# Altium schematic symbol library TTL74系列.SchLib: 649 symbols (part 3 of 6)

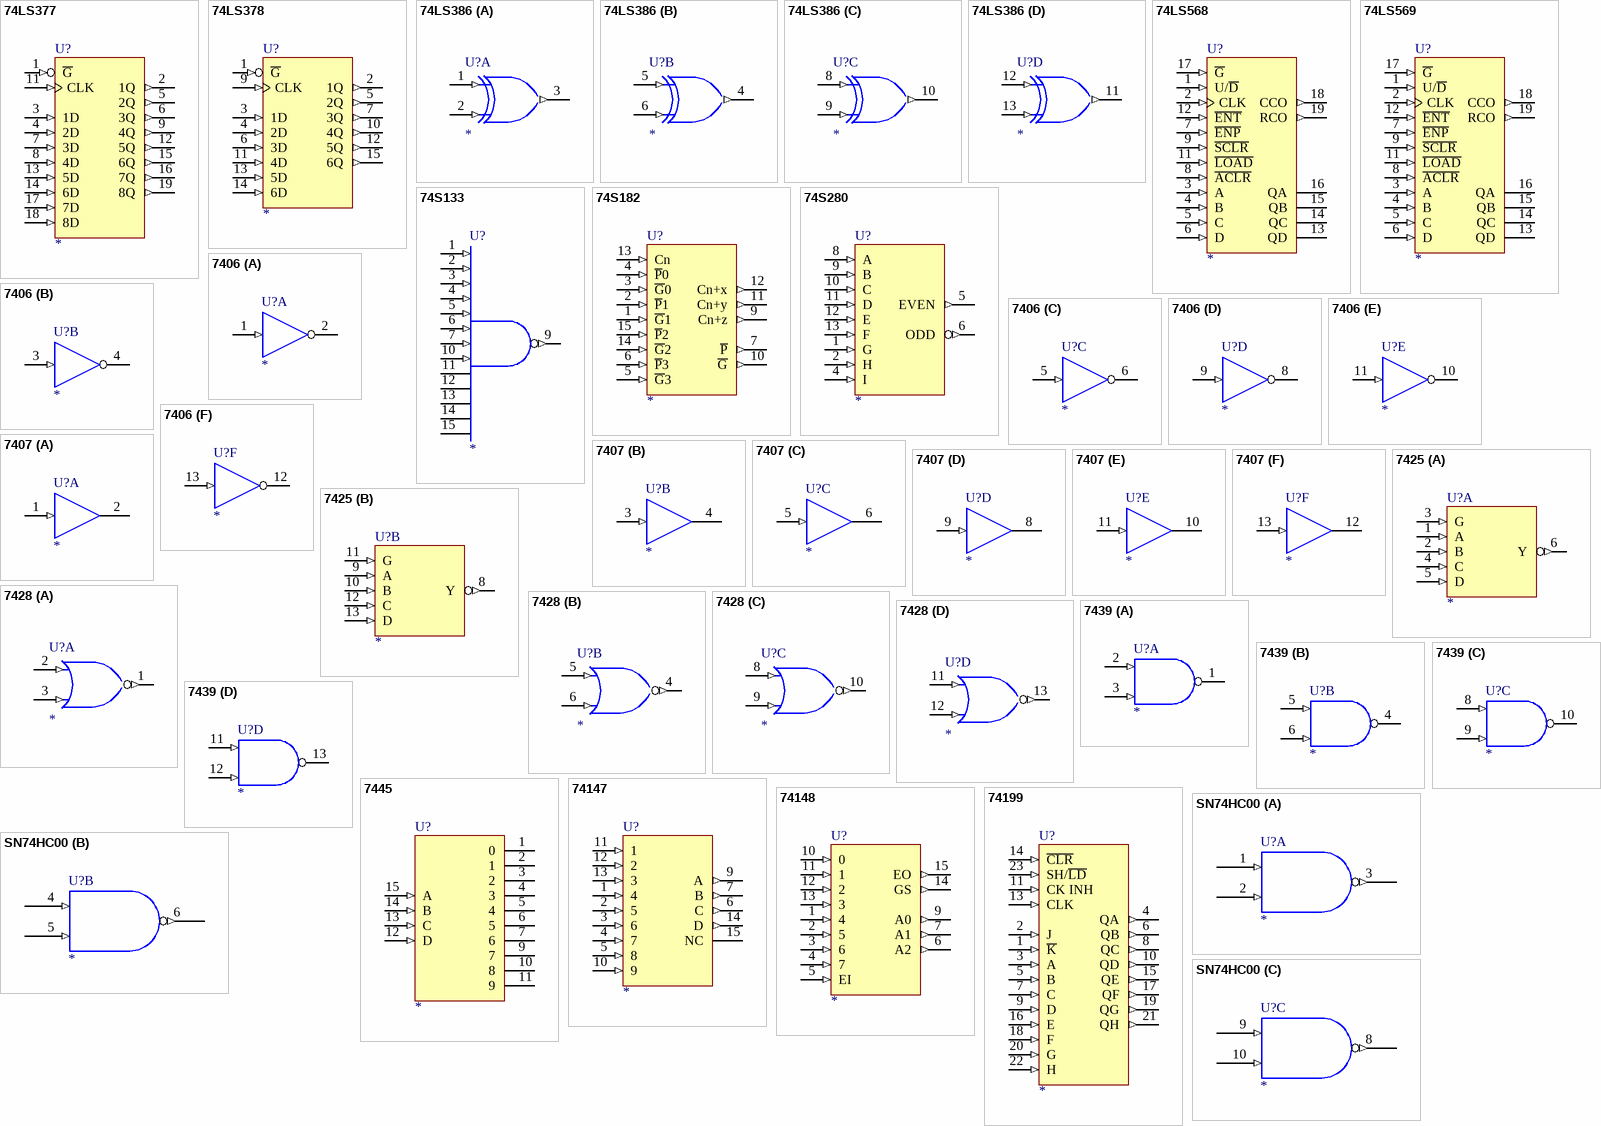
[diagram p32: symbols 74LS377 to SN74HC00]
## 74148
designator U?
8-Line to 3-Line Priority Encoder
footprint DIP-16
simulation model 74148 (SIMCODE)
pins: 1 4 (in), 2 5 (in), 3 6 (in), 4 7 (in), 5 EI (in), 6 A2 (out), 7 A1 (out), 8 GND (power) hidden to GND, 9 A0 (out), 10 0 (in), 11 1 (in), 12 2 (in), 13 3 (in), 14 GS (out), 15 EO (out), 16 VCC (power) hidden to VCC
1 alternate drawing of the same symbol

## 74199
designator U?
8-Bit Shift Register
footprint DIP-24
simulation model 74199 (SIMCODE)
pins: 1 ~{K} (in), 2 J (in), 3 A (in), 4 QA (out), 5 B (in), 6 QB (out), 7 C (in), 8 QC (out), 9 D (in), 10 QD (out), 11 CK INH (in), 12 GND (power) hidden to GND, 13 CLK (in), 14 ~{CLR} (in), 15 QE (out), 16 E (in), 17 QF (out), 18 F (in), 19 QG (out), 20 G (in), 21 QH (out), 22 H (in), 23 SH/~{LD} (in), 24 VCC (power) hidden to VCC
1 alternate drawing of the same symbol


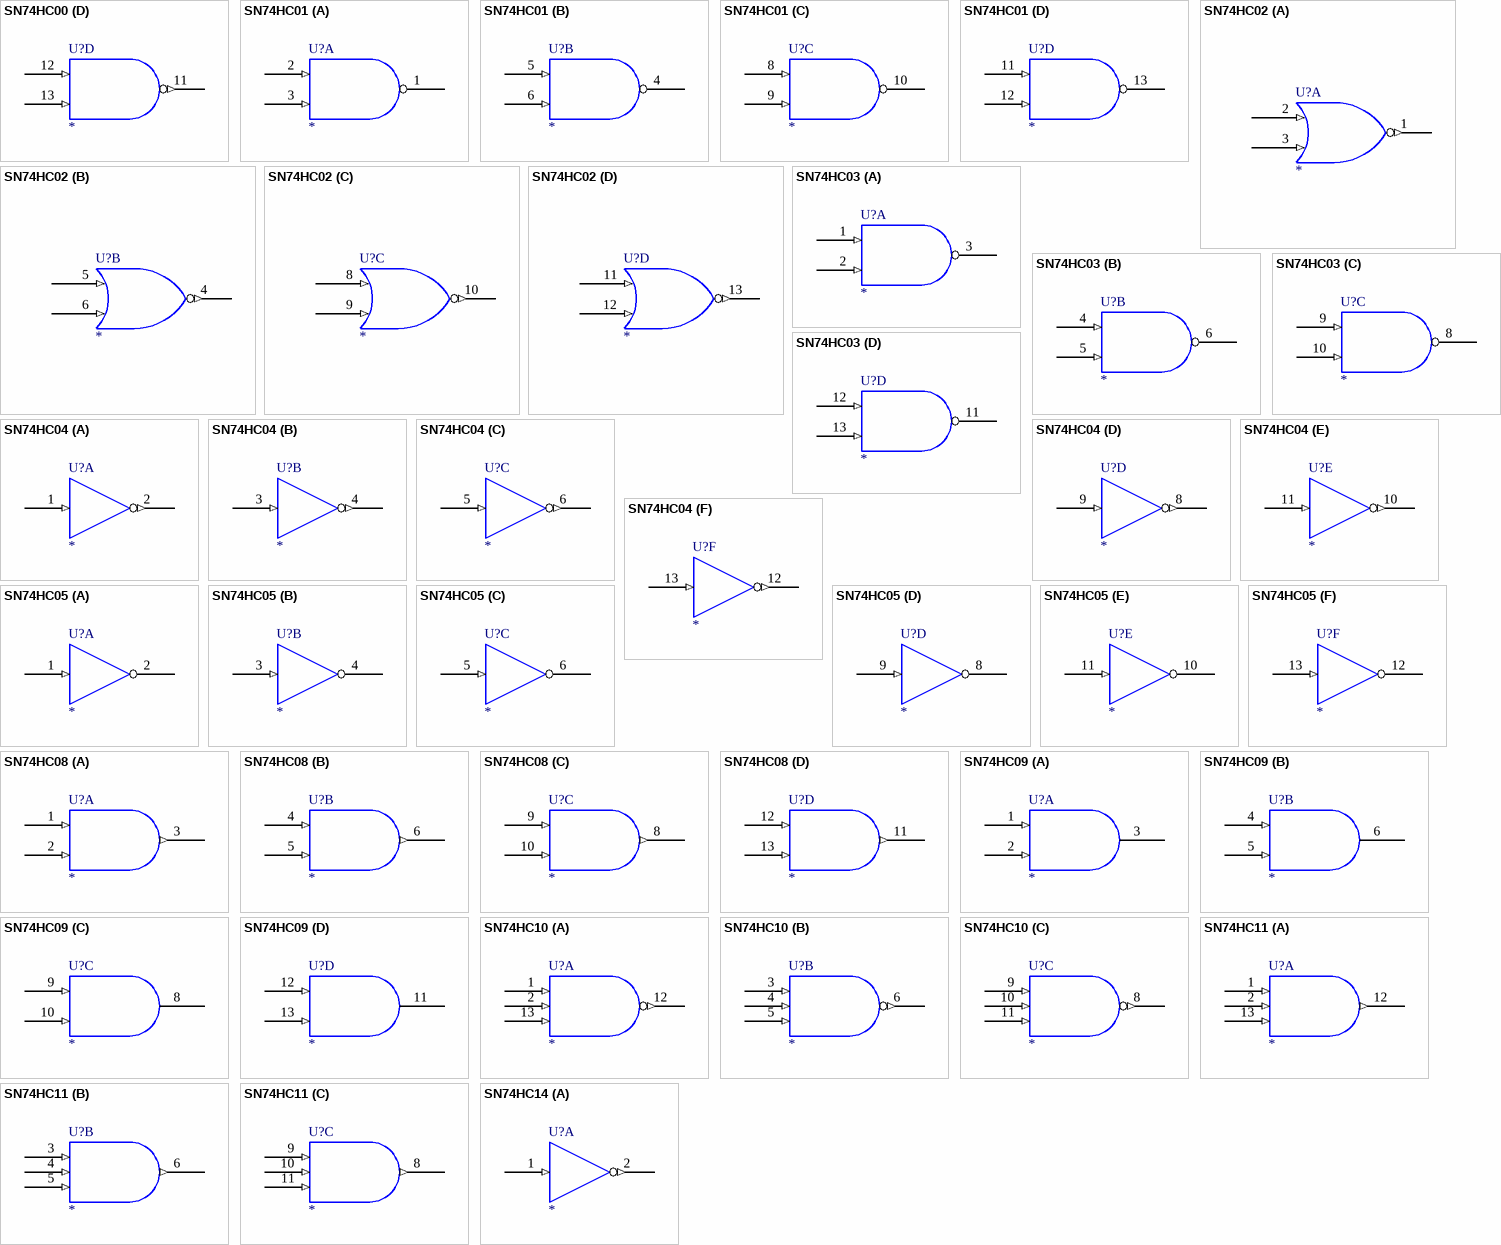
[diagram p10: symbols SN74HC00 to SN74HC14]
## SN74HC00
designator U?
Quad 2-IN Pos Nand G
footprint SO14
footprint DIP-14
part A pins: 1 (in), 2 (in), 3 (out), 7 GND (power) hidden to GND, 14 VCC (power) hidden to VCC
part B pins: 4 (in), 5 (in), 6 (out), 7 GND (power) hidden to GND, 14 VCC (power) hidden to VCC
part C pins: 7 GND (power) hidden to GND, 8 (out), 9 (in), 10 (in), 14 VCC (power) hidden to VCC
part D pins: 7 GND (power) hidden to GND, 11 (out), 12 (in), 13 (in), 14 VCC (power) hidden to VCC
2 alternate drawings of the same symbol

## SN74HC01
designator U?
Quad 2-IN Pos Nand G OCO
footprint SO14
footprint DIP-14
part A pins: 1 (oc), 2 (in), 3 (in), 7 GND (power) hidden to GND, 14 VCC (power) hidden to VCC
part B pins: 4 (oc), 5 (in), 6 (in), 7 GND (power) hidden to GND, 14 VCC (power) hidden to VCC
part C pins: 7 GND (power) hidden to GND, 8 (in), 9 (in), 10 (oc), 14 VCC (power) hidden to VCC
part D pins: 7 GND (power) hidden to GND, 11 (in), 12 (in), 13 (oc), 14 VCC (power) hidden to VCC
2 alternate drawings of the same symbol

## SN74HC02
designator U?
Quad 2-IN Pos Nor G
footprint SO14
footprint DIP-14
part A pins: 1 (out), 2 (in), 3 (in), 7 GND (power) hidden to GND, 14 VCC (power) hidden to VCC
part B pins: 4 (out), 5 (in), 6 (in), 7 GND (power) hidden to GND, 14 VCC (power) hidden to VCC
part C pins: 7 GND (power) hidden to GND, 8 (in), 9 (in), 10 (out), 14 VCC (power) hidden to VCC
part D pins: 7 GND (power) hidden to GND, 11 (in), 12 (in), 13 (out), 14 VCC (power) hidden to VCC
2 alternate drawings of the same symbol

## SN74HC03
designator U?
Quad 2-IN Pos Nand G OCO
footprint SO14
footprint DIP-14
part A pins: 1 (in), 2 (in), 3 (oc), 7 GND (power) hidden to GND, 14 VCC (power) hidden to VCC
part B pins: 4 (in), 5 (in), 6 (oc), 7 GND (power) hidden to GND, 14 VCC (power) hidden to VCC
part C pins: 7 GND (power) hidden to GND, 8 (oc), 9 (in), 10 (in), 14 VCC (power) hidden to VCC
part D pins: 7 GND (power) hidden to GND, 11 (oc), 12 (in), 13 (in), 14 VCC (power) hidden to VCC
2 alternate drawings of the same symbol

## SN74HC04
designator U?
Hex Inverters
footprint SO14
footprint DIP-14
part A pins: 1 (in), 2 (out), 7 GND (power) hidden to GND, 14 VCC (power) hidden to VCC
part B pins: 3 (in), 4 (out), 7 GND (power) hidden to GND, 14 VCC (power) hidden to VCC
part C pins: 5 (in), 6 (out), 7 GND (power) hidden to GND, 14 VCC (power) hidden to VCC
part D pins: 7 GND (power) hidden to GND, 8 (out), 9 (in), 14 VCC (power) hidden to VCC
part E pins: 7 GND (power) hidden to GND, 10 (out), 11 (in), 14 VCC (power) hidden to VCC
part F pins: 7 GND (power) hidden to GND, 12 (out), 13 (in), 14 VCC (power) hidden to VCC
2 alternate drawings of the same symbol

## SN74HC05
designator U?
Hex Inverters OCO
footprint SO14
footprint DIP-14
part A pins: 1 (in), 2 (oc), 7 GND (power) hidden to GND, 14 VCC (power) hidden to VCC
part B pins: 3 (in), 4 (oc), 7 GND (power) hidden to GND, 14 VCC (power) hidden to VCC
part C pins: 5 (in), 6 (oc), 7 GND (power) hidden to GND, 14 VCC (power) hidden to VCC
part D pins: 7 GND (power) hidden to GND, 8 (oc), 9 (in), 14 VCC (power) hidden to VCC
part E pins: 7 GND (power) hidden to GND, 10 (oc), 11 (in), 14 VCC (power) hidden to VCC
part F pins: 7 GND (power) hidden to GND, 12 (oc), 13 (in), 14 VCC (power) hidden to VCC
2 alternate drawings of the same symbol

## SN74HC08
designator U?
Quad 2-IN Pos And G
footprint SO14
footprint DIP-14
part A pins: 1 (in), 2 (in), 3 (out), 7 GND (power) hidden to GND, 14 VCC (power) hidden to VCC
part B pins: 4 (in), 5 (in), 6 (out), 7 GND (power) hidden to GND, 14 VCC (power) hidden to VCC
part C pins: 7 GND (power) hidden to GND, 8 (out), 9 (in), 10 (in), 14 VCC (power) hidden to VCC
part D pins: 7 GND (power) hidden to GND, 11 (out), 12 (in), 13 (in), 14 VCC (power) hidden to VCC
2 alternate drawings of the same symbol

## SN74HC09
designator U?
Quad 2-IN Pos And G OCO
footprint SO14
footprint DIP-14
part A pins: 1 (in), 2 (in), 3 (oc), 7 GND (power) hidden to GND, 14 VCC (power) hidden to VCC
part B pins: 4 (in), 5 (in), 6 (oc), 7 GND (power) hidden to GND, 14 VCC (power) hidden to VCC
part C pins: 7 GND (power) hidden to GND, 8 (oc), 9 (in), 10 (in), 14 VCC (power) hidden to VCC
part D pins: 7 GND (power) hidden to GND, 11 (oc), 12 (in), 13 (in), 14 VCC (power) hidden to VCC
2 alternate drawings of the same symbol

## SN74HC10
designator U?
Triple 3-IN Pos Nand G
footprint SO14
footprint DIP-14
part A pins: 1 (in), 2 (in), 7 GND (power) hidden to GND, 12 (out), 13 (in), 14 VCC (power) hidden to VCC
part B pins: 3 (in), 4 (in), 5 (in), 6 (out), 7 GND (power) hidden to GND, 14 VCC (power) hidden to VCC
part C pins: 7 GND (power) hidden to GND, 8 (out), 9 (in), 10 (in), 11 (in), 14 VCC (power) hidden to VCC
2 alternate drawings of the same symbol

## SN74HC11
designator U?
Triple 3-IN Pos And G
footprint SO14
footprint DIP-14
part A pins: 1 (in), 2 (in), 7 GND (power) hidden to GND, 12 (out), 13 (in), 14 VCC (power) hidden to VCC
part B pins: 3 (in), 4 (in), 5 (in), 6 (out), 7 GND (power) hidden to GND, 14 VCC (power) hidden to VCC
part C pins: 7 GND (power) hidden to GND, 8 (out), 9 (in), 10 (in), 11 (in), 14 VCC (power) hidden to VCC
2 alternate drawings of the same symbol


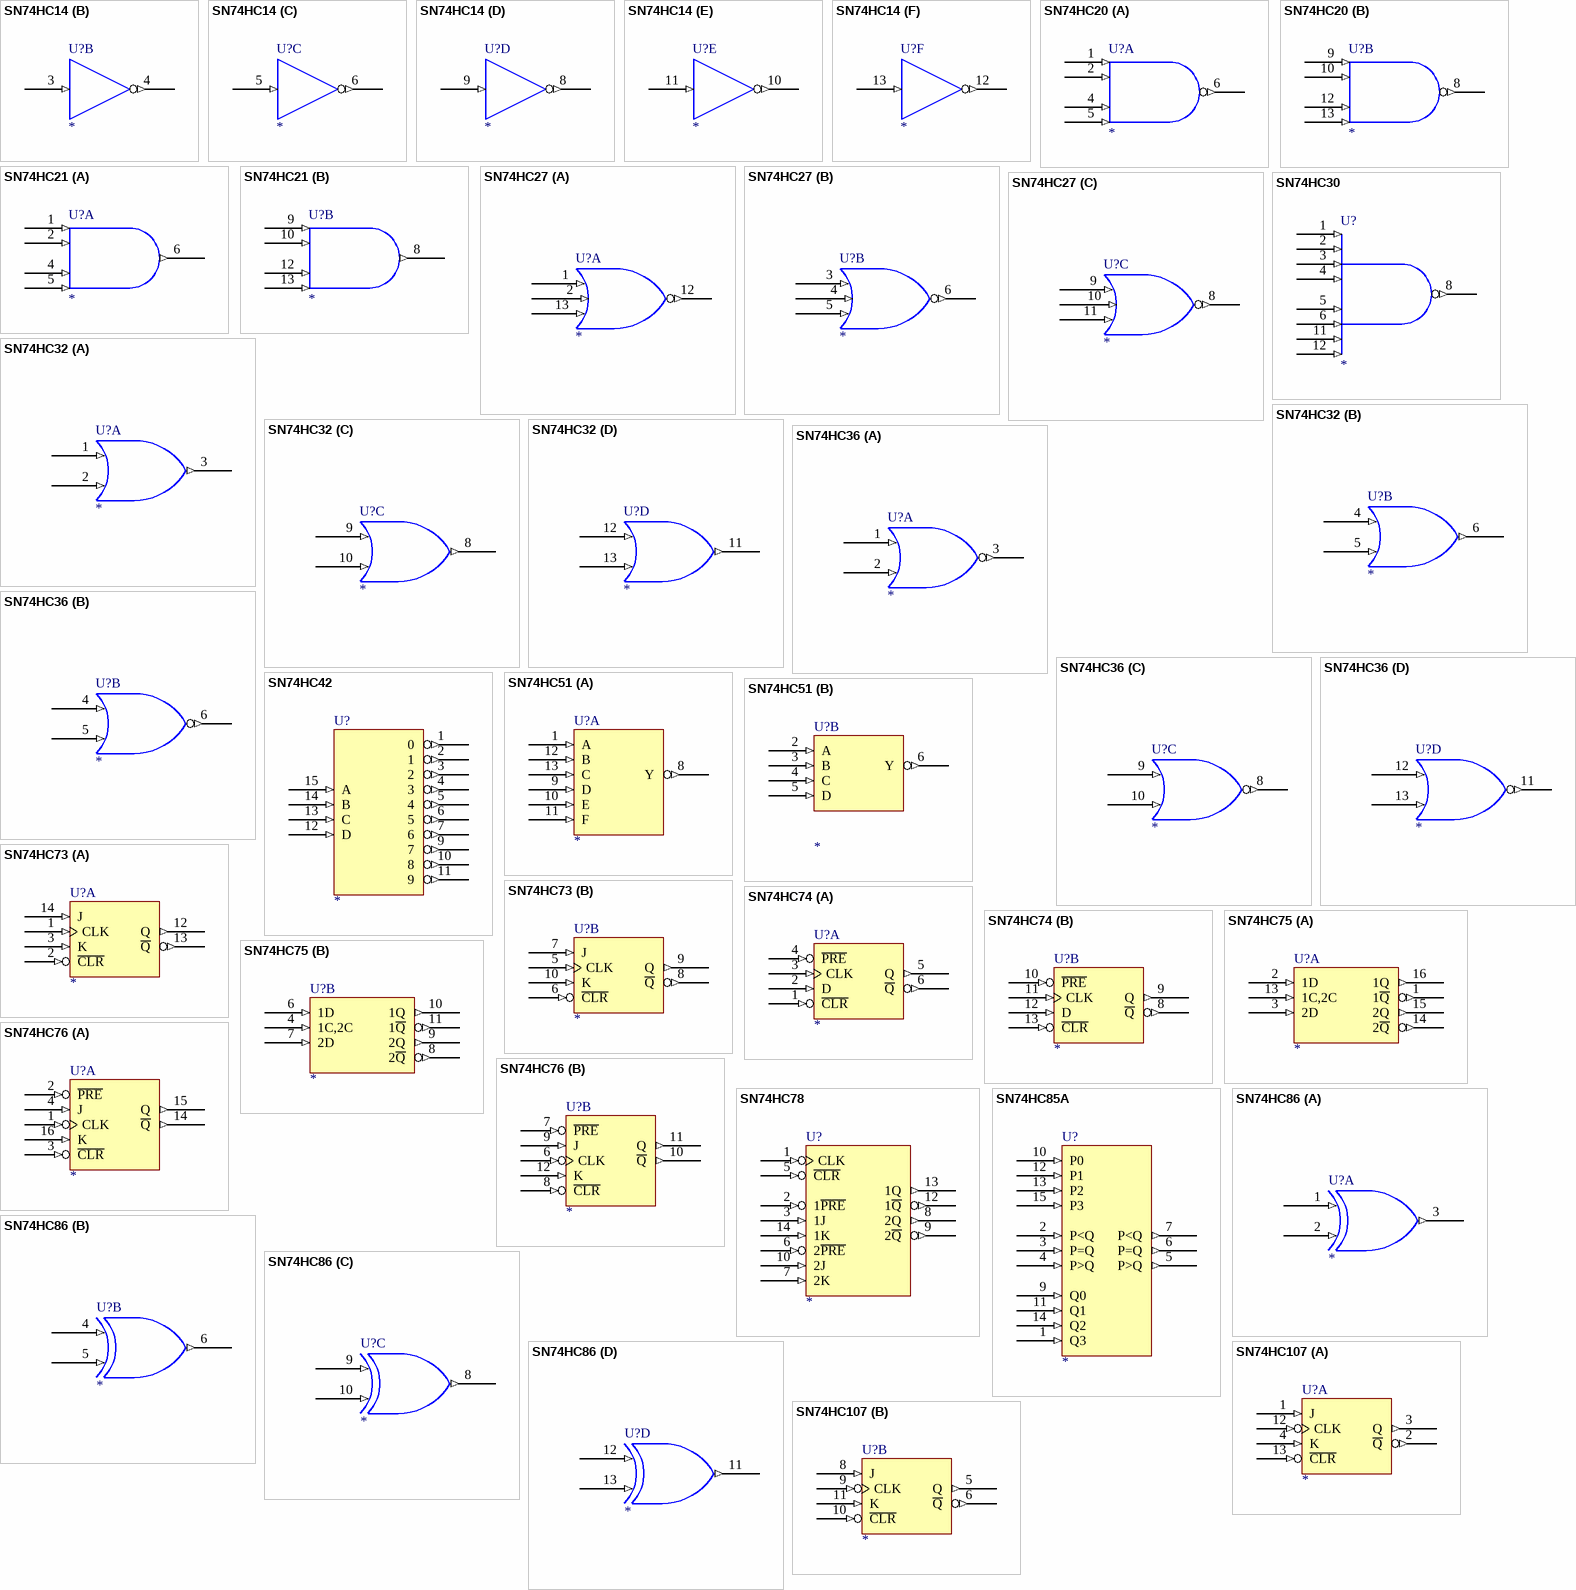
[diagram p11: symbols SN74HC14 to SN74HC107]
## SN74HC14
designator U?
Hex Inverter SCH
footprint SO14
footprint DIP-14
part A pins: 1 (in), 2 (out), 7 GND (power) hidden to GND, 14 VCC (power) hidden to VCC
part B pins: 3 (in), 4 (out), 7 GND (power) hidden to GND, 14 VCC (power) hidden to VCC
part C pins: 5 (in), 6 (out), 7 GND (power) hidden to GND, 14 VCC (power) hidden to VCC
part D pins: 7 GND (power) hidden to GND, 8 (out), 9 (in), 14 VCC (power) hidden to VCC
part E pins: 7 GND (power) hidden to GND, 10 (out), 11 (in), 14 VCC (power) hidden to VCC
part F pins: 7 GND (power) hidden to GND, 12 (out), 13 (in), 14 VCC (power) hidden to VCC
2 alternate drawings of the same symbol

## SN74HC20
designator U?
Dual 4-IN Pos Nand G
footprint SO14
footprint DIP-14
part A pins: 1 (in), 2 (in), 4 (in), 5 (in), 6 (out), 7 GND (power) hidden to GND, 14 VCC (power) hidden to VCC
part B pins: 7 GND (power) hidden to GND, 8 (out), 9 (in), 10 (in), 12 (in), 13 (in), 14 VCC (power) hidden to VCC
2 alternate drawings of the same symbol

## SN74HC21
designator U?
Dual 4-IN Pos And G
footprint SO14
footprint DIP-14
part A pins: 1 (in), 2 (in), 4 (in), 5 (in), 6 (out), 7 GND (power) hidden to GND, 14 VCC (power) hidden to VCC
part B pins: 7 GND (power) hidden to GND, 8 (out), 9 (in), 10 (in), 12 (in), 13 (in), 14 VCC (power) hidden to VCC
2 alternate drawings of the same symbol

## SN74HC27
designator U?
Triple 3-IN Pos Nor G
footprint SO14
footprint DIP-14
part A pins: 1 (in), 2 (in), 7 GND (power) hidden to GND, 12 (out), 13 (in), 14 VCC (power) hidden to VCC
part B pins: 3 (in), 4 (in), 5 (in), 6 (out), 7 GND (power) hidden to GND, 14 VCC (power) hidden to VCC
part C pins: 7 GND (power) hidden to GND, 8 (out), 9 (in), 10 (in), 11 (in), 14 VCC (power) hidden to VCC
2 alternate drawings of the same symbol

## SN74HC30
designator U?
8-IN Nand Pos G
footprint SO14
footprint DIP-14
pins: 1 (in), 2 (in), 3 (in), 4 (in), 5 (in), 6 (in), 7 GND (power) hidden to GND, 8 (out), 11 (in), 12 (in), 14 VCC (power) hidden to VCC
2 alternate drawings of the same symbol

## SN74HC32
designator U?
Quad 2-IN Pos Or G
footprint SO14
footprint DIP-14
part A pins: 1 (in), 2 (in), 3 (out), 7 GND (power) hidden to GND, 14 VCC (power) hidden to VCC
part B pins: 4 (in), 5 (in), 6 (out), 7 GND (power) hidden to GND, 14 VCC (power) hidden to VCC
part C pins: 7 GND (power) hidden to GND, 8 (out), 9 (in), 10 (in), 14 VCC (power) hidden to VCC
part D pins: 7 GND (power) hidden to GND, 11 (out), 12 (in), 13 (in), 14 VCC (power) hidden to VCC
2 alternate drawings of the same symbol

## SN74HC36
designator U?
Quad 2-IN Pos NOR G
footprint SO14
footprint DIP-14
part A pins: 1 (in), 2 (in), 3 (out), 7 GND (power) hidden to GND, 14 VCC (power) hidden to VCC
part B pins: 4 (in), 5 (in), 6 (out), 7 GND (power) hidden to GND, 14 VCC (power) hidden to VCC
part C pins: 7 GND (power) hidden to GND, 8 (out), 9 (in), 10 (in), 14 VCC (power) hidden to VCC
part D pins: 7 GND (power) hidden to GND, 11 (out), 12 (in), 13 (in), 14 VCC (power) hidden to VCC
2 alternate drawings of the same symbol

## SN74HC42
designator U?
4-line BCD to 10-line decimal Dec
footprint SO16
footprint DIP-16
pins: 1 0 (out), 2 1 (out), 3 2 (out), 4 3 (out), 5 4 (out), 6 5 (out), 7 6 (out), 8 GND (power) hidden to GND, 9 7 (out), 10 8 (out), 11 9 (out), 12 D (in), 13 C (in), 14 B (in), 15 A (in), 16 VCC (power) hidden to VCC
1 alternate drawing of the same symbol

## SN74HC51
designator U?
DUAL 2-WIDE 2&3-IN AND-OR-INVERT G
footprint SO14
footprint DIP-14
part A pins: 1 A (in), 7 GND (power) hidden to GND, 8 Y (out), 9 D (in), 10 E (in), 11 F (in), 12 B (in), 13 C (in), 14 VCC (power) hidden to VCC
part B pins: 2 A (in), 3 B (in), 4 C (in), 5 D (in), 6 Y (out), 7 GND (power) hidden to GND, 14 VCC (power) hidden to VCC
1 alternate drawing of the same symbol

## SN74HC73
designator U?
DUAL J-K FF CR
footprint SO14
footprint DIP-14
part A pins: 1 CLK (in), 2 ~{CLR} (in), 3 K (in), 4 GND (power) hidden to GND, 11 VCC (power) hidden to VCC, 12 Q (out), 13 ~{Q} (out), 14 J (in)
part B pins: 4 GND (power) hidden to GND, 5 CLK (in), 6 ~{CLR} (in), 7 J (in), 8 ~{Q} (out), 9 Q (out), 10 K (in), 11 VCC (power) hidden to VCC
1 alternate drawing of the same symbol

## SN74HC74
designator U?
DUAL D PET FF RS CR
footprint SO14
footprint DIP-14
part A pins: 1 ~{CLR} (in), 2 D (in), 3 CLK (in), 4 ~{PRE} (in), 5 Q (out), 6 ~{Q} (out), 7 GND (power) hidden to GND, 14 VCC (power) hidden to VCC
part B pins: 7 GND (power) hidden to GND, 8 ~{Q} (out), 9 Q (out), 10 ~{PRE} (in), 11 CLK (in), 12 D (in), 13 ~{CLR} (in), 14 VCC (power) hidden to VCC
1 alternate drawing of the same symbol

## SN74HC75
designator U?
4-BIT BISTABLE LCH
footprint SO16
footprint DIP-16
part A pins: 1 1~{Q} (out), 2 1D (in), 3 2D (in), 5 VCC (power) hidden to VCC, 12 GND (power) hidden to GND, 13 1C,2C (in), 14 2~{Q} (out), 15 2Q (out), 16 1Q (out)
part B pins: 4 1C,2C (in), 5 VCC (power) hidden to VCC, 6 1D (in), 7 2D (in), 8 2~{Q} (out), 9 2Q (out), 10 1Q (out), 11 1~{Q} (out), 12 GND (power) hidden to GND
1 alternate drawing of the same symbol

## SN74HC76
designator U?
DUAL J-K NET FF RS CR
footprint SO16
footprint DIP-16
part A pins: 1 CLK (in), 2 ~{PRE} (in), 3 ~{CLR} (in), 4 J (in), 5 VCC (power) hidden to VCC, 13 GND (power) hidden to GND, 14 ~{Q} (out), 15 Q (out), 16 K (in)
part B pins: 5 VCC (power) hidden to VCC, 6 CLK (in), 7 ~{PRE} (in), 8 ~{CLR} (in), 9 J (in), 10 ~{Q} (out), 11 Q (out), 12 K (in), 13 GND (power) hidden to GND
1 alternate drawing of the same symbol

## SN74HC78
designator U?
DUAL J-K FF RS COM CLK COM CR
footprint SO14
footprint DIP-14
pins: 1 CLK (in), 2 1~{PRE} (in), 3 1J (in), 4 VCC (power) hidden to VCC, 5 ~{CLR} (in), 6 2~{PRE} (in), 7 2K (in), 8 2Q (out), 9 2~{Q} (out), 10 2J (in), 11 GND (power) hidden to GND, 12 1~{Q} (out), 13 1Q (out), 14 1K (in)
1 alternate drawing of the same symbol

## SN74HC85A
designator U?
4-BIT MAGNITUDE COMP
footprint DIP-16
pins: 1 Q3 (in), 2 P<Q (in), 3 P=Q (in), 4 P>Q (in), 5 P>Q (out), 6 P=Q (out), 7 P<Q (out), 8 GND (power) hidden to GND, 9 Q0 (in), 10 P0 (in), 11 Q1 (in), 12 P1 (in), 13 P2 (in), 14 Q2 (in), 15 P3 (in), 16 VCC (power) hidden to VCC
1 alternate drawing of the same symbol

## SN74HC86
designator U?
QUAD 2-IN XOR  G
footprint SO14
footprint DIP-14
part A pins: 1 (in), 2 (in), 3 (out), 7 GND (power) hidden to GND, 14 VCC (power) hidden to VCC
part B pins: 4 (in), 5 (in), 6 (out), 7 GND (power) hidden to GND, 14 VCC (power) hidden to VCC
part C pins: 7 GND (power) hidden to GND, 8 (out), 9 (in), 10 (in), 14 VCC (power) hidden to VCC
part D pins: 7 GND (power) hidden to GND, 11 (out), 12 (in), 13 (in), 14 VCC (power) hidden to VCC
1 alternate drawing of the same symbol

## SN74HC107
designator U?
DUAL J-K FF CR
footprint SO14
footprint DIP-14
part A pins: 1 J (in), 2 ~{Q} (out), 3 Q (out), 4 K (in), 7 GND (power) hidden to GND, 12 CLK (in), 13 ~{CLR} (in), 14 VCC (power) hidden to VCC
part B pins: 5 Q (out), 6 ~{Q} (out), 7 GND (power) hidden to GND, 8 J (in), 9 CLK (in), 10 ~{CLR} (in), 11 K (in), 14 VCC (power) hidden to VCC
1 alternate drawing of the same symbol


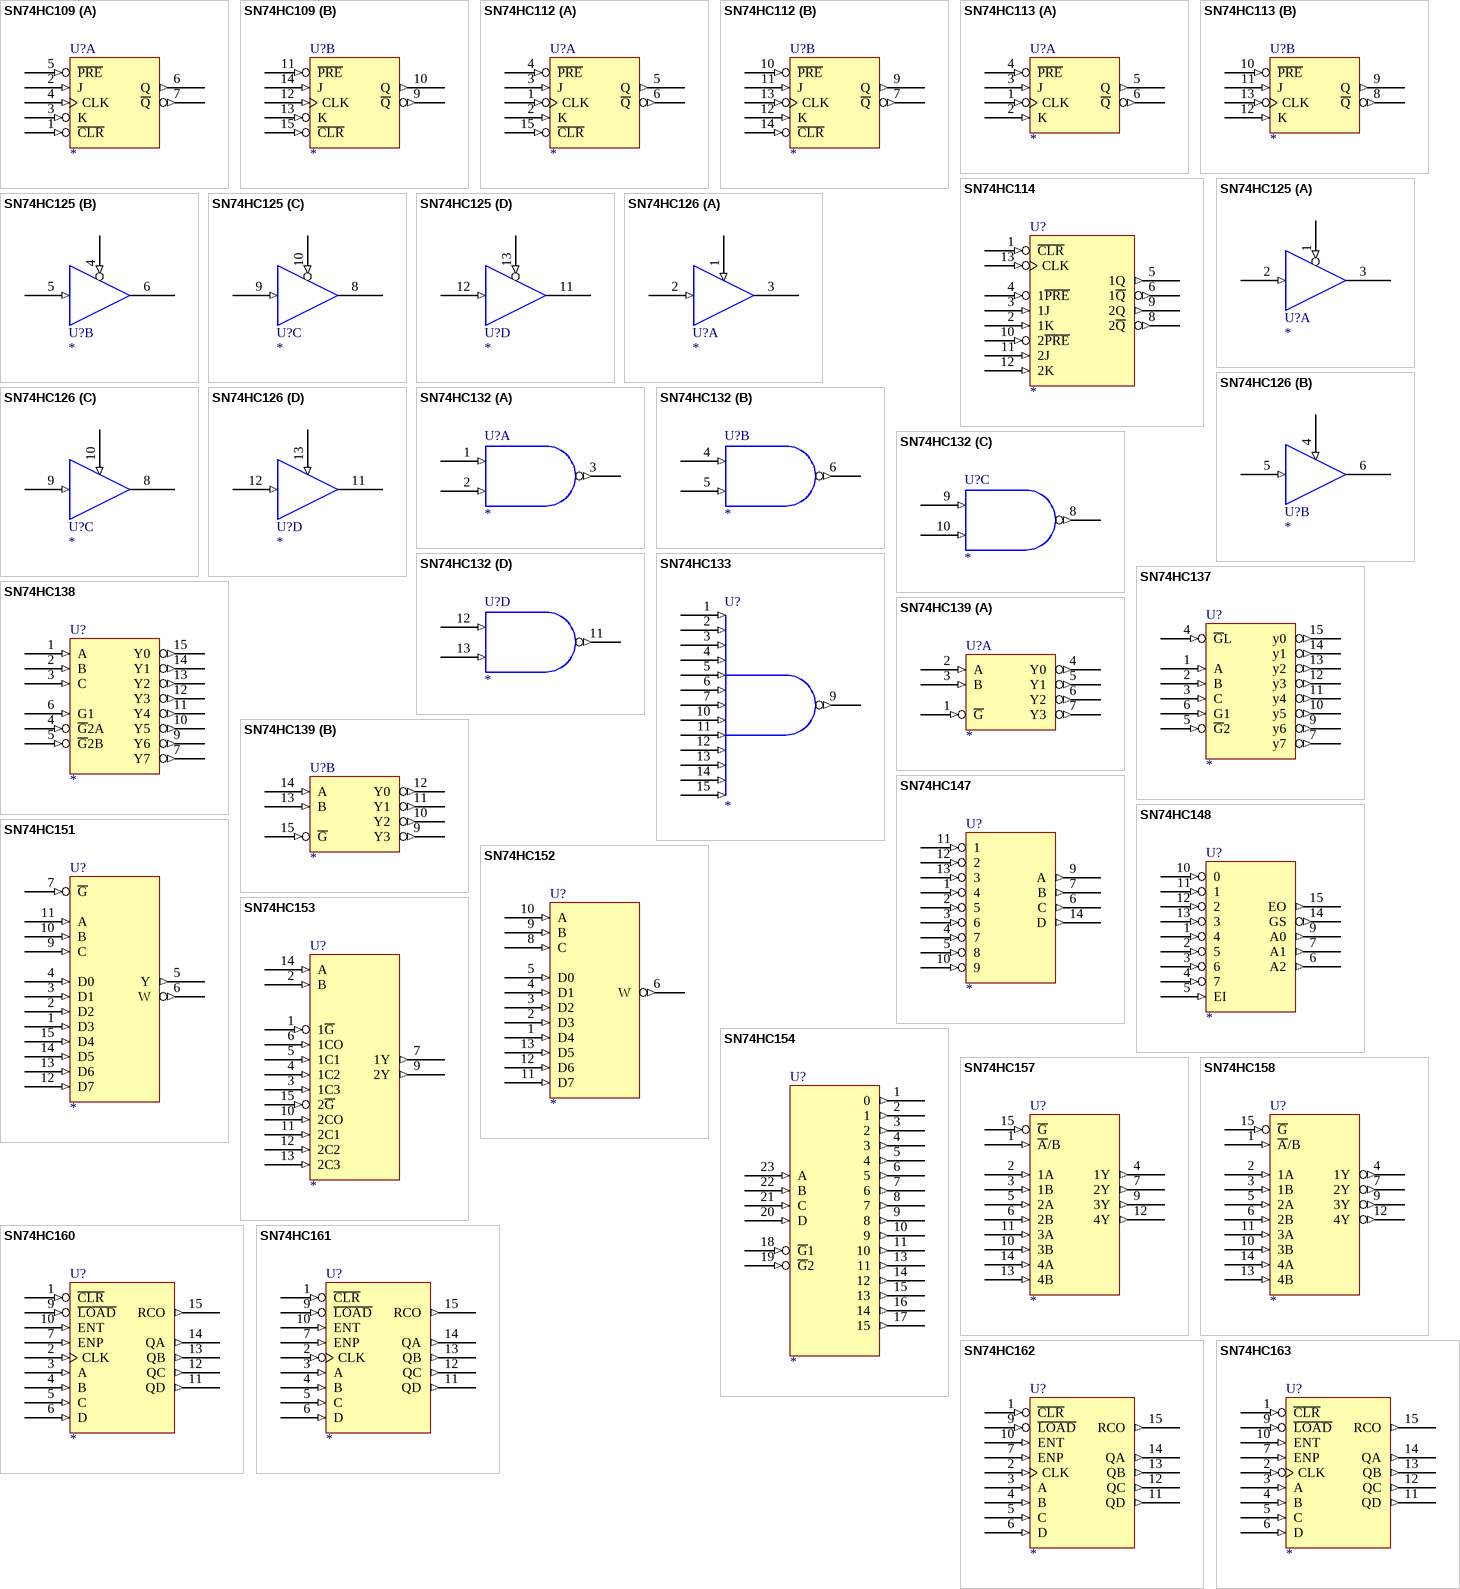
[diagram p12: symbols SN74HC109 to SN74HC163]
## SN74HC109
designator U?
DUAL J-K PET FF RS CR
footprint SO16
footprint DIP-16
part A pins: 1 ~{CLR} (in), 2 J (in), 3 K (in), 4 CLK (in), 5 ~{PRE} (in), 6 Q (out), 7 ~{Q} (out), 8 GND (power) hidden to GND, 16 VCC (power) hidden to VCC
part B pins: 8 GND (power) hidden to GND, 9 ~{Q} (out), 10 Q (out), 11 ~{PRE} (in), 12 CLK (in), 13 K (in), 14 J (in), 15 ~{CLR} (in), 16 VCC (power) hidden to VCC
1 alternate drawing of the same symbol

## SN74HC112
designator U?
DUAL J-K NET FF RS CR
footprint SO16
footprint DIP-16
part A pins: 1 CLK (in), 2 K (in), 3 J (in), 4 ~{PRE} (in), 5 Q (out), 6 ~{Q} (out), 8 GND (power) hidden to GND, 15 ~{CLR} (in), 16 VCC (power) hidden to VCC
part B pins: 7 ~{Q} (out), 8 GND (power) hidden to GND, 9 Q (out), 10 ~{PRE} (in), 11 J (in), 12 K (in), 13 CLK (in), 14 ~{CLR} (in), 16 VCC (power) hidden to VCC
1 alternate drawing of the same symbol

## SN74HC113
designator U?
DUAL J-K NET FF RS
footprint SO14
footprint DIP-14
part A pins: 1 CLK (in), 2 K (in), 3 J (in), 4 ~{PRE} (in), 5 Q (out), 6 ~{Q} (out), 7 GND (power) hidden to GND, 14 VCC (power) hidden to VCC
part B pins: 7 GND (power) hidden to GND, 8 ~{Q} (out), 9 Q (out), 10 ~{PRE} (in), 11 J (in), 12 K (in), 13 CLK (in), 14 VCC (power) hidden to VCC
1 alternate drawing of the same symbol

## SN74HC114
designator U?
DUAL J-K NET FF RS COM CR COM CLK
footprint SO14
footprint DIP-14
pins: 1 ~{CLR} (in), 2 1K (in), 3 1J (in), 4 1~{PRE} (in), 5 1Q (out), 6 1~{Q} (out), 7 GND (power) hidden to GND, 8 2~{Q} (out), 9 2Q (out), 10 2~{PRE} (in), 11 2J (in), 12 2K (in), 13 CLK (in), 14 VCC (power) hidden to VCC
1 alternate drawing of the same symbol

## SN74HC125
designator U?
QUAD BUS BUF 3SO
footprint DIP-14
part A pins: 1 (in), 2 (in), 3 (hiz), 7 GND (power) hidden to GND, 14 VCC (power) hidden to VCC
part B pins: 4 (in), 5 (in), 6 (hiz), 7 GND (power) hidden to GND, 14 VCC (power) hidden to VCC
part C pins: 7 GND (power) hidden to GND, 8 (hiz), 9 (in), 10 (in), 14 VCC (power) hidden to VCC
part D pins: 7 GND (power) hidden to GND, 11 (hiz), 12 (in), 13 (in), 14 VCC (power) hidden to VCC
2 alternate drawings of the same symbol

## SN74HC126
designator U?
QUAD BUS BUF 3SO
footprint DIP-14
part A pins: 1 (in), 2 (in), 3 (hiz), 7 GND (power) hidden to GND, 14 VCC (power) hidden to VCC
part B pins: 4 (in), 5 (in), 6 (hiz), 7 GND (power) hidden to GND, 14 VCC (power) hidden to VCC
part C pins: 7 GND (power) hidden to GND, 8 (hiz), 9 (in), 10 (in), 14 VCC (power) hidden to VCC
part D pins: 7 GND (power) hidden to GND, 11 (hiz), 12 (in), 13 (in), 14 VCC (power) hidden to VCC
2 alternate drawings of the same symbol

## SN74HC132
designator U?
QUAD 2-IN POS NAND SCH
footprint SO14
footprint DIP-14
part A pins: 1 (in), 2 (in), 3 (out), 7 GND (power) hidden to GND, 14 VCC (power) hidden to VCC
part B pins: 4 (in), 5 (in), 6 (out), 7 GND (power) hidden to GND, 14 VCC (power) hidden to VCC
part C pins: 7 GND (power) hidden to GND, 8 (out), 9 (in), 10 (in), 14 VCC (power) hidden to VCC
part D pins: 7 GND (power) hidden to GND, 11 (out), 12 (in), 13 (in), 14 VCC (power) hidden to VCC
2 alternate drawings of the same symbol

## SN74HC133
designator U?
13-IN POS Nand G
footprint SO16
footprint DIP-16
pins: 1 (in), 2 (in), 3 (in), 4 (in), 5 (in), 6 (in), 7 (in), 8 GND (power) hidden to GND, 9 (out), 10 (in), 11 (in), 12 (in), 13 (in), 14 (in), 15 (in), 16 VCC (power) hidden to VCC
2 alternate drawings of the same symbol

## SN74HC137
designator U?
3-8LINE DEC/DEMUL ADDRESS LCH
footprint SO16
footprint DIP-16
pins: 1 A (in), 2 B (in), 3 C (in), 4 ~{G}L (in), 5 ~{G}2 (in), 6 G1 (in), 7 y7 (out), 8 GND (power) hidden to GND, 9 y6 (out), 10 y5 (out), 11 y4 (out), 12 y3 (out), 13 y2 (out), 14 y1 (out), 15 y0 (out), 16 VCC (power) hidden to VCC
1 alternate drawing of the same symbol

## SN74HC138
designator U?
3-8LINE DEC/DEMUL
footprint SO16
footprint DIP-16
pins: 1 A (in), 2 B (in), 3 C (in), 4 ~{G}2A (in), 5 ~{G}2B (in), 6 G1 (in), 7 Y7 (out), 8 GND (power) hidden to GND, 9 Y6 (out), 10 Y5 (out), 11 Y4 (out), 12 Y3 (out), 13 Y2 (out), 14 Y1 (out), 15 Y0 (out), 16 VCC (power) hidden to VCC
1 alternate drawing of the same symbol

## SN74HC139
designator U?
DUAL 2-4LINE DEC/DEMULT
footprint SO16W
footprint DIP-16
part A pins: 1 ~{G} (in), 2 A (in), 3 B (in), 4 Y0 (out), 5 Y1 (out), 6 Y2 (out), 7 Y3 (out), 8 GND (power) hidden to GND, 16 VCC (power) hidden to VCC
part B pins: 8 GND (power) hidden to GND, 9 Y3 (out), 10 Y2 (out), 11 Y1 (out), 12 Y0 (out), 13 B (in), 14 A (in), 15 ~{G} (in), 16 VCC (power) hidden to VCC
1 alternate drawing of the same symbol

## SN74HC147
designator U?
10-4 LINE PRIORITY ENC
footprint DIP-16
pins: 1 4 (in), 2 5 (in), 3 6 (in), 4 7 (in), 5 8 (in), 6 C (out), 7 B (out), 8 GND (power) hidden to GND, 9 A (out), 10 9 (in), 11 1 (in), 12 2 (in), 13 3 (in), 14 D (out), 16 VCC (power) hidden to VCC
1 alternate drawing of the same symbol

## SN74HC148
designator U?
8-3 LINE PRIORITY ENC
footprint SO16W
footprint DIP-16
pins: 1 4 (in), 2 5 (in), 3 6 (in), 4 7 (in), 5 EI (in), 6 A2 (out), 7 A1 (out), 8 GND (power) hidden to GND, 9 A0 (out), 10 0 (in), 11 1 (in), 12 2 (in), 13 3 (in), 14 GS (out), 15 EO (out), 16 VCC (power) hidden to VCC
1 alternate drawing of the same symbol

## SN74HC151
designator U?
DATA SELEC/MUX
footprint SO16
footprint DIP-16
pins: 1 D3 (in), 2 D2 (in), 3 D1 (in), 4 D0 (in), 5 Y (out), 6 W (out), 7 ~{G} (in), 8 GND (power) hidden to GND, 9 C (in), 10 B (in), 11 A (in), 12 D7 (in), 13 D6 (in), 14 D5 (in), 15 D4 (in), 16 VCC (power) hidden to VCC
1 alternate drawing of the same symbol

## SN74HC152
designator U?
8 TO 1-LINE DATA SELEC/MUX
footprint SO14
footprint DIP-14
pins: 1 D4 (in), 2 D3 (in), 3 D2 (in), 4 D1 (in), 5 D0 (in), 6 W (out), 7 GND (power) hidden to GND, 8 C (in), 9 B (in), 10 A (in), 11 D7 (in), 12 D6 (in), 13 D5 (in), 14 VCC (power) hidden to VCC
1 alternate drawing of the same symbol

## SN74HC153
designator U?
DUAL 4-1 LINE DATA SELEC/MUX
footprint SO16
footprint SO16W
footprint DIP-16
pins: 1 1~{G} (in), 2 B (in), 3 1C3 (in), 4 1C2 (in), 5 1C1 (in), 6 1CO (in), 7 1Y (out), 8 GND (power) hidden to GND, 9 2Y (out), 10 2CO (in), 11 2C1 (in), 12 2C2 (in), 13 2C3 (in), 14 A (in), 15 2~{G} (in), 16 VCC (power) hidden to VCC
1 alternate drawing of the same symbol

## SN74HC154
designator U?
4-16LINE DEC DEMUL
footprint SO24W
footprint DIP-24
pins: 1 0 (out), 2 1 (out), 3 2 (out), 4 3 (out), 5 4 (out), 6 5 (out), 7 6 (out), 8 7 (out), 9 8 (out), 10 9 (out), 11 10 (out), 12 GND (power) hidden to GND, 13 11 (out), 14 12 (out), 15 13 (out), 16 14 (out), 17 15 (out), 18 ~{G}1 (in), 19 ~{G}2 (in), 20 D (in), 21 C (in), 22 B (in), 23 A (in), 24 VCC (power) hidden to VCC
1 alternate drawing of the same symbol

## SN74HC157
designator U?
QUAD 2-1LINE DATA SELEC/MUX
footprint SO16
footprint DIP-16
pins: 1 ~{A}/B (in), 2 1A (in), 3 1B (in), 4 1Y (out), 5 2A (in), 6 2B (in), 7 2Y (out), 8 GND (power) hidden to GND, 9 3Y (out), 10 3B (in), 11 3A (in), 12 4Y (out), 13 4B (in), 14 4A (in), 15 ~{G} (in), 16 VCC (power) hidden to VCC
1 alternate drawing of the same symbol

## SN74HC158
designator U?
QUAD 2-1LINE DATA SELEC/MUX
footprint SO16
footprint DIP-16
pins: 1 ~{A}/B (in), 2 1A (in), 3 1B (in), 4 1Y (out), 5 2A (in), 6 2B (in), 7 2Y (out), 8 GND (power) hidden to GND, 9 3Y (out), 10 3B (in), 11 3A (in), 12 4Y (out), 13 4B (in), 14 4A (in), 15 ~{G} (in), 16 VCC (power) hidden to VCC
1 alternate drawing of the same symbol

## SN74HC160
designator U?
SYN 4-BIT CNT
footprint SO16
footprint DIP-16
pins: 1 ~{CLR} (in), 2 CLK (in), 3 A (in), 4 B (in), 5 C (in), 6 D (in), 7 ENP (in), 8 GND (power) hidden to GND, 9 ~{LOAD} (in), 10 ENT (in), 11 QD (out), 12 QC (out), 13 QB (out), 14 QA (out), 15 RCO (out), 16 VCC (power) hidden to VCC
1 alternate drawing of the same symbol

## SN74HC161
designator U?
SYN 4-BIT CNT
footprint SO16
footprint DIP-16
pins: 1 ~{CLR} (in), 2 CLK (in), 3 A (in), 4 B (in), 5 C (in), 6 D (in), 7 ENP (in), 8 GND (power) hidden to GND, 9 ~{LOAD} (in), 10 ENT (in), 11 QD (out), 12 QC (out), 13 QB (out), 14 QA (out), 15 RCO (out), 16 VCC (power) hidden to VCC
1 alternate drawing of the same symbol

## SN74HC162
designator U?
SYN 4-BIT CNT
footprint SO16
footprint DIP-16
pins: 1 ~{CLR} (in), 2 CLK (in), 3 A (in), 4 B (in), 5 C (in), 6 D (in), 7 ENP (in), 8 GND (power) hidden to GND, 9 ~{LOAD} (in), 10 ENT (in), 11 QD (out), 12 QC (out), 13 QB (out), 14 QA (out), 15 RCO (out), 16 VCC (power) hidden to VCC
1 alternate drawing of the same symbol

## SN74HC163
designator U?
SYN 4-BIT CNT
footprint SO16
footprint DIP-16
pins: 1 ~{CLR} (in), 2 CLK (in), 3 A (in), 4 B (in), 5 C (in), 6 D (in), 7 ENP (in), 8 GND (power) hidden to GND, 9 ~{LOAD} (in), 10 ENT (in), 11 QD (out), 12 QC (out), 13 QB (out), 14 QA (out), 15 RCO (out), 16 VCC (power) hidden to VCC
1 alternate drawing of the same symbol


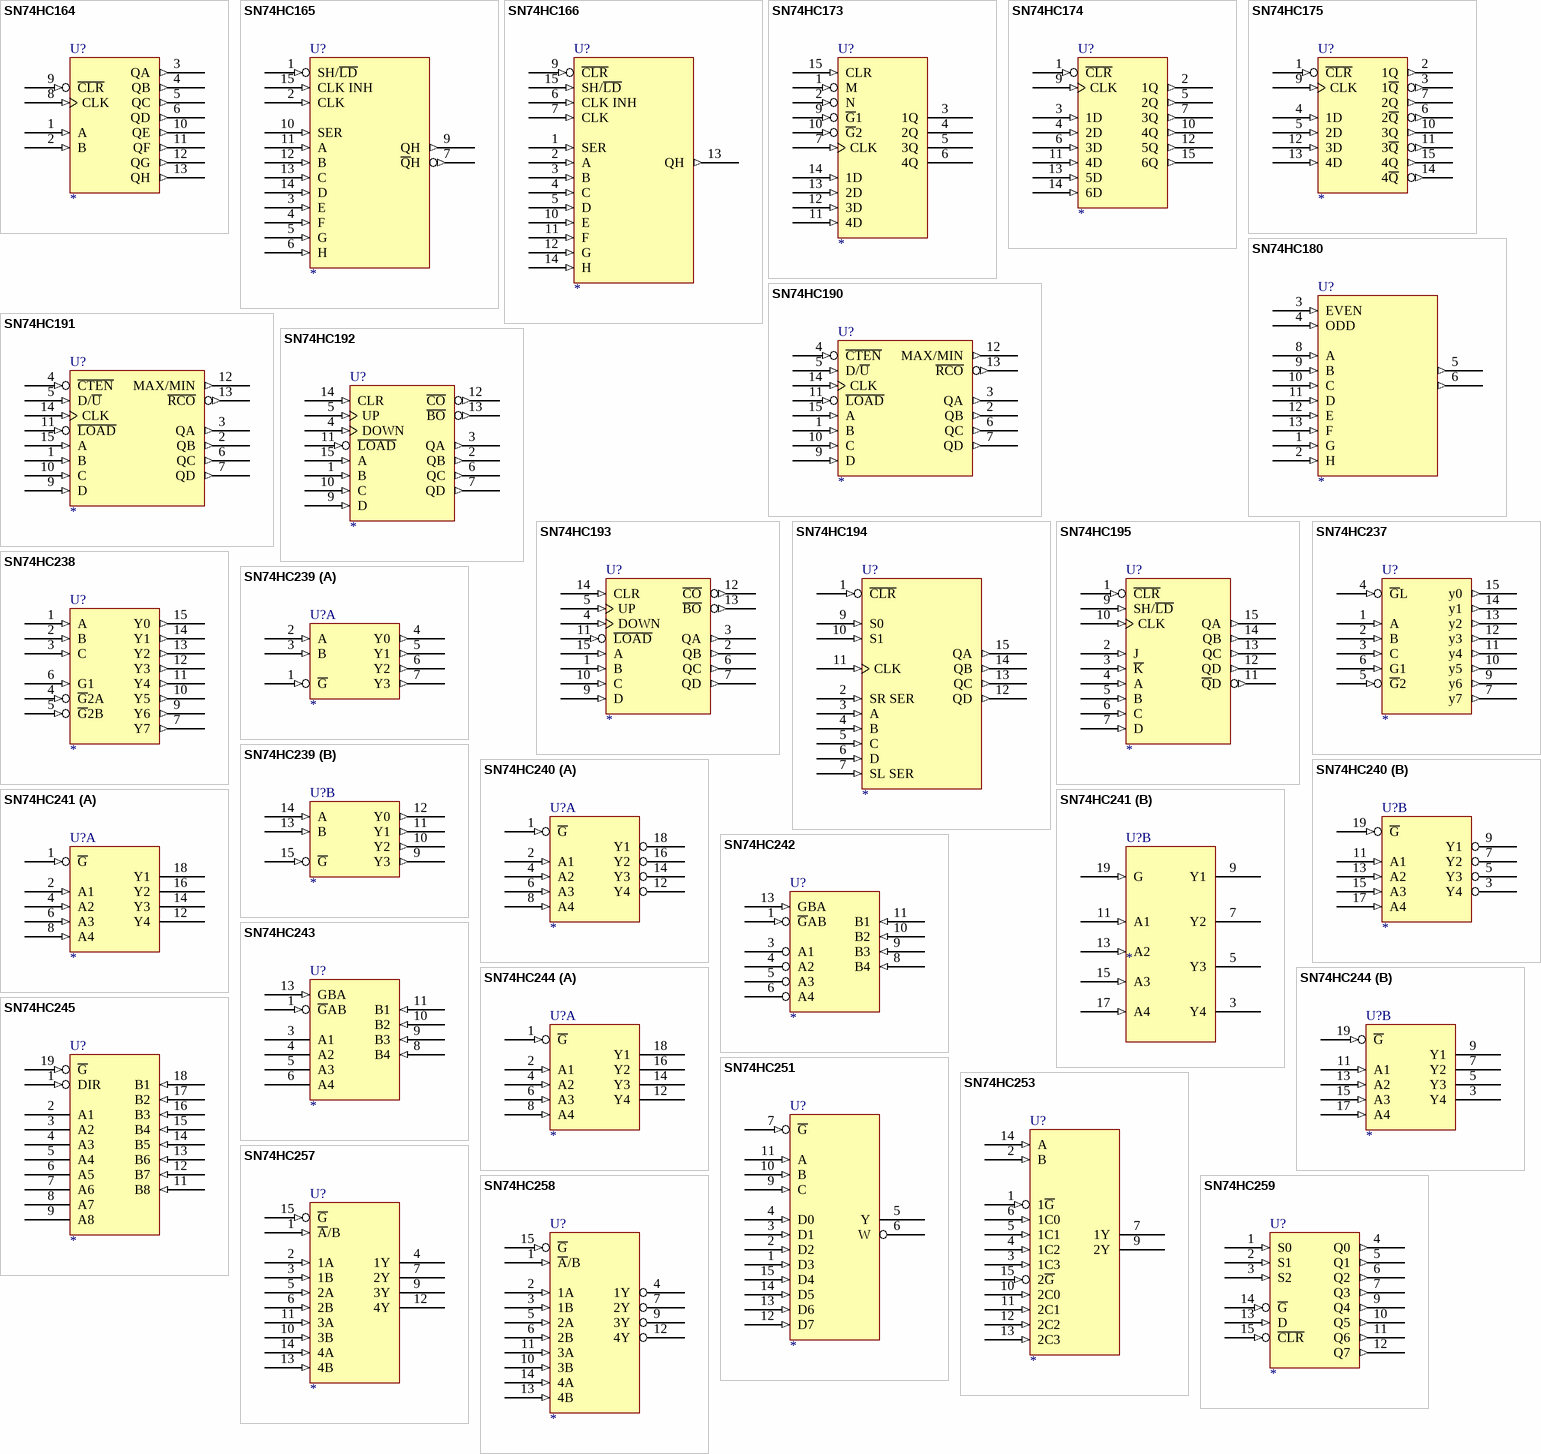
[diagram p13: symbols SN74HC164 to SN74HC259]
## SN74HC164
designator U?
8-BIT PALL SERI SFT REG
footprint DIP-14
pins: 1 A (in), 2 B (in), 3 QA (out), 4 QB (out), 5 QC (out), 6 QD (out), 7 GND (power) hidden to GND, 8 CLK (in), 9 ~{CLR} (in), 10 QE (out), 11 QF (out), 12 QG (out), 13 QH (out), 14 VCC (power) hidden to VCC
1 alternate drawing of the same symbol

## SN74HC165
designator U?
PALL LOAD 8-BIT SFT REG
footprint SO16
footprint DIP-16
pins: 1 SH/~{LD} (in), 2 CLK (in), 3 E (in), 4 F (in), 5 G (in), 6 H (in), 7 ~{Q}H (out), 8 GND (power) hidden to GND, 9 QH (out), 10 SER (in), 11 A (in), 12 B (in), 13 C (in), 14 D (in), 15 CLK INH (in), 16 VCC (power) hidden to VCC
1 alternate drawing of the same symbol

## SN74HC166
designator U?
PALL LOAD 8-BIT SFT REG
footprint SO16
footprint DIP-16
pins: 1 SER (in), 2 A (in), 3 B (in), 4 C (in), 5 D (in), 6 CLK INH (in), 7 CLK (in), 8 GND (power) hidden to GND, 9 ~{CLR} (in), 10 E (in), 11 F (in), 12 G (in), 13 QH (out), 14 H (in), 15 SH/~{LD} (in), 16 VCC (power) hidden to VCC
1 alternate drawing of the same symbol

## SN74HC173
designator U?
4-BIT D-TYPE REG 3SO
footprint SO16
footprint DIP-16
pins: 1 M (in), 2 N (in), 3 1Q (hiz), 4 2Q (hiz), 5 3Q (hiz), 6 4Q (hiz), 7 CLK (in), 8 GND (power) hidden to GND, 9 ~{G}1 (in), 10 ~{G}2 (in), 11 4D (in), 12 3D (in), 13 2D (in), 14 1D (in), 15 CLR (in), 16 VCC (power) hidden to VCC
1 alternate drawing of the same symbol

## SN74HC174
designator U?
HEX D-TYPE FF CR
footprint SO16
footprint DIP-16
pins: 1 ~{CLR} (in), 2 1Q (out), 3 1D (in), 4 2D (in), 5 2Q (out), 6 3D (in), 7 3Q (out), 8 GND (power) hidden to GND, 9 CLK (in), 10 4Q (out), 11 4D (in), 12 5Q (out), 13 5D (in), 14 6D (in), 15 6Q (out), 16 VCC (power) hidden to VCC
1 alternate drawing of the same symbol

## SN74HC175
designator U?
QUAD D-TYPE FF CR
footprint SO16
footprint DIP-16
pins: 1 ~{CLR} (in), 2 1Q (out), 3 1~{Q} (out), 4 1D (in), 5 2D (in), 6 2~{Q} (out), 7 2Q (out), 8 GND (power) hidden to GND, 9 CLK (in), 10 3Q (out), 11 3~{Q} (out), 12 3D (in), 13 4D (in), 14 4~{Q} (out), 15 4Q (out), 16 VCC (power) hidden to VCC
1 alternate drawing of the same symbol

## SN74HC180
designator U?
9-BIT PARITY GNR/CHKR
footprint SO14
footprint DIP-14
pins: 1 G (in), 2 H (in), 3 EVEN (in), 4 ODD (in), 5 (out), 6 (out), 7 GND (power) hidden to GND, 8 A (in), 9 B (in), 10 C (in), 11 D (in), 12 E (in), 13 F (in), 14 VCC (power) hidden to VCC
1 alternate drawing of the same symbol

## SN74HC190
designator U?
SYN UP/DOWN CNT DOWN/UP MODE CONTTOL
footprint SO16
footprint DIP-16
pins: 1 B (in), 2 QB (out), 3 QA (out), 4 ~{CTEN} (in), 5 D/~{U} (in), 6 QC (out), 7 QD (out), 8 GND (power) hidden to GND, 9 D (in), 10 C (in), 11 ~{LOAD} (in), 12 MAX/MIN (out), 13 ~{RCO} (out), 14 CLK (in), 15 A (in), 16 VCC (power) hidden to VCC
1 alternate drawing of the same symbol

## SN74HC191
designator U?
SYN UP/DOWN CNT DOWN/UP MODE CONTTOL
footprint SO16
footprint DIP-16
pins: 1 B (in), 2 QB (out), 3 QA (out), 4 ~{CTEN} (in), 5 D/~{U} (in), 6 QC (out), 7 QD (out), 8 GND (power) hidden to GND, 9 D (in), 10 C (in), 11 ~{LOAD} (in), 12 MAX/MIN (out), 13 ~{RCO} (out), 14 CLK (in), 15 A (in), 16 VCC (power) hidden to VCC
1 alternate drawing of the same symbol

## SN74HC192
designator U?
SYN 4-BIT UP/DOWN CNT DUAL CLK CR
footprint SO16
footprint DIP-16
pins: 1 B (in), 2 QB (out), 3 QA (out), 4 DOWN (in), 5 UP (in), 6 QC (out), 7 QD (out), 8 GND (power) hidden to GND, 9 D (in), 10 C (in), 11 ~{LOAD} (in), 12 ~{CO} (out), 13 ~{BO} (out), 14 CLR (in), 15 A (in), 16 VCC (power) hidden to VCC
1 alternate drawing of the same symbol

## SN74HC193
designator U?
SYN 4-BIT UP/DOWN CNT DUAL CLK CR
footprint SO16
footprint DIP-16
pins: 1 B (in), 2 QB (out), 3 QA (out), 4 DOWN (in), 5 UP (in), 6 QC (out), 7 QD (out), 8 GND (power) hidden to GND, 9 D (in), 10 C (in), 11 ~{LOAD} (in), 12 ~{CO} (out), 13 ~{BO} (out), 14 CLR (in), 15 A (in), 16 VCC (power) hidden to VCC
1 alternate drawing of the same symbol

## SN74HC194
designator U?
4-BIT BIDIRECTIONAL UNIVERSAL SFT REG
footprint DIP-16
pins: 1 ~{CLR} (in), 2 SR SER (in), 3 A (in), 4 B (in), 5 C (in), 6 D (in), 7 SL SER (in), 8 GND (power) hidden to GND, 9 S0 (in), 10 S1 (in), 11 CLK (in), 12 QD (out), 13 QC (out), 14 QB (out), 15 QA (out), 16 VCC (power) hidden to VCC
1 alternate drawing of the same symbol

## SN74HC195
designator U?
4-BIT PARALLEL ACCESS SFT REG
footprint DIP-16
pins: 1 ~{CLR} (in), 2 J (in), 3 ~{K} (in), 4 A (in), 5 B (in), 6 C (in), 7 D (in), 8 GND (power) hidden to GND, 9 SH/~{LD} (in), 10 CLK (in), 11 ~{Q}D (out), 12 QD (out), 13 QC (out), 14 QB (out), 15 QA (out), 16 VCC (power) hidden to VCC
1 alternate drawing of the same symbol

## SN74HC237
designator U?
3-8LINE DEC/DEMUL ADDRESS LCH
footprint SO16
footprint DIP-16
pins: 1 A (in), 2 B (in), 3 C (in), 4 ~{G}L (in), 5 ~{G}2 (in), 6 G1 (in), 7 y7 (out), 8 GND (power) hidden to GND, 9 y6 (out), 10 y5 (out), 11 y4 (out), 12 y3 (out), 13 y2 (out), 14 y1 (out), 15 y0 (out), 16 VCC (power) hidden to VCC
1 alternate drawing of the same symbol

## SN74HC238
designator U?
3-8LINE DEC/DEMUL
footprint SO16
footprint DIP-16
pins: 1 A (in), 2 B (in), 3 C (in), 4 ~{G}2A (in), 5 ~{G}2B (in), 6 G1 (in), 7 Y7 (out), 8 GND (power) hidden to GND, 9 Y6 (out), 10 Y5 (out), 11 Y4 (out), 12 Y3 (out), 13 Y2 (out), 14 Y1 (out), 15 Y0 (out), 16 VCC (power) hidden to VCC
1 alternate drawing of the same symbol

## SN74HC239
designator U?
DUAL 2-4LINE DEC/DEMULT
footprint SO16
footprint DIP-16
part A pins: 1 ~{G} (in), 2 A (in), 3 B (in), 4 Y0 (out), 5 Y1 (out), 6 Y2 (out), 7 Y3 (out), 8 GND (power) hidden to GND, 16 VCC (power) hidden to VCC
part B pins: 8 GND (power) hidden to GND, 9 Y3 (out), 10 Y2 (out), 11 Y1 (out), 12 Y0 (out), 13 B (in), 14 A (in), 15 ~{G} (in), 16 VCC (power) hidden to VCC
1 alternate drawing of the same symbol

## SN74HC240
designator U?
OCTAL BUF AND LIN DRV 3SO
footprint SO20W
footprint DIP-20
part A pins: 1 ~{G} (in), 2 A1 (in), 4 A2 (in), 6 A3 (in), 8 A4 (in), 10 GND (power) hidden to GND, 12 Y4 (hiz), 14 Y3 (hiz), 16 Y2 (hiz), 18 Y1 (hiz), 20 VCC (power) hidden to VCC
part B pins: 3 Y4 (hiz), 5 Y3 (hiz), 7 Y2 (hiz), 9 Y1 (hiz), 10 GND (power) hidden to GND, 11 A1 (in), 13 A2 (in), 15 A3 (in), 17 A4 (in), 19 ~{G} (in), 20 VCC (power) hidden to VCC
1 alternate drawing of the same symbol

## SN74HC241
designator U?
OCTAL BUF AND LIN DRV 3SO
footprint SO20W
footprint DIP-20
part A pins: 1 ~{G} (in), 2 A1 (in), 4 A2 (in), 6 A3 (in), 8 A4 (in), 10 GND (power) hidden to GND, 12 Y4 (hiz), 14 Y3 (hiz), 16 Y2 (hiz), 18 Y1 (hiz), 20 VCC (power) hidden to VCC
part B pins: 3 Y4 (hiz), 5 Y3 (hiz), 7 Y2 (hiz), 9 Y1 (hiz), 10 GND (power) hidden to GND, 11 A1 (in), 13 A2 (in), 15 A3 (in), 17 A4 (in), 19 G (in), 20 VCC (power) hidden to VCC
1 alternate drawing of the same symbol

## SN74HC242
designator U?
QUAD BUS TRANSCEIVER
footprint DIP-14
pins: 1 ~{G}AB (in), 3 A1 (hiz), 4 A2 (hiz), 5 A3 (hiz), 6 A4 (hiz), 7 GND (power) hidden to GND, 8 B4 (in), 9 B3 (in), 10 B2 (in), 11 B1 (in), 13 GBA (in), 14 VCC (power) hidden to VCC
1 alternate drawing of the same symbol

## SN74HC243
designator U?
QUAD BUS TRANSCEIVER
footprint DIP-14
pins: 1 ~{G}AB (in), 3 A1 (hiz), 4 A2 (hiz), 5 A3 (hiz), 6 A4 (hiz), 7 GND (power) hidden to GND, 8 B4 (in), 9 B3 (in), 10 B2 (in), 11 B1 (in), 13 GBA (in), 14 VCC (power) hidden to VCC
1 alternate drawing of the same symbol

## SN74HC244
designator U?
OCTAL BUF AND LIN DRV 3SO
footprint SO20W
footprint DIP-20
part A pins: 1 ~{G} (in), 2 A1 (in), 4 A2 (in), 6 A3 (in), 8 A4 (in), 10 GND (power) hidden to GND, 12 Y4 (hiz), 14 Y3 (hiz), 16 Y2 (hiz), 18 Y1 (hiz), 20 VCC (power) hidden to VCC
part B pins: 3 Y4 (hiz), 5 Y3 (hiz), 7 Y2 (hiz), 9 Y1 (hiz), 10 GND (power) hidden to GND, 11 A1 (in), 13 A2 (in), 15 A3 (in), 17 A4 (in), 19 ~{G} (in), 20 VCC (power) hidden to VCC
1 alternate drawing of the same symbol

## SN74HC245
designator U?
QUAD BUS TRANSCEIVER 3SO
footprint SO20W
footprint DIP-20
pins: 1 DIR (in), 2 A1 (hiz), 3 A2 (hiz), 4 A3 (hiz), 5 A4 (hiz), 6 A5 (hiz), 7 A6 (hiz), 8 A7 (hiz), 9 A8 (hiz), 10 GND (power) hidden to GND, 11 B8 (in), 12 B7 (in), 13 B6 (in), 14 B5 (in), 15 B4 (in), 16 B3 (in), 17 B2 (in), 18 B1 (in), 19 ~{G} (in), 20 VCC (power) hidden to VCC
1 alternate drawing of the same symbol

## SN74HC251
designator U?
DATA SLCR/MUX 3SO
footprint SO16
footprint DIP-16
pins: 1 D3 (in), 2 D2 (in), 3 D1 (in), 4 D0 (in), 5 Y (hiz), 6 W (hiz), 7 ~{G} (in), 8 GND (power) hidden to GND, 9 C (in), 10 B (in), 11 A (in), 12 D7 (in), 13 D6 (in), 14 D5 (in), 15 D4 (in), 16 VCC (power) hidden to VCC
1 alternate drawing of the same symbol

## SN74HC253
designator U?
DUAL 4-1LINES DATA SLCR/MUX
footprint SO16
footprint DIP-16
pins: 1 1~{G} (in), 2 B (in), 3 1C3 (in), 4 1C2 (in), 5 1C1 (in), 6 1C0 (in), 7 1Y (hiz), 8 GND (power) hidden to GND, 9 2Y (hiz), 10 2C0 (in), 11 2C1 (in), 12 2C2 (in), 13 2C3 (in), 14 A (in), 15 2~{G} (in), 16 VCC (power) hidden to VCC
1 alternate drawing of the same symbol

## SN74HC257
designator U?
QUAD 2-1LINE DATA SLCR/MUX
footprint SO16
footprint DIP-16
pins: 1 ~{A}/B (in), 2 1A (in), 3 1B (in), 4 1Y (hiz), 5 2A (in), 6 2B (in), 7 2Y (hiz), 8 GND (power) hidden to GND, 9 3Y (hiz), 10 3B (in), 11 3A (in), 12 4Y (hiz), 13 4B (in), 14 4A (in), 15 ~{G} (in), 16 VCC (power) hidden to VCC
1 alternate drawing of the same symbol

## SN74HC258
designator U?
QUAD 2-1LINE DATA SLCR/MUX
footprint SO16
footprint DIP-16
pins: 1 ~{A}/B (in), 2 1A (in), 3 1B (in), 4 1Y (hiz), 5 2A (in), 6 2B (in), 7 2Y (hiz), 8 GND (power) hidden to GND, 9 3Y (hiz), 10 3B (in), 11 3A (in), 12 4Y (hiz), 13 4B (in), 14 4A (in), 15 ~{G} (in), 16 VCC (power) hidden to VCC
1 alternate drawing of the same symbol

## SN74HC259
designator U?
8-BIT ADDRESSABLE LCH
footprint SO16
footprint DIP-16
pins: 1 S0 (in), 2 S1 (in), 3 S2 (in), 4 Q0 (out), 5 Q1 (out), 6 Q2 (out), 7 Q3 (out), 8 GND (power) hidden to GND, 9 Q4 (out), 10 Q5 (out), 11 Q6 (out), 12 Q7 (out), 13 D (in), 14 ~{G} (in), 15 ~{CLR} (in), 16 VCC (power) hidden to VCC
1 alternate drawing of the same symbol


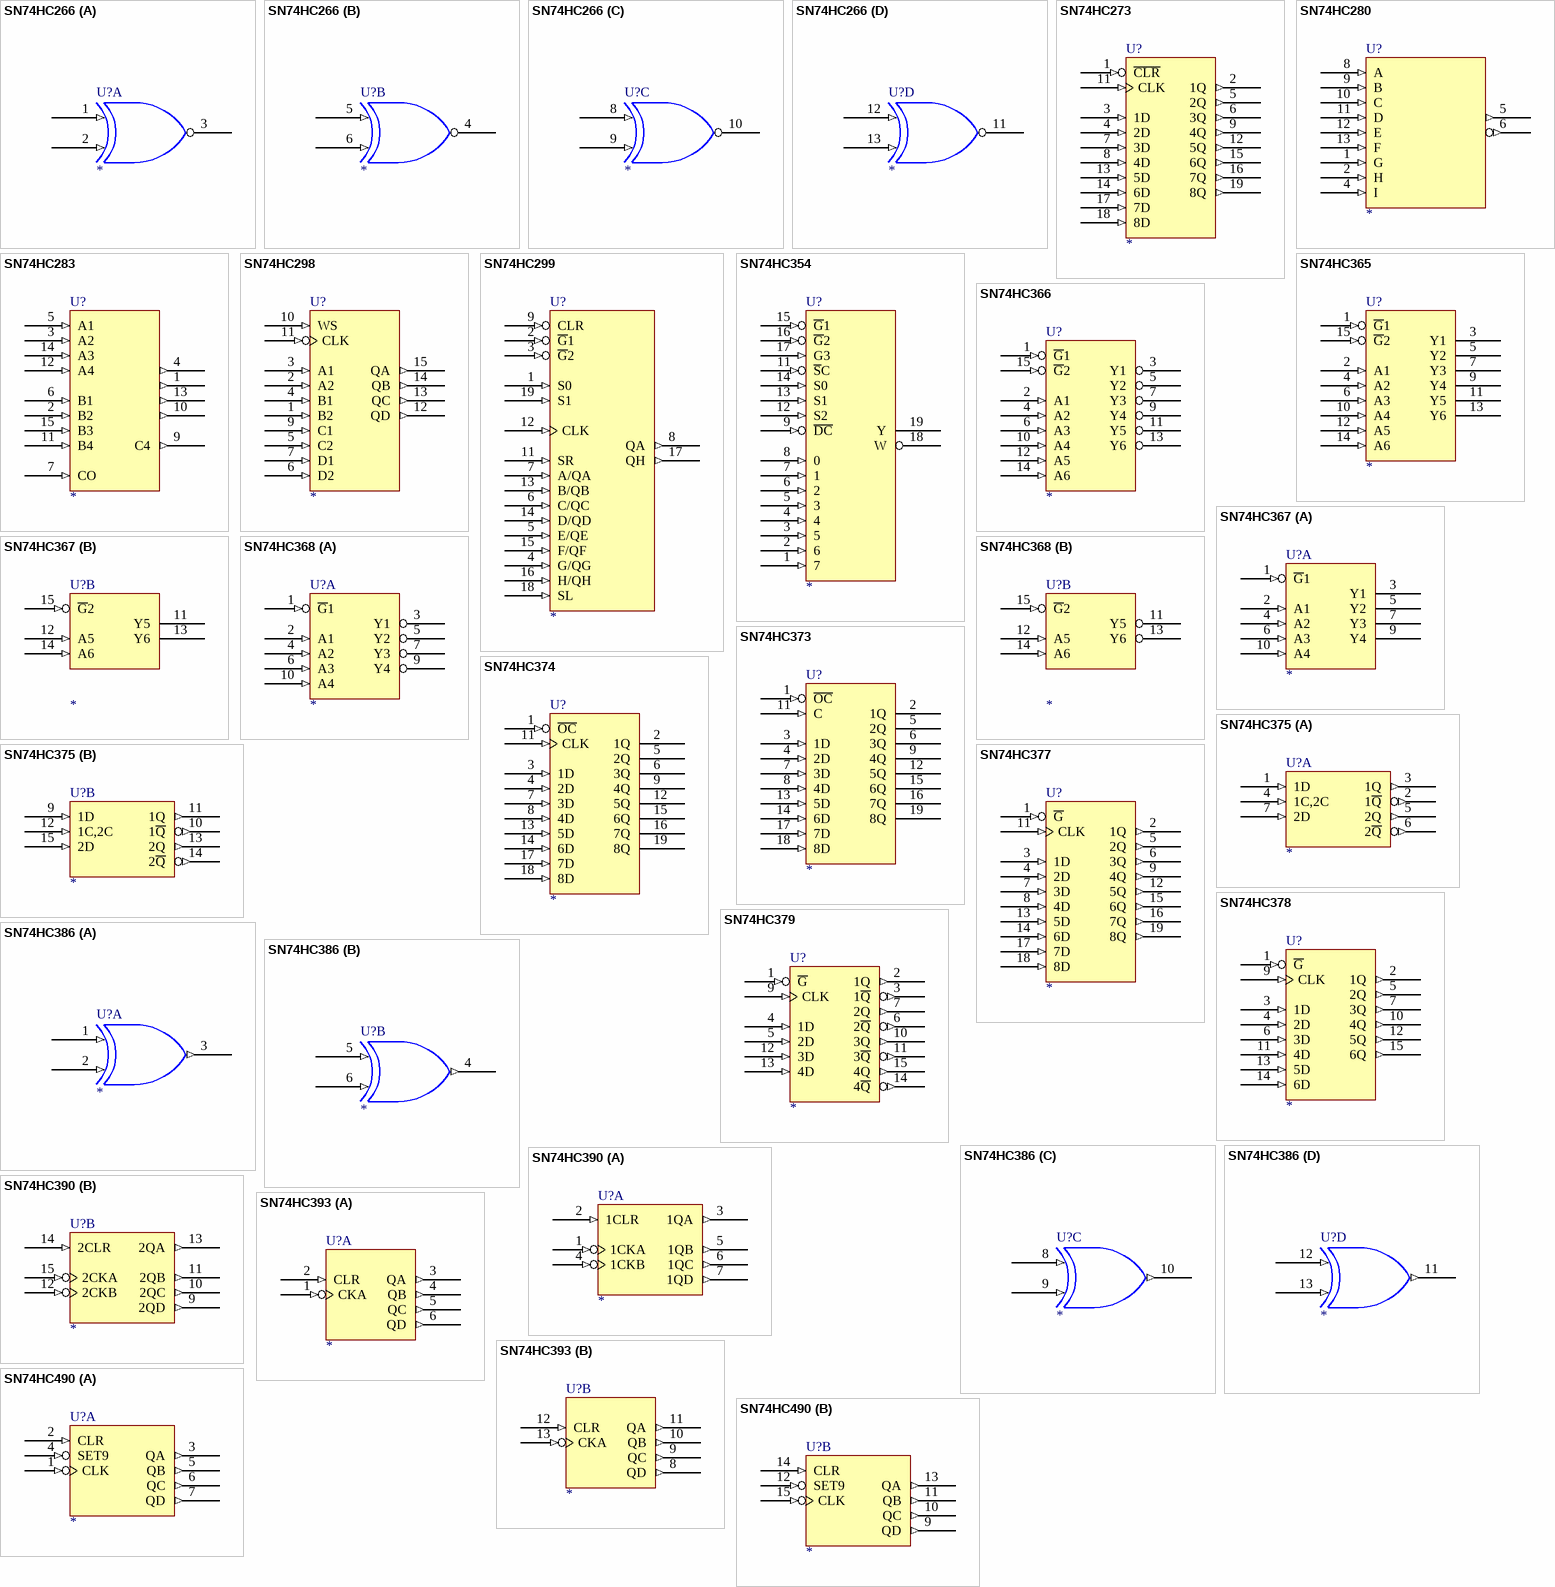
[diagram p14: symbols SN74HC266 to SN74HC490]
## SN74HC266
designator U?
QUAD 2-IN XOR  G OCO
footprint SO14
footprint DIP-14
part A pins: 1 (in), 2 (in), 3 (oc), 7 GND (power) hidden to GND, 14 VCC (power) hidden to VCC
part B pins: 4 (oc), 5 (in), 6 (in), 7 GND (power) hidden to GND, 14 VCC (power) hidden to VCC
part C pins: 7 GND (power) hidden to GND, 8 (in), 9 (in), 10 (oc), 14 VCC (power) hidden to VCC
part D pins: 7 GND (power) hidden to GND, 11 (oc), 12 (in), 13 (in), 14 VCC (power) hidden to VCC
1 alternate drawing of the same symbol

## SN74HC273
designator U?
OCTAL D-TYPE FF CR
footprint SO20W
footprint DIP-20
pins: 1 ~{CLR} (in), 2 1Q (out), 3 1D (in), 4 2D (in), 5 2Q (out), 6 3Q (out), 7 3D (in), 8 4D (in), 9 4Q (out), 10 GND (power) hidden to GND, 11 CLK (in), 12 5Q (out), 13 5D (in), 14 6D (in), 15 6Q (out), 16 7Q (out), 17 7D (in), 18 8D (in), 19 8Q (out), 20 VCC (power) hidden to VCC
1 alternate drawing of the same symbol

## SN74HC280
designator U?
9-BIT ODD/EVEN PARITY GNR/CHKR
footprint SO14
footprint DIP-14
pins: 1 G (in), 2 H (in), 4 I (in), 5 (out), 6 (out), 7 GND (power) hidden to GND, 8 A (in), 9 B (in), 10 C (in), 11 D (in), 12 E (in), 13 F (in), 14 VCC (power) hidden to VCC
1 alternate drawing of the same symbol

## SN74HC283
designator U?
4-BIT BIN ADD WITH FC
footprint SO16
footprint DIP-16
pins: 1 (out), 2 B2 (in), 3 A2 (in), 4 (out), 5 A1 (in), 6 B1 (in), 7 CO (in), 8 GND (power) hidden to GND, 9 C4 (out), 10 (out), 11 B4 (in), 12 A4 (in), 13 (out), 14 A3 (in), 15 B3 (in), 16 VCC (power) hidden to VCC
1 alternate drawing of the same symbol

## SN74HC298
designator U?
QUAD 2-IN MUX WITH STORAGE
footprint DIP-16
pins: 1 B2 (in), 2 A2 (in), 3 A1 (in), 4 B1 (in), 5 C2 (in), 6 D2 (in), 7 D1 (in), 8 GND (power) hidden to GND, 9 C1 (in), 10 WS (in), 11 CLK (in), 12 QD (out), 13 QC (out), 14 QB (out), 15 QA (out), 16 VCC (power) hidden to VCC
1 alternate drawing of the same symbol

## SN74HC299
designator U?
8-BIT UNIVERSAL SFT/STORAGE REG
footprint SO20W
footprint DIP-20
pins: 1 S0 (in), 2 ~{G}1 (in), 3 ~{G}2 (in), 4 G/QG (in), 5 E/QE (in), 6 C/QC (in), 7 A/QA (in), 8 QA (out), 9 CLR (in), 10 GND (power) hidden to GND, 11 SR (in), 12 CLK (in), 13 B/QB (in), 14 D/QD (in), 15 F/QF (in), 16 H/QH (in), 17 QH (out), 18 SL (in), 19 S1 (in), 20 VCC (power) hidden to VCC
1 alternate drawing of the same symbol

## SN74HC354
designator U?
8-1LINE DATA SLCR/MUX/REG
footprint SO20W
footprint DIP-20
pins: 1 7 (in), 2 6 (in), 3 5 (in), 4 (in), 5 3 (in), 6 2 (in), 7 1 (in), 8 0 (in), 9 ~{DC} (in), 10 GND (power) hidden to GND, 11 ~{S}C (in), 12 S2 (in), 13 S1 (in), 14 S0 (in), 15 ~{G}1 (in), 16 ~{G}2 (in), 17 G3 (in), 18 W (hiz), 19 Y (hiz), 20 VCC (power) hidden to VCC
1 alternate drawing of the same symbol

## SN74HC365
designator U?
HEX BUS DRV 3SO
footprint SO16
footprint DIP-16
pins: 1 ~{G}1 (in), 2 A1 (in), 3 Y1 (hiz), 4 A2 (in), 5 Y2 (hiz), 6 A3 (in), 7 Y3 (hiz), 8 GND (power) hidden to GND, 9 Y4 (hiz), 10 A4 (in), 11 Y5 (hiz), 12 A5 (in), 13 Y6 (hiz), 14 A6 (in), 15 ~{G}2 (in), 16 VCC (power) hidden to VCC
1 alternate drawing of the same symbol

## SN74HC366
designator U?
HEX BUS DRV 3SO
footprint SO16
footprint DIP-16
pins: 1 ~{G}1 (in), 2 A1 (in), 3 Y1 (hiz), 4 A2 (in), 5 Y2 (hiz), 6 A3 (in), 7 Y3 (hiz), 8 GND (power) hidden to GND, 9 Y4 (hiz), 10 A4 (in), 11 Y5 (hiz), 12 A5 (in), 13 Y6 (hiz), 14 A6 (in), 15 ~{G}2 (in), 16 VCC (power) hidden to VCC
1 alternate drawing of the same symbol

## SN74HC367
designator U?
HEX BUS DRV 3SO
footprint SO16
footprint DIP-16
part A pins: 1 ~{G}1 (in), 2 A1 (in), 3 Y1 (hiz), 4 A2 (in), 5 Y2 (hiz), 6 A3 (in), 7 Y3 (hiz), 8 GND (power) hidden to GND, 9 Y4 (hiz), 10 A4 (in), 16 VCC (power) hidden to VCC
part B pins: 8 GND (power) hidden to GND, 11 Y5 (hiz), 12 A5 (in), 13 Y6 (hiz), 14 A6 (in), 15 ~{G}2 (in), 16 VCC (power) hidden to VCC
1 alternate drawing of the same symbol

## SN74HC368
designator U?
HEX BUS DRV 3SO
footprint SO16
footprint DIP-16
part A pins: 1 ~{G}1 (in), 2 A1 (in), 3 Y1 (hiz), 4 A2 (in), 5 Y2 (hiz), 6 A3 (in), 7 Y3 (hiz), 8 GND (power) hidden to GND, 9 Y4 (hiz), 10 A4 (in), 16 VCC (power) hidden to VCC
part B pins: 8 GND (power) hidden to GND, 11 Y5 (hiz), 12 A5 (in), 13 Y6 (hiz), 14 A6 (in), 15 ~{G}2 (in), 16 VCC (power) hidden to VCC
1 alternate drawing of the same symbol

## SN74HC373
designator U?
OCTAL TRANSPARENT LCH
footprint SO20W
footprint DIP-20
pins: 1 ~{OC} (in), 2 1Q (hiz), 3 1D (in), 4 2D (in), 5 2Q (hiz), 6 3Q (hiz), 7 3D (in), 8 4D (in), 9 4Q (hiz), 10 GND (power) hidden to GND, 11 C (in), 12 5Q (hiz), 13 5D (in), 14 6D (in), 15 6Q (hiz), 16 7Q (hiz), 17 7D (in), 18 8D (in), 19 8Q (hiz), 20 VCC (power) hidden to VCC
1 alternate drawing of the same symbol

## SN74HC374
designator U?
OCTAL  D-TYPE EDGE-TRIGGERED FF 3SO
footprint SO20W
footprint DIP-20
pins: 1 ~{OC} (in), 2 1Q (hiz), 3 1D (in), 4 2D (in), 5 2Q (hiz), 6 3Q (hiz), 7 3D (in), 8 4D (in), 9 4Q (hiz), 10 GND (power) hidden to GND, 11 CLK (in), 12 5Q (hiz), 13 5D (in), 14 6D (in), 15 6Q (hiz), 16 7Q (hiz), 17 7D (in), 18 8D (in), 19 8Q (hiz), 20 VCC (power) hidden to VCC
1 alternate drawing of the same symbol

## SN74HC375
designator U?
4-BIT BISTABLE LCH
footprint SO16
footprint DIP-16
part A pins: 1 1D (in), 2 1~{Q} (out), 3 1Q (out), 4 1C,2C (in), 5 2Q (out), 6 2~{Q} (out), 7 2D (in), 8 GND (power) hidden to GND, 16 VCC (power) hidden to VCC
part B pins: 8 GND (power) hidden to GND, 9 1D (in), 10 1~{Q} (out), 11 1Q (out), 12 1C,2C (in), 13 2Q (out), 14 2~{Q} (out), 15 2D (in), 16 VCC (power) hidden to VCC
1 alternate drawing of the same symbol

## SN74HC377
designator U?
OCTAL D-TYPE FF WITH ENABLE
footprint SO20W
footprint DIP-20
pins: 1 ~{G} (in), 2 1Q (out), 3 1D (in), 4 2D (in), 5 2Q (out), 6 3Q (out), 7 3D (in), 8 4D (in), 9 4Q (out), 10 GND (power) hidden to GND, 11 CLK (in), 12 5Q (out), 13 5D (in), 14 6D (in), 15 6Q (out), 16 7Q (out), 17 7D (in), 18 8D (in), 19 8Q (out), 20 VCC (power) hidden to VCC
1 alternate drawing of the same symbol

## SN74HC378
designator U?
HEX D-TYPE FF WITH ENABLE
footprint SO16
footprint DIP-16
pins: 1 ~{G} (in), 2 1Q (out), 3 1D (in), 4 2D (in), 5 2Q (out), 6 3D (in), 7 3Q (out), 8 GND (power) hidden to GND, 9 CLK (in), 10 4Q (out), 11 4D (in), 12 5Q (out), 13 5D (in), 14 6D (in), 15 6Q (out), 16 VCC (power) hidden to VCC
1 alternate drawing of the same symbol

## SN74HC379
designator U?
QUAD D-TYPE FF WITH ENABLE
footprint SO16
footprint DIP-16
pins: 1 ~{G} (in), 2 1Q (out), 3 1~{Q} (out), 4 1D (in), 5 2D (in), 6 2~{Q} (out), 7 2Q (out), 8 GND (power) hidden to GND, 9 CLK (in), 10 3Q (out), 11 3~{Q} (out), 12 3D (in), 13 4D (in), 14 4~{Q} (out), 15 4Q (out), 16 VCC (power) hidden to VCC
1 alternate drawing of the same symbol

## SN74HC386
designator U?
QUAD 2-IN XOR
footprint SO14
footprint DIP-14
part A pins: 1 (in), 2 (in), 3 (out), 7 GND (power) hidden to GND, 14 VCC (power) hidden to VCC
part B pins: 4 (out), 5 (in), 6 (in), 7 GND (power) hidden to GND, 14 VCC (power) hidden to VCC
part C pins: 7 GND (power) hidden to GND, 8 (in), 9 (in), 10 (out), 14 VCC (power) hidden to VCC
part D pins: 7 GND (power) hidden to GND, 11 (out), 12 (in), 13 (in), 14 VCC (power) hidden to VCC
1 alternate drawing of the same symbol

## SN74HC390
designator U?
DUAL 4-BIT AND BIN CNT
footprint SO16
footprint DIP-16
part A pins: 1 1CKA (in), 2 1CLR (in), 3 1QA (out), 4 1CKB (in), 5 1QB (out), 6 1QC (out), 7 1QD (out), 8 GND (power) hidden to GND, 16 VCC (power) hidden to VCC
part B pins: 8 GND (power) hidden to GND, 9 2QD (out), 10 2QC (out), 11 2QB (out), 12 2CKB (in), 13 2QA (out), 14 2CLR (in), 15 2CKA (in), 16 VCC (power) hidden to VCC
1 alternate drawing of the same symbol

## SN74HC393
designator U?
DUAL 4-BIT AND BIN CNT
footprint DIP-14
part A pins: 1 CKA (in), 2 CLR (in), 3 QA (out), 4 QB (out), 5 QC (out), 6 QD (out), 7 GND (power) hidden to GND, 14 VCC (power) hidden to VCC
part B pins: 7 GND (power) hidden to GND, 8 QD (out), 9 QC (out), 10 QB (out), 11 QA (out), 12 CLR (in), 13 CKA (in), 14 VCC (power) hidden to VCC
1 alternate drawing of the same symbol

## SN74HC490
designator U?
DUAL 4-BIT AND BIN CNT
footprint DIP-16
part A pins: 1 CLK (in), 2 CLR (in), 3 QA (out), 4 SET9 (in), 5 QB (out), 6 QC (out), 7 QD (out), 8 GND (power) hidden to GND, 16 VCC (power) hidden to VCC
part B pins: 8 GND (power) hidden to GND, 9 QD (out), 10 QC (out), 11 QB (out), 12 SET9 (in), 13 QA (out), 14 CLR (in), 15 CLK (in), 16 VCC (power) hidden to VCC
1 alternate drawing of the same symbol


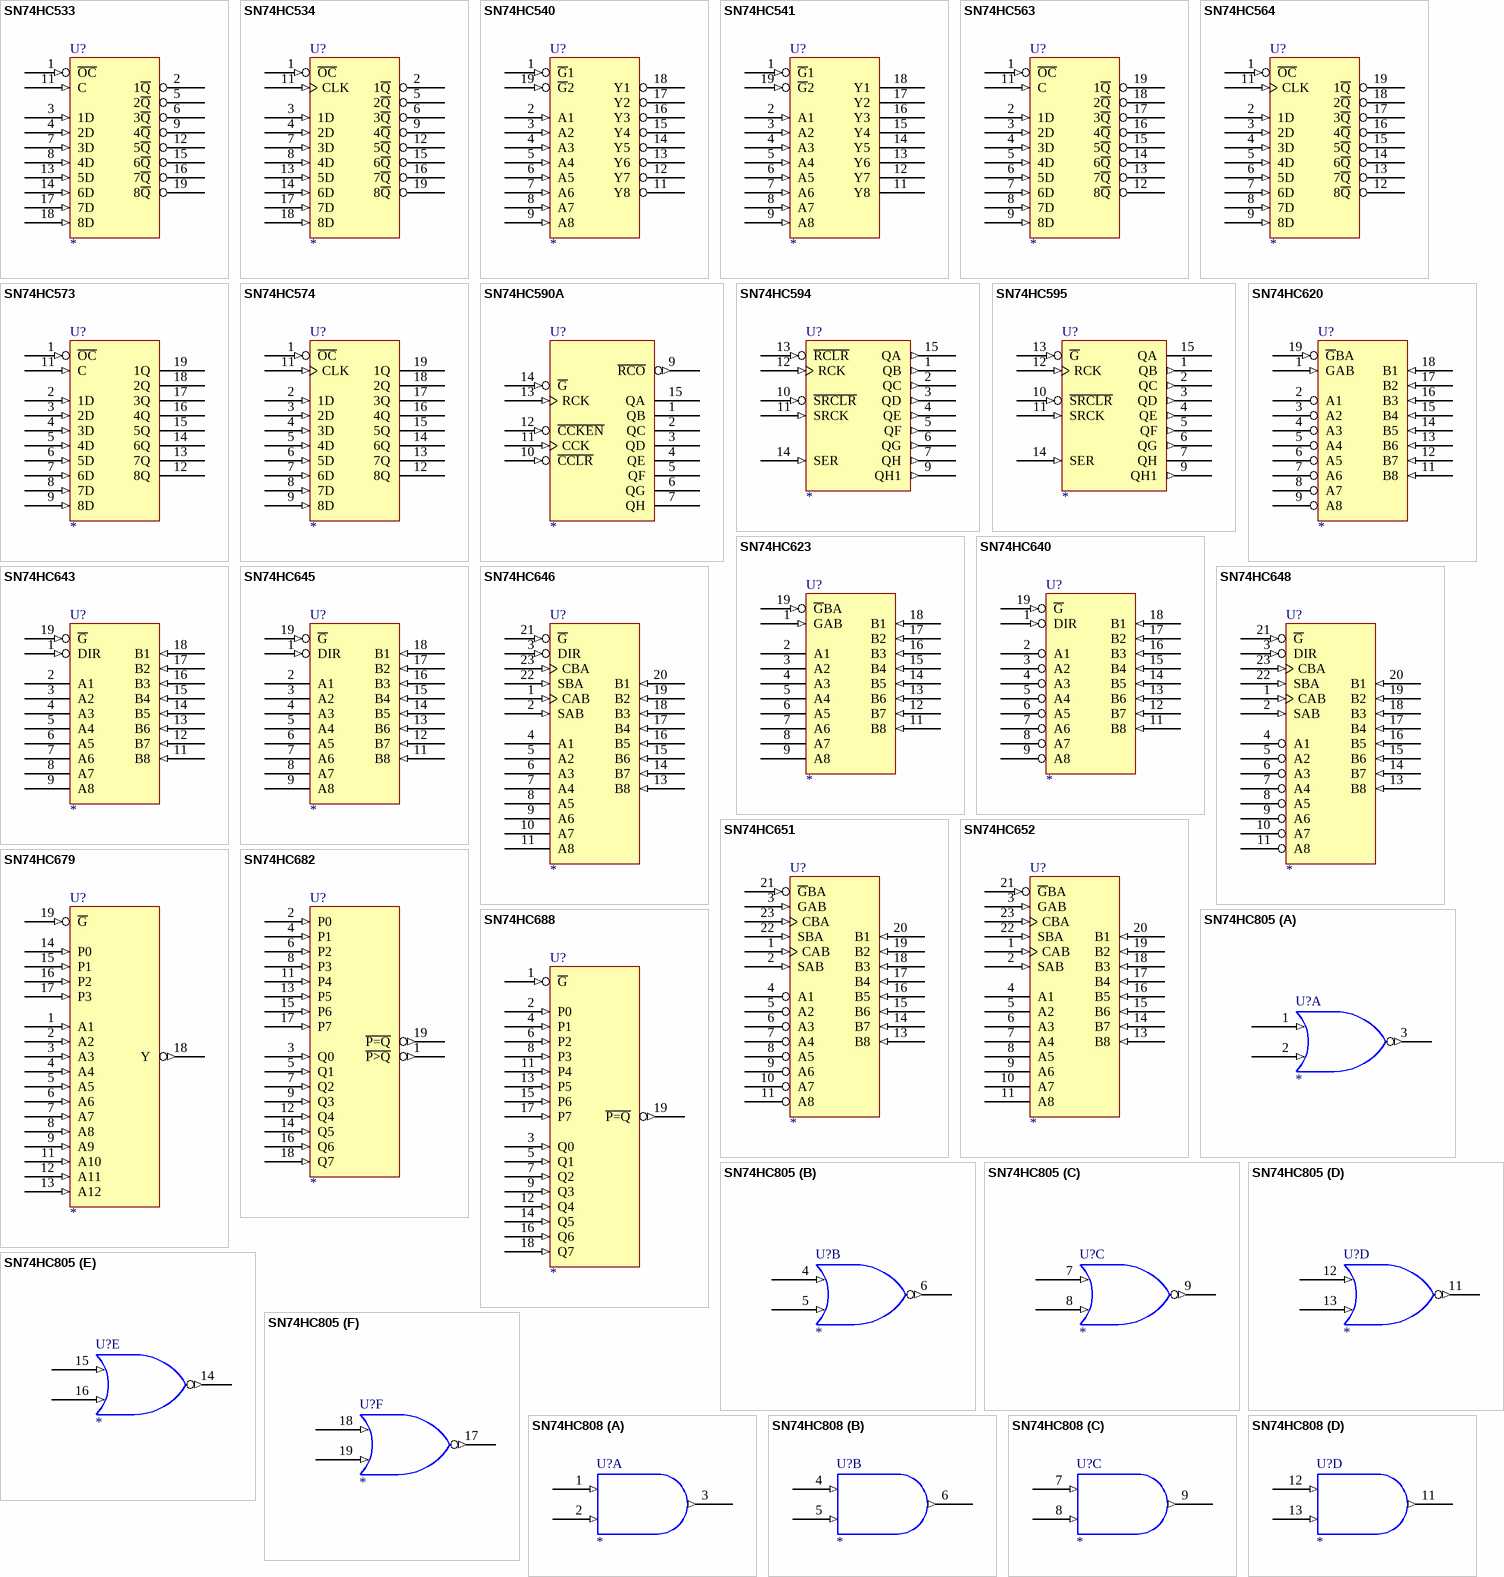
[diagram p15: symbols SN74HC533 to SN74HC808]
## SN74HC533
designator U?
OCTAL D-TYPE TRANSPARENT LCH 3SO
footprint SO20W
footprint DIP-20
pins: 1 ~{OC} (in), 2 1~{Q} (hiz), 3 1D (in), 4 2D (in), 5 2~{Q} (hiz), 6 3~{Q} (hiz), 7 3D (in), 8 4D (in), 9 4~{Q} (hiz), 10 GND (power) hidden to GND, 11 C (in), 12 5~{Q} (hiz), 13 5D (in), 14 6D (in), 15 6~{Q} (hiz), 16 7~{Q} (hiz), 17 7D (in), 18 8D (in), 19 8~{Q} (hiz), 20 VCC (power) hidden to VCC
1 alternate drawing of the same symbol

## SN74HC534
designator U?
OCTAL TRANSPARENT LCH
footprint SO20W
footprint DIP-20
pins: 1 ~{OC} (in), 2 1~{Q} (hiz), 3 1D (in), 4 2D (in), 5 2~{Q} (hiz), 6 3~{Q} (hiz), 7 3D (in), 8 4D (in), 9 4~{Q} (hiz), 10 GND (power) hidden to GND, 11 CLK (in), 12 5~{Q} (hiz), 13 5D (in), 14 6D (in), 15 6~{Q} (hiz), 16 7~{Q} (hiz), 17 7D (in), 18 8D (in), 19 8~{Q} (hiz), 20 VCC (power) hidden to VCC
1 alternate drawing of the same symbol

## SN74HC540
designator U?
OCTAL BUF AND LINE DRV 3SO
footprint SO20W
footprint DIP-20
pins: 1 ~{G}1 (in), 2 A1 (in), 3 A2 (in), 4 A3 (in), 5 A4 (in), 6 A5 (in), 7 A6 (in), 8 A7 (in), 9 A8 (in), 10 GND (power) hidden to GND, 11 Y8 (hiz), 12 Y7 (hiz), 13 Y6 (hiz), 14 Y5 (hiz), 15 Y4 (hiz), 16 Y3 (hiz), 17 Y2 (hiz), 18 Y1 (hiz), 19 ~{G}2 (in), 20 VCC (power) hidden to VCC
1 alternate drawing of the same symbol

## SN74HC541
designator U?
OCTAL BUF AND LINE DRV 3SO
footprint SO20W
footprint DIP-20
pins: 1 ~{G}1 (in), 2 A1 (in), 3 A2 (in), 4 A3 (in), 5 A4 (in), 6 A5 (in), 7 A6 (in), 8 A7 (in), 9 A8 (in), 10 GND (power) hidden to GND, 11 Y8 (hiz), 12 Y7 (hiz), 13 Y6 (hiz), 14 Y5 (hiz), 15 Y4 (hiz), 16 Y3 (hiz), 17 Y2 (hiz), 18 Y1 (hiz), 19 ~{G}2 (in), 20 VCC (power) hidden to VCC
1 alternate drawing of the same symbol

## SN74HC563
designator U?
OCTAL D-TYPE TRANSPARENT LCH 3SO
footprint SO20W
footprint DIP-20
pins: 1 ~{OC} (in), 2 1D (in), 3 2D (in), 4 3D (in), 5 4D (in), 6 5D (in), 7 6D (in), 8 7D (in), 9 8D (in), 10 GND (power) hidden to GND, 11 C (in), 12 8~{Q} (hiz), 13 7~{Q} (hiz), 14 6~{Q} (hiz), 15 5~{Q} (hiz), 16 4~{Q} (hiz), 17 3~{Q} (hiz), 18 2~{Q} (hiz), 19 1~{Q} (hiz), 20 VCC (power) hidden to VCC
1 alternate drawing of the same symbol

## SN74HC564
designator U?
OCTAL D-TYPE EDGE-TRIGGERED FF 3SO
footprint SO20W
footprint DIP-20
pins: 1 ~{OC} (in), 2 1D (in), 3 2D (in), 4 3D (in), 5 4D (in), 6 5D (in), 7 6D (in), 8 7D (in), 9 8D (in), 10 GND (power) hidden to GND, 11 CLK (in), 12 8~{Q} (hiz), 13 7~{Q} (hiz), 14 6~{Q} (hiz), 15 5~{Q} (hiz), 16 4~{Q} (hiz), 17 3~{Q} (hiz), 18 2~{Q} (hiz), 19 1~{Q} (hiz), 20 VCC (power) hidden to VCC
1 alternate drawing of the same symbol

## SN74HC573
designator U?
OCTAL D-TYPE TRANSPARENT LCH 3SO
footprint SO20W
footprint DIP-20
pins: 1 ~{OC} (in), 2 1D (in), 3 2D (in), 4 3D (in), 5 4D (in), 6 5D (in), 7 6D (in), 8 7D (in), 9 8D (in), 10 GND (power) hidden to GND, 11 C (in), 12 8Q (hiz), 13 7Q (hiz), 14 6Q (hiz), 15 5Q (hiz), 16 4Q (hiz), 17 3Q (hiz), 18 2Q (hiz), 19 1Q (hiz), 20 VCC (power) hidden to VCC
1 alternate drawing of the same symbol

## SN74HC574
designator U?
OCTAL D-TYPE EDGE-TRIGGERED FF 3SO
footprint SO20W
footprint DIP-20
pins: 1 ~{OC} (in), 2 1D (in), 3 2D (in), 4 3D (in), 5 4D (in), 6 5D (in), 7 6D (in), 8 7D (in), 9 8D (in), 10 GND (power) hidden to GND, 11 CLK (in), 12 8Q (hiz), 13 7Q (hiz), 14 6Q (hiz), 15 5Q (hiz), 16 4Q (hiz), 17 3Q (hiz), 18 2Q (hiz), 19 1Q (hiz), 20 VCC (power) hidden to VCC
1 alternate drawing of the same symbol

## SN74HC590A
designator U?
8-BIT BIN CNT WITH OUTPUT REGISTERS
footprint SO16W
footprint DIP-16
pins: 1 QB (hiz), 2 QC (hiz), 3 QD (hiz), 4 QE (hiz), 5 QF (hiz), 6 QG (hiz), 7 QH (hiz), 8 GND (power) hidden to GND, 9 ~{RCO} (out), 10 ~{CCLR} (in), 11 CCK (in), 12 ~{CCKEN} (in), 13 RCK (in), 14 ~{G} (in), 15 QA (hiz), 16 VCC (power) hidden to VCC
1 alternate drawing of the same symbol

## SN74HC594
designator U?
8-BIT SFT REG WIRTH OUTPUT LCH
footprint SO16
footprint DIP-16
pins: 1 QB (out), 2 QC (out), 3 QD (out), 4 QE (out), 5 QF (out), 6 QG (out), 7 QH (out), 8 GND (power) hidden to GND, 9 QH1 (out), 10 ~{SRCLR} (in), 11 SRCK (in), 12 RCK (in), 13 ~{RCLR} (in), 14 SER (in), 15 QA (out), 16 VCC (power) hidden to VCC
1 alternate drawing of the same symbol

## SN74HC595
designator U?
8-BIT SFT REG WIRTH OUTPUT LCH
footprint SO16
footprint DIP-16
pins: 1 QB (out), 2 QC (out), 3 QD (out), 4 QE (out), 5 QF (out), 6 QG (out), 7 QH (hiz), 8 GND (power) hidden to GND, 9 QH1 (out), 10 ~{SRCLR} (in), 11 SRCK (in), 12 RCK (in), 13 ~{G} (in), 14 SER (in), 15 QA (hiz), 16 VCC (power) hidden to VCC
1 alternate drawing of the same symbol

## SN74HC620
designator U?
OCTAL BUS TRANCEIVER
footprint SO20W
footprint DIP-20
pins: 1 GAB (in), 2 A1 (hiz), 3 A2 (hiz), 4 A3 (hiz), 5 A4 (hiz), 6 A5 (hiz), 7 A6 (hiz), 8 A7 (hiz), 9 A8 (hiz), 10 GND (power) hidden to GND, 11 B8 (in), 12 B7 (in), 13 B6 (in), 14 B5 (in), 15 B4 (in), 16 B3 (in), 17 B2 (in), 18 B1 (in), 19 ~{G}BA (in), 20 VCC (power) hidden to VCC
1 alternate drawing of the same symbol

## SN74HC623
designator U?
OCTAL BUS TRANCEIVER
footprint SO20W
footprint DIP-20
pins: 1 GAB (in), 2 A1 (hiz), 3 A2 (hiz), 4 A3 (hiz), 5 A4 (hiz), 6 A5 (hiz), 7 A6 (hiz), 8 A7 (hiz), 9 A8 (hiz), 10 GND (power) hidden to GND, 11 B8 (in), 12 B7 (in), 13 B6 (in), 14 B5 (in), 15 B4 (in), 16 B3 (in), 17 B2 (in), 18 B1 (in), 19 ~{G}BA (in), 20 VCC (power) hidden to VCC
1 alternate drawing of the same symbol

## SN74HC640
designator U?
OCTAL BUS TRANCEIVER
footprint SO20W
footprint DIP-20
pins: 1 DIR (in), 2 A1 (hiz), 3 A2 (hiz), 4 A3 (hiz), 5 A4 (hiz), 6 A5 (hiz), 7 A6 (hiz), 8 A7 (hiz), 9 A8 (hiz), 10 GND (power) hidden to GND, 11 B8 (in), 12 B7 (in), 13 B6 (in), 14 B5 (in), 15 B4 (in), 16 B3 (in), 17 B2 (in), 18 B1 (in), 19 ~{G} (in), 20 VCC (power) hidden to VCC
1 alternate drawing of the same symbol

## SN74HC643
designator U?
OCTAL BUS TRANCEIVER
footprint SO20W
footprint DIP-20
pins: 1 DIR (in), 2 A1 (hiz), 3 A2 (hiz), 4 A3 (hiz), 5 A4 (hiz), 6 A5 (hiz), 7 A6 (hiz), 8 A7 (hiz), 9 A8 (hiz), 10 GND (power) hidden to GND, 11 B8 (in), 12 B7 (in), 13 B6 (in), 14 B5 (in), 15 B4 (in), 16 B3 (in), 17 B2 (in), 18 B1 (in), 19 ~{G} (in), 20 VCC (power) hidden to VCC
1 alternate drawing of the same symbol

## SN74HC645
designator U?
OCTAL BUS TRANCEIVER
footprint SO20W
footprint DIP-20
pins: 1 DIR (in), 2 A1 (hiz), 3 A2 (hiz), 4 A3 (hiz), 5 A4 (hiz), 6 A5 (hiz), 7 A6 (hiz), 8 A7 (hiz), 9 A8 (hiz), 10 GND (power) hidden to GND, 11 B8 (in), 12 B7 (in), 13 B6 (in), 14 B5 (in), 15 B4 (in), 16 B3 (in), 17 B2 (in), 18 B1 (in), 19 ~{G} (in), 20 VCC (power) hidden to VCC
1 alternate drawing of the same symbol

## SN74HC646
designator U?
OCTAL BUS TRANCEIVER AND REG
footprint SO24W
footprint DIP-24
pins: 1 CAB (in), 2 SAB (in), 3 DIR (in), 4 A1 (hiz), 5 A2 (hiz), 6 A3 (hiz), 7 A4 (hiz), 8 A5 (hiz), 9 A6 (hiz), 10 A7 (hiz), 11 A8 (hiz), 12 GND (power) hidden to GND, 13 B8 (in), 14 B7 (in), 15 B6 (in), 16 B5 (in), 17 B4 (in), 18 B3 (in), 19 B2 (in), 20 B1 (in), 21 ~{G} (in), 22 SBA (in), 23 CBA (in), 24 VCC (power) hidden to VCC
1 alternate drawing of the same symbol

## SN74HC648
designator U?
OCTAL BUS TRANCEIVER AND REG
footprint SO24W
footprint DIP-24
pins: 1 CAB (in), 2 SAB (in), 3 DIR (in), 4 A1 (hiz), 5 A2 (hiz), 6 A3 (hiz), 7 A4 (hiz), 8 A5 (hiz), 9 A6 (hiz), 10 A7 (hiz), 11 A8 (hiz), 12 GND (power) hidden to GND, 13 B8 (in), 14 B7 (in), 15 B6 (in), 16 B5 (in), 17 B4 (in), 18 B3 (in), 19 B2 (in), 20 B1 (in), 21 ~{G} (in), 22 SBA (in), 23 CBA (in), 24 VCC (power) hidden to VCC
1 alternate drawing of the same symbol

## SN74HC651
designator U?
OCTAL BUS TRANCEIVER AND REG
footprint SO24W
footprint DIP-24
pins: 1 CAB (in), 2 SAB (in), 3 GAB (in), 4 A1 (hiz), 5 A2 (hiz), 6 A3 (hiz), 7 A4 (hiz), 8 A5 (hiz), 9 A6 (hiz), 10 A7 (hiz), 11 A8 (hiz), 12 GND (power) hidden to GND, 13 B8 (in), 14 B7 (in), 15 B6 (in), 16 B5 (in), 17 B4 (in), 18 B3 (in), 19 B2 (in), 20 B1 (in), 21 ~{G}BA (in), 22 SBA (in), 23 CBA (in), 24 VCC (power) hidden to VCC
1 alternate drawing of the same symbol

## SN74HC652
designator U?
OCTAL BUS TRANCEIVER AND REG
footprint SO24W
footprint DIP-24
pins: 1 CAB (in), 2 SAB (in), 3 GAB (in), 4 A1 (hiz), 5 A2 (hiz), 6 A3 (hiz), 7 A4 (hiz), 8 A5 (hiz), 9 A6 (hiz), 10 A7 (hiz), 11 A8 (hiz), 12 GND (power) hidden to GND, 13 B8 (in), 14 B7 (in), 15 B6 (in), 16 B5 (in), 17 B4 (in), 18 B3 (in), 19 B2 (in), 20 B1 (in), 21 ~{G}BA (in), 22 SBA (in), 23 CBA (in), 24 VCC (power) hidden to VCC
1 alternate drawing of the same symbol

## SN74HC679
designator U?
12-BIT ADDRESS COMPARATORS
footprint SO20W
footprint DIP-20
pins: 1 A1 (in), 2 A2 (in), 3 A3 (in), 4 A4 (in), 5 A5 (in), 6 A6 (in), 7 A7 (in), 8 A8 (in), 9 A9 (in), 10 GND (power) hidden to GND, 11 A10 (in), 12 A11 (in), 13 A12 (in), 14 P0 (in), 15 P1 (in), 16 P2 (in), 17 P3 (in), 18 Y (out), 19 ~{G} (in), 20 VCC (power) hidden to VCC
1 alternate drawing of the same symbol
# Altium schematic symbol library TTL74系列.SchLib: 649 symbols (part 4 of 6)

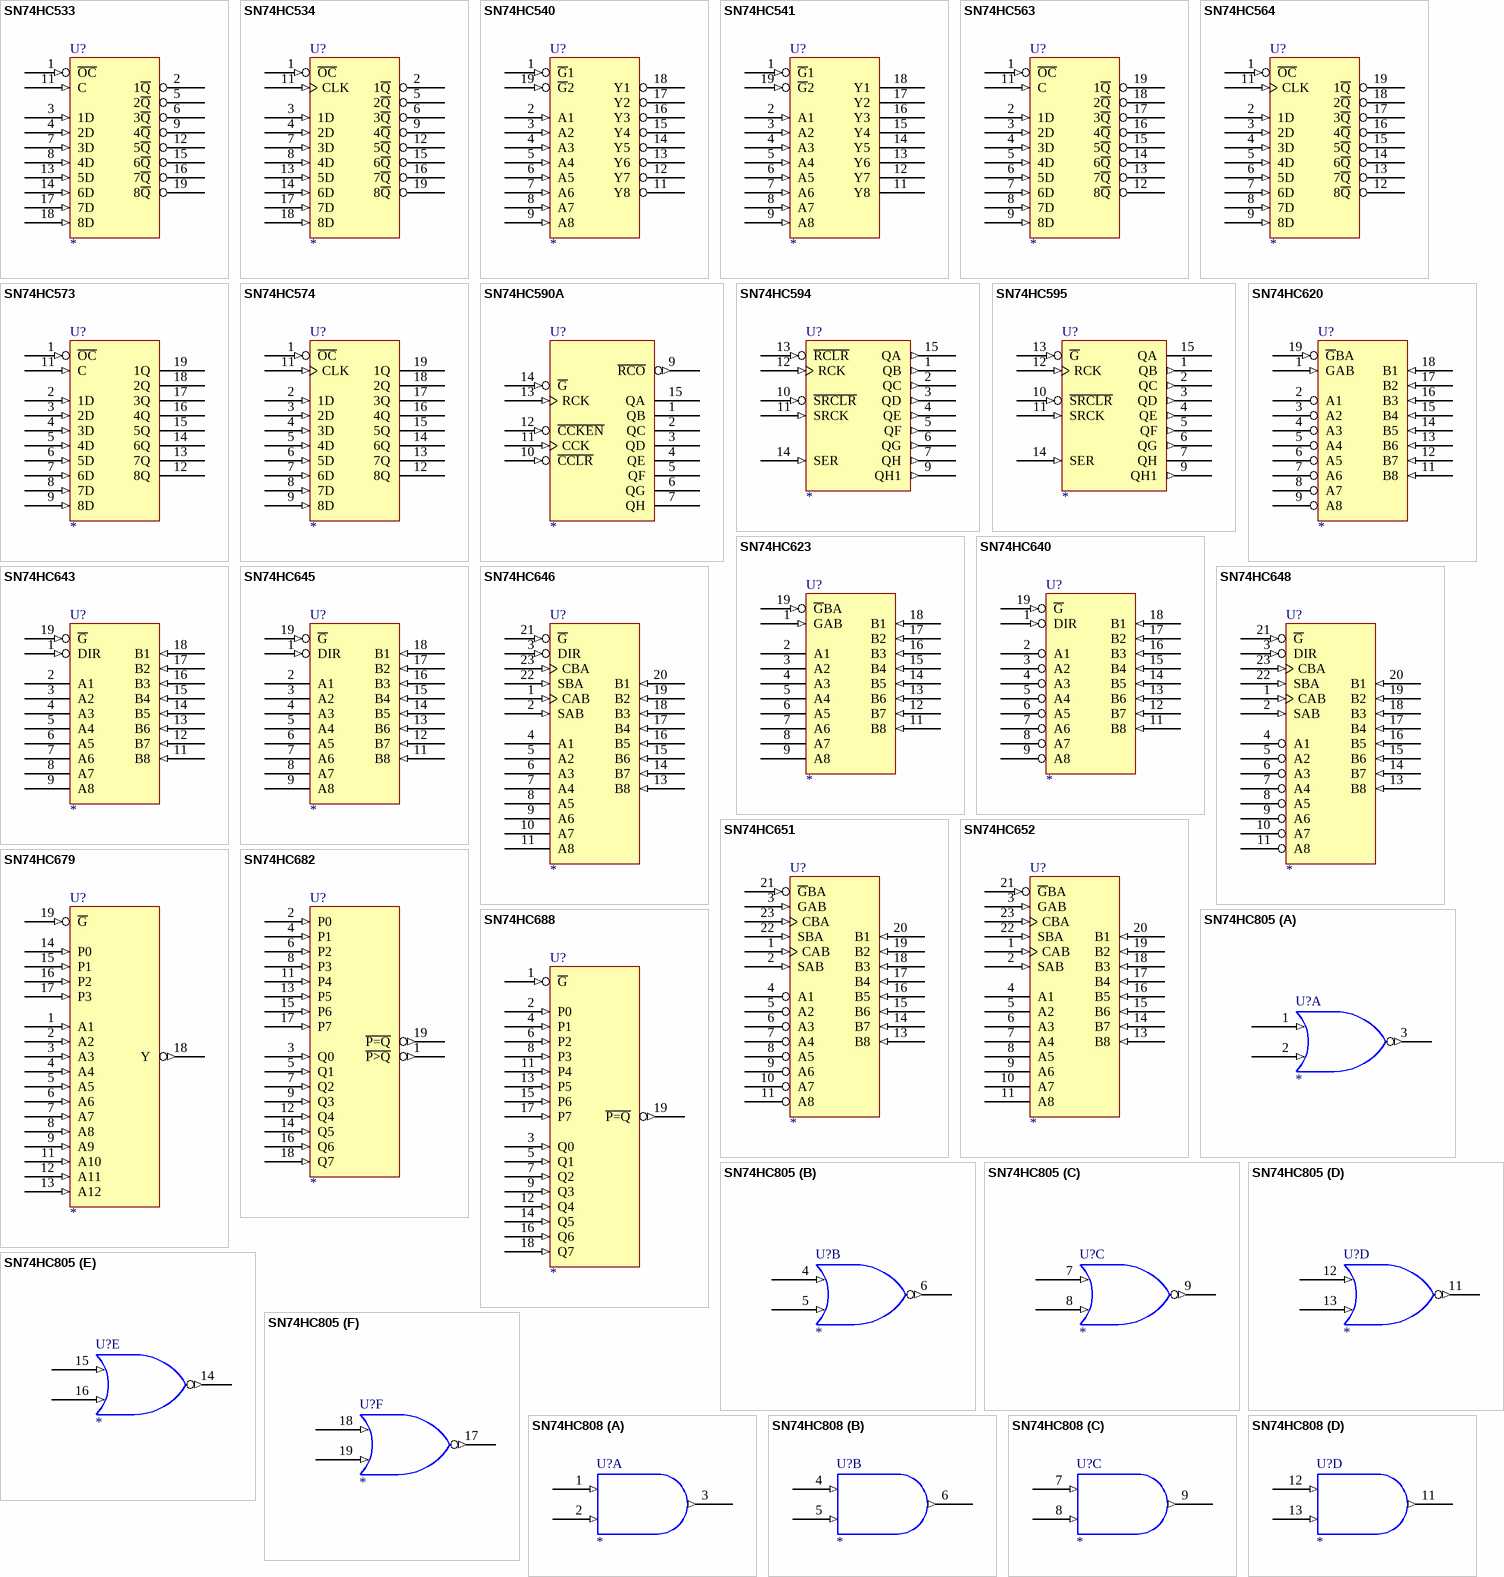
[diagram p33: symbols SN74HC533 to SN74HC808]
## SN74HC682
designator U?
8-BIT MAGNITUDE/IDENTITY COMPARATOR
footprint SO20W
footprint DIP-20
pins: 1 ~{P>Q} (out), 2 P0 (in), 3 Q0 (in), 4 P1 (in), 5 Q1 (in), 6 P2 (in), 7 Q2 (in), 8 P3 (in), 9 Q3 (in), 10 GND (power) hidden to GND, 11 P4 (in), 12 Q4 (in), 13 P5 (in), 14 Q5 (in), 15 P6 (in), 16 Q6 (in), 17 P7 (in), 18 Q7 (in), 19 ~{P=Q} (out), 20 VCC (power) hidden to VCC
1 alternate drawing of the same symbol

## SN74HC688
designator U?
8-BIT IDENTITY COMPARATOR
footprint SO20W
footprint DIP-20
pins: 1 ~{G} (in), 2 P0 (in), 3 Q0 (in), 4 P1 (in), 5 Q1 (in), 6 P2 (in), 7 Q2 (in), 8 P3 (in), 9 Q3 (in), 10 GND (power) hidden to GND, 11 P4 (in), 12 Q4 (in), 13 P5 (in), 14 Q5 (in), 15 P6 (in), 16 Q6 (in), 17 P7 (in), 18 Q7 (in), 19 ~{P=Q} (out), 20 VCC (power) hidden to VCC
1 alternate drawing of the same symbol

## SN74HC805
designator U?
HEX 2-IN NOR DRIVERS
footprint SO20W
footprint DIP-20
part A pins: 1 (in), 2 (in), 3 (out), 10 GND (power) hidden to GND, 20 VCC (power) hidden to VCC
part B pins: 4 (in), 5 (in), 6 (out), 10 GND (power) hidden to GND, 20 VCC (power) hidden to VCC
part C pins: 7 (in), 8 (in), 9 (out), 10 GND (power) hidden to GND, 20 VCC (power) hidden to VCC
part D pins: 10 GND (power) hidden to GND, 11 (out), 12 (in), 13 (in), 20 VCC (power) hidden to VCC
part E pins: 10 GND (power) hidden to GND, 14 (out), 15 (in), 16 (in), 20 VCC (power) hidden to VCC
part F pins: 10 GND (power) hidden to GND, 17 (out), 18 (in), 19 (in), 20 VCC (power) hidden to VCC
2 alternate drawings of the same symbol


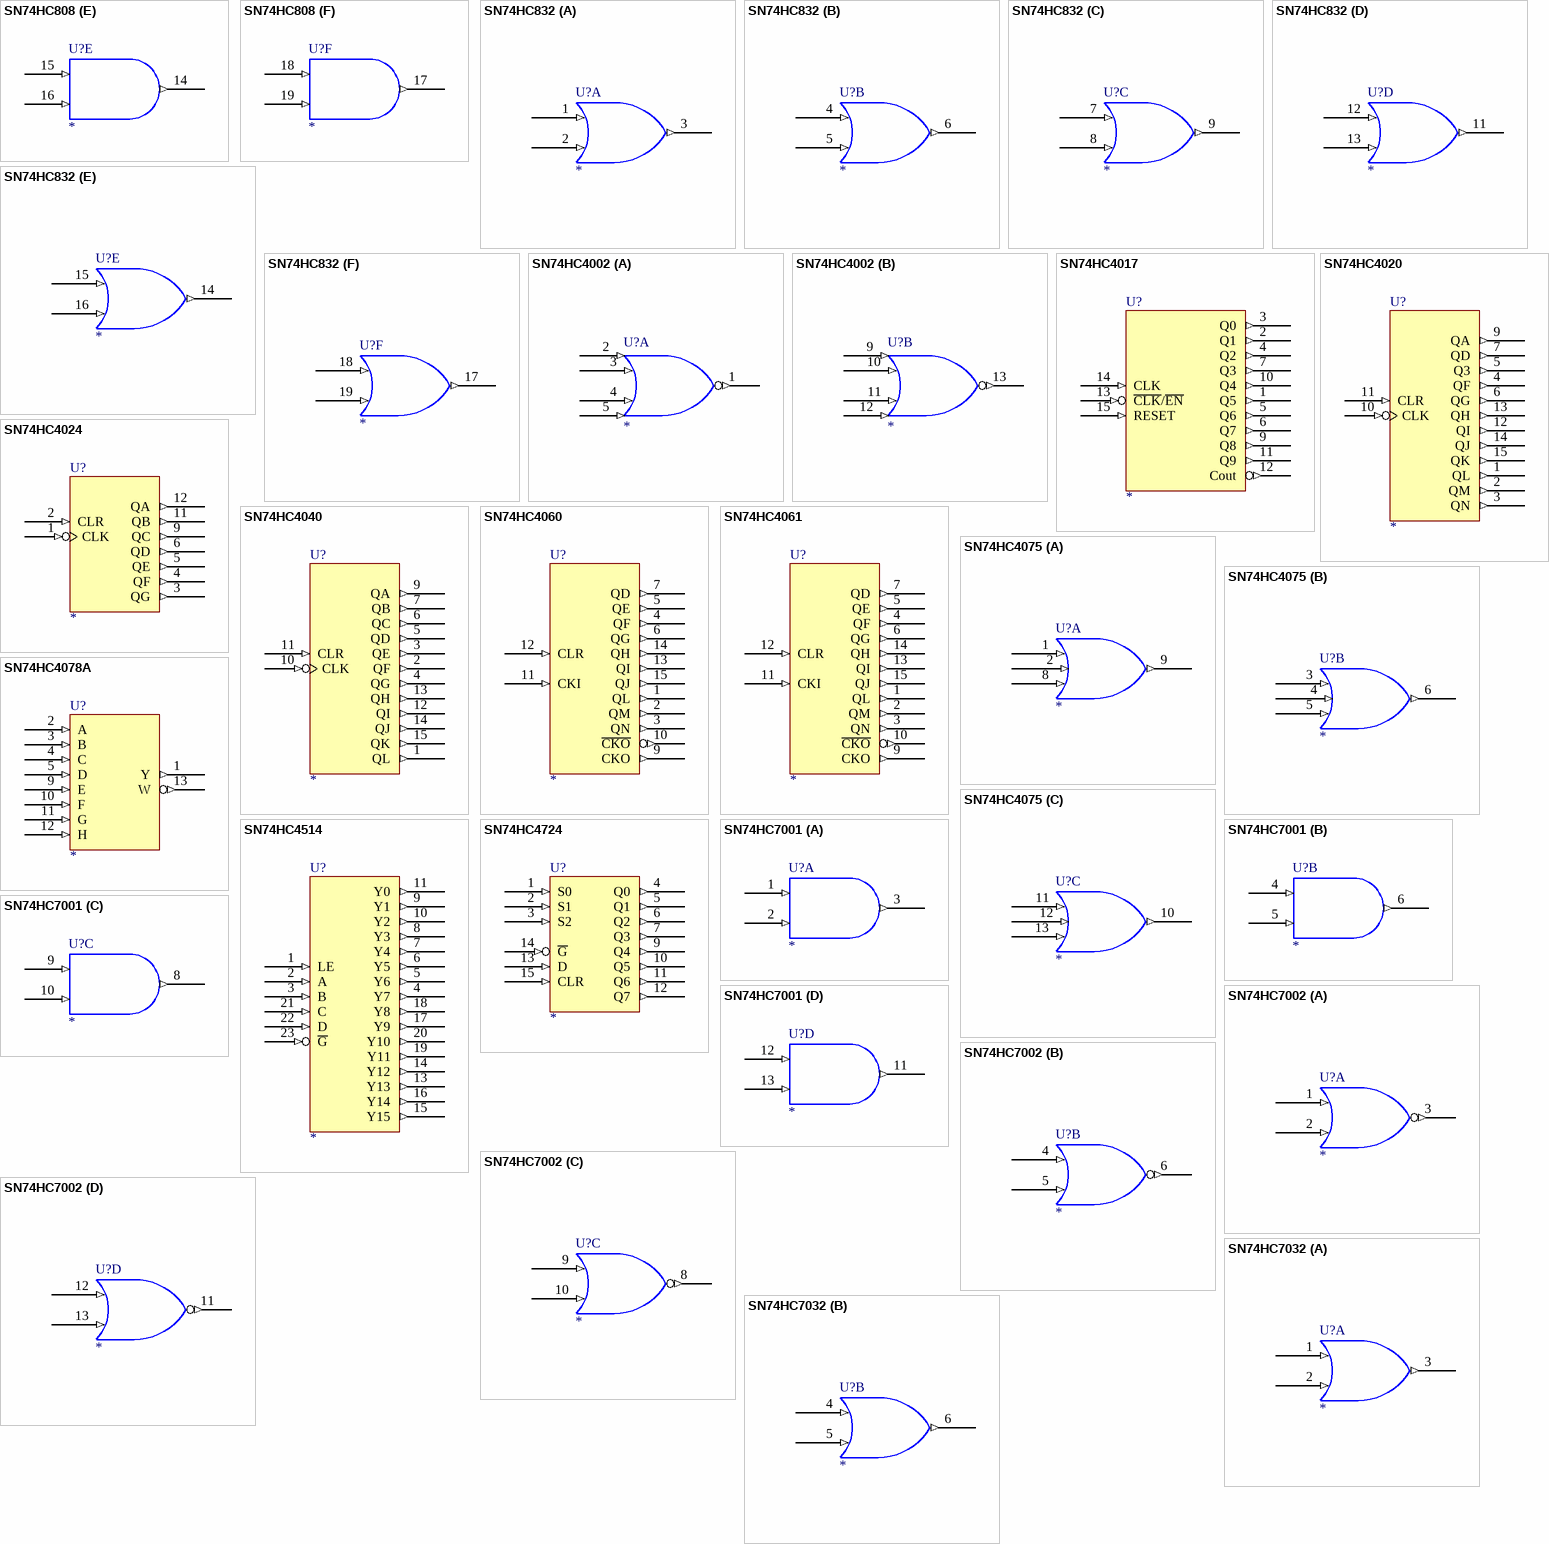
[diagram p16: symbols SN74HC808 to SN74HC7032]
## SN74HC808
designator U?
HEX 2-IN AND DRIVERS
footprint SO20W
footprint DIP-20
part A pins: 1 (in), 2 (in), 3 (out), 10 GND (power) hidden to GND, 20 VCC (power) hidden to VCC
part B pins: 4 (in), 5 (in), 6 (out), 10 GND (power) hidden to GND, 20 VCC (power) hidden to VCC
part C pins: 7 (in), 8 (in), 9 (out), 10 GND (power) hidden to GND, 20 VCC (power) hidden to VCC
part D pins: 10 GND (power) hidden to GND, 11 (out), 12 (in), 13 (in), 20 VCC (power) hidden to VCC
part E pins: 10 GND (power) hidden to GND, 14 (out), 15 (in), 16 (in), 20 VCC (power) hidden to VCC
part F pins: 10 GND (power) hidden to GND, 17 (out), 18 (in), 19 (in), 20 VCC (power) hidden to VCC
2 alternate drawings of the same symbol

## SN74HC832
designator U?
HEX 2-IN OR DRIVERS
footprint SO20W
footprint DIP-20
part A pins: 1 (in), 2 (in), 3 (out), 10 GND (power) hidden to GND, 20 VCC (power) hidden to VCC
part B pins: 4 (in), 5 (in), 6 (out), 10 GND (power) hidden to GND, 20 VCC (power) hidden to VCC
part C pins: 7 (in), 8 (in), 9 (out), 10 GND (power) hidden to GND, 20 VCC (power) hidden to VCC
part D pins: 10 GND (power) hidden to GND, 11 (out), 12 (in), 13 (in), 20 VCC (power) hidden to VCC
part E pins: 10 GND (power) hidden to GND, 14 (out), 15 (in), 16 (in), 20 VCC (power) hidden to VCC
part F pins: 10 GND (power) hidden to GND, 17 (out), 18 (in), 19 (in), 20 VCC (power) hidden to VCC
2 alternate drawings of the same symbol

## SN74HC4002
designator U?
Dual 4-INPUT NOR GATE
footprint SO14
footprint DIP-14
part A pins: 1 (out), 2 (in), 3 (in), 4 (in), 5 (in), 7 GND (power) hidden to GND, 14 VCC (power) hidden to VCC
part B pins: 7 GND (power) hidden to GND, 9 (in), 10 (in), 11 (in), 12 (in), 13 (out), 14 VCC (power) hidden to VCC
2 alternate drawings of the same symbol

## SN74HC4017
designator U?
DECADE COUNTER/DIVIDER
footprint DIP-16
pins: 1 Q5 (out), 2 Q1 (out), 3 Q0 (out), 4 Q2 (out), 5 Q6 (out), 6 Q7 (out), 7 Q3 (out), 8 GND (power) hidden to GND, 9 Q8 (out), 10 Q4 (out), 11 Q9 (out), 12 Cout (out), 13 ~{CLK}/~{EN} (in), 14 CLK (in), 15 RESET (in), 16 VCC (power) hidden to VCC
1 alternate drawing of the same symbol

## SN74HC4020
designator U?
14-BIT BINARY COUNTER
footprint SO16
footprint DIP-16
pins: 1 QL (out), 2 QM (out), 3 QN (out), 4 QF (out), 5 Q3 (out), 6 QG (out), 7 QD (out), 8 GND (power) hidden to GND, 9 QA (out), 10 CLK (in), 11 CLR (in), 12 QI (out), 13 QH (out), 14 QJ (out), 15 QK (out), 16 VCC (power) hidden to VCC
1 alternate drawing of the same symbol

## SN74HC4024
designator U?
ASYNCHRONOUS 7-BIT BINARY COUNTERS
footprint SO14
footprint DIP-14
pins: 1 CLK (in), 2 CLR (in), 3 QG (out), 4 QF (out), 5 QE (out), 6 QD (out), 7 GND (power) hidden to GND, 9 QC (out), 11 QB (out), 12 QA (out), 14 VCC (power) hidden to VCC
1 alternate drawing of the same symbol

## SN74HC4040
designator U?
ASYNCHRONOUS 12-BIT BINARY COUNTERS
footprint SO16
footprint DIP-16
pins: 1 QL (out), 2 QF (out), 3 QE (out), 4 QG (out), 5 QD (out), 6 QC (out), 7 QB (out), 8 GND (power) hidden to GND, 9 QA (out), 10 CLK (in), 11 CLR (in), 12 QI (out), 13 QH (out), 14 QJ (out), 15 QK (out), 16 VCC (power) hidden to VCC
1 alternate drawing of the same symbol

## SN74HC4060
designator U?
ASYNCHRONOUS 14-STAGE BINARY COUNTERS AND OSCILATORS
footprint SO16
footprint DIP-16
pins: 1 QL (out), 2 QM (out), 3 QN (out), 4 QF (out), 5 QE (out), 6 QG (out), 7 QD (out), 8 GND (power) hidden to GND, 9 CKO (out), 10 ~{CKO} (out), 11 CKI (in), 12 CLR (in), 13 QI (out), 14 QH (out), 15 QJ (out), 16 VCC (power) hidden to VCC
1 alternate drawing of the same symbol

## SN74HC4061
designator U?
ASYNCHRONOUS 14-STAGE BINARY COUNTERS AND OSCILATORS
footprint SO16
footprint DIP-16
pins: 1 QL (out), 2 QM (out), 3 QN (out), 4 QF (out), 5 QE (out), 6 QG (out), 7 QD (out), 8 GND (power) hidden to GND, 9 CKO (out), 10 ~{CKO} (out), 11 CKI (in), 12 CLR (in), 13 QI (out), 14 QH (out), 15 QJ (out), 16 VCC (power) hidden to VCC
1 alternate drawing of the same symbol

## SN74HC4075
designator U?
TRIPLE 3-INPUT OR GATE
footprint SO14
footprint DIP-14
part A pins: 1 (in), 2 (in), 7 GND (power) hidden to GND, 8 (in), 9 (out), 14 VCC (power) hidden to VCC
part B pins: 3 (in), 4 (in), 5 (in), 6 (out), 7 GND (power) hidden to GND, 14 VCC (power) hidden to VCC
part C pins: 7 GND (power) hidden to GND, 10 (out), 11 (in), 12 (in), 13 (in), 14 VCC (power) hidden to VCC
2 alternate drawings of the same symbol

## SN74HC4078A
designator U?
8-INPUT OR/NOR GATE
footprint SO14
footprint DIP-14
pins: 1 Y (out), 2 A (in), 3 B (in), 4 C (in), 5 D (in), 7 GND (power) hidden to GND, 9 E (in), 10 F (in), 11 G (in), 12 H (in), 13 W (out), 14 VCC (power) hidden to VCC
1 alternate drawing of the same symbol

## SN74HC4514
designator U?
4-LINE TO 16-LINE DECODER/DEMULTIPLEXERS WITH ADDRESS LATCHES
footprint SO24W
footprint DIP-24
pins: 1 LE (in), 2 A (in), 3 B (in), 4 Y7 (out), 5 Y6 (out), 6 Y5 (out), 7 Y4 (out), 8 Y3 (out), 9 Y1 (out), 10 Y2 (out), 11 Y0 (out), 12 GND (power) hidden to GND, 13 Y13 (out), 14 Y12 (out), 15 Y15 (out), 16 Y14 (out), 17 Y9 (out), 18 Y8 (out), 19 Y11 (out), 20 Y10 (out), 21 C (in), 22 D (in), 23 ~{G} (in), 24 VCC (power) hidden to VCC
1 alternate drawing of the same symbol

## SN74HC4724
designator U?
8-BIT ADDRESSABLE LARCHES
footprint DIP-16
pins: 1 S0 (in), 2 S1 (in), 3 S2 (in), 4 Q0 (out), 5 Q1 (out), 6 Q2 (out), 7 Q3 (out), 8 GND (power) hidden to GND, 9 Q4 (out), 10 Q5 (out), 11 Q6 (out), 12 Q7 (out), 13 D (in), 14 ~{G} (in), 15 CLR (in), 16 VCC (power) hidden to VCC
1 alternate drawing of the same symbol

## SN74HC7001
designator U?
Quad 2-IN Pos AND G SCH INPUTS
footprint SO14
footprint DIP-14
part A pins: 1 (in), 2 (in), 3 (out), 7 GND (power) hidden to GND, 14 VCC (power) hidden to VCC
part B pins: 4 (in), 5 (in), 6 (out), 7 GND (power) hidden to GND, 14 VCC (power) hidden to VCC
part C pins: 7 GND (power) hidden to GND, 8 (out), 9 (in), 10 (in), 14 VCC (power) hidden to VCC
part D pins: 7 GND (power) hidden to GND, 11 (out), 12 (in), 13 (in), 14 VCC (power) hidden to VCC
2 alternate drawings of the same symbol

## SN74HC7002
designator U?
Quad 2-IN Pos NOR G SCH INPUTS
footprint SO14
footprint DIP-14
part A pins: 1 (in), 2 (in), 3 (out), 7 GND (power) hidden to GND, 14 VCC (power) hidden to VCC
part B pins: 4 (in), 5 (in), 6 (out), 7 GND (power) hidden to GND, 14 VCC (power) hidden to VCC
part C pins: 7 GND (power) hidden to GND, 8 (out), 9 (in), 10 (in), 14 VCC (power) hidden to VCC
part D pins: 7 GND (power) hidden to GND, 11 (out), 12 (in), 13 (in), 14 VCC (power) hidden to VCC
2 alternate drawings of the same symbol


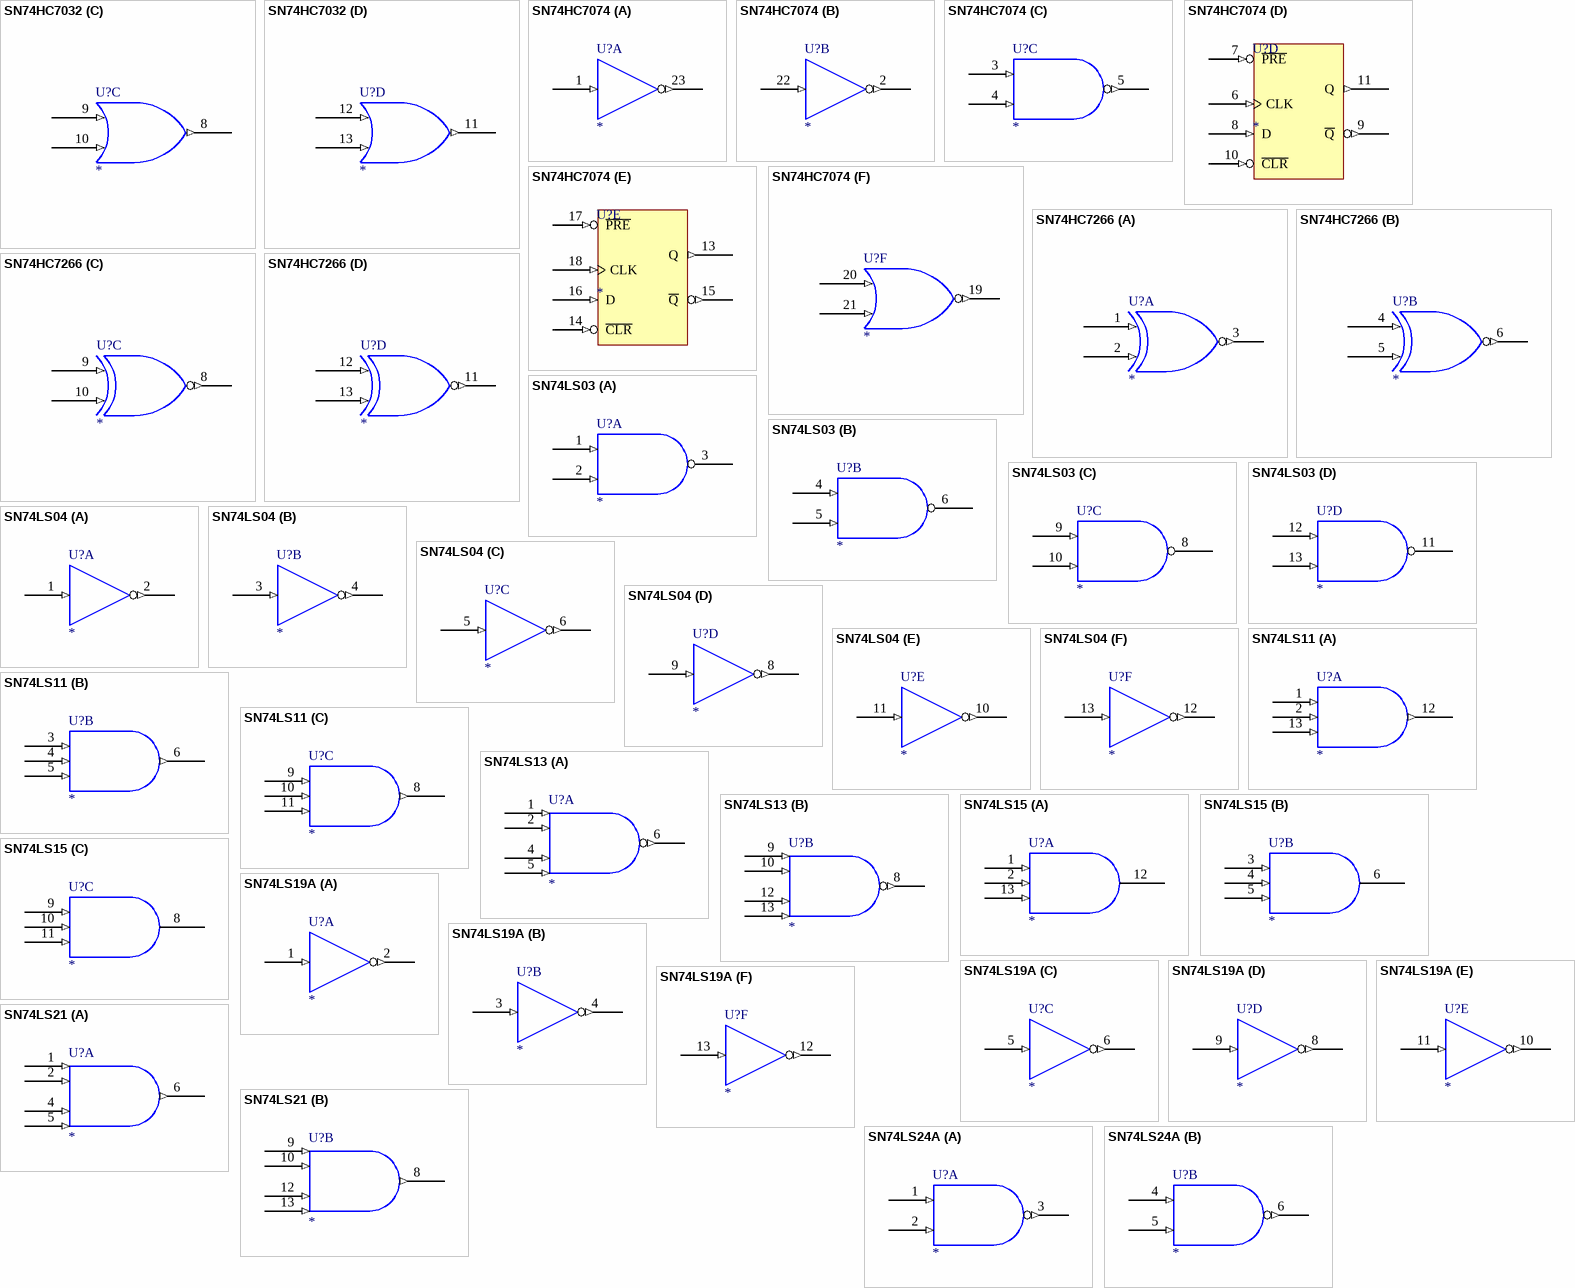
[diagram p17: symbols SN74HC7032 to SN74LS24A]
## SN74HC7032
designator U?
Quad 2-IN Pos OR G SCH INPUTS
footprint SO14
footprint DIP-14
part A pins: 1 (in), 2 (in), 3 (out), 7 GND (power) hidden to GND, 14 VCC (power) hidden to VCC
part B pins: 4 (in), 5 (in), 6 (out), 7 GND (power) hidden to GND, 14 VCC (power) hidden to VCC
part C pins: 7 GND (power) hidden to GND, 8 (out), 9 (in), 10 (in), 14 VCC (power) hidden to VCC
part D pins: 7 GND (power) hidden to GND, 11 (out), 12 (in), 13 (in), 14 VCC (power) hidden to VCC
2 alternate drawings of the same symbol

## SN74HC7074
designator U?
6-SECTION MULTIFUNCTION NAND INVERT NOR FF
footprint SO24W
footprint DIP-24
part A pins: 1 (in), 12 GND (power) hidden to GND, 23 (out), 24 VCC (power) hidden to VCC
part B pins: 2 (out), 12 GND (power) hidden to GND, 22 (in), 24 VCC (power) hidden to VCC
part C pins: 3 (in), 4 (in), 5 (out), 12 GND (power) hidden to GND, 24 VCC (power) hidden to VCC
part D pins: 6 CLK (in), 7 ~{PRE} (in), 8 D (in), 9 ~{Q} (out), 10 ~{CLR} (in), 11 Q (out), 12 GND (power) hidden to GND, 24 VCC (power) hidden to VCC
part E pins: 12 GND (power) hidden to GND, 13 Q (out), 14 ~{CLR} (in), 15 ~{Q} (out), 16 D (in), 17 ~{PRE} (in), 18 CLK (in), 24 VCC (power) hidden to VCC
part F pins: 12 GND (power) hidden to GND, 19 (out), 20 (in), 21 (in), 24 VCC (power) hidden to VCC
2 alternate drawings of the same symbol

## SN74HC7266
designator U?
QUAD 2-IN XNOR G
footprint SO14
footprint DIP-14
part A pins: 1 (in), 2 (in), 3 (out), 7 GND (power) hidden to GND, 14 VCC (power) hidden to VCC
part B pins: 4 (in), 5 (in), 6 (out), 7 GND (power) hidden to GND, 14 VCC (power) hidden to VCC
part C pins: 7 GND (power) hidden to GND, 8 (out), 9 (in), 10 (in), 14 VCC (power) hidden to VCC
part D pins: 7 GND (power) hidden to GND, 11 (out), 12 (in), 13 (in), 14 VCC (power) hidden to VCC
1 alternate drawing of the same symbol

## SN74LS03
designator U?
Quad 2-IN Pos Nand G OCO
footprint SO14
footprint DIP-14
part A pins: 1 (in), 2 (in), 3 (oc), 7 GND (power) hidden to GND, 14 VCC (power) hidden to VCC
part B pins: 4 (in), 5 (in), 6 (oc), 7 GND (power) hidden to GND, 14 VCC (power) hidden to VCC
part C pins: 7 GND (power) hidden to GND, 8 (oc), 9 (in), 10 (in), 14 VCC (power) hidden to VCC
part D pins: 7 GND (power) hidden to GND, 11 (oc), 12 (in), 13 (in), 14 VCC (power) hidden to VCC
2 alternate drawings of the same symbol

## SN74LS04
designator U?
Hex Inverters
footprint SO14
footprint DIP-14
part A pins: 1 (in), 2 (out), 7 GND (power) hidden to GND, 14 VCC (power) hidden to VCC
part B pins: 3 (in), 4 (out), 7 GND (power) hidden to GND, 14 VCC (power) hidden to VCC
part C pins: 5 (in), 6 (out), 7 GND (power) hidden to GND, 14 VCC (power) hidden to VCC
part D pins: 7 GND (power) hidden to GND, 8 (out), 9 (in), 14 VCC (power) hidden to VCC
part E pins: 7 GND (power) hidden to GND, 10 (out), 11 (in), 14 VCC (power) hidden to VCC
part F pins: 7 GND (power) hidden to GND, 12 (out), 13 (in), 14 VCC (power) hidden to VCC
2 alternate drawings of the same symbol

## SN74LS11
designator U?
Triple 3-IN Pos And G
footprint SO14
footprint DIP-14
part A pins: 1 (in), 2 (in), 7 GND (power) hidden to GND, 12 (out), 13 (in), 14 VCC (power) hidden to VCC
part B pins: 3 (in), 4 (in), 5 (in), 6 (out), 7 GND (power) hidden to GND, 14 VCC (power) hidden to VCC
part C pins: 7 GND (power) hidden to GND, 8 (out), 9 (in), 10 (in), 11 (in), 14 VCC (power) hidden to VCC
2 alternate drawings of the same symbol

## SN74LS13
designator U?
Dual 4-IN Pos Nand G SCH
footprint SO14
footprint DIP-14
part A pins: 1 (in), 2 (in), 4 (in), 5 (in), 6 (out), 7 GND (power) hidden to GND, 14 VCC (power) hidden to VCC
part B pins: 7 GND (power) hidden to GND, 8 (out), 9 (in), 10 (in), 12 (in), 13 (in), 14 VCC (power) hidden to VCC
2 alternate drawings of the same symbol

## SN74LS15
designator U?
Triple 3-IN Pos And G OCO
footprint SO14
footprint DIP-14
part A pins: 1 (in), 2 (in), 7 GND (power) hidden to GND, 12 (oc), 13 (in), 14 VCC (power) hidden to VCC
part B pins: 3 (in), 4 (in), 5 (in), 6 (oc), 7 GND (power) hidden to GND, 14 VCC (power) hidden to VCC
part C pins: 7 GND (power) hidden to GND, 8 (oc), 9 (in), 10 (in), 11 (in), 14 VCC (power) hidden to VCC
2 alternate drawings of the same symbol

## SN74LS19A
designator U?
Hex Inverter Totem
footprint SO14
footprint DIP-14
part A pins: 1 (in), 2 (out), 7 GND (power) hidden to GND, 14 VCC (power) hidden to VCC
part B pins: 3 (in), 4 (out), 7 GND (power) hidden to GND, 14 VCC (power) hidden to VCC
part C pins: 5 (in), 6 (out), 7 GND (power) hidden to GND, 14 VCC (power) hidden to VCC
part D pins: 7 GND (power) hidden to GND, 8 (out), 9 (in), 14 VCC (power) hidden to VCC
part E pins: 7 GND (power) hidden to GND, 10 (out), 11 (in), 14 VCC (power) hidden to VCC
part F pins: 7 GND (power) hidden to GND, 12 (out), 13 (in), 14 VCC (power) hidden to VCC
2 alternate drawings of the same symbol

## SN74LS21
designator U?
Dual 4-IN Pos And G
footprint SO14
footprint DIP-14
part A pins: 1 (in), 2 (in), 4 (in), 5 (in), 6 (out), 7 GND (power) hidden to GND, 14 VCC (power) hidden to VCC
part B pins: 7 GND (power) hidden to GND, 8 (out), 9 (in), 10 (in), 12 (in), 13 (in), 14 VCC (power) hidden to VCC
2 alternate drawings of the same symbol


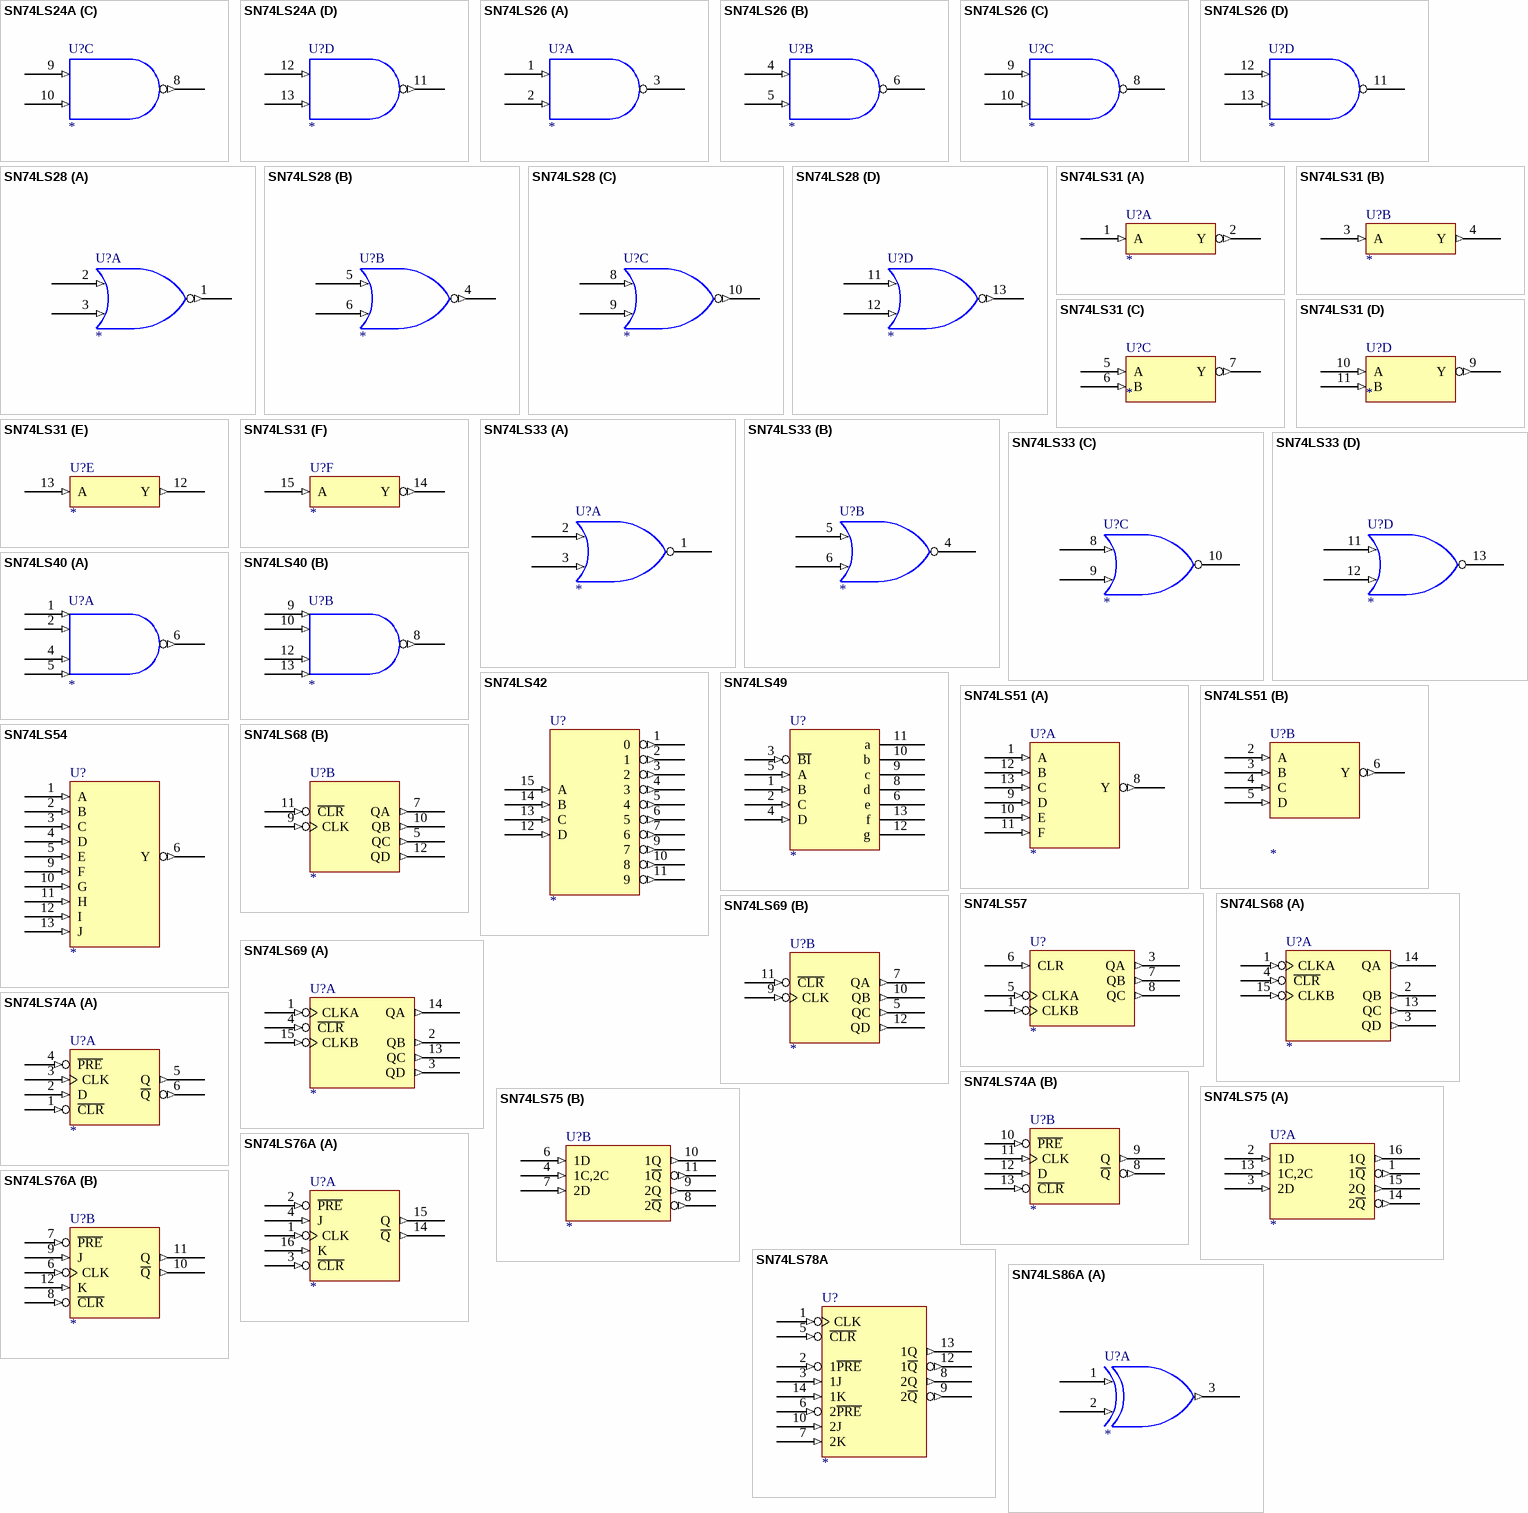
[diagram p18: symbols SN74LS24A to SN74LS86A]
## SN74LS24A
designator U?
Quad 2-IN Pos Nand G SCH totem
footprint SO14
footprint DIP-14
part A pins: 1 (in), 2 (in), 3 (out), 7 GND (power) hidden to GND, 14 VCC (power) hidden to VCC
part B pins: 4 (in), 5 (in), 6 (out), 7 GND (power) hidden to GND, 14 VCC (power) hidden to VCC
part C pins: 7 GND (power) hidden to GND, 8 (out), 9 (in), 10 (in), 14 VCC (power) hidden to VCC
part D pins: 7 GND (power) hidden to GND, 11 (out), 12 (in), 13 (in), 14 VCC (power) hidden to VCC
2 alternate drawings of the same symbol

## SN74LS26
designator U?
Quad 2-IN Pos Nand G HV INTF
footprint SO14
footprint DIP-14
part A pins: 1 (in), 2 (in), 3 (oc), 7 GND (power) hidden to GND, 14 VCC (power) hidden to VCC
part B pins: 4 (in), 5 (in), 6 (oc), 7 GND (power) hidden to GND, 14 VCC (power) hidden to VCC
part C pins: 7 GND (power) hidden to GND, 8 (oc), 9 (in), 10 (in), 14 VCC (power) hidden to VCC
part D pins: 7 GND (power) hidden to GND, 11 (oc), 12 (in), 13 (in), 14 VCC (power) hidden to VCC
2 alternate drawings of the same symbol

## SN74LS28
designator U?
Quad 2-IN Pos Nor G BUF
footprint SO14
footprint DIP-14
part A pins: 1 (out), 2 (in), 3 (in), 7 GND (power) hidden to GND, 14 VCC (power) hidden to VCC
part B pins: 4 (out), 5 (in), 6 (in), 7 GND (power) hidden to GND, 14 VCC (power) hidden to VCC
part C pins: 7 GND (power) hidden to GND, 8 (in), 9 (in), 10 (out), 14 VCC (power) hidden to VCC
part D pins: 7 GND (power) hidden to GND, 11 (in), 12 (in), 13 (out), 14 VCC (power) hidden to VCC
2 alternate drawings of the same symbol

## SN74LS31
designator U?
Delay Elements
footprint SO16
footprint DIP-16
part A pins: 1 A (in), 2 Y (out), 8 GND (power) hidden to GND, 16 VCC (power) hidden to VCC
part B pins: 3 A (in), 4 Y (out), 8 GND (power) hidden to GND, 16 VCC (power) hidden to VCC
part C pins: 5 A (in), 6 B (in), 7 Y (out), 8 GND (power) hidden to GND, 16 VCC (power) hidden to VCC
part D pins: 8 GND (power) hidden to GND, 9 Y (out), 10 A (in), 11 B (in), 16 VCC (power) hidden to VCC
part E pins: 8 GND (power) hidden to GND, 12 Y (out), 13 A (in), 16 VCC (power) hidden to VCC
part F pins: 8 GND (power) hidden to GND, 14 Y (out), 15 A (in), 16 VCC (power) hidden to VCC
1 alternate drawing of the same symbol

## SN74LS33
designator U?
Quad 2-IN Pos Nor G BUF OCO
footprint SO14
footprint DIP-14
part A pins: 1 (oc), 2 (in), 3 (in), 7 GND (power) hidden to GND, 14 VCC (power) hidden to VCC
part B pins: 4 (oc), 5 (in), 6 (in), 7 GND (power) hidden to GND, 14 VCC (power) hidden to VCC
part C pins: 7 GND (power) hidden to GND, 8 (in), 9 (in), 10 (oc), 14 VCC (power) hidden to VCC
part D pins: 7 GND (power) hidden to GND, 11 (in), 12 (in), 13 (oc), 14 VCC (power) hidden to VCC
2 alternate drawings of the same symbol

## SN74LS40
designator U?
Dual 4-in Pos Nand G BUF
footprint SO14
footprint DIP-14
part A pins: 1 (in), 2 (in), 4 (in), 5 (in), 6 (out), 7 GND (power) hidden to GND, 14 VCC (power) hidden to VCC
part B pins: 7 GND (power) hidden to GND, 8 (out), 9 (in), 10 (in), 12 (in), 13 (in), 14 VCC (power) hidden to VCC
2 alternate drawings of the same symbol

## SN74LS42
designator U?
4-line BCD to 10-line decimal Dec
footprint SO16
footprint DIP-16
pins: 1 0 (out), 2 1 (out), 3 2 (out), 4 3 (out), 5 4 (out), 6 5 (out), 7 6 (out), 8 GND (power) hidden to GND, 9 7 (out), 10 8 (out), 11 9 (out), 12 D (in), 13 C (in), 14 B (in), 15 A (in), 16 VCC (power) hidden to VCC
1 alternate drawing of the same symbol

## SN74LS49
designator U?
BCD-To-SEVEN-SEGMENT DEC DRV
footprint SO14
footprint DIP-14
pins: 1 B (in), 2 C (in), 3 ~{BI} (in), 4 D (in), 5 A (in), 6 e (oc), 7 GND (power) hidden to GND, 8 d (oc), 9 c (oc), 10 b (oc), 11 a (oc), 12 g (oc), 13 f (oc), 14 VCC (power) hidden to VCC
1 alternate drawing of the same symbol

## SN74LS51
designator U?
DUAL 2-WIDE 2&3-IN AND-OR-INVERT G
footprint SO14
footprint DIP-14
part A pins: 1 A (in), 7 GND (power) hidden to GND, 8 Y (out), 9 D (in), 10 E (in), 11 F (in), 12 B (in), 13 C (in), 14 VCC (power) hidden to VCC
part B pins: 2 A (in), 3 B (in), 4 C (in), 5 D (in), 6 Y (out), 7 GND (power) hidden to GND, 14 VCC (power) hidden to VCC
1 alternate drawing of the same symbol

## SN74LS54
designator U?
4-WIDE 2-IN AND-OR-INVERT G
footprint SO14
footprint DIP-14
pins: 1 A (in), 2 B (in), 3 C (in), 4 D (in), 5 E (in), 6 Y (out), 7 GND (power) hidden to GND, 9 F (in), 10 G (in), 11 H (in), 12 I (in), 13 J (in), 14 VCC (power) hidden to VCC
1 alternate drawing of the same symbol

## SN74LS57
designator U?
FREQUENCY DIVIDERS
footprint DIP-8
pins: 1 CLKB (in), 2 VCC (power) hidden to VCC, 3 QA (out), 4 GND (power) hidden to GND, 5 CLKA (in), 6 CLR (in), 7 QB (out), 8 QC (out)
1 alternate drawing of the same symbol

## SN74LS68
designator U?
DUAL 4-BIT DECADE OR BINARY CNT
footprint SO16
footprint DIP-16
part A pins: 1 CLKA (in), 2 QB (out), 3 QD (out), 4 ~{CLR} (in), 8 GND (power) hidden to GND, 13 QC (out), 14 QA (out), 15 CLKB (in), 16 VCC (power) hidden to VCC
part B pins: 5 QC (out), 7 QA (out), 8 GND (power) hidden to GND, 9 CLK (in), 10 QB (out), 11 ~{CLR} (in), 12 QD (out), 16 VCC (power) hidden to VCC
1 alternate drawing of the same symbol

## SN74LS69
designator U?
DUAL 4-BIT DECADE OR BINARY CNT
footprint SO16
footprint DIP-16
part A pins: 1 CLKA (in), 2 QB (out), 3 QD (out), 4 ~{CLR} (in), 8 GND (power) hidden to GND, 13 QC (out), 14 QA (out), 15 CLKB (in), 16 VCC (power) hidden to VCC
part B pins: 5 QC (out), 7 QA (out), 8 GND (power) hidden to GND, 9 CLK (in), 10 QB (out), 11 ~{CLR} (in), 12 QD (out), 16 VCC (power) hidden to VCC
1 alternate drawing of the same symbol

## SN74LS74A
designator U?
DUAL D PET FF RS CR
footprint SO14
footprint DIP-14
part A pins: 1 ~{CLR} (in), 2 D (in), 3 CLK (in), 4 ~{PRE} (in), 5 Q (out), 6 ~{Q} (out), 7 GND (power) hidden to GND, 14 VCC (power) hidden to VCC
part B pins: 7 GND (power) hidden to GND, 8 ~{Q} (out), 9 Q (out), 10 ~{PRE} (in), 11 CLK (in), 12 D (in), 13 ~{CLR} (in), 14 VCC (power) hidden to VCC
1 alternate drawing of the same symbol

## SN74LS75
designator U?
4-BIT BISTABLE LCH
footprint SO16
footprint DIP-16
part A pins: 1 1~{Q} (out), 2 1D (in), 3 2D (in), 5 VCC (power) hidden to VCC, 12 GND (power) hidden to GND, 13 1C,2C (in), 14 2~{Q} (out), 15 2Q (out), 16 1Q (out)
part B pins: 4 1C,2C (in), 5 VCC (power) hidden to VCC, 6 1D (in), 7 2D (in), 8 2~{Q} (out), 9 2Q (out), 10 1Q (out), 11 1~{Q} (out), 12 GND (power) hidden to GND
1 alternate drawing of the same symbol

## SN74LS76A
designator U?
DUAL J-K NET FF RS CR
footprint SO16
footprint DIP-16
part A pins: 1 CLK (in), 2 ~{PRE} (in), 3 ~{CLR} (in), 4 J (in), 5 VCC (power) hidden to VCC, 13 GND (power) hidden to GND, 14 ~{Q} (out), 15 Q (out), 16 K (in)
part B pins: 5 VCC (power) hidden to VCC, 6 CLK (in), 7 ~{PRE} (in), 8 ~{CLR} (in), 9 J (in), 10 ~{Q} (out), 11 Q (out), 12 K (in), 13 GND (power) hidden to GND
1 alternate drawing of the same symbol

## SN74LS78A
designator U?
DUAL J-K FF RS COM CLK COM CR
footprint SO14
footprint DIP-14
pins: 1 CLK (in), 2 1~{PRE} (in), 3 1J (in), 4 VCC (power) hidden to VCC, 5 ~{CLR} (in), 6 2~{PRE} (in), 7 2K (in), 8 2Q (out), 9 2~{Q} (out), 10 2J (in), 11 GND (power) hidden to GND, 12 1~{Q} (out), 13 1Q (out), 14 1K (in)
1 alternate drawing of the same symbol


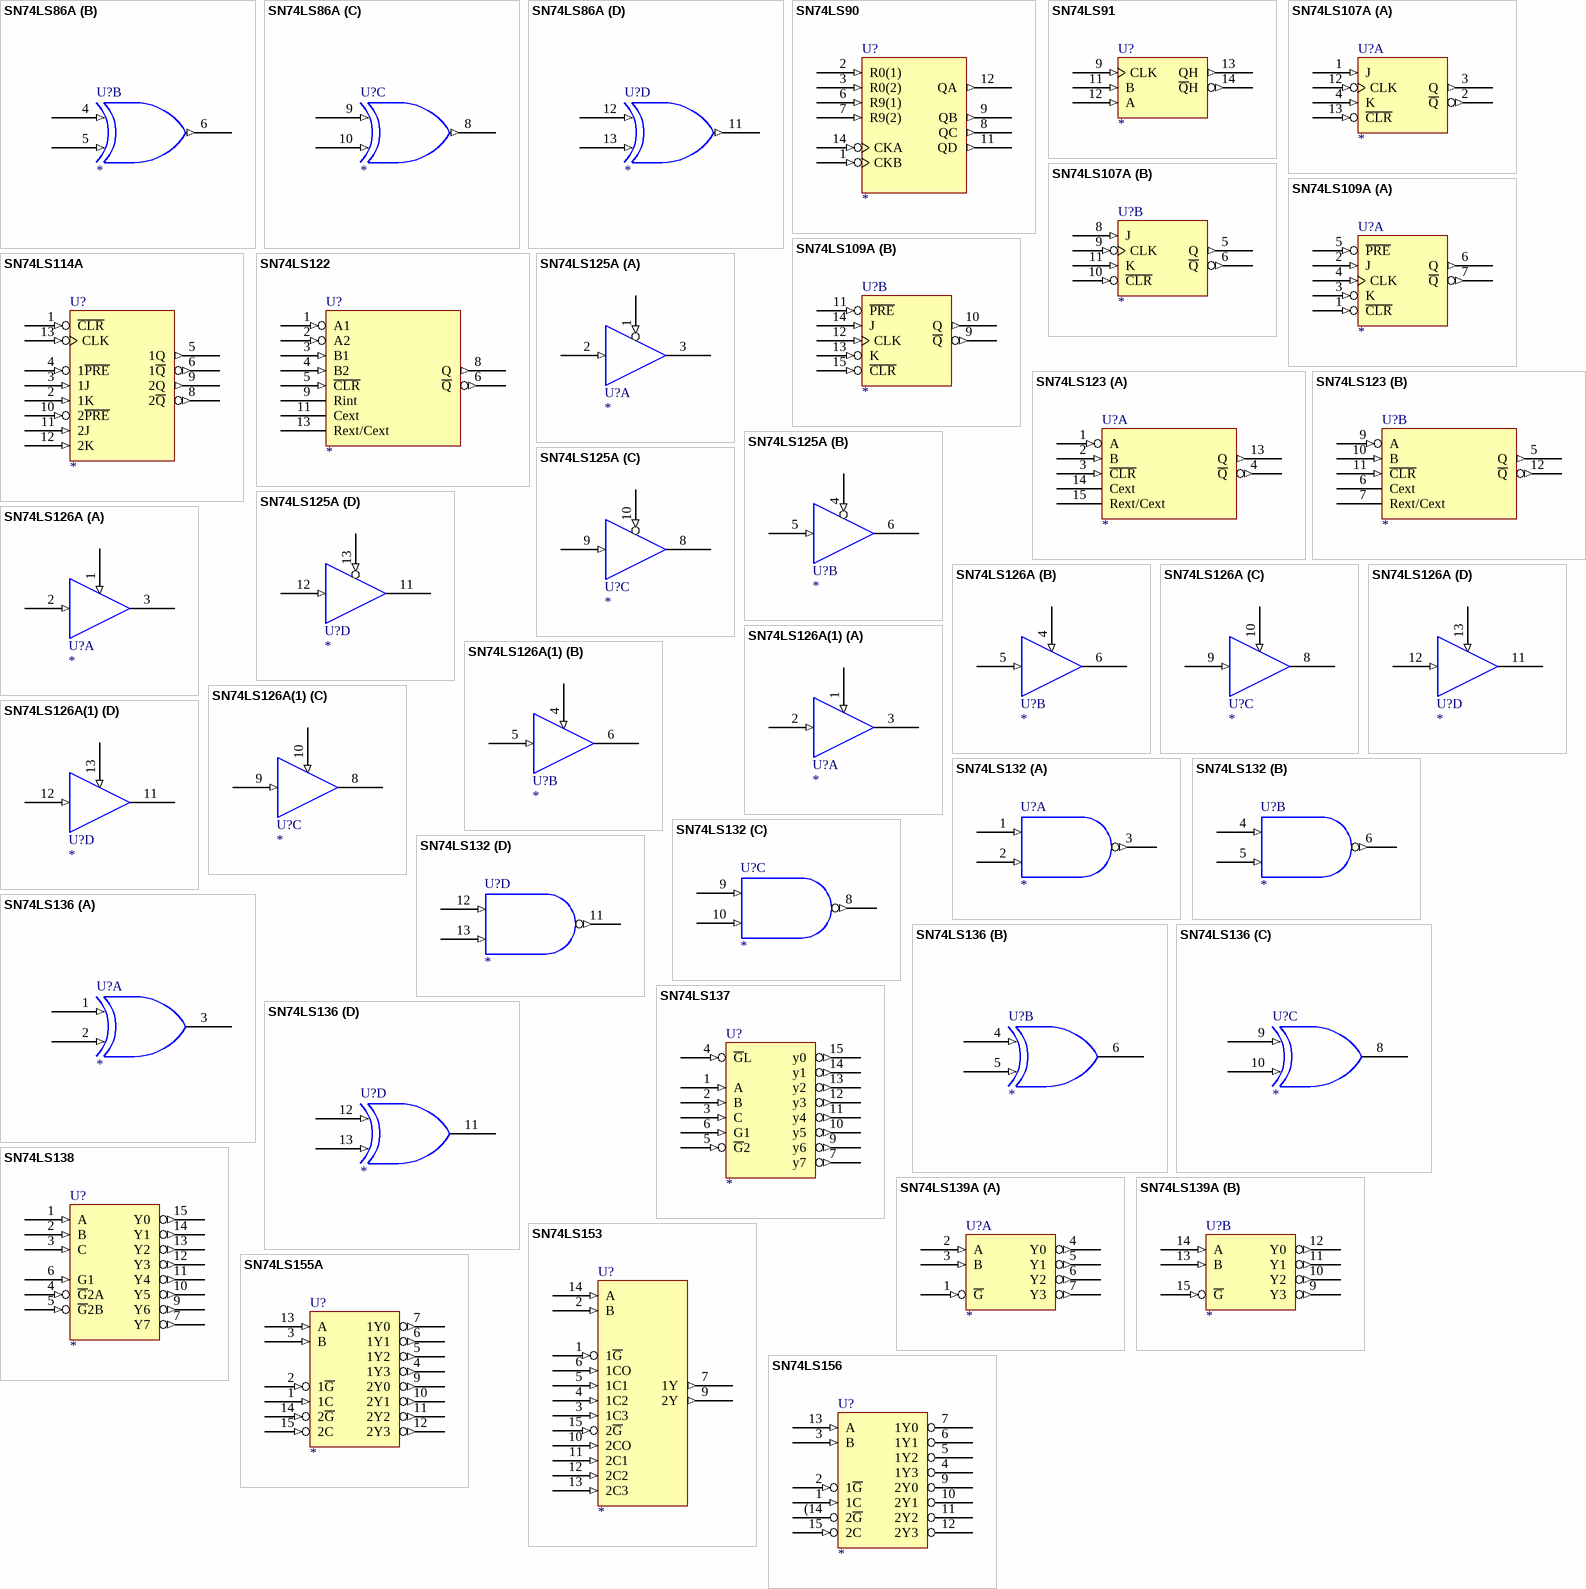
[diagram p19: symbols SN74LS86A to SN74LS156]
## SN74LS86A
designator U?
QUAD 2-IN XOR  G
footprint SO14
footprint DIP-14
part A pins: 1 (in), 2 (in), 3 (out), 7 GND (power) hidden to GND, 14 VCC (power) hidden to VCC
part B pins: 4 (in), 5 (in), 6 (out), 7 GND (power) hidden to GND, 14 VCC (power) hidden to VCC
part C pins: 7 GND (power) hidden to GND, 8 (out), 9 (in), 10 (in), 14 VCC (power) hidden to VCC
part D pins: 7 GND (power) hidden to GND, 11 (out), 12 (in), 13 (in), 14 VCC (power) hidden to VCC
1 alternate drawing of the same symbol

## SN74LS90
designator U?
DECADE DIV-BY-12 BIN CNT
footprint SO14
footprint DIP-14
pins: 1 CKB (in), 2 R0(1) (in), 3 R0(2) (in), 5 VCC (power) hidden to VCC, 6 R9(1) (in), 7 R9(2) (in), 8 QC (out), 9 QB (out), 10 GND (power) hidden to GND, 11 QD (out), 12 QA (out), 14 CKA (in)
1 alternate drawing of the same symbol

## SN74LS91
designator U?
8-BIT SHIFT REG
footprint SO14
footprint DIP-14
pins: 5 VCC (power) hidden to VCC, 9 CLK (in), 10 GND (power) hidden to GND, 11 B (in), 12 A (in), 13 QH (out), 14 ~{Q}H (out)
1 alternate drawing of the same symbol

## SN74LS107A
designator U?
DUAL J-K FF CR
footprint SO14
footprint DIP-14
part A pins: 1 J (in), 2 ~{Q} (out), 3 Q (out), 4 K (in), 7 GND (power) hidden to GND, 12 CLK (in), 13 ~{CLR} (in), 14 VCC (power) hidden to VCC
part B pins: 5 Q (out), 6 ~{Q} (out), 7 GND (power) hidden to GND, 8 J (in), 9 CLK (in), 10 ~{CLR} (in), 11 K (in), 14 VCC (power) hidden to VCC
1 alternate drawing of the same symbol

## SN74LS109A
designator U?
DUAL J-K PET FF RS CR
footprint SO16
footprint DIP-16
part A pins: 1 ~{CLR} (in), 2 J (in), 3 K (in), 4 CLK (in), 5 ~{PRE} (in), 6 Q (out), 7 ~{Q} (out), 8 GND (power) hidden to GND, 16 VCC (power) hidden to VCC
part B pins: 8 GND (power) hidden to GND, 9 ~{Q} (out), 10 Q (out), 11 ~{PRE} (in), 12 CLK (in), 13 K (in), 14 J (in), 15 ~{CLR} (in), 16 VCC (power) hidden to VCC
1 alternate drawing of the same symbol

## SN74LS114A
designator U?
DUAL J-K NET FF RS COM CR COM CLK
footprint SO14
footprint DIP-14
pins: 1 ~{CLR} (in), 2 1K (in), 3 1J (in), 4 1~{PRE} (in), 5 1Q (out), 6 1~{Q} (out), 7 GND (power) hidden to GND, 8 2~{Q} (out), 9 2Q (out), 10 2~{PRE} (in), 11 2J (in), 12 2K (in), 13 CLK (in), 14 VCC (power) hidden to VCC
1 alternate drawing of the same symbol

## SN74LS122
designator U?
RETRIGGERABLE MONOSTABLE MULTIVIBRATOR
footprint SO14
footprint DIP-14
pins: 1 A1 (in), 2 A2 (in), 3 B1 (in), 4 B2 (in), 5 ~{CLR} (in), 6 ~{Q} (out), 7 GND (power) hidden to GND, 8 Q (out), 9 Rint, 11 Cext, 13 Rext/Cext, 14 VCC (power) hidden to VCC
1 alternate drawing of the same symbol

## SN74LS123
designator U?
RETRIGGERABLE MONOSTABLE MULTIVIBRATOR
footprint SO16
footprint DIP-16
part A pins: 1 A (in), 2 B (in), 3 ~{CLR} (in), 4 ~{Q} (out), 8 GND (power) hidden to GND, 13 Q (out), 14 Cext, 15 Rext/Cext, 16 VCC (power) hidden to VCC
part B pins: 5 Q (out), 6 Cext, 7 Rext/Cext, 8 GND (power) hidden to GND, 9 A (in), 10 B (in), 11 ~{CLR} (in), 12 ~{Q} (out), 16 VCC (power) hidden to VCC
1 alternate drawing of the same symbol

## SN74LS125A
designator U?
QUAD BUS BUF 3SO
footprint SO14
footprint DIP-14
part A pins: 1 (in), 2 (in), 3 (hiz), 7 GND (power) hidden to GND, 14 VCC (power) hidden to VCC
part B pins: 4 (in), 5 (in), 6 (hiz), 7 GND (power) hidden to GND, 14 VCC (power) hidden to VCC
part C pins: 7 GND (power) hidden to GND, 8 (hiz), 9 (in), 10 (in), 14 VCC (power) hidden to VCC
part D pins: 7 GND (power) hidden to GND, 11 (hiz), 12 (in), 13 (in), 14 VCC (power) hidden to VCC
2 alternate drawings of the same symbol

## SN74LS126A
designator U?
QUAD BUS BUF 3SO
footprint SO14
footprint DIP-14
part A pins: 1 (in), 2 (in), 3 (hiz), 7 GND (power) hidden to GND, 14 VCC (power) hidden to VCC
part B pins: 4 (in), 5 (in), 6 (hiz), 7 GND (power) hidden to GND, 14 VCC (power) hidden to VCC
part C pins: 7 GND (power) hidden to GND, 8 (hiz), 9 (in), 10 (in), 14 VCC (power) hidden to VCC
part D pins: 7 GND (power) hidden to GND, 11 (hiz), 12 (in), 13 (in), 14 VCC (power) hidden to VCC
2 alternate drawings of the same symbol

## SN74LS126A(1)
designator U?
QUAD BUS BUF 3SO
footprint DIP-14
part A pins: 1 (in), 2 (in), 3 (hiz), 7 GND (power) hidden to GND, 14 VCC (power) hidden to VCC
part B pins: 4 (in), 5 (in), 6 (hiz), 7 GND (power) hidden to GND, 14 VCC (power) hidden to VCC
part C pins: 7 GND (power) hidden to GND, 8 (hiz), 9 (in), 10 (in), 14 VCC (power) hidden to VCC
part D pins: 7 GND (power) hidden to GND, 11 (hiz), 12 (in), 13 (in), 14 VCC (power) hidden to VCC
2 alternate drawings of the same symbol

## SN74LS132
designator U?
QUAD 2-IN POS NAND SCH
footprint SO14
footprint DIP-14
part A pins: 1 (in), 2 (in), 3 (out), 7 GND (power) hidden to GND, 14 VCC (power) hidden to VCC
part B pins: 4 (in), 5 (in), 6 (out), 7 GND (power) hidden to GND, 14 VCC (power) hidden to VCC
part C pins: 7 GND (power) hidden to GND, 8 (out), 9 (in), 10 (in), 14 VCC (power) hidden to VCC
part D pins: 7 GND (power) hidden to GND, 11 (out), 12 (in), 13 (in), 14 VCC (power) hidden to VCC
2 alternate drawings of the same symbol

## SN74LS136
designator U?
QUAD 2-IN XOR  G OCO
footprint DIP-14
part A pins: 1 (in), 2 (in), 3 (oc), 7 GND (power) hidden to GND, 14 VCC (power) hidden to VCC
part B pins: 4 (in), 5 (in), 6 (oc), 7 GND (power) hidden to GND, 14 VCC (power) hidden to VCC
part C pins: 7 GND (power) hidden to GND, 8 (oc), 9 (in), 10 (in), 14 VCC (power) hidden to VCC
part D pins: 7 GND (power) hidden to GND, 11 (oc), 12 (in), 13 (in), 14 VCC (power) hidden to VCC
1 alternate drawing of the same symbol

## SN74LS137
designator U?
3-8LINE DEC/DEMUL ADDRESS LCH
footprint SO16
footprint DIP-16
pins: 1 A (in), 2 B (in), 3 C (in), 4 ~{G}L (in), 5 ~{G}2 (in), 6 G1 (in), 7 y7 (out), 8 GND (power) hidden to GND, 9 y6 (out), 10 y5 (out), 11 y4 (out), 12 y3 (out), 13 y2 (out), 14 y1 (out), 15 y0 (out), 16 VCC (power) hidden to VCC
1 alternate drawing of the same symbol

## SN74LS138
designator U?
3-8LINE DEC/DEMUL
footprint SO16
footprint DIP-16
pins: 1 A (in), 2 B (in), 3 C (in), 4 ~{G}2A (in), 5 ~{G}2B (in), 6 G1 (in), 7 Y7 (out), 8 GND (power) hidden to GND, 9 Y6 (out), 10 Y5 (out), 11 Y4 (out), 12 Y3 (out), 13 Y2 (out), 14 Y1 (out), 15 Y0 (out), 16 VCC (power) hidden to VCC
1 alternate drawing of the same symbol

## SN74LS139A
designator U?
DUAL 2-4LINE DEC/DEMULT
footprint SO16
footprint DIP-16
part A pins: 1 ~{G} (in), 2 A (in), 3 B (in), 4 Y0 (out), 5 Y1 (out), 6 Y2 (out), 7 Y3 (out), 8 GND (power) hidden to GND, 16 VCC (power) hidden to VCC
part B pins: 8 GND (power) hidden to GND, 9 Y3 (out), 10 Y2 (out), 11 Y1 (out), 12 Y0 (out), 13 B (in), 14 A (in), 15 ~{G} (in), 16 VCC (power) hidden to VCC
1 alternate drawing of the same symbol

## SN74LS153
designator U?
DUAL 4-1 LINE DATA SELEC/MUX
footprint SO16
footprint DIP-16
pins: 1 1~{G} (in), 2 B (in), 3 1C3 (in), 4 1C2 (in), 5 1C1 (in), 6 1CO (in), 7 1Y (out), 8 GND (power) hidden to GND, 9 2Y (out), 10 2CO (in), 11 2C1 (in), 12 2C2 (in), 13 2C3 (in), 14 A (in), 15 2~{G} (in), 16 VCC (power) hidden to VCC
1 alternate drawing of the same symbol

## SN74LS155A
designator U?
DUAL 2-4 LINE DEC/DEMUL
footprint SO16
footprint DIP-16
pins: 1 1C (in), 2 1~{G} (in), 3 B (in), 4 1Y3 (out), 5 1Y2 (out), 6 1Y1 (out), 7 1Y0 (out), 8 GND (power) hidden to GND, 9 2Y0 (out), 10 2Y1 (out), 11 2Y2 (out), 12 2Y3 (out), 13 A (in), 14 2~{G} (in), 15 2C (in), 16 VCC (power) hidden to VCC
1 alternate drawing of the same symbol

## SN74LS156
designator U?
DUAL 2-4 LINE DEC/DEMUL
footprint DIP-16
pins: 1 1C (in), 2 1~{G} (in), 3 B (in), 4 1Y3 (oc), 5 1Y2 (oc), 6 1Y1 (oc), 7 1Y0 (oc), 8 GND (power) hidden to GND, 9 2Y0 (oc), 10 2Y1 (oc), 11 2Y2 (oc), 12 2Y3 (oc), 13 A (in), 15 2C (in), 16 VCC (power) hidden to VCC, (14 2~{G}
1 alternate drawing of the same symbol


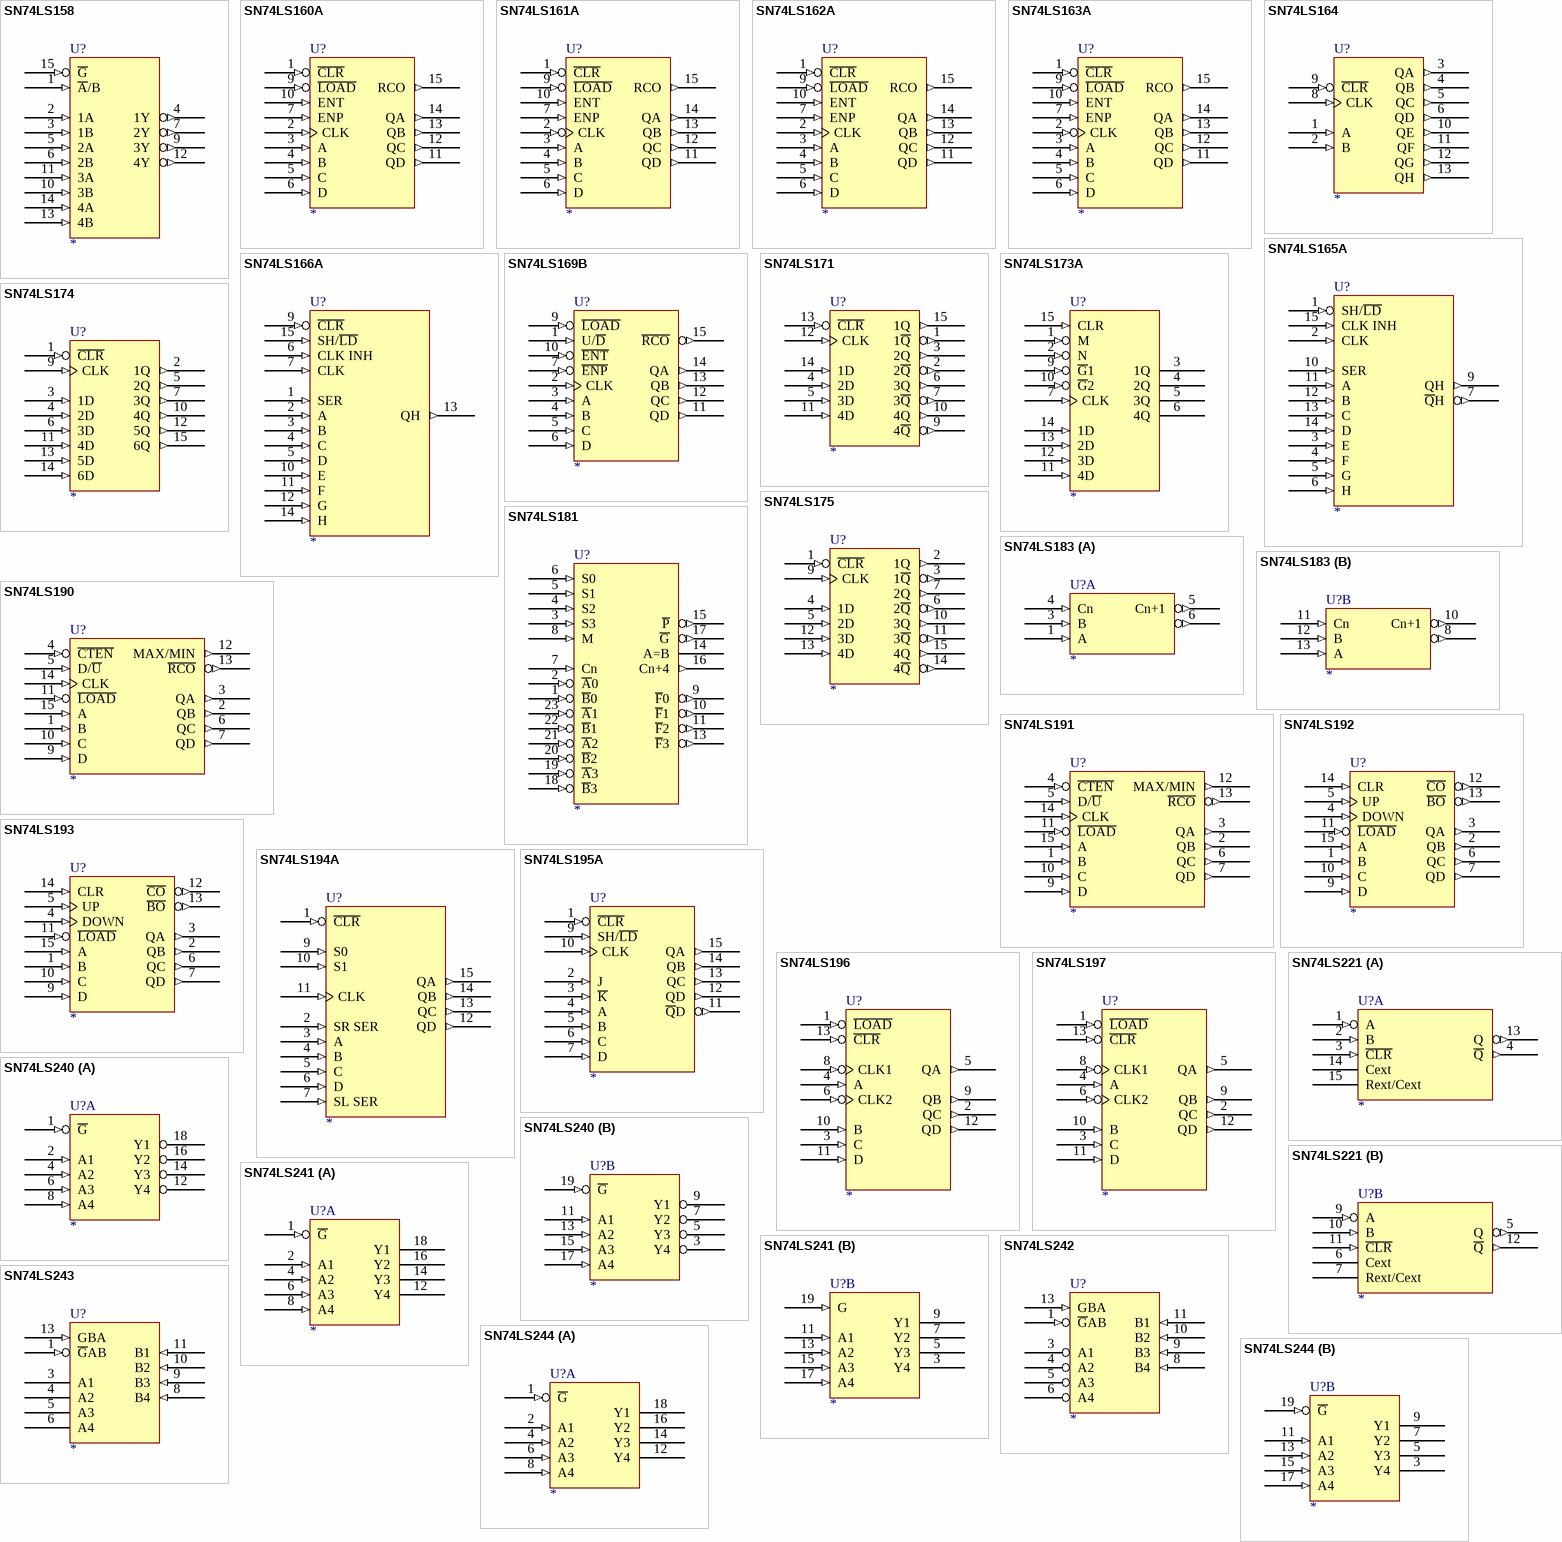
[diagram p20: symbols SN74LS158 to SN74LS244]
## SN74LS158
designator U?
QUAD 2-1LINE DATA SELEC/MUX
footprint SO16
footprint DIP-16
pins: 1 ~{A}/B (in), 2 1A (in), 3 1B (in), 4 1Y (out), 5 2A (in), 6 2B (in), 7 2Y (out), 8 GND (power) hidden to GND, 9 3Y (out), 10 3B (in), 11 3A (in), 12 4Y (out), 13 4B (in), 14 4A (in), 15 ~{G} (in), 16 VCC (power) hidden to VCC
1 alternate drawing of the same symbol

## SN74LS160A
designator U?
SYN 4-BIT CNT
footprint SO16
footprint DIP-16
pins: 1 ~{CLR} (in), 2 CLK (in), 3 A (in), 4 B (in), 5 C (in), 6 D (in), 7 ENP (in), 8 GND (power) hidden to GND, 9 ~{LOAD} (in), 10 ENT (in), 11 QD (out), 12 QC (out), 13 QB (out), 14 QA (out), 15 RCO (out), 16 VCC (power) hidden to VCC
1 alternate drawing of the same symbol

## SN74LS161A
designator U?
SYN 4-BIT CNT
footprint DIP-16
footprint SO16
pins: 1 ~{CLR} (in), 2 CLK (in), 3 A (in), 4 B (in), 5 C (in), 6 D (in), 7 ENP (in), 8 GND (power) hidden to GND, 9 ~{LOAD} (in), 10 ENT (in), 11 QD (out), 12 QC (out), 13 QB (out), 14 QA (out), 15 RCO (out), 16 VCC (power) hidden to VCC
1 alternate drawing of the same symbol

## SN74LS162A
designator U?
SYN 4-BIT CNT
footprint SO16
footprint DIP-16
pins: 1 ~{CLR} (in), 2 CLK (in), 3 A (in), 4 B (in), 5 C (in), 6 D (in), 7 ENP (in), 8 GND (power) hidden to GND, 9 ~{LOAD} (in), 10 ENT (in), 11 QD (out), 12 QC (out), 13 QB (out), 14 QA (out), 15 RCO (out), 16 VCC (power) hidden to VCC
1 alternate drawing of the same symbol

## SN74LS163A
designator U?
SYN 4-BIT CNT
footprint SO16
footprint DIP-16
pins: 1 ~{CLR} (in), 2 CLK (in), 3 A (in), 4 B (in), 5 C (in), 6 D (in), 7 ENP (in), 8 GND (power) hidden to GND, 9 ~{LOAD} (in), 10 ENT (in), 11 QD (out), 12 QC (out), 13 QB (out), 14 QA (out), 15 RCO (out), 16 VCC (power) hidden to VCC
1 alternate drawing of the same symbol

## SN74LS164
designator U?
8-BIT PALL SERI SFT REG
footprint SO14
footprint DIP-14
pins: 1 A (in), 2 B (in), 3 QA (out), 4 QB (out), 5 QC (out), 6 QD (out), 7 GND (power) hidden to GND, 8 CLK (in), 9 ~{CLR} (in), 10 QE (out), 11 QF (out), 12 QG (out), 13 QH (out), 14 VCC (power) hidden to VCC
1 alternate drawing of the same symbol

## SN74LS165A
designator U?
PALL LOAD 8-BIT SFT REG
footprint SO16
footprint DIP-16
pins: 1 SH/~{LD} (in), 2 CLK (in), 3 E (in), 4 F (in), 5 G (in), 6 H (in), 7 ~{Q}H (out), 8 GND (power) hidden to GND, 9 QH (out), 10 SER (in), 11 A (in), 12 B (in), 13 C (in), 14 D (in), 15 CLK INH (in), 16 VCC (power) hidden to VCC
1 alternate drawing of the same symbol

## SN74LS166A
designator U?
PALL LOAD 8-BIT SFT REG
footprint DIP-16
footprint SO16
pins: 1 SER (in), 2 A (in), 3 B (in), 4 C (in), 5 D (in), 6 CLK INH (in), 7 CLK (in), 8 GND (power) hidden to GND, 9 ~{CLR} (in), 10 E (in), 11 F (in), 12 G (in), 13 QH (out), 14 H (in), 15 SH/~{LD} (in), 16 VCC (power) hidden to VCC
1 alternate drawing of the same symbol

## SN74LS169B
designator U?
SYN 4-BIT UP/DOWN BIN CNT
footprint SO16
footprint DIP-16
pins: 1 U/~{D} (in), 2 CLK (in), 3 A (in), 4 B (in), 5 C (in), 6 D (in), 7 ~{ENP} (in), 8 GND (power) hidden to GND, 9 ~{LOAD} (in), 10 ~{ENT} (in), 11 QD (out), 12 QC (out), 13 QB (out), 14 QA (out), 15 ~{RCO} (out), 16 VCC (power) hidden to VCC
1 alternate drawing of the same symbol

## SN74LS171
designator U?
QUAD D-TYPE FF CR
footprint SO16
footprint DIP-16
pins: 1 1~{Q} (out), 2 2~{Q} (out), 3 2Q (out), 4 2D (in), 5 3D (in), 6 3Q (out), 7 3~{Q} (out), 8 GND (power) hidden to GND, 9 4~{Q} (out), 10 4Q (out), 11 4D (in), 12 CLK (in), 13 ~{CLR} (in), 14 1D (in), 15 1Q (out), 16 VCC (power) hidden to VCC
1 alternate drawing of the same symbol

## SN74LS173A
designator U?
4-BIT D-TYPE REG 3SO
footprint SO16
footprint DIP-16
pins: 1 M (in), 2 N (in), 3 1Q (hiz), 4 2Q (hiz), 5 3Q (hiz), 6 4Q (hiz), 7 CLK (in), 8 GND (power) hidden to GND, 9 ~{G}1 (in), 10 ~{G}2 (in), 11 4D (in), 12 3D (in), 13 2D (in), 14 1D (in), 15 CLR (in), 16 VCC (power) hidden to VCC
1 alternate drawing of the same symbol

## SN74LS174
designator U?
HEX D-TYPE FF CR
footprint SO16
footprint DIP-16
pins: 1 ~{CLR} (in), 2 1Q (out), 3 1D (in), 4 2D (in), 5 2Q (out), 6 3D (in), 7 3Q (out), 8 GND (power) hidden to GND, 9 CLK (in), 10 4Q (out), 11 4D (in), 12 5Q (out), 13 5D (in), 14 6D (in), 15 6Q (out), 16 VCC (power) hidden to VCC
1 alternate drawing of the same symbol

## SN74LS175
designator U?
QUAD D-TYPE FF CR
footprint SO16
footprint DIP-16
pins: 1 ~{CLR} (in), 2 1Q (out), 3 1~{Q} (out), 4 1D (in), 5 2D (in), 6 2~{Q} (out), 7 2Q (out), 8 GND (power) hidden to GND, 9 CLK (in), 10 3Q (out), 11 3~{Q} (out), 12 3D (in), 13 4D (in), 14 4~{Q} (out), 15 4Q (out), 16 VCC (power) hidden to VCC
1 alternate drawing of the same symbol

## SN74LS181
designator U?
ALU/FN GNR
footprint SO24W
footprint DIP-24
pins: 1 ~{B}0 (in), 2 ~{A}0 (in), 3 S3 (in), 4 S2 (in), 5 S1 (in), 6 S0 (in), 7 Cn (in), 8 M (in), 9 ~{F}0 (out), 10 ~{F}1 (out), 11 ~{F}2 (out), 12 GND (power) hidden to GND, 13 ~{F}3 (out), 14 A=B (oc), 15 ~{P} (out), 16 Cn+4 (out), 17 ~{G} (out), 18 ~{B}3 (in), 19 ~{A}3 (in), 20 ~{B}2 (in), 21 ~{A}2 (in), 22 ~{B}1 (in), 23 ~{A}1 (in), 24 VCC (power) hidden to VCC
1 alternate drawing of the same symbol

## SN74LS183
designator U?
DUAL CARRY-SAVE FULL ADD
footprint DIP-14
part A pins: 1 A (in), 3 B (in), 4 Cn (in), 5 Cn+1 (out), 6 (out), 7 GND (power) hidden to GND, 14 VCC (power) hidden to VCC
part B pins: 7 GND (power) hidden to GND, 8 (out), 10 Cn+1 (out), 11 Cn (in), 12 B (in), 13 A (in), 14 VCC (power) hidden to VCC
1 alternate drawing of the same symbol

## SN74LS190
designator U?
SYN UP/DOWN CNT DOWN/UP MODE CONTTOL
footprint DIP-16
footprint SO16
pins: 1 B (in), 2 QB (out), 3 QA (out), 4 ~{CTEN} (in), 5 D/~{U} (in), 6 QC (out), 7 QD (out), 8 GND (power) hidden to GND, 9 D (in), 10 C (in), 11 ~{LOAD} (in), 12 MAX/MIN (out), 13 ~{RCO} (out), 14 CLK (in), 15 A (in), 16 VCC (power) hidden to VCC
1 alternate drawing of the same symbol

## SN74LS191
designator U?
SYN UP/DOWN CNT DOWN/UP MODE CONTTOL
footprint SO16
footprint DIP-16
pins: 1 B (in), 2 QB (out), 3 QA (out), 4 ~{CTEN} (in), 5 D/~{U} (in), 6 QC (out), 7 QD (out), 8 GND (power) hidden to GND, 9 D (in), 10 C (in), 11 ~{LOAD} (in), 12 MAX/MIN (out), 13 ~{RCO} (out), 14 CLK (in), 15 A (in), 16 VCC (power) hidden to VCC
1 alternate drawing of the same symbol

## SN74LS192
designator U?
SYN 4-BIT UP/DOWN CNT DUAL CLK CR
footprint SO16
footprint DIP-16
pins: 1 B (in), 2 QB (out), 3 QA (out), 4 DOWN (in), 5 UP (in), 6 QC (out), 7 QD (out), 8 GND (power) hidden to GND, 9 D (in), 10 C (in), 11 ~{LOAD} (in), 12 ~{CO} (out), 13 ~{BO} (out), 14 CLR (in), 15 A (in), 16 VCC (power) hidden to VCC
1 alternate drawing of the same symbol

## SN74LS193
designator U?
SYN 4-BIT UP/DOWN CNT DUAL CLK CR
footprint DIP-16
footprint SO16
pins: 1 B (in), 2 QB (out), 3 QA (out), 4 DOWN (in), 5 UP (in), 6 QC (out), 7 QD (out), 8 GND (power) hidden to GND, 9 D (in), 10 C (in), 11 ~{LOAD} (in), 12 ~{CO} (out), 13 ~{BO} (out), 14 CLR (in), 15 A (in), 16 VCC (power) hidden to VCC
1 alternate drawing of the same symbol

## SN74LS194A
designator U?
4-BIT BIDIRECTIONAL UNIVERSAL SFT REG
footprint SO16
footprint DIP-16
pins: 1 ~{CLR} (in), 2 SR SER (in), 3 A (in), 4 B (in), 5 C (in), 6 D (in), 7 SL SER (in), 8 GND (power) hidden to GND, 9 S0 (in), 10 S1 (in), 11 CLK (in), 12 QD (out), 13 QC (out), 14 QB (out), 15 QA (out), 16 VCC (power) hidden to VCC
1 alternate drawing of the same symbol

## SN74LS195A
designator U?
4-BIT PARALLEL ACCESS SFT REG
footprint SO16
footprint DIP-16
pins: 1 ~{CLR} (in), 2 J (in), 3 ~{K} (in), 4 A (in), 5 B (in), 6 C (in), 7 D (in), 8 GND (power) hidden to GND, 9 SH/~{LD} (in), 10 CLK (in), 11 ~{Q}D (out), 12 QD (out), 13 QC (out), 14 QB (out), 15 QA (out), 16 VCC (power) hidden to VCC
1 alternate drawing of the same symbol

## SN74LS196
designator U?
50/30/100-MHZ PRESETTABLE DECADE BIN CNT LCH
footprint DIP-16
footprint SO16
pins: 1 ~{LOAD} (in), 2 QC (out), 3 C (in), 4 A (in), 5 QA (out), 6 CLK2 (in), 7 GND (power) hidden to GND, 8 CLK1 (in), 9 QB (out), 10 B (in), 11 D (in), 12 QD (out), 13 ~{CLR} (in), 14 VCC (power) hidden to VCC
1 alternate drawing of the same symbol

## SN74LS197
designator U?
50/30/100-MHZ PRESETTABLE DECADE BIN CNT LCH
footprint SO16
footprint DIP-16
pins: 1 ~{LOAD} (in), 2 QC (out), 3 C (in), 4 A (in), 5 QA (out), 6 CLK2 (in), 7 GND (power) hidden to GND, 8 CLK1 (in), 9 QB (out), 10 B (in), 11 D (in), 12 QD (out), 13 ~{CLR} (in), 14 VCC (power) hidden to VCC
1 alternate drawing of the same symbol

## SN74LS221
designator U?
DUAL MONOSTABLE MULTIVIBRATOR SCHI
footprint SO16
footprint DIP-16
part A pins: 1 A (in), 2 B (in), 3 ~{CLR} (in), 4 ~{Q} (out), 8 GND (power) hidden to GND, 13 Q (out), 14 Cext, 15 Rext/Cext, 16 VCC (power) hidden to VCC
part B pins: 5 Q (out), 6 Cext, 7 Rext/Cext, 8 GND (power) hidden to GND, 9 A (in), 10 B (in), 11 ~{CLR} (in), 12 ~{Q} (out), 16 VCC (power) hidden to VCC
1 alternate drawing of the same symbol

## SN74LS240
designator U?
OCTAL BUF AND LIN DRV 3SO
footprint SO20W
footprint DIP-20
part A pins: 1 ~{G} (in), 2 A1 (in), 4 A2 (in), 6 A3 (in), 8 A4 (in), 10 GND (power) hidden to GND, 12 Y4 (hiz), 14 Y3 (hiz), 16 Y2 (hiz), 18 Y1 (hiz), 20 VCC (power) hidden to VCC
part B pins: 3 Y4 (hiz), 5 Y3 (hiz), 7 Y2 (hiz), 9 Y1 (hiz), 10 GND (power) hidden to GND, 11 A1 (in), 13 A2 (in), 15 A3 (in), 17 A4 (in), 19 ~{G} (in), 20 VCC (power) hidden to VCC
1 alternate drawing of the same symbol

## SN74LS241
designator U?
OCTAL BUF AND LIN DRV 3SO
footprint SO20W
footprint DIP-20
part A pins: 1 ~{G} (in), 2 A1 (in), 4 A2 (in), 6 A3 (in), 8 A4 (in), 10 GND (power) hidden to GND, 12 Y4 (hiz), 14 Y3 (hiz), 16 Y2 (hiz), 18 Y1 (hiz), 20 VCC (power) hidden to VCC
part B pins: 3 Y4 (hiz), 5 Y3 (hiz), 7 Y2 (hiz), 9 Y1 (hiz), 10 GND (power) hidden to GND, 11 A1 (in), 13 A2 (in), 15 A3 (in), 17 A4 (in), 19 G (in), 20 VCC (power) hidden to VCC
1 alternate drawing of the same symbol

## SN74LS242
designator U?
QUAD BUS TRANSCEIVER
footprint SO14
footprint DIP-14
pins: 1 ~{G}AB (in), 3 A1 (hiz), 4 A2 (hiz), 5 A3 (hiz), 6 A4 (hiz), 7 GND (power) hidden to GND, 8 B4 (in), 9 B3 (in), 10 B2 (in), 11 B1 (in), 13 GBA (in), 14 VCC (power) hidden to VCC
1 alternate drawing of the same symbol

## SN74LS243
designator U?
QUAD BUS TRANSCEIVER
footprint SO14
footprint DIP-14
pins: 1 ~{G}AB (in), 3 A1 (hiz), 4 A2 (hiz), 5 A3 (hiz), 6 A4 (hiz), 7 GND (power) hidden to GND, 8 B4 (in), 9 B3 (in), 10 B2 (in), 11 B1 (in), 13 GBA (in), 14 VCC (power) hidden to VCC
1 alternate drawing of the same symbol

## SN74LS244
designator U?
OCTAL BUF AND LIN DRV 3SO
footprint DIP-20
footprint SO20W
part A pins: 1 ~{G} (in), 2 A1 (in), 4 A2 (in), 6 A3 (in), 8 A4 (in), 10 GND (power) hidden to GND, 12 Y4 (hiz), 14 Y3 (hiz), 16 Y2 (hiz), 18 Y1 (hiz), 20 VCC (power) hidden to VCC
part B pins: 3 Y4 (hiz), 5 Y3 (hiz), 7 Y2 (hiz), 9 Y1 (hiz), 10 GND (power) hidden to GND, 11 A1 (in), 13 A2 (in), 15 A3 (in), 17 A4 (in), 19 ~{G} (in), 20 VCC (power) hidden to VCC
1 alternate drawing of the same symbol


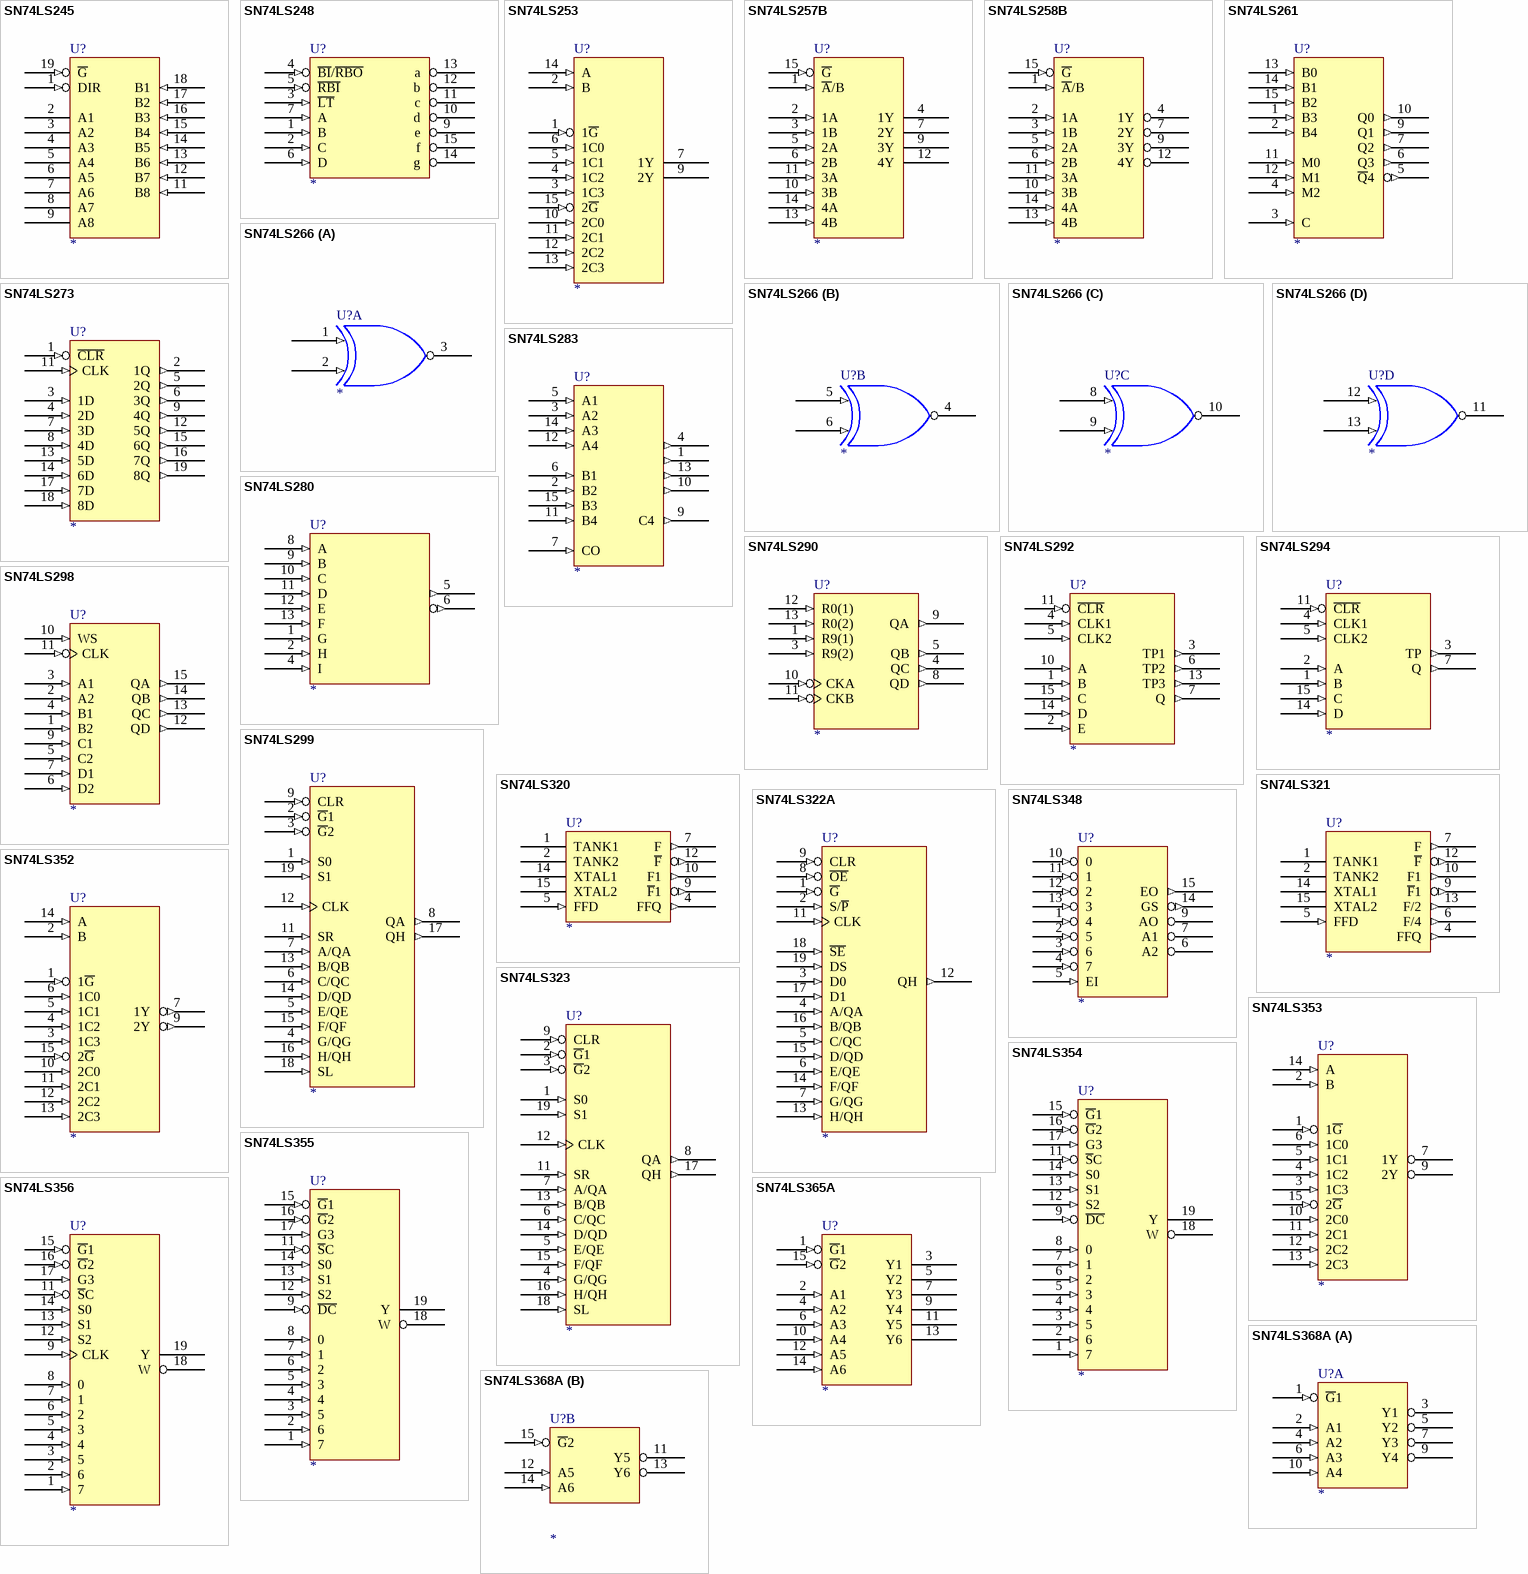
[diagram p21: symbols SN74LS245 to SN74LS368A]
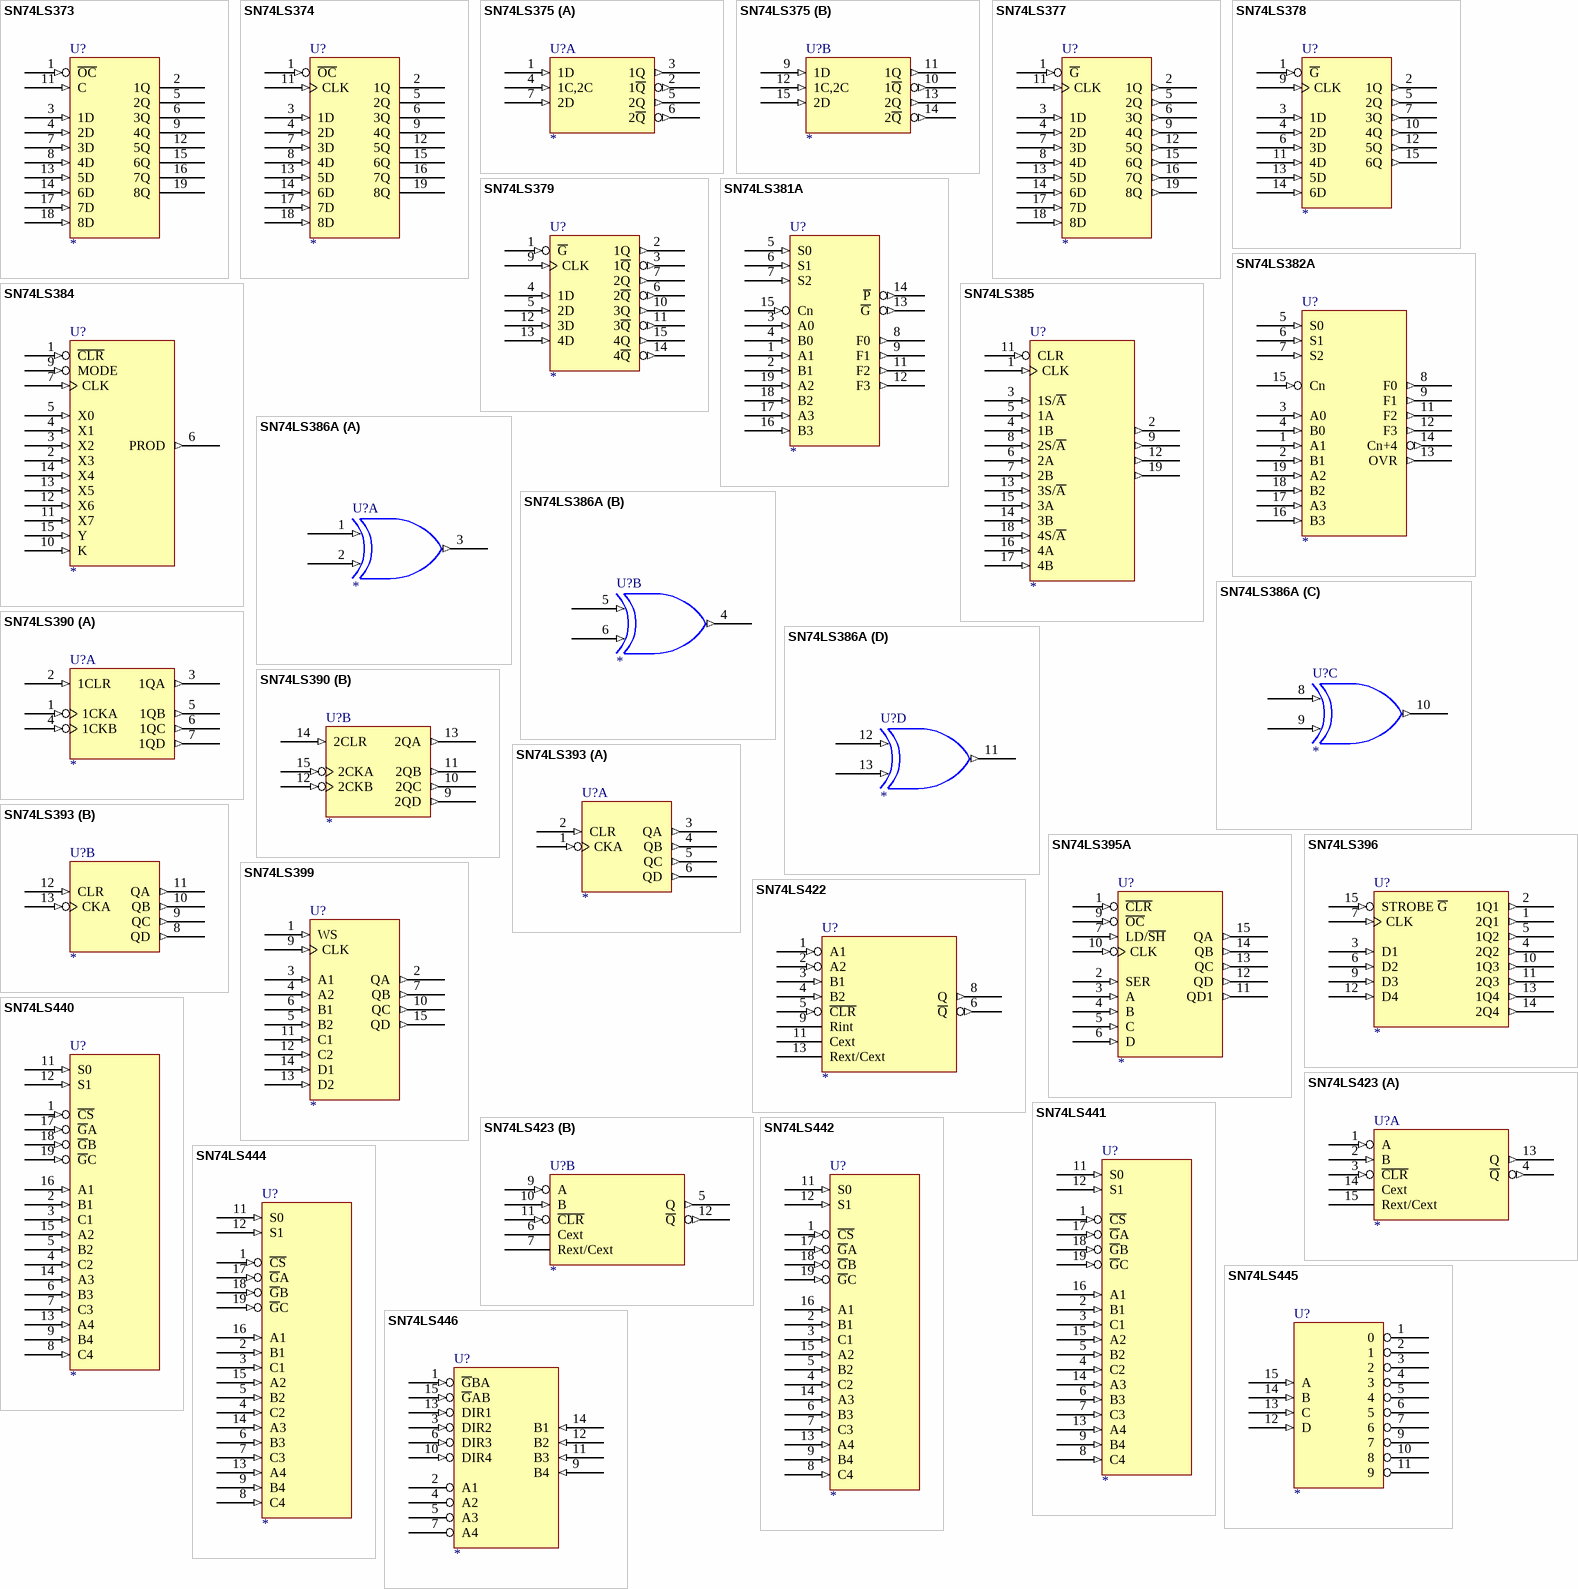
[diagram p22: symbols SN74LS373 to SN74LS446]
## SN74LS245
designator U?
QUAD BUS TRANSCEIVER 3SO
footprint SO20W
footprint DIP-20
pins: 1 DIR (in), 2 A1 (hiz), 3 A2 (hiz), 4 A3 (hiz), 5 A4 (hiz), 6 A5 (hiz), 7 A6 (hiz), 8 A7 (hiz), 9 A8 (hiz), 10 GND (power) hidden to GND, 11 B8 (in), 12 B7 (in), 13 B6 (in), 14 B5 (in), 15 B4 (in), 16 B3 (in), 17 B2 (in), 18 B1 (in), 19 ~{G} (in), 20 VCC (power) hidden to VCC
1 alternate drawing of the same symbol

## SN74LS248
designator U?
BCD-TO-SEVEN-SEGMENTDEC/DRV
footprint DIP-16
footprint SO16
pins: 1 B (in), 2 C (in), 3 ~{LT} (in), 4 ~{BI}/~{RBO} (in), 5 ~{RBI} (in), 6 D (in), 7 A (in), 8 GND (power) hidden to GND, 9 e (oc), 10 d (oc), 11 c (oc), 12 b (oc), 13 a (oc), 14 g (oc), 15 f (oc), 16 VCC (power) hidden to VCC
1 alternate drawing of the same symbol

## SN74LS253
designator U?
DUAL 4-1LINES DATA SLCR/MUX
footprint SO16
footprint DIP-16
pins: 1 1~{G} (in), 2 B (in), 3 1C3 (in), 4 1C2 (in), 5 1C1 (in), 6 1C0 (in), 7 1Y (hiz), 8 GND (power) hidden to GND, 9 2Y (hiz), 10 2C0 (in), 11 2C1 (in), 12 2C2 (in), 13 2C3 (in), 14 A (in), 15 2~{G} (in), 16 VCC (power) hidden to VCC
1 alternate drawing of the same symbol

## SN74LS257B
designator U?
QUAD 2-1LINE DATA SLCR/MUX
footprint SO16
pins: 1 ~{A}/B (in), 2 1A (in), 3 1B (in), 4 1Y (hiz), 5 2A (in), 6 2B (in), 7 2Y (hiz), 8 GND (power) hidden to GND, 9 3Y (hiz), 10 3B (in), 11 3A (in), 12 4Y (hiz), 13 4B (in), 14 4A (in), 15 ~{G} (in), 16 VCC (power) hidden to VCC
1 alternate drawing of the same symbol

## SN74LS258B
designator U?
QUAD 2-1LINE DATA SLCR/MUX
footprint DIP-16
footprint SO16
pins: 1 ~{A}/B (in), 2 1A (in), 3 1B (in), 4 1Y (hiz), 5 2A (in), 6 2B (in), 7 2Y (hiz), 8 GND (power) hidden to GND, 9 3Y (hiz), 10 3B (in), 11 3A (in), 12 4Y (hiz), 13 4B (in), 14 4A (in), 15 ~{G} (in), 16 VCC (power) hidden to VCC
1 alternate drawing of the same symbol

## SN74LS261
designator U?
2-BIT 4-BIT PARALLEL BIN MULT
footprint DIP-16
footprint SO16
pins: 1 B3 (in), 2 B4 (in), 3 C (in), 4 M2 (in), 5 ~{Q}4 (out), 6 Q3 (out), 7 Q2 (out), 8 GND (power) hidden to GND, 9 Q1 (out), 10 Q0 (out), 11 M0 (in), 12 M1 (in), 13 B0 (in), 14 B1 (in), 15 B2 (in), 16 VCC (power) hidden to VCC
1 alternate drawing of the same symbol

## SN74LS266
designator U?
QUAD 2-IN XOR  G OCO
footprint SO14
footprint DIP-14
part A pins: 1 (in), 2 (in), 3 (oc), 7 GND (power) hidden to GND, 14 VCC (power) hidden to VCC
part B pins: 4 (oc), 5 (in), 6 (in), 7 GND (power) hidden to GND, 14 VCC (power) hidden to VCC
part C pins: 7 GND (power) hidden to GND, 8 (in), 9 (in), 10 (oc), 14 VCC (power) hidden to VCC
part D pins: 7 GND (power) hidden to GND, 11 (oc), 12 (in), 13 (in), 14 VCC (power) hidden to VCC
1 alternate drawing of the same symbol

## SN74LS273
designator U?
OCTAL D-TYPE FF CR
footprint DIP-20
footprint SO20W
pins: 1 ~{CLR} (in), 2 1Q (out), 3 1D (in), 4 2D (in), 5 2Q (out), 6 3Q (out), 7 3D (in), 8 4D (in), 9 4Q (out), 10 GND (power) hidden to GND, 11 CLK (in), 12 5Q (out), 13 5D (in), 14 6D (in), 15 6Q (out), 16 7Q (out), 17 7D (in), 18 8D (in), 19 8Q (out), 20 VCC (power) hidden to VCC
1 alternate drawing of the same symbol

## SN74LS280
designator U?
9-BIT ODD/EVEN PARITY GNR/CHKR
footprint DIP-14
footprint SO14
pins: 1 G (in), 2 H (in), 4 I (in), 5 (out), 6 (out), 7 GND (power) hidden to GND, 8 A (in), 9 B (in), 10 C (in), 11 D (in), 12 E (in), 13 F (in), 14 VCC (power) hidden to VCC
1 alternate drawing of the same symbol

## SN74LS283
designator U?
4-BIT BIN ADD WITH FC
footprint SO16
footprint DIP-16
pins: 1 (out), 2 B2 (in), 3 A2 (in), 4 (out), 5 A1 (in), 6 B1 (in), 7 CO (in), 8 GND (power) hidden to GND, 9 C4 (out), 10 (out), 11 B4 (in), 12 A4 (in), 13 (out), 14 A3 (in), 15 B3 (in), 16 VCC (power) hidden to VCC
1 alternate drawing of the same symbol

## SN74LS290
designator U?
DECADE AND 4-BIT BIN CNT
footprint DIP-14
footprint SO14
pins: 1 R9(1) (in), 3 R9(2) (in), 4 QC (out), 5 QB (out), 7 GND (power) hidden to GND, 8 QD (out), 9 QA (out), 10 CKA (in), 11 CKB (in), 12 R0(1) (in), 13 R0(2) (in), 14 VCC (power) hidden to VCC
1 alternate drawing of the same symbol

## SN74LS292
designator U?
PROGRAMMABLE FRQ DIV/DIGITAL TIMERS
footprint DIP-16
pins: 1 B (in), 2 E (in), 3 TP1 (out), 4 CLK1 (in), 5 CLK2 (in), 6 TP2 (out), 7 Q (out), 8 GND (power) hidden to GND, 10 A (in), 11 ~{CLR} (in), 13 TP3 (out), 14 D (in), 15 C (in), 16 VCC (power) hidden to VCC
1 alternate drawing of the same symbol

## SN74LS294
designator U?
PROGRAMMABLE FRQ DIV/DIGITAL TIMERS
footprint DIP-16
pins: 1 B (in), 2 A (in), 3 TP (out), 4 CLK1 (in), 5 CLK2 (in), 7 Q (out), 8 GND (power) hidden to GND, 11 ~{CLR} (in), 14 D (in), 15 C (in), 16 VCC (power) hidden to VCC
1 alternate drawing of the same symbol

## SN74LS298
designator U?
QUAD 2-IN MUX WITH STORAGE
footprint SO16
footprint DIP-16
pins: 1 B2 (in), 2 A2 (in), 3 A1 (in), 4 B1 (in), 5 C2 (in), 6 D2 (in), 7 D1 (in), 8 GND (power) hidden to GND, 9 C1 (in), 10 WS (in), 11 CLK (in), 12 QD (out), 13 QC (out), 14 QB (out), 15 QA (out), 16 VCC (power) hidden to VCC
1 alternate drawing of the same symbol

## SN74LS299
designator U?
8-BIT UNIVERSAL SFT/STORAGE REG
footprint DIP-20
footprint SO20W
pins: 1 S0 (in), 2 ~{G}1 (in), 3 ~{G}2 (in), 4 G/QG (in), 5 E/QE (in), 6 C/QC (in), 7 A/QA (in), 8 QA (out), 9 CLR (in), 10 GND (power) hidden to GND, 11 SR (in), 12 CLK (in), 13 B/QB (in), 14 D/QD (in), 15 F/QF (in), 16 H/QH (in), 17 QH (out), 18 SL (in), 19 S1 (in), 20 VCC (power) hidden to VCC
1 alternate drawing of the same symbol

## SN74LS320
designator U?
CRYSTAL-CONTROLLED OSCILLATOR
footprint DIP-16
pins: 1 TANK1, 2 TANK2, 4 FFQ (out), 5 FFD (in), 7 F (out), 8 GND (power) hidden to GND, 9 ~{F}1 (out), 10 F1 (out), 11 VCC1 (power) hidden to VCC1, 12 ~{F} (out), 14 XTAL1, 15 XTAL2, 16 VCC (power) hidden to VCC
1 alternate drawing of the same symbol

## SN74LS321
designator U?
CRYSTAL-CONTROLLED OSCILLATOR
footprint DIP-16
pins: 1 TANK1, 2 TANK2, 4 FFQ (out), 5 FFD (in), 6 F/4 (out), 7 F (out), 8 GND (power) hidden to GND, 9 ~{F}1 (out), 10 F1 (out), 11 VCC1 (power) hidden to VCC1, 12 ~{F} (out), 13 F/2 (out), 14 XTAL1, 15 XTAL2, 16 VCC (power) hidden to VCC
1 alternate drawing of the same symbol

## SN74LS322A
designator U?
8-BIT REG WITH SIGN EXTEND REG
footprint SO20W
footprint DIP-20
pins: 1 ~{G} (in), 2 S/~{P} (in), 3 D0 (in), 4 A/QA (in), 5 C/QC (in), 6 E/QE (in), 7 G/QG (in), 8 ~{OE} (in), 9 CLR (in), 10 GND (power) hidden to GND, 11 CLK (in), 12 QH (out), 13 H/QH (in), 14 F/QF (in), 15 D/QD (in), 16 B/QB (in), 17 D1 (in), 18 ~{SE} (in), 19 DS (in), 20 VCC (power) hidden to VCC
1 alternate drawing of the same symbol

## SN74LS323
designator U?
8-BIT UNIVERSAL SFT/STORAGE REG
footprint DIP-20
footprint SO20W
pins: 1 S0 (in), 2 ~{G}1 (in), 3 ~{G}2 (in), 4 G/QG (in), 5 E/QE (in), 6 C/QC (in), 7 A/QA (in), 8 QA (out), 9 CLR (in), 10 GND (power) hidden to GND, 11 SR (in), 12 CLK (in), 13 B/QB (in), 14 D/QD (in), 15 F/QF (in), 16 H/QH (in), 17 QH (out), 18 SL (in), 19 S1 (in), 20 VCC (power) hidden to VCC
1 alternate drawing of the same symbol

## SN74LS348
designator U?
8-TO-3 PRIORITY ENCODER 3SO
footprint DIP-16
footprint SO16
pins: 1 4 (in), 2 5 (in), 3 6 (in), 4 7 (in), 5 EI (in), 6 A2 (hiz), 7 A1 (hiz), 8 GND (power) hidden to GND, 9 AO (hiz), 10 0 (in), 11 1 (in), 12 2 (in), 13 3 (in), 14 GS (out), 15 EO (out), 16 VCC (power) hidden to VCC
1 alternate drawing of the same symbol

## SN74LS352
designator U?
DUAL 4-1LINES DATA SLCR/MUX
footprint DIP-16
footprint SO16
pins: 1 1~{G} (in), 2 B (in), 3 1C3 (in), 4 1C2 (in), 5 1C1 (in), 6 1C0 (in), 7 1Y (out), 8 GND (power) hidden to GND, 9 2Y (out), 10 2C0 (in), 11 2C1 (in), 12 2C2 (in), 13 2C3 (in), 14 A (in), 15 2~{G} (in), 16 VCC (power) hidden to VCC
1 alternate drawing of the same symbol

## SN74LS353
designator U?
DUAL 4-1LINES DATA SLCR/MUX 3SO
footprint SO16
footprint DIP-16
pins: 1 1~{G} (in), 2 B (in), 3 1C3 (in), 4 1C2 (in), 5 1C1 (in), 6 1C0 (in), 7 1Y (hiz), 8 GND (power) hidden to GND, 9 2Y (hiz), 10 2C0 (in), 11 2C1 (in), 12 2C2 (in), 13 2C3 (in), 14 A (in), 15 2~{G} (in), 16 VCC (power) hidden to VCC
1 alternate drawing of the same symbol

## SN74LS354
designator U?
8-1LINE DATA SLCR/MUX/REG
footprint SO20W
footprint DIP-20
pins: 1 7 (in), 2 6 (in), 3 5 (in), 4 (in), 5 3 (in), 6 2 (in), 7 1 (in), 8 0 (in), 9 ~{DC} (in), 10 GND (power) hidden to GND, 11 ~{S}C (in), 12 S2 (in), 13 S1 (in), 14 S0 (in), 15 ~{G}1 (in), 16 ~{G}2 (in), 17 G3 (in), 18 W (hiz), 19 Y (hiz), 20 VCC (power) hidden to VCC
1 alternate drawing of the same symbol

## SN74LS355
designator U?
8-1LINE DATA SLCR/MUX/REG
footprint SO20W
footprint DIP-20
pins: 1 7 (in), 2 6 (in), 3 5 (in), 4 (in), 5 3 (in), 6 2 (in), 7 1 (in), 8 0 (in), 9 ~{DC} (in), 10 GND (power) hidden to GND, 11 ~{S}C (in), 12 S2 (in), 13 S1 (in), 14 S0 (in), 15 ~{G}1 (in), 16 ~{G}2 (in), 17 G3 (in), 18 W (oc), 19 Y (oc), 20 VCC (power) hidden to VCC
1 alternate drawing of the same symbol

## SN74LS356
designator U?
8-1LINE DATA SLCR/MUX/REG
footprint DIP-20
footprint SO20W
pins: 1 7 (in), 2 6 (in), 3 5 (in), 4 (in), 5 3 (in), 6 2 (in), 7 1 (in), 8 0 (in), 9 CLK (in), 10 GND (power) hidden to GND, 11 ~{S}C (in), 12 S2 (in), 13 S1 (in), 14 S0 (in), 15 ~{G}1 (in), 16 ~{G}2 (in), 17 G3 (in), 18 W (hiz), 19 Y (hiz), 20 VCC (power) hidden to VCC
1 alternate drawing of the same symbol

## SN74LS365A
designator U?
HEX BUS DRV 3SO
footprint SO16
footprint DIP-16
pins: 1 ~{G}1 (in), 2 A1 (in), 3 Y1 (hiz), 4 A2 (in), 5 Y2 (hiz), 6 A3 (in), 7 Y3 (hiz), 8 GND (power) hidden to GND, 9 Y4 (hiz), 10 A4 (in), 11 Y5 (hiz), 12 A5 (in), 13 Y6 (hiz), 14 A6 (in), 15 ~{G}2 (in), 16 VCC (power) hidden to VCC
1 alternate drawing of the same symbol

## SN74LS368A
designator U?
HEX BUS DRV 3SO
footprint SO16
footprint DIP-16
part A pins: 1 ~{G}1 (in), 2 A1 (in), 3 Y1 (hiz), 4 A2 (in), 5 Y2 (hiz), 6 A3 (in), 7 Y3 (hiz), 8 GND (power) hidden to GND, 9 Y4 (hiz), 10 A4 (in), 16 VCC (power) hidden to VCC
part B pins: 8 GND (power) hidden to GND, 11 Y5 (hiz), 12 A5 (in), 13 Y6 (hiz), 14 A6 (in), 15 ~{G}2 (in), 16 VCC (power) hidden to VCC
1 alternate drawing of the same symbol

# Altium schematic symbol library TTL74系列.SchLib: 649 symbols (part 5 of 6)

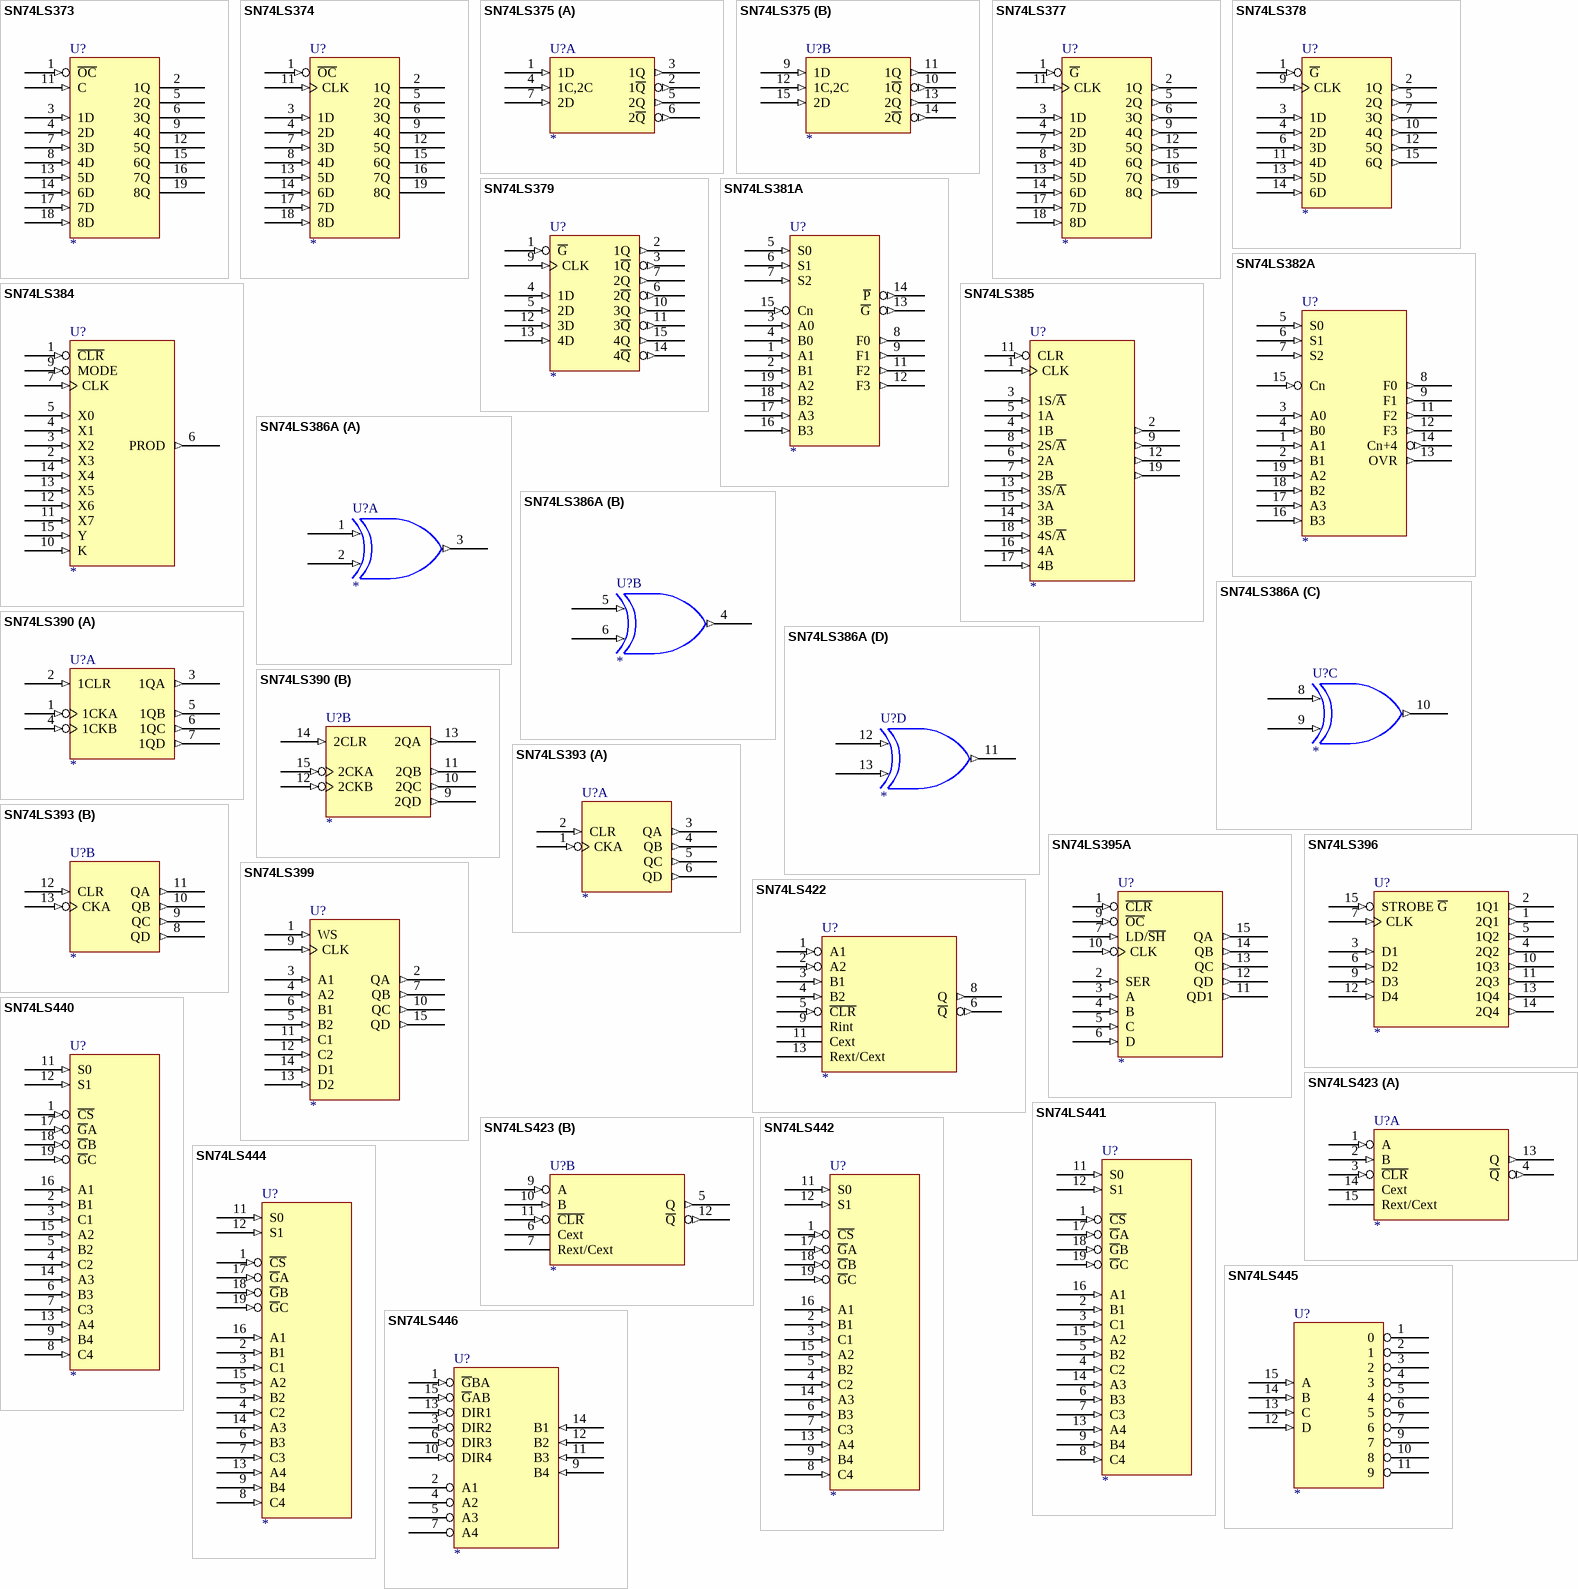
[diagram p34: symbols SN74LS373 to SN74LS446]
## SN74LS373
designator U?
OCTAL TRANSPARENT LCH
footprint DIP-20
pins: 1 ~{OC} (in), 2 1Q (hiz), 3 1D (in), 4 2D (in), 5 2Q (hiz), 6 3Q (hiz), 7 3D (in), 8 4D (in), 9 4Q (hiz), 10 GND (power) hidden to GND, 11 C (in), 12 5Q (hiz), 13 5D (in), 14 6D (in), 15 6Q (hiz), 16 7Q (hiz), 17 7D (in), 18 8D (in), 19 8Q (hiz), 20 VCC (power) hidden to VCC
1 alternate drawing of the same symbol

## SN74LS374
designator U?
OCTAL D-TYPE EDGE TRIGGERED FF 3SO
footprint DIP-20
pins: 1 ~{OC} (in), 2 1Q (hiz), 3 1D (in), 4 2D (in), 5 2Q (hiz), 6 3Q (hiz), 7 3D (in), 8 4D (in), 9 4Q (hiz), 10 GND (power) hidden to GND, 11 CLK (in), 12 5Q (hiz), 13 5D (in), 14 6D (in), 15 6Q (hiz), 16 7Q (hiz), 17 7D (in), 18 8D (in), 19 8Q (hiz), 20 VCC (power) hidden to VCC
1 alternate drawing of the same symbol

## SN74LS375
designator U?
4-BIT BISTABLE LCH
footprint SO16
footprint DIP-16
part A pins: 1 1D (in), 2 1~{Q} (out), 3 1Q (out), 4 1C,2C (in), 5 2Q (out), 6 2~{Q} (out), 7 2D (in), 8 GND (power) hidden to GND, 16 VCC (power) hidden to VCC
part B pins: 8 GND (power) hidden to GND, 9 1D (in), 10 1~{Q} (out), 11 1Q (out), 12 1C,2C (in), 13 2Q (out), 14 2~{Q} (out), 15 2D (in), 16 VCC (power) hidden to VCC
1 alternate drawing of the same symbol

## SN74LS377
designator U?
OCTAL D-TYPE FF WITH ENABLE
footprint DIP-20
footprint SO20W
pins: 1 ~{G} (in), 2 1Q (out), 3 1D (in), 4 2D (in), 5 2Q (out), 6 3Q (out), 7 3D (in), 8 4D (in), 9 4Q (out), 10 GND (power) hidden to GND, 11 CLK (in), 12 5Q (out), 13 5D (in), 14 6D (in), 15 6Q (out), 16 7Q (out), 17 7D (in), 18 8D (in), 19 8Q (out), 20 VCC (power) hidden to VCC
1 alternate drawing of the same symbol

## SN74LS378
designator U?
HEX D-TYPE FF WITH ENABLE
footprint SO16
footprint DIP-16
pins: 1 ~{G} (in), 2 1Q (out), 3 1D (in), 4 2D (in), 5 2Q (out), 6 3D (in), 7 3Q (out), 8 GND (power) hidden to GND, 9 CLK (in), 10 4Q (out), 11 4D (in), 12 5Q (out), 13 5D (in), 14 6D (in), 15 6Q (out), 16 VCC (power) hidden to VCC
1 alternate drawing of the same symbol

## SN74LS379
designator U?
QUAD D-TYPE FF WITH ENABLE
footprint DIP-16
footprint SO16
pins: 1 ~{G} (in), 2 1Q (out), 3 1~{Q} (out), 4 1D (in), 5 2D (in), 6 2~{Q} (out), 7 2Q (out), 8 GND (power) hidden to GND, 9 CLK (in), 10 3Q (out), 11 3~{Q} (out), 12 3D (in), 13 4D (in), 14 4~{Q} (out), 15 4Q (out), 16 VCC (power) hidden to VCC
1 alternate drawing of the same symbol

## SN74LS381A
designator U?
ALU/FN GNR
footprint SO20W
footprint DIP-20
footprint SO16W
pins: 1 A1 (in), 2 B1 (in), 3 A0 (in), 4 B0 (in), 5 S0 (in), 6 S1 (in), 7 S2 (in), 8 F0 (out), 9 F1 (out), 10 GND (power) hidden to GND, 11 F2 (out), 12 F3 (out), 13 ~{G} (out), 14 ~{P} (out), 15 Cn (in), 16 B3 (in), 17 A3 (in), 18 B2 (in), 19 A2 (in), 20 VCC (power) hidden to VCC
1 alternate drawing of the same symbol

## SN74LS382A
designator U?
ALU/FN GNR
footprint DIP-20
footprint SO20W
pins: 1 A1 (in), 2 B1 (in), 3 A0 (in), 4 B0 (in), 5 S0 (in), 6 S1 (in), 7 S2 (in), 8 F0 (out), 9 F1 (out), 10 GND (power) hidden to GND, 11 F2 (out), 12 F3 (out), 13 OVR (out), 14 Cn+4 (out), 15 Cn (in), 16 B3 (in), 17 A3 (in), 18 B2 (in), 19 A2 (in), 20 VCC (power) hidden to VCC
1 alternate drawing of the same symbol

## SN74LS384
designator U?
8-BY-1-BIT TWO COMPLEMENT MULT
footprint DIP-16
pins: 1 ~{CLR} (in), 2 X3 (in), 3 X2 (in), 4 X1 (in), 5 X0 (in), 6 PROD (out), 7 CLK (in), 8 GND (power) hidden to GND, 9 MODE (in), 10 K (in), 11 X7 (in), 12 X6 (in), 13 X5 (in), 14 X4 (in), 15 Y (in), 16 VCC (power) hidden to VCC
1 alternate drawing of the same symbol

## SN74LS385
designator U?
QUAD SER ADDER/SUBTRACTER
footprint DIP-20
footprint SO20W
pins: 1 CLK (in), 2 (out), 3 1S/~{A} (in), 4 1B (in), 5 1A (in), 6 2A (in), 7 2B (in), 8 2S/~{A} (in), 9 (out), 10 GND (power) hidden to GND, 11 CLR (in), 12 (out), 13 3S/~{A} (in), 14 3B (in), 15 3A (in), 16 4A (in), 17 4B (in), 18 4S/~{A} (in), 19 (out), 20 VCC (power) hidden to VCC
1 alternate drawing of the same symbol

## SN74LS386A
designator U?
QUAD 2-IN XOR
footprint DIP-14
footprint SO14
part A pins: 1 (in), 2 (in), 3 (out), 7 GND (power) hidden to GND, 14 VCC (power) hidden to VCC
part B pins: 4 (out), 5 (in), 6 (in), 7 GND (power) hidden to GND, 14 VCC (power) hidden to VCC
part C pins: 7 GND (power) hidden to GND, 8 (in), 9 (in), 10 (out), 14 VCC (power) hidden to VCC
part D pins: 7 GND (power) hidden to GND, 11 (out), 12 (in), 13 (in), 14 VCC (power) hidden to VCC
1 alternate drawing of the same symbol

## SN74LS390
designator U?
DUAL 4-BIT AND BIN CNT
footprint SO16
footprint DIP-16
part A pins: 1 1CKA (in), 2 1CLR (in), 3 1QA (out), 4 1CKB (in), 5 1QB (out), 6 1QC (out), 7 1QD (out), 8 GND (power) hidden to GND, 16 VCC (power) hidden to VCC
part B pins: 8 GND (power) hidden to GND, 9 2QD (out), 10 2QC (out), 11 2QB (out), 12 2CKB (in), 13 2QA (out), 14 2CLR (in), 15 2CKA (in), 16 VCC (power) hidden to VCC
1 alternate drawing of the same symbol

## SN74LS393
designator U?
DUAL 4-BIT AND BIN CNT
footprint DIP-14
part A pins: 1 CKA (in), 2 CLR (in), 3 QA (out), 4 QB (out), 5 QC (out), 6 QD (out), 7 GND (power) hidden to GND, 14 VCC (power) hidden to VCC
part B pins: 7 GND (power) hidden to GND, 8 QD (out), 9 QC (out), 10 QB (out), 11 QA (out), 12 CLR (in), 13 CKA (in), 14 VCC (power) hidden to VCC
1 alternate drawing of the same symbol

## SN74LS395A
designator U?
4-BIT CASCADABLE SFT REG 3SO
footprint SO16
footprint DIP-16
pins: 1 ~{CLR} (in), 2 SER (in), 3 A (in), 4 B (in), 5 C (in), 6 D (in), 7 LD/~{SH} (in), 8 GND (power) hidden to GND, 9 ~{OC} (in), 10 CLK (in), 11 QD1 (out), 12 QD (out), 13 QC (out), 14 QB (out), 15 QA (out), 16 VCC (power) hidden to VCC
1 alternate drawing of the same symbol

## SN74LS396
designator U?
OCTAL STORAGE REG
footprint SO16
footprint DIP-16
pins: 1 2Q1 (out), 2 1Q1 (out), 3 D1 (in), 4 2Q2 (out), 5 1Q2 (out), 6 D2 (in), 7 CLK (in), 8 GND (power) hidden to GND, 9 D3 (in), 10 1Q3 (out), 11 2Q3 (out), 12 D4 (in), 13 1Q4 (out), 14 2Q4 (out), 15 STROBE ~{G} (in), 16 VCC (power) hidden to VCC
1 alternate drawing of the same symbol

## SN74LS399
designator U?
QUAD 2-IN MUX WITH STORAGE
footprint SO16
footprint DIP-16
pins: 1 WS (in), 2 QA (out), 3 A1 (in), 4 A2 (in), 5 B2 (in), 6 B1 (in), 7 QB (out), 8 GND (power) hidden to GND, 9 CLK (in), 10 QC (out), 11 C1 (in), 12 C2 (in), 13 D2 (in), 14 D1 (in), 15 QD (out), 16 VCC (power) hidden to VCC
1 alternate drawing of the same symbol

## SN74LS422
designator U?
RETRIGGERABLE MONOSTABLE MULTIVIBRATOR
footprint SO14
footprint DIP-14
pins: 1 A1 (in), 2 A2 (in), 3 B1 (in), 4 B2 (in), 5 ~{CLR} (in), 6 ~{Q} (out), 7 GND (power) hidden to GND, 8 Q (out), 9 Rint, 11 Cext, 13 Rext/Cext, 14 VCC (power) hidden to VCC
1 alternate drawing of the same symbol

## SN74LS423
designator U?
RETRIGGERABLE MONOSTABLE MULTIVIBRATOR
footprint SO16
footprint DIP-16
part A pins: 1 A (in), 2 B (in), 3 ~{CLR} (in), 4 ~{Q} (out), 8 GND (power) hidden to GND, 13 Q (out), 14 Cext, 15 Rext/Cext, 16 VCC (power) hidden to VCC
part B pins: 5 Q (out), 6 Cext, 7 Rext/Cext, 8 GND (power) hidden to GND, 9 A (in), 10 B (in), 11 ~{CLR} (in), 12 ~{Q} (out), 16 VCC (power) hidden to VCC
1 alternate drawing of the same symbol

## SN74LS440
designator U?
QUAD TRIDIRECTIONAL BUS TRANSCEIVERS
footprint SO20W
footprint DIP-20
pins: 1 ~{CS} (in), 2 B1 (in), 3 C1 (in), 4 C2 (in), 5 B2 (in), 6 B3 (in), 7 C3 (in), 8 C4 (in), 9 B4 (in), 10 GND (power) hidden to GND, 11 S0 (in), 12 S1 (in), 13 A4 (in), 14 A3 (in), 15 A2 (in), 16 A1 (in), 17 ~{G}A (in), 18 ~{G}B (in), 19 ~{G}C (in), 20 VCC (power) hidden to VCC
1 alternate drawing of the same symbol

## SN74LS441
designator U?
QUAD TRIDIRECTIONAL BUS TRANSCEIVERS
footprint DIP-20
footprint SO20W
pins: 1 ~{CS} (in), 2 B1 (in), 3 C1 (in), 4 C2 (in), 5 B2 (in), 6 B3 (in), 7 C3 (in), 8 C4 (in), 9 B4 (in), 10 GND (power) hidden to GND, 11 S0 (in), 12 S1 (in), 13 A4 (in), 14 A3 (in), 15 A2 (in), 16 A1 (in), 17 ~{G}A (in), 18 ~{G}B (in), 19 ~{G}C (in), 20 VCC (power) hidden to VCC
1 alternate drawing of the same symbol

## SN74LS442
designator U?
QUAD TRIDIRECTIONAL BUS TRANSCEIVERS
footprint SO20W
footprint DIP-20
pins: 1 ~{CS} (in), 2 B1 (in), 3 C1 (in), 4 C2 (in), 5 B2 (in), 6 B3 (in), 7 C3 (in), 8 C4 (in), 9 B4 (in), 10 GND (power) hidden to GND, 11 S0 (in), 12 S1 (in), 13 A4 (in), 14 A3 (in), 15 A2 (in), 16 A1 (in), 17 ~{G}A (in), 18 ~{G}B (in), 19 ~{G}C (in), 20 VCC (power) hidden to VCC
1 alternate drawing of the same symbol

## SN74LS444
designator U?
QUAD TRIDIRECTIONAL BUS TRANSCEIVERS
footprint SO20W
footprint DIP-20
pins: 1 ~{CS} (in), 2 B1 (in), 3 C1 (in), 4 C2 (in), 5 B2 (in), 6 B3 (in), 7 C3 (in), 8 C4 (in), 9 B4 (in), 10 GND (power) hidden to GND, 11 S0 (in), 12 S1 (in), 13 A4 (in), 14 A3 (in), 15 A2 (in), 16 A1 (in), 17 ~{G}A (in), 18 ~{G}B (in), 19 ~{G}C (in), 20 VCC (power) hidden to VCC
1 alternate drawing of the same symbol

## SN74LS445
designator U?
BCD-TO-DECIMAL DEC/DRV
footprint SO16
footprint DIP-16
pins: 1 0 (oc), 2 1 (oc), 3 2 (oc), 4 3 (oc), 5 4 (oc), 6 5 (oc), 7 6 (oc), 8 GND (power) hidden to GND, 9 7 (oc), 10 8 (oc), 11 9 (oc), 12 D (in), 13 C (in), 14 B (in), 15 A (in), 16 VCC (power) hidden to VCC
1 alternate drawing of the same symbol

## SN74LS446
designator U?
QUAD BUS TRANSCEIVER WITH INDIVIDUAL DIR CONTROL
footprint SO16
footprint DIP-16
pins: 1 ~{G}BA (in), 2 A1 (hiz), 3 DIR2 (in), 4 A2 (hiz), 5 A3 (hiz), 6 DIR3 (in), 7 A4 (hiz), 8 GND (power) hidden to GND, 9 B4 (in), 10 DIR4 (in), 11 B3 (in), 12 B2 (in), 13 DIR1 (in), 14 B1 (in), 15 ~{G}AB (in), 16 VCC (power) hidden to VCC
1 alternate drawing of the same symbol


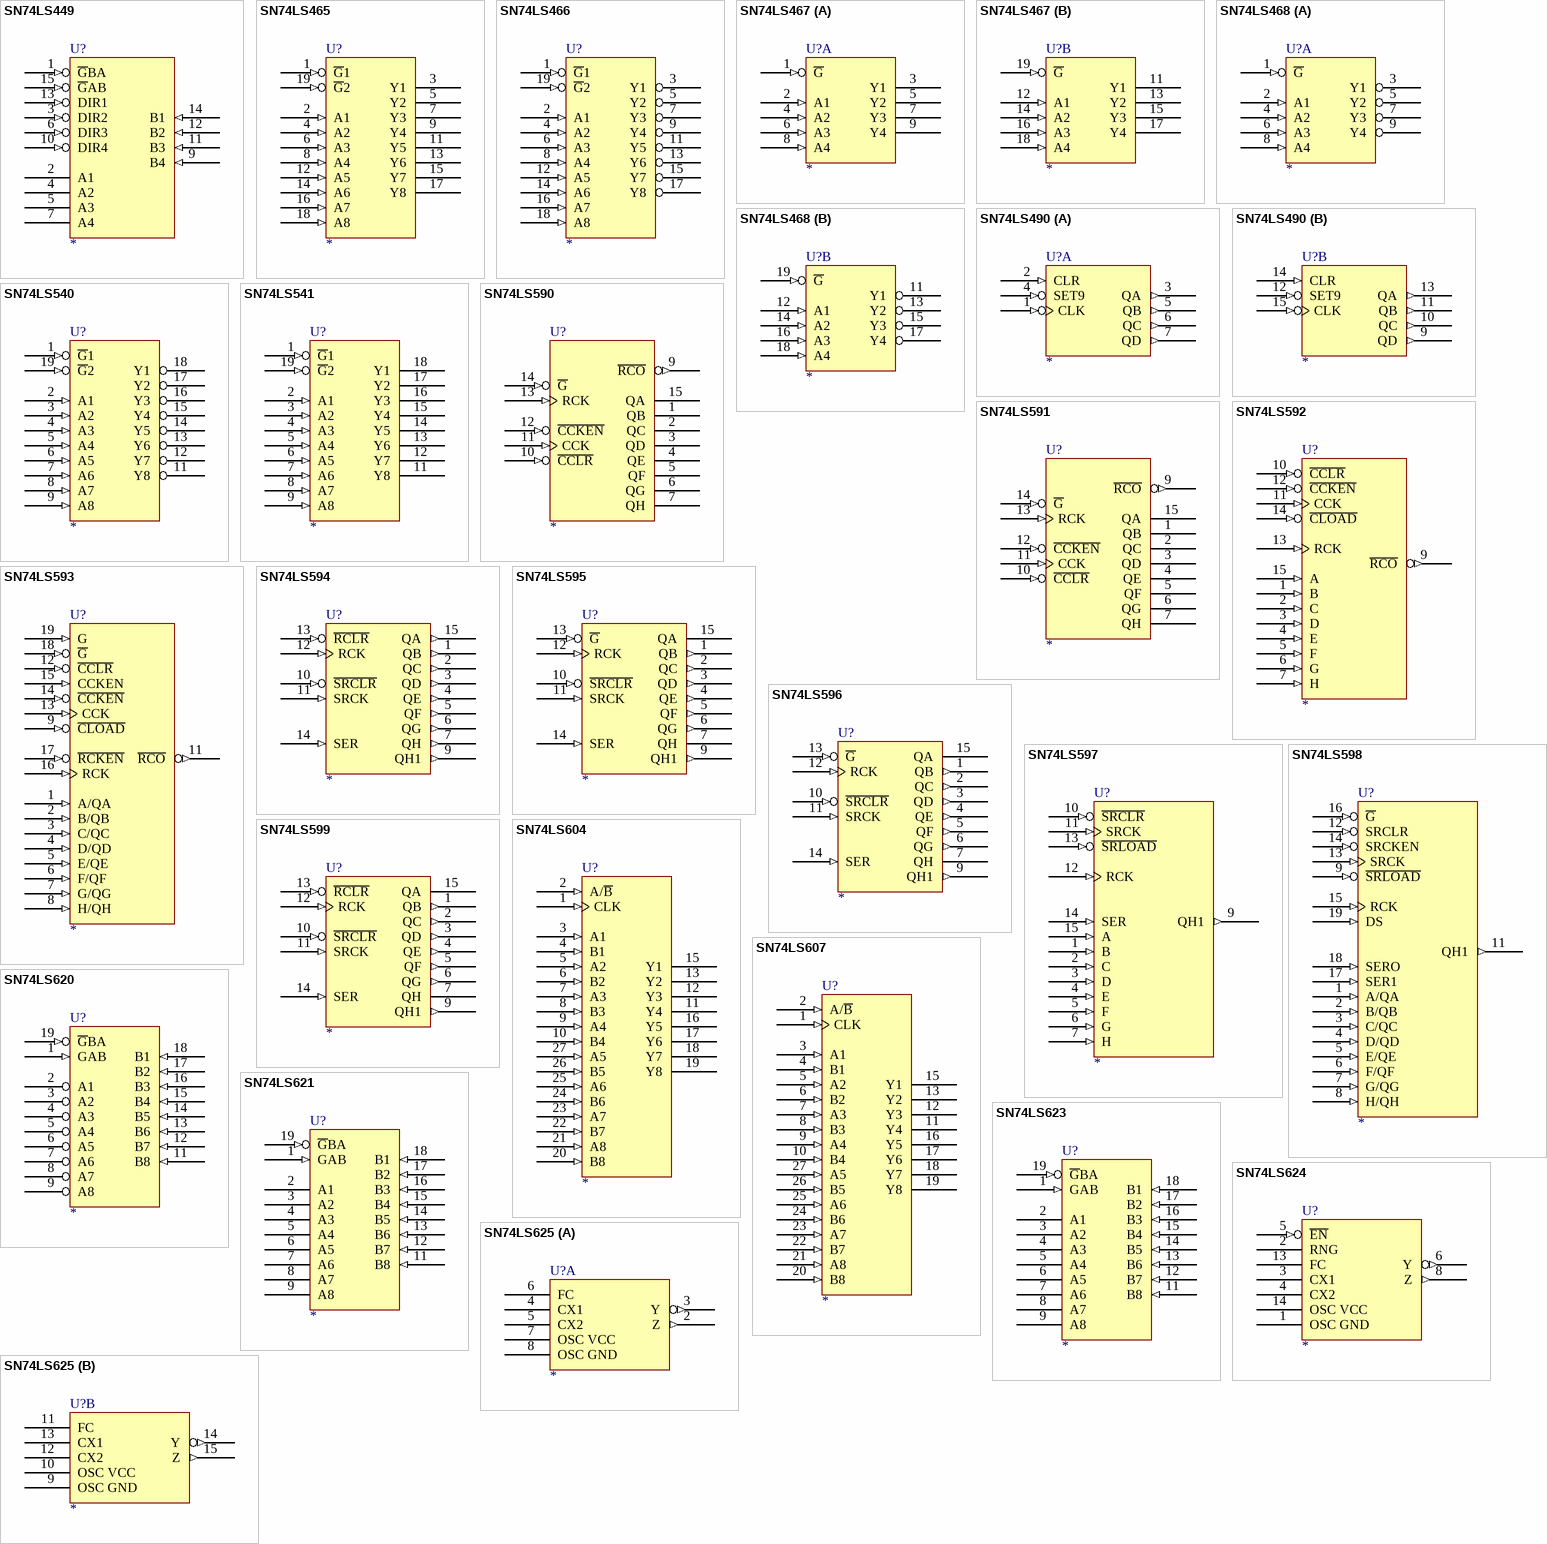
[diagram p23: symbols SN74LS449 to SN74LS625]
## SN74LS449
designator U?
QUAD BUS TRANSCEIVER WITH INDIVIDUAL DIR CONTROL
footprint DIP-16
footprint SO16
pins: 1 ~{G}BA (in), 2 A1 (hiz), 3 DIR2 (in), 4 A2 (hiz), 5 A3 (hiz), 6 DIR3 (in), 7 A4 (hiz), 8 GND (power) hidden to GND, 9 B4 (in), 10 DIR4 (in), 11 B3 (in), 12 B2 (in), 13 DIR1 (in), 14 B1 (in), 15 ~{G}AB (in), 16 VCC (power) hidden to VCC
1 alternate drawing of the same symbol

## SN74LS465
designator U?
OCTAL BUF 3SO
footprint SO20W
footprint DIP-20
pins: 1 ~{G}1 (in), 2 A1 (in), 3 Y1 (hiz), 4 A2 (in), 5 Y2 (hiz), 6 A3 (in), 7 Y3 (hiz), 8 A4 (in), 9 Y4 (hiz), 10 GND (power) hidden to GND, 11 Y5 (hiz), 12 A5 (in), 13 Y6 (hiz), 14 A6 (in), 15 Y7 (hiz), 16 A7 (in), 17 Y8 (hiz), 18 A8 (in), 19 ~{G}2 (in), 20 VCC (power) hidden to VCC
1 alternate drawing of the same symbol

## SN74LS466
designator U?
OCTAL BUF 3SO
footprint DIP-20
footprint SO20W
pins: 1 ~{G}1 (in), 2 A1 (in), 3 Y1 (hiz), 4 A2 (in), 5 Y2 (hiz), 6 A3 (in), 7 Y3 (hiz), 8 A4 (in), 9 Y4 (hiz), 10 GND (power) hidden to GND, 11 Y5 (hiz), 12 A5 (in), 13 Y6 (hiz), 14 A6 (in), 15 Y7 (hiz), 16 A7 (in), 17 Y8 (hiz), 18 A8 (in), 19 ~{G}2 (in), 20 VCC (power) hidden to VCC
1 alternate drawing of the same symbol

## SN74LS467
designator U?
OCTAL BUF 3SO
footprint DIP-20
footprint SO20W
part A pins: 1 ~{G} (in), 2 A1 (in), 3 Y1 (hiz), 4 A2 (in), 5 Y2 (hiz), 6 A3 (in), 7 Y3 (hiz), 8 A4 (in), 9 Y4 (hiz), 10 GND (power) hidden to GND, 20 VCC (power) hidden to VCC
part B pins: 10 GND (power) hidden to GND, 11 Y1 (hiz), 12 A1 (in), 13 Y2 (hiz), 14 A2 (in), 15 Y3 (hiz), 16 A3 (in), 17 Y4 (hiz), 18 A4 (in), 19 ~{G} (in), 20 VCC (power) hidden to VCC
1 alternate drawing of the same symbol

## SN74LS468
designator U?
OCTAL BUF 3SO
footprint DIP-20
footprint SO20W
part A pins: 1 ~{G} (in), 2 A1 (in), 3 Y1 (hiz), 4 A2 (in), 5 Y2 (hiz), 6 A3 (in), 7 Y3 (hiz), 8 A4 (in), 9 Y4 (hiz), 10 GND (power) hidden to GND, 20 VCC (power) hidden to VCC
part B pins: 10 GND (power) hidden to GND, 11 Y1 (hiz), 12 A1 (in), 13 Y2 (hiz), 14 A2 (in), 15 Y3 (hiz), 16 A3 (in), 17 Y4 (hiz), 18 A4 (in), 19 ~{G} (in), 20 VCC (power) hidden to VCC
1 alternate drawing of the same symbol

## SN74LS490
designator U?
DUAL 4-BIT AND BIN CNT
footprint SO16
footprint DIP-16
part A pins: 1 CLK (in), 2 CLR (in), 3 QA (out), 4 SET9 (in), 5 QB (out), 6 QC (out), 7 QD (out), 8 GND (power) hidden to GND, 16 VCC (power) hidden to VCC
part B pins: 8 GND (power) hidden to GND, 9 QD (out), 10 QC (out), 11 QB (out), 12 SET9 (in), 13 QA (out), 14 CLR (in), 15 CLK (in), 16 VCC (power) hidden to VCC
1 alternate drawing of the same symbol

## SN74LS540
designator U?
OCTAL BUF AND LINE DRV 3SO
footprint SO20W
footprint DIP-20
pins: 1 ~{G}1 (in), 2 A1 (in), 3 A2 (in), 4 A3 (in), 5 A4 (in), 6 A5 (in), 7 A6 (in), 8 A7 (in), 9 A8 (in), 10 GND (power) hidden to GND, 11 Y8 (hiz), 12 Y7 (hiz), 13 Y6 (hiz), 14 Y5 (hiz), 15 Y4 (hiz), 16 Y3 (hiz), 17 Y2 (hiz), 18 Y1 (hiz), 19 ~{G}2 (in), 20 VCC (power) hidden to VCC
1 alternate drawing of the same symbol

## SN74LS541
designator U?
OCTAL BUF AND LINE DRV 3SO
footprint SO20W
footprint DIP-20
pins: 1 ~{G}1 (in), 2 A1 (in), 3 A2 (in), 4 A3 (in), 5 A4 (in), 6 A5 (in), 7 A6 (in), 8 A7 (in), 9 A8 (in), 10 GND (power) hidden to GND, 11 Y8 (hiz), 12 Y7 (hiz), 13 Y6 (hiz), 14 Y5 (hiz), 15 Y4 (hiz), 16 Y3 (hiz), 17 Y2 (hiz), 18 Y1 (hiz), 19 ~{G}2 (in), 20 VCC (power) hidden to VCC
1 alternate drawing of the same symbol

## SN74LS590
designator U?
8-BIT BIN CNT WITH OUTPUT REGISTERS
footprint DIP-16
pins: 1 QB (hiz), 2 QC (hiz), 3 QD (hiz), 4 QE (hiz), 5 QF (hiz), 6 QG (hiz), 7 QH (hiz), 8 GND (power) hidden to GND, 9 ~{RCO} (out), 10 ~{CCLR} (in), 11 CCK (in), 12 ~{CCKEN} (in), 13 RCK (in), 14 ~{G} (in), 15 QA (hiz), 16 VCC (power) hidden to VCC
1 alternate drawing of the same symbol

## SN74LS591
designator U?
8-BIT BIN CNT WITH OUTPUT REGISTERS
footprint DIP-16
pins: 1 QB (oc), 2 QC (oc), 3 QD (oc), 4 QE (oc), 5 QF (oc), 6 QG (oc), 7 QH (oc), 8 GND (power) hidden to GND, 9 ~{RCO} (out), 10 ~{CCLR} (in), 11 CCK (in), 12 ~{CCKEN} (in), 13 RCK (in), 14 ~{G} (in), 15 QA (oc), 16 VCC (power) hidden to VCC
1 alternate drawing of the same symbol

## SN74LS592
designator U?
8-BIT BIN CNT WITH INPUT REG
footprint DIP-16
pins: 1 B (in), 2 C (in), 3 D (in), 4 E (in), 5 F (in), 6 G (in), 7 H (in), 8 GND (power) hidden to GND, 9 ~{RCO} (out), 10 ~{CCLR} (in), 11 CCK (in), 12 ~{CCKEN} (in), 13 RCK (in), 14 ~{CLOAD} (in), 15 A (in), 16 VCC (power) hidden to VCC
1 alternate drawing of the same symbol

## SN74LS593
designator U?
8-BIT BIN CNT WITH INPUT REG
footprint SO20W
footprint DIP-20
pins: 1 A/QA (in), 2 B/QB (in), 3 C/QC (in), 4 D/QD (in), 5 E/QE (in), 6 F/QF (in), 7 G/QG (in), 8 H/QH (in), 9 ~{CLOAD} (in), 10 GND (power) hidden to GND, 11 ~{RCO} (out), 12 ~{CCLR} (in), 13 CCK (in), 14 ~{CCKEN} (in), 15 CCKEN (in), 16 RCK (in), 17 ~{RCKEN} (in), 18 ~{G} (in), 19 G (in), 20 VCC (power) hidden to VCC
1 alternate drawing of the same symbol

## SN74LS594
designator U?
8-BIT SFT REG WIRTH OUTPUT LCH
footprint DIP-16
pins: 1 QB (out), 2 QC (out), 3 QD (out), 4 QE (out), 5 QF (out), 6 QG (out), 7 QH (out), 8 GND (power) hidden to GND, 9 QH1 (out), 10 ~{SRCLR} (in), 11 SRCK (in), 12 RCK (in), 13 ~{RCLR} (in), 14 SER (in), 15 QA (out), 16 VCC (power) hidden to VCC
1 alternate drawing of the same symbol

## SN74LS595
designator U?
8-BIT SFT REG WIRTH OUTPUT LCH
footprint DIP-16
pins: 1 QB (out), 2 QC (out), 3 QD (out), 4 QE (out), 5 QF (out), 6 QG (out), 7 QH (hiz), 8 GND (power) hidden to GND, 9 QH1 (out), 10 ~{SRCLR} (in), 11 SRCK (in), 12 RCK (in), 13 ~{G} (in), 14 SER (in), 15 QA (hiz), 16 VCC (power) hidden to VCC
1 alternate drawing of the same symbol

## SN74LS596
designator U?
8-BIT SFT REG WIRTH OUTPUT LCH
footprint DIP-16
pins: 1 QB (out), 2 QC (out), 3 QD (out), 4 QE (out), 5 QF (out), 6 QG (out), 7 QH (oc), 8 GND (power) hidden to GND, 9 QH1 (out), 10 ~{SRCLR} (in), 11 SRCK (in), 12 RCK (in), 13 ~{G} (in), 14 SER (in), 15 QA (oc), 16 VCC (power) hidden to VCC
1 alternate drawing of the same symbol

## SN74LS597
designator U?
8-BIT SFT REG WITH INPUT LCH
footprint DIP-16
pins: 1 B (in), 2 C (in), 3 D (in), 4 E (in), 5 F (in), 6 G (in), 7 H (in), 8 GND (power) hidden to GND, 9 QH1 (out), 10 ~{SRCLR} (in), 11 SRCK (in), 12 RCK (in), 13 ~{SRLOAD} (in), 14 SER (in), 15 A (in), 16 VCC (power) hidden to VCC
1 alternate drawing of the same symbol

## SN74LS598
designator U?
8-BIT SRG WITH INPUT LCH
footprint SO20W
footprint DIP-20
pins: 1 A/QA (in), 2 B/QB (in), 3 C/QC (in), 4 D/QD (in), 5 E/QE (in), 6 F/QF (in), 7 G/QG (in), 8 H/QH (in), 9 ~{SRLOAD} (in), 10 GND (power) hidden to GND, 11 QH1 (out), 12 SRCLR (in), 13 SRCK (in), 14 SRCKEN (in), 15 RCK (in), 16 ~{G} (in), 17 SER1 (in), 18 SERO (in), 19 DS (in), 20 VCC (power) hidden to VCC
1 alternate drawing of the same symbol

## SN74LS599
designator U?
8-BIT SFT REG WIRTH OUTPUT LCH
footprint DIP-16
pins: 1 QB (out), 2 QC (out), 3 QD (out), 4 QE (out), 5 QF (out), 6 QG (out), 7 QH (oc), 8 GND (power) hidden to GND, 9 QH1 (out), 10 ~{SRCLR} (in), 11 SRCK (in), 12 RCK (in), 13 ~{RCLR} (in), 14 SER (in), 15 QA (oc), 16 VCC (power) hidden to VCC
1 alternate drawing of the same symbol

## SN74LS604
designator U?
OCTAL 2-IN MULTIPLEXED LCH
footprint DIP-28
footprint DIP-28
pins: 1 CLK (in), 2 A/~{B} (in), 3 A1 (in), 4 B1 (in), 5 A2 (in), 6 B2 (in), 7 A3 (in), 8 B3 (in), 9 A4 (in), 10 B4 (in), 11 Y4 (hiz), 12 Y3 (hiz), 13 Y2 (hiz), 14 GND (power) hidden to GND, 15 Y1 (hiz), 16 Y5 (hiz), 17 Y6 (hiz), 18 Y7 (hiz), 19 Y8 (hiz), 20 B8 (in), 21 A8 (in), 22 B7 (in), 23 A7 (in), 24 B6 (in), 25 A6 (in), 26 B5 (in), 27 A5 (in), 28 VCC (power) hidden to VCC
1 alternate drawing of the same symbol

## SN74LS607
designator U?
OCTAL 2-IN MULTIPLEXED LCH
footprint DIP-28
footprint DIP-28
pins: 1 CLK (in), 2 A/~{B} (in), 3 A1 (in), 4 B1 (in), 5 A2 (in), 6 B2 (in), 7 A3 (in), 8 B3 (in), 9 A4 (in), 10 B4 (in), 11 Y4 (oc), 12 Y3 (oc), 13 Y2 (oc), 14 GND (power) hidden to GND, 15 Y1 (oc), 16 Y5 (oc), 17 Y6 (oc), 18 Y7 (oc), 19 Y8 (oc), 20 B8 (in), 21 A8 (in), 22 B7 (in), 23 A7 (in), 24 B6 (in), 25 A6 (in), 26 B5 (in), 27 A5 (in), 28 VCC (power) hidden to VCC
1 alternate drawing of the same symbol

## SN74LS620
designator U?
OCTAL BUS TRANCEIVER
footprint SO20W
footprint DIP-20
pins: 1 GAB (in), 2 A1 (hiz), 3 A2 (hiz), 4 A3 (hiz), 5 A4 (hiz), 6 A5 (hiz), 7 A6 (hiz), 8 A7 (hiz), 9 A8 (hiz), 10 GND (power) hidden to GND, 11 B8 (in), 12 B7 (in), 13 B6 (in), 14 B5 (in), 15 B4 (in), 16 B3 (in), 17 B2 (in), 18 B1 (in), 19 ~{G}BA (in), 20 VCC (power) hidden to VCC
1 alternate drawing of the same symbol

## SN74LS621
designator U?
OCTAL BUS TRANCEIVER
footprint SO20W
footprint DIP-20
pins: 1 GAB (in), 2 A1 (oc), 3 A2 (oc), 4 A3 (oc), 5 A4 (oc), 6 A5 (oc), 7 A6 (oc), 8 A7 (oc), 9 A8 (oc), 10 GND (power) hidden to GND, 11 B8 (in), 12 B7 (in), 13 B6 (in), 14 B5 (in), 15 B4 (in), 16 B3 (in), 17 B2 (in), 18 B1 (in), 19 ~{G}BA (in), 20 VCC (power) hidden to VCC
1 alternate drawing of the same symbol

## SN74LS623
designator U?
OCTAL BUS TRANCEIVER
footprint SO20W
footprint DIP-20
pins: 1 GAB (in), 2 A1 (hiz), 3 A2 (hiz), 4 A3 (hiz), 5 A4 (hiz), 6 A5 (hiz), 7 A6 (hiz), 8 A7 (hiz), 9 A8 (hiz), 10 GND (power) hidden to GND, 11 B8 (in), 12 B7 (in), 13 B6 (in), 14 B5 (in), 15 B4 (in), 16 B3 (in), 17 B2 (in), 18 B1 (in), 19 ~{G}BA (in), 20 VCC (power) hidden to VCC
1 alternate drawing of the same symbol

## SN74LS624
designator U?
VOLTAGE-CONTROLLED OSC
footprint DIP-14
footprint SO14
pins: 1 OSC GND (power), 2 RNG, 3 CX1, 4 CX2, 5 ~{EN} (in), 6 Y (out), 7 GND (power) hidden to GND, 8 Z (out), 9 VCC (power) hidden to VCC, 13 FC, 14 OSC VCC (power)
1 alternate drawing of the same symbol

## SN74LS625
designator U?
VOLTAGE-CONTROLLED OSC
footprint DIP-16
footprint SO16
part A pins: 1 GND (power) hidden to GND, 2 Z (out), 3 Y (out), 4 CX1, 5 CX2, 6 FC, 7 OSC VCC (power), 8 OSC GND (power), 16 VCC (power) hidden to VCC
part B pins: 1 GND (power) hidden to GND, 9 OSC GND (power), 10 OSC VCC (power), 11 FC, 12 CX2, 13 CX1, 14 Y (out), 15 Z (out), 16 VCC (power) hidden to VCC
1 alternate drawing of the same symbol


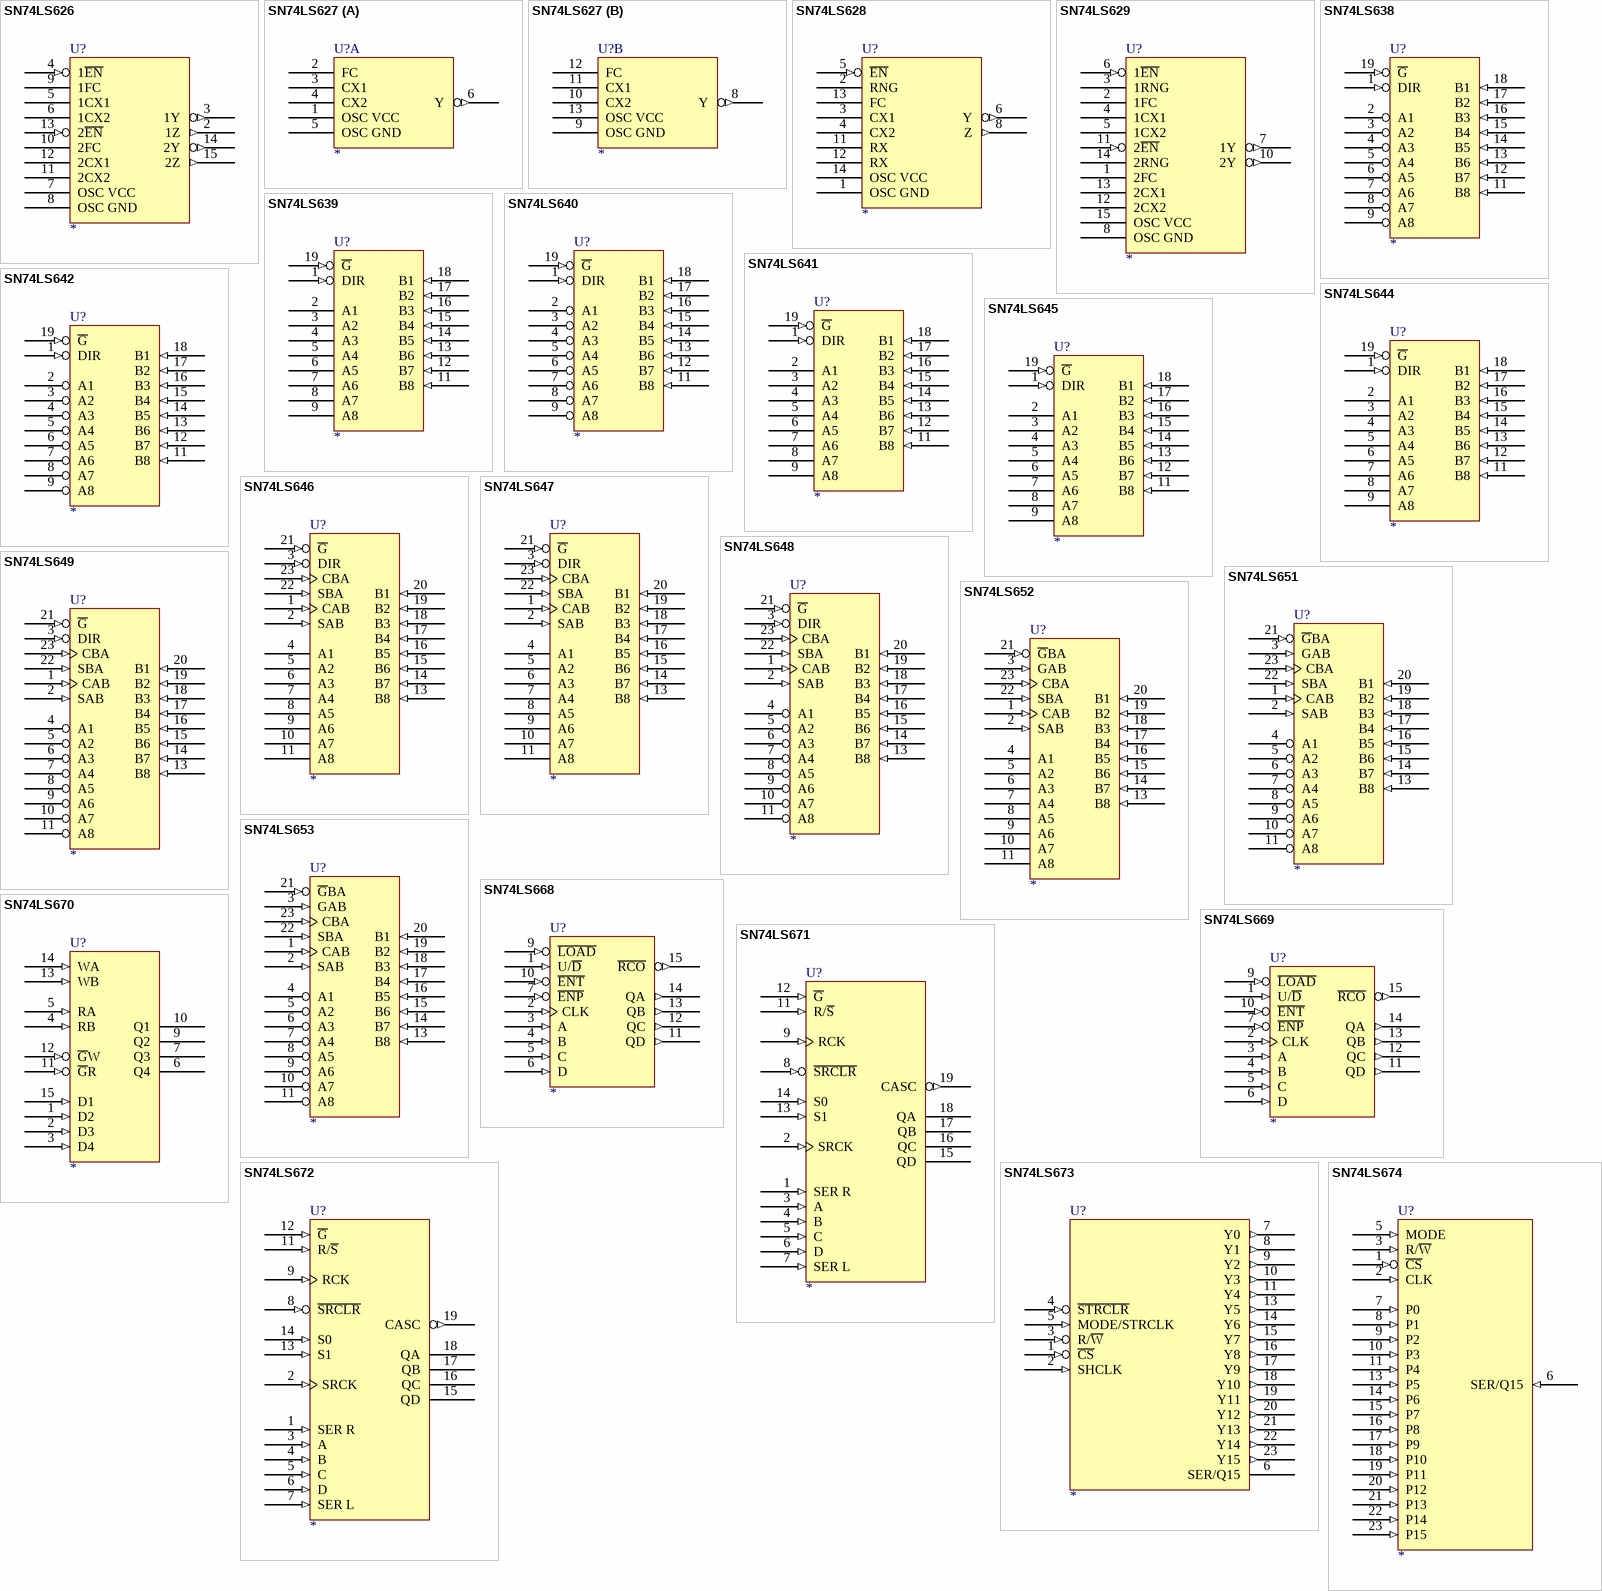
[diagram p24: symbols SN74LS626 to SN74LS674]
## SN74LS626
designator U?
VOLTAGE-CONTROLLED OSC
footprint DIP-16
footprint SO16
pins: 1 GND (power) hidden to GND, 2 1Z (out), 3 1Y (out), 4 1~{EN} (in), 5 1CX1, 6 1CX2, 7 OSC VCC (power), 8 OSC GND (power), 9 1FC, 10 2FC, 11 2CX2, 12 2CX1, 13 2~{EN} (in), 14 2Y (out), 15 2Z (out), 16 VCC (power) hidden to VCC
1 alternate drawing of the same symbol

## SN74LS627
designator U?
VOLTAGE-CONTROLLED OSC
footprint SO14
footprint DIP-14
part A pins: 1 OSC VCC (power), 2 FC, 3 CX1, 4 CX2, 5 OSC GND (power), 6 Y (out), 7 GND (power) hidden to GND, 14 VCC (power) hidden to VCC
part B pins: 7 GND (power) hidden to GND, 8 Y (out), 9 OSC GND (power), 10 CX2, 11 CX1, 12 FC, 13 OSC VCC (power), 14 VCC (power) hidden to VCC
1 alternate drawing of the same symbol

## SN74LS628
designator U?
VOLTAGE-CONTROLLED OSC
footprint DIP-14
footprint SO14
pins: 1 OSC GND (power), 2 RNG, 3 CX1, 4 CX2, 5 ~{EN} (in), 6 Y (out), 7 GND (power) hidden to GND, 8 Z (out), 9 VCC (power) hidden to VCC, 11 RX, 12 RX, 13 FC, 14 OSC VCC (power)
1 alternate drawing of the same symbol

## SN74LS629
designator U?
VOLTAGE-CONTROLLED OSC
footprint SO16
footprint DIP-16
pins: 1 2FC, 2 1FC, 3 1RNG, 4 1CX1, 5 1CX2, 6 1~{EN} (in), 7 1Y (out), 8 OSC GND (power), 9 GND (power) hidden to GND, 10 2Y (out), 11 2~{EN} (in), 12 2CX2, 13 2CX1, 14 2RNG, 15 OSC VCC (power), 16 VCC (power) hidden to VCC
1 alternate drawing of the same symbol

## SN74LS638
designator U?
OCTAL BUS TRANCEIVER
footprint DIP-20
footprint SO20W
pins: 1 DIR (in), 2 A1 (oc), 3 A2 (oc), 4 A3 (oc), 5 A4 (oc), 6 A5 (oc), 7 A6 (oc), 8 A7 (oc), 9 A8 (oc), 10 GND (power) hidden to GND, 11 B8 (in), 12 B7 (in), 13 B6 (in), 14 B5 (in), 15 B4 (in), 16 B3 (in), 17 B2 (in), 18 B1 (in), 19 ~{G} (in), 20 VCC (power) hidden to VCC
1 alternate drawing of the same symbol

## SN74LS639
designator U?
OCTAL BUS TRANCEIVER
footprint DIP-20
footprint SO20W
pins: 1 DIR (in), 2 A1 (oc), 3 A2 (oc), 4 A3 (oc), 5 A4 (oc), 6 A5 (oc), 7 A6 (oc), 8 A7 (oc), 9 A8 (oc), 10 GND (power) hidden to GND, 11 B8 (in), 12 B7 (in), 13 B6 (in), 14 B5 (in), 15 B4 (in), 16 B3 (in), 17 B2 (in), 18 B1 (in), 19 ~{G} (in), 20 VCC (power) hidden to VCC
1 alternate drawing of the same symbol

## SN74LS640
designator U?
OCTAL BUS TRANCEIVER
footprint SO20W
footprint DIP-20
pins: 1 DIR (in), 2 A1 (hiz), 3 A2 (hiz), 4 A3 (hiz), 5 A4 (hiz), 6 A5 (hiz), 7 A6 (hiz), 8 A7 (hiz), 9 A8 (hiz), 10 GND (power) hidden to GND, 11 B8 (in), 12 B7 (in), 13 B6 (in), 14 B5 (in), 15 B4 (in), 16 B3 (in), 17 B2 (in), 18 B1 (in), 19 ~{G} (in), 20 VCC (power) hidden to VCC
1 alternate drawing of the same symbol

## SN74LS641
designator U?
OCTAL BUS TRANCEIVER
footprint DIP-20
footprint SO20W
pins: 1 DIR (in), 2 A1 (oc), 3 A2 (oc), 4 A3 (oc), 5 A4 (oc), 6 A5 (oc), 7 A6 (oc), 8 A7 (oc), 9 A8 (oc), 10 GND (power) hidden to GND, 11 B8 (in), 12 B7 (in), 13 B6 (in), 14 B5 (in), 15 B4 (in), 16 B3 (in), 17 B2 (in), 18 B1 (in), 19 ~{G} (in), 20 VCC (power) hidden to VCC
1 alternate drawing of the same symbol

## SN74LS642
designator U?
OCTAL BUS TRANCEIVER
footprint DIP-20
footprint SO20W
pins: 1 DIR (in), 2 A1 (oc), 3 A2 (oc), 4 A3 (oc), 5 A4 (oc), 6 A5 (oc), 7 A6 (oc), 8 A7 (oc), 9 A8 (oc), 10 GND (power) hidden to GND, 11 B8 (in), 12 B7 (in), 13 B6 (in), 14 B5 (in), 15 B4 (in), 16 B3 (in), 17 B2 (in), 18 B1 (in), 19 ~{G} (in), 20 VCC (power) hidden to VCC
1 alternate drawing of the same symbol

## SN74LS644
designator U?
OCTAL BUS TRANCEIVER
footprint DIP-20
footprint SO20W
pins: 1 DIR (in), 2 A1 (oc), 3 A2 (oc), 4 A3 (oc), 5 A4 (oc), 6 A5 (oc), 7 A6 (oc), 8 A7 (oc), 9 A8 (oc), 10 GND (power) hidden to GND, 11 B8 (in), 12 B7 (in), 13 B6 (in), 14 B5 (in), 15 B4 (in), 16 B3 (in), 17 B2 (in), 18 B1 (in), 19 ~{G} (in), 20 VCC (power) hidden to VCC
1 alternate drawing of the same symbol

## SN74LS645
designator U?
OCTAL BUS TRANCEIVER
footprint DIP-20
footprint SO20W
pins: 1 DIR (in), 2 A1 (hiz), 3 A2 (hiz), 4 A3 (hiz), 5 A4 (hiz), 6 A5 (hiz), 7 A6 (hiz), 8 A7 (hiz), 9 A8 (hiz), 10 GND (power) hidden to GND, 11 B8 (in), 12 B7 (in), 13 B6 (in), 14 B5 (in), 15 B4 (in), 16 B3 (in), 17 B2 (in), 18 B1 (in), 19 ~{G} (in), 20 VCC (power) hidden to VCC
1 alternate drawing of the same symbol

## SN74LS646
designator U?
OCTAL BUS TRANCEIVER AND REG
footprint DIP-24
footprint SO24W
pins: 1 CAB (in), 2 SAB (in), 3 DIR (in), 4 A1 (hiz), 5 A2 (hiz), 6 A3 (hiz), 7 A4 (hiz), 8 A5 (hiz), 9 A6 (hiz), 10 A7 (hiz), 11 A8 (hiz), 12 GND (power) hidden to GND, 13 B8 (in), 14 B7 (in), 15 B6 (in), 16 B5 (in), 17 B4 (in), 18 B3 (in), 19 B2 (in), 20 B1 (in), 21 ~{G} (in), 22 SBA (in), 23 CBA (in), 24 VCC (power) hidden to VCC
1 alternate drawing of the same symbol

## SN74LS647
designator U?
OCTAL BUS TRANCEIVER AND REG
footprint DIP-24
footprint SO24W
pins: 1 CAB (in), 2 SAB (in), 3 DIR (in), 4 A1 (oc), 5 A2 (oc), 6 A3 (oc), 7 A4 (oc), 8 A5 (oc), 9 A6 (oc), 10 A7 (oc), 11 A8 (oc), 12 GND (power) hidden to GND, 13 B8 (in), 14 B7 (in), 15 B6 (in), 16 B5 (in), 17 B4 (in), 18 B3 (in), 19 B2 (in), 20 B1 (in), 21 ~{G} (in), 22 SBA (in), 23 CBA (in), 24 VCC (power) hidden to VCC
1 alternate drawing of the same symbol

## SN74LS648
designator U?
OCTAL BUS TRANCEIVER AND REG
footprint DIP-24
footprint SO24W
pins: 1 CAB (in), 2 SAB (in), 3 DIR (in), 4 A1 (hiz), 5 A2 (hiz), 6 A3 (hiz), 7 A4 (hiz), 8 A5 (hiz), 9 A6 (hiz), 10 A7 (hiz), 11 A8 (hiz), 12 GND (power) hidden to GND, 13 B8 (in), 14 B7 (in), 15 B6 (in), 16 B5 (in), 17 B4 (in), 18 B3 (in), 19 B2 (in), 20 B1 (in), 21 ~{G} (in), 22 SBA (in), 23 CBA (in), 24 VCC (power) hidden to VCC
1 alternate drawing of the same symbol

## SN74LS649
designator U?
OCTAL BUS TRANCEIVER AND REG
footprint SO24W
footprint DIP-24
pins: 1 CAB (in), 2 SAB (in), 3 DIR (in), 4 A1 (oc), 5 A2 (oc), 6 A3 (oc), 7 A4 (oc), 8 A5 (oc), 9 A6 (oc), 10 A7 (oc), 11 A8 (oc), 12 GND (power) hidden to GND, 13 B8 (in), 14 B7 (in), 15 B6 (in), 16 B5 (in), 17 B4 (in), 18 B3 (in), 19 B2 (in), 20 B1 (in), 21 ~{G} (in), 22 SBA (in), 23 CBA (in), 24 VCC (power) hidden to VCC
1 alternate drawing of the same symbol

## SN74LS651
designator U?
OCTAL BUS TRANCEIVER AND REG
footprint DIP-24
footprint SO24W
pins: 1 CAB (in), 2 SAB (in), 3 GAB (in), 4 A1 (hiz), 5 A2 (hiz), 6 A3 (hiz), 7 A4 (hiz), 8 A5 (hiz), 9 A6 (hiz), 10 A7 (hiz), 11 A8 (hiz), 12 GND (power) hidden to GND, 13 B8 (in), 14 B7 (in), 15 B6 (in), 16 B5 (in), 17 B4 (in), 18 B3 (in), 19 B2 (in), 20 B1 (in), 21 ~{G}BA (in), 22 SBA (in), 23 CBA (in), 24 VCC (power) hidden to VCC
1 alternate drawing of the same symbol

## SN74LS652
designator U?
OCTAL BUS TRANCEIVER AND REG
footprint SO24W
footprint DIP-24
pins: 1 CAB (in), 2 SAB (in), 3 GAB (in), 4 A1 (hiz), 5 A2 (hiz), 6 A3 (hiz), 7 A4 (hiz), 8 A5 (hiz), 9 A6 (hiz), 10 A7 (hiz), 11 A8 (hiz), 12 GND (power) hidden to GND, 13 B8 (in), 14 B7 (in), 15 B6 (in), 16 B5 (in), 17 B4 (in), 18 B3 (in), 19 B2 (in), 20 B1 (in), 21 ~{G}BA (in), 22 SBA (in), 23 CBA (in), 24 VCC (power) hidden to VCC
1 alternate drawing of the same symbol

## SN74LS653
designator U?
OCTAL BUS TRANCEIVER AND REG
footprint DIP-24
footprint SO24W
pins: 1 CAB (in), 2 SAB (in), 3 GAB (in), 4 A1 (oc), 5 A2 (oc), 6 A3 (oc), 7 A4 (oc), 8 A5 (oc), 9 A6 (oc), 10 A7 (oc), 11 A8 (oc), 12 GND (power) hidden to GND, 13 B8 (in), 14 B7 (in), 15 B6 (in), 16 B5 (in), 17 B4 (in), 18 B3 (in), 19 B2 (in), 20 B1 (in), 21 ~{G}BA (in), 22 SBA (in), 23 CBA (in), 24 VCC (power) hidden to VCC
1 alternate drawing of the same symbol

## SN74LS668
designator U?
SYNCHRONOUS 4-BIT UP/DOWN CNT
footprint DIP-16
footprint SO16
pins: 1 U/~{D} (in), 2 CLK (in), 3 A (in), 4 B (in), 5 C (in), 6 D (in), 7 ~{ENP} (in), 8 GND (power) hidden to GND, 9 ~{LOAD} (in), 10 ~{ENT} (in), 11 QD (out), 12 QC (out), 13 QB (out), 14 QA (out), 15 ~{RCO} (out), 16 VCC (power) hidden to VCC
1 alternate drawing of the same symbol

## SN74LS669
designator U?
SYNCHRONOUS 4-BIT UP/DOWN CNT
footprint DIP-16
footprint SO16
pins: 1 U/~{D} (in), 2 CLK (in), 3 A (in), 4 B (in), 5 C (in), 6 D (in), 7 ~{ENP} (in), 8 GND (power) hidden to GND, 9 ~{LOAD} (in), 10 ~{ENT} (in), 11 QD (out), 12 QC (out), 13 QB (out), 14 QA (out), 15 ~{RCO} (out), 16 VCC (power) hidden to VCC
1 alternate drawing of the same symbol

## SN74LS670
designator U?
4-BY-4 REG FILES 3SO
footprint SO16
footprint DIP-16
pins: 1 D2 (in), 2 D3 (in), 3 D4 (in), 4 RB (in), 5 RA (in), 6 Q4 (hiz), 7 Q3 (hiz), 8 GND (power) hidden to GND, 9 Q2 (hiz), 10 Q1 (hiz), 11 ~{G}R (in), 12 ~{G}W (in), 13 WB (in), 14 WA (in), 15 D1 (in), 16 VCC (power) hidden to VCC
1 alternate drawing of the same symbol

## SN74LS671
designator U?
4-BIT UNIVERSAL SFT REG/LCH 3SO
footprint SO20W
footprint DIP-20
pins: 1 SER R (in), 2 SRCK (in), 3 A (in), 4 B (in), 5 C (in), 6 D (in), 7 SER L (in), 8 ~{SRCLR} (in), 9 RCK (in), 10 GND (power) hidden to GND, 11 R/~{S} (in), 12 ~{G} (in), 13 S1 (in), 14 S0 (in), 15 QD (hiz), 16 QC (hiz), 17 QB (hiz), 18 QA (hiz), 19 CASC (out), 20 VCC (power) hidden to VCC
1 alternate drawing of the same symbol

## SN74LS672
designator U?
4-BIT UNIVERSAL SFT REG/LCH 3SO
footprint SO20W
footprint DIP-20
pins: 1 SER R (in), 2 SRCK (in), 3 A (in), 4 B (in), 5 C (in), 6 D (in), 7 SER L (in), 8 ~{SRCLR} (in), 9 RCK (in), 10 GND (power) hidden to GND, 11 R/~{S} (in), 12 ~{G} (in), 13 S1 (in), 14 S0 (in), 15 QD (hiz), 16 QC (hiz), 17 QB (hiz), 18 QA (hiz), 19 CASC (out), 20 VCC (power) hidden to VCC
1 alternate drawing of the same symbol

## SN74LS673
designator U?
16-BIT SFT REG
footprint SO24W
footprint DIP-24
pins: 1 ~{CS} (in), 2 SHCLK (in), 3 R/~{W} (in), 4 ~{STRCLR} (in), 5 MODE/STRCLK (in), 6 SER/Q15 (hiz), 7 Y0 (out), 8 Y1 (out), 9 Y2 (out), 10 Y3 (out), 11 Y4 (out), 12 GND (power) hidden to GND, 13 Y5 (out), 14 Y6 (out), 15 Y7 (out), 16 Y8 (out), 17 Y9 (out), 18 Y10 (out), 19 Y11 (out), 20 Y12 (out), 21 Y13 (out), 22 Y14 (out), 23 Y15 (out), 24 VCC (power) hidden to VCC
1 alternate drawing of the same symbol

## SN74LS674
designator U?
16-BIT SFT REG
footprint SO24W
footprint DIP-24
pins: 1 ~{CS} (in), 2 CLK (in), 3 R/~{W} (in), 5 MODE (in), 6 SER/Q15 (in), 7 P0 (in), 8 P1 (in), 9 P2 (in), 10 P3 (in), 11 P4 (in), 12 GND (power) hidden to GND, 13 P5 (in), 14 P6 (in), 15 P7 (in), 16 P8 (in), 17 P9 (in), 18 P10 (in), 19 P11 (in), 20 P12 (in), 21 P13 (in), 22 P14 (in), 23 P15 (in), 24 VCC (power) hidden to VCC
1 alternate drawing of the same symbol


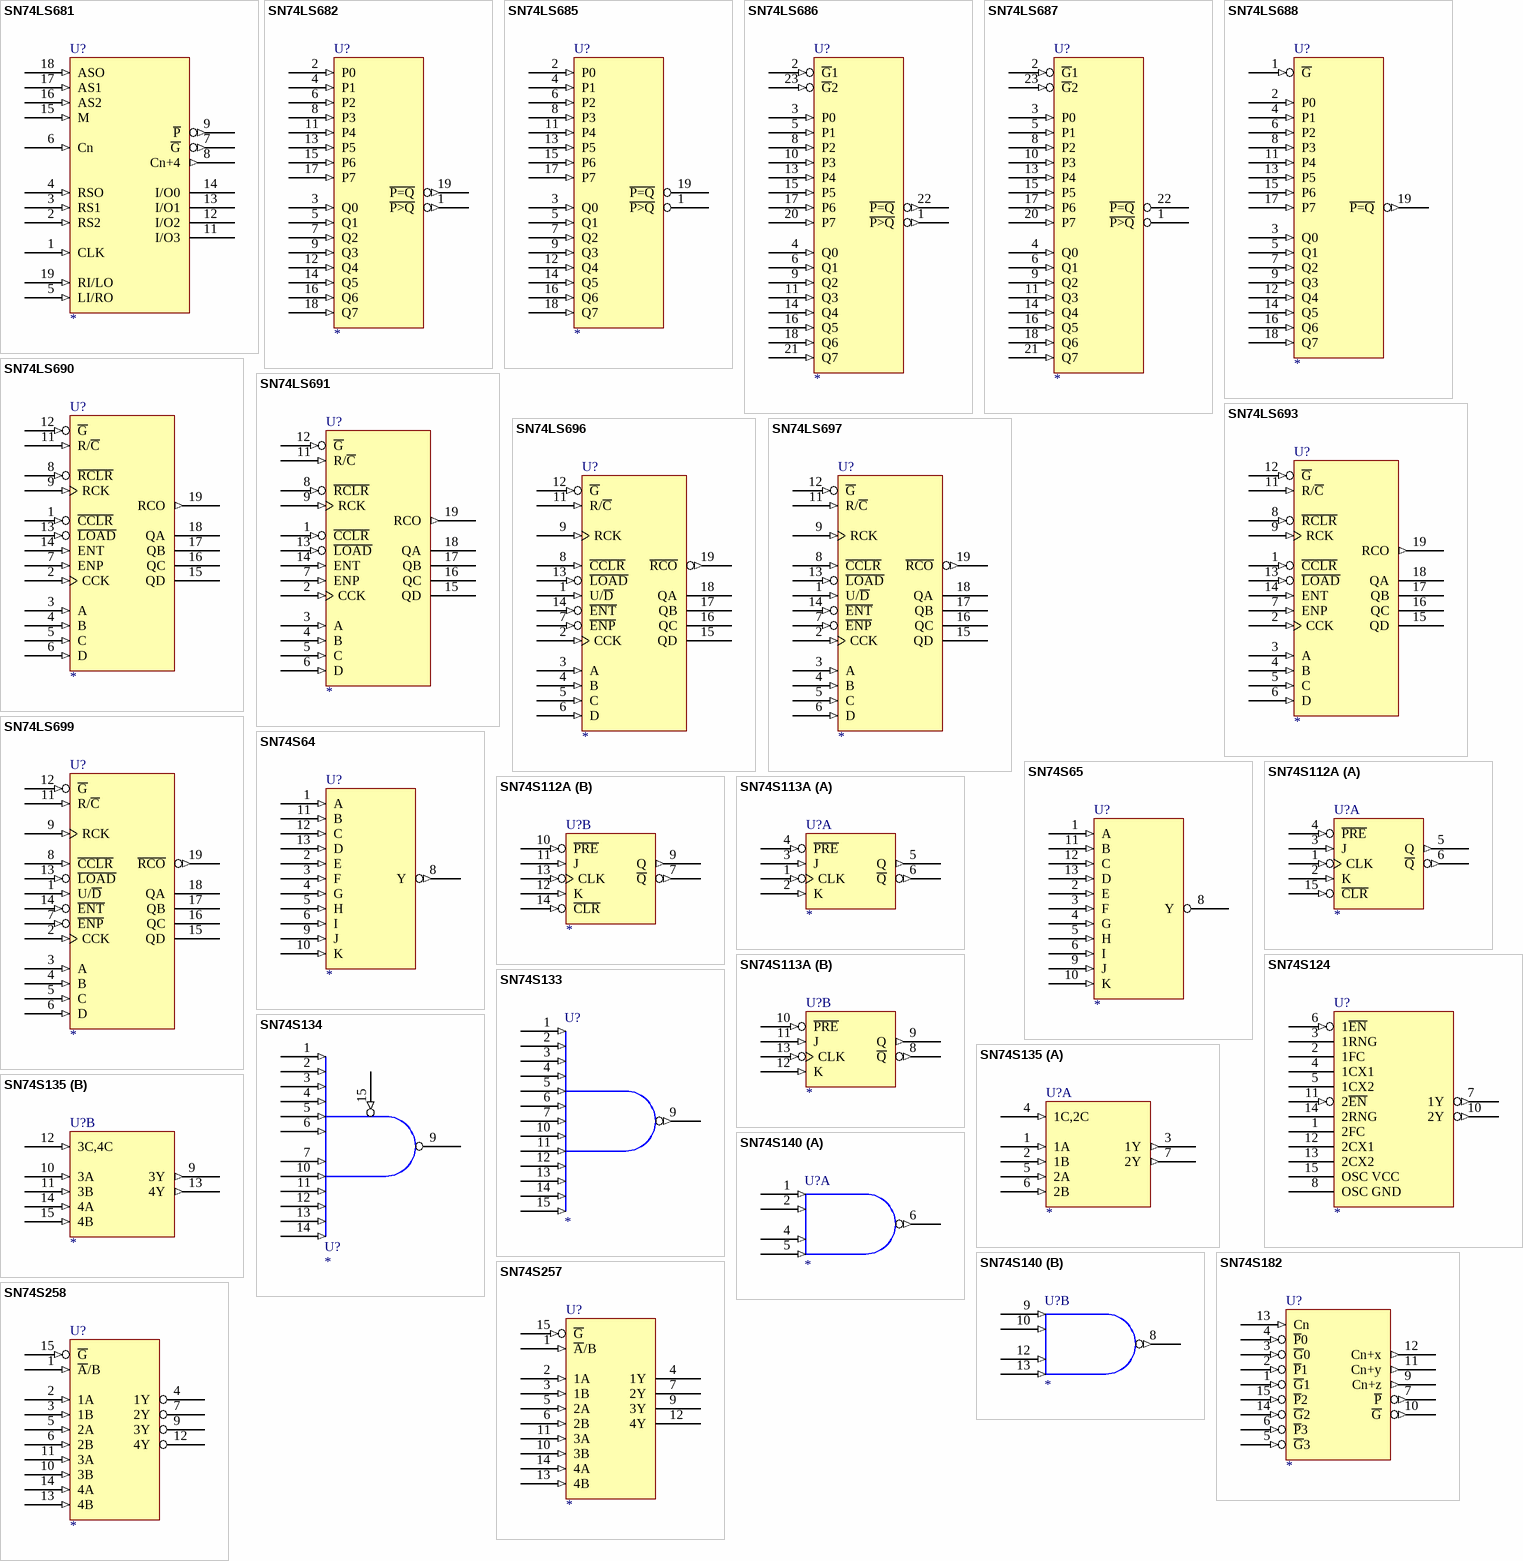
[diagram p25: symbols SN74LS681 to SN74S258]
## SN74LS681
designator U?
4-BIT PARALLEL BIN ACCUMULATOR
footprint DIP-20
footprint SO20W
pins: 1 CLK (in), 2 RS2 (in), 3 RS1 (in), 4 RSO (in), 5 LI/RO (in), 6 Cn (in), 7 ~{G} (out), 8 Cn+4 (out), 9 ~{P} (out), 10 GND (power) hidden to GND, 11 I/O3 (hiz), 12 I/O2 (hiz), 13 I/O1 (hiz), 14 I/O0 (hiz), 15 M (in), 16 AS2 (in), 17 AS1 (in), 18 ASO (in), 19 RI/LO (in), 20 VCC (power) hidden to VCC
1 alternate drawing of the same symbol

## SN74LS682
designator U?
8-BIT MAGNITUDE/IDENTITY COMPARATOR
footprint DIP-20
footprint SO20W
pins: 1 ~{P>Q} (out), 2 P0 (in), 3 Q0 (in), 4 P1 (in), 5 Q1 (in), 6 P2 (in), 7 Q2 (in), 8 P3 (in), 9 Q3 (in), 10 GND (power) hidden to GND, 11 P4 (in), 12 Q4 (in), 13 P5 (in), 14 Q5 (in), 15 P6 (in), 16 Q6 (in), 17 P7 (in), 18 Q7 (in), 19 ~{P=Q} (out), 20 VCC (power) hidden to VCC
1 alternate drawing of the same symbol

## SN74LS685
designator U?
8-BIT MAGNITUDE/IDENTITY COMPARATOR
footprint SO20W
footprint DIP-20
pins: 1 ~{P>Q} (oc), 2 P0 (in), 3 Q0 (in), 4 P1 (in), 5 Q1 (in), 6 P2 (in), 7 Q2 (in), 8 P3 (in), 9 Q3 (in), 10 GND (power) hidden to GND, 11 P4 (in), 12 Q4 (in), 13 P5 (in), 14 Q5 (in), 15 P6 (in), 16 Q6 (in), 17 P7 (in), 18 Q7 (in), 19 ~{P=Q} (oc), 20 VCC (power) hidden to VCC
1 alternate drawing of the same symbol

## SN74LS686
designator U?
8-BIT MAGNITUDE/IDENTITY COMPARATOR
footprint DIP-24
footprint SO24W
pins: 1 ~{P>Q} (out), 2 ~{G}1 (in), 3 P0 (in), 4 Q0 (in), 5 P1 (in), 6 Q1 (in), 8 P2 (in), 9 Q2 (in), 10 P3 (in), 11 Q3 (in), 12 GND (power) hidden to GND, 13 P4 (in), 14 Q4 (in), 15 P5 (in), 16 Q5 (in), 17 P6 (in), 18 Q6 (in), 20 P7 (in), 21 Q7 (in), 22 ~{P=Q} (out), 23 ~{G}2 (in), 24 VCC (power) hidden to VCC
1 alternate drawing of the same symbol

## SN74LS687
designator U?
8-BIT MAGNITUDE/IDENTITY COMPARATOR
footprint DIP-24
footprint SO24W
pins: 1 ~{P>Q} (oc), 2 ~{G}1 (in), 3 P0 (in), 4 Q0 (in), 5 P1 (in), 6 Q1 (in), 8 P2 (in), 9 Q2 (in), 10 P3 (in), 11 Q3 (in), 12 GND (power) hidden to GND, 13 P4 (in), 14 Q4 (in), 15 P5 (in), 16 Q5 (in), 17 P6 (in), 18 Q6 (in), 20 P7 (in), 21 Q7 (in), 22 ~{P=Q} (oc), 23 ~{G}2 (in), 24 VCC (power) hidden to VCC
1 alternate drawing of the same symbol

## SN74LS688
designator U?
8-BIT MAGNITUDE/IDENTITY COMPARATOR
footprint DIP-20
footprint SO20W
pins: 1 ~{G} (in), 2 P0 (in), 3 Q0 (in), 4 P1 (in), 5 Q1 (in), 6 P2 (in), 7 Q2 (in), 8 P3 (in), 9 Q3 (in), 10 GND (power) hidden to GND, 11 P4 (in), 12 Q4 (in), 13 P5 (in), 14 Q5 (in), 15 P6 (in), 16 Q6 (in), 17 P7 (in), 18 Q7 (in), 19 ~{P=Q} (out), 20 VCC (power) hidden to VCC
1 alternate drawing of the same symbol

## SN74LS690
designator U?
SYNCHRONOUS CNT WITH OUTPUT REG AND MUX 3SO
footprint SO20W
footprint DIP-20
pins: 1 ~{CCLR} (in), 2 CCK (in), 3 A (in), 4 B (in), 5 C (in), 6 D (in), 7 ENP (in), 8 ~{RCLR} (in), 9 RCK (in), 10 GND (power) hidden to GND, 11 R/~{C} (in), 12 ~{G} (in), 13 ~{LOAD} (in), 14 ENT (in), 15 QD (hiz), 16 QC (hiz), 17 QB (hiz), 18 QA (hiz), 19 RCO (out), 20 VCC (power) hidden to VCC
1 alternate drawing of the same symbol

## SN74LS691
designator U?
SYNCHRONOUS CNT WITH OUTPUT REG AND MUX 3SO
footprint SO20W
footprint DIP-20
pins: 1 ~{CCLR} (in), 2 CCK (in), 3 A (in), 4 B (in), 5 C (in), 6 D (in), 7 ENP (in), 8 ~{RCLR} (in), 9 RCK (in), 10 GND (power) hidden to GND, 11 R/~{C} (in), 12 ~{G} (in), 13 ~{LOAD} (in), 14 ENT (in), 15 QD (hiz), 16 QC (hiz), 17 QB (hiz), 18 QA (hiz), 19 RCO (out), 20 VCC (power) hidden to VCC
1 alternate drawing of the same symbol

## SN74LS693
designator U?
SYNCHRONOUS CNT WITH OUTPUT REG AND MUX 3SO
footprint DIP-20
footprint SO20W
pins: 1 ~{CCLR} (in), 2 CCK (in), 3 A (in), 4 B (in), 5 C (in), 6 D (in), 7 ENP (in), 8 ~{RCLR} (in), 9 RCK (in), 10 GND (power) hidden to GND, 11 R/~{C} (in), 12 ~{G} (in), 13 ~{LOAD} (in), 14 ENT (in), 15 QD (hiz), 16 QC (hiz), 17 QB (hiz), 18 QA (hiz), 19 RCO (out), 20 VCC (power) hidden to VCC
1 alternate drawing of the same symbol

## SN74LS696
designator U?
SYNCHRONOUS U/D CNT WITH OUTPUT REG AND MUX 3SO
footprint DIP-20
footprint SO20W
pins: 1 U/~{D} (in), 2 CCK (in), 3 A (in), 4 B (in), 5 C (in), 6 D (in), 7 ~{ENP} (in), 8 ~{CCLR} (in), 9 RCK (in), 10 GND (power) hidden to GND, 11 R/~{C} (in), 12 ~{G} (in), 13 ~{LOAD} (in), 14 ~{ENT} (in), 15 QD (hiz), 16 QC (hiz), 17 QB (hiz), 18 QA (hiz), 19 ~{RCO} (out), 20 VCC (power) hidden to VCC
1 alternate drawing of the same symbol

## SN74LS697
designator U?
SYNCHRONOUS U/D CNT WITH OUTPUT REG AND MUX 3SO
footprint DIP-20
footprint SO20W
pins: 1 U/~{D} (in), 2 CCK (in), 3 A (in), 4 B (in), 5 C (in), 6 D (in), 7 ~{ENP} (in), 8 ~{CCLR} (in), 9 RCK (in), 10 GND (power) hidden to GND, 11 R/~{C} (in), 12 ~{G} (in), 13 ~{LOAD} (in), 14 ~{ENT} (in), 15 QD (hiz), 16 QC (hiz), 17 QB (hiz), 18 QA (hiz), 19 ~{RCO} (out), 20 VCC (power) hidden to VCC
1 alternate drawing of the same symbol

## SN74LS699
designator U?
SYNCHRONOUS U/D CNT WITH OUTPUT REG AND MUX 3SO
footprint DIP-20
footprint SO20W
pins: 1 U/~{D} (in), 2 CCK (in), 3 A (in), 4 B (in), 5 C (in), 6 D (in), 7 ~{ENP} (in), 8 ~{CCLR} (in), 9 RCK (in), 10 GND (power) hidden to GND, 11 R/~{C} (in), 12 ~{G} (in), 13 ~{LOAD} (in), 14 ~{ENT} (in), 15 QD (hiz), 16 QC (hiz), 17 QB (hiz), 18 QA (hiz), 19 ~{RCO} (out), 20 VCC (power) hidden to VCC
1 alternate drawing of the same symbol

## SN74S64
designator U?
4-2-3-2 IN AND-OR-INVERT G
footprint SO14
footprint DIP-14
pins: 1 A (in), 2 E (in), 3 F (in), 4 G (in), 5 H (in), 6 I (in), 7 GND (power) hidden to GND, 8 Y (out), 9 J (in), 10 K (in), 11 B (in), 12 C (in), 13 D (in), 14 VCC (power) hidden to VCC
1 alternate drawing of the same symbol

## SN74S65
designator U?
4-2-3-2 IN AND-OR-INVERT G
footprint SO14
footprint DIP-14
pins: 1 A (in), 2 E (in), 3 F (in), 4 G (in), 5 H (in), 6 I (in), 7 GND (power) hidden to GND, 8 Y (oc), 9 J (in), 10 K (in), 11 B (in), 12 C (in), 13 D (in), 14 VCC (power) hidden to VCC
1 alternate drawing of the same symbol

## SN74S112A
designator U?
DUAL J-K NET FF RS CR
footprint SO16
footprint DIP-16
part A pins: 1 CLK (in), 2 K (in), 3 J (in), 4 ~{PRE} (in), 5 Q (out), 6 ~{Q} (out), 8 GND (power) hidden to GND, 15 ~{CLR} (in), 16 VCC (power) hidden to VCC
part B pins: 7 ~{Q} (out), 8 GND (power) hidden to GND, 9 Q (out), 10 ~{PRE} (in), 11 J (in), 12 K (in), 13 CLK (in), 14 ~{CLR} (in), 16 VCC (power) hidden to VCC
1 alternate drawing of the same symbol

## SN74S113A
designator U?
DUAL J-K NET FF RS
footprint SO14
footprint DIP-14
part A pins: 1 CLK (in), 2 K (in), 3 J (in), 4 ~{PRE} (in), 5 Q (out), 6 ~{Q} (out), 7 GND (power) hidden to GND, 14 VCC (power) hidden to VCC
part B pins: 7 GND (power) hidden to GND, 8 ~{Q} (out), 9 Q (out), 10 ~{PRE} (in), 11 J (in), 12 K (in), 13 CLK (in), 14 VCC (power) hidden to VCC
1 alternate drawing of the same symbol

## SN74S124
designator U?
DUAL VOLTAGE-CONTROLLED OSC
footprint SO16
footprint DIP-16
pins: 1 2FC, 2 1FC, 3 1RNG, 4 1CX1, 5 1CX2, 6 1~{EN} (in), 7 1Y (out), 8 OSC GND (power), 9 GND (power) hidden to GND, 10 2Y (out), 11 2~{EN} (in), 12 2CX1, 13 2CX2, 14 2RNG, 15 OSC VCC (power), 16 VCC (power) hidden to VCC
1 alternate drawing of the same symbol

## SN74S133
designator U?
13-IN POS Nand G
footprint SO16
footprint DIP-16
pins: 1 (in), 2 (in), 3 (in), 4 (in), 5 (in), 6 (in), 7 (in), 8 GND (power) hidden to GND, 9 (out), 10 (in), 11 (in), 12 (in), 13 (in), 14 (in), 15 (in), 16 VCC (power) hidden to VCC
2 alternate drawings of the same symbol

## SN74S134
designator U?
12-IN POS Nand G 3SO
footprint SO16
footprint DIP-16
pins: 1 (in), 2 (in), 3 (in), 4 (in), 5 (in), 6 (in), 7 (in), 8 GND (power) hidden to GND, 9 (hiz), 10 (in), 11 (in), 12 (in), 13 (in), 14 (in), 15 (in), 16 VCC (power) hidden to VCC
2 alternate drawings of the same symbol

## SN74S135
designator U?
QUAD XOR/NOR G
footprint SO16
footprint DIP-16
part A pins: 1 1A (in), 2 1B (in), 3 1Y (out), 4 1C,2C (in), 5 2A (in), 6 2B (in), 7 2Y (out), 8 GND (power) hidden to GND, 16 VCC (power) hidden to VCC
part B pins: 8 GND (power) hidden to GND, 9 3Y (out), 10 3A (in), 11 3B (in), 12 3C,4C (in), 13 4Y (out), 14 4A (in), 15 4B (in), 16 VCC (power) hidden to VCC
1 alternate drawing of the same symbol

## SN74S140
designator U?
Dual 4-in Pos Nand 50-OHM LINE DRV
footprint SO14
footprint DIP-14
part A pins: 1 (in), 2 (in), 4 (in), 5 (in), 6 (out), 7 GND (power) hidden to GND, 14 VCC (power) hidden to VCC
part B pins: 7 GND (power) hidden to GND, 8 (out), 9 (in), 10 (in), 12 (in), 13 (in), 14 VCC (power) hidden to VCC
2 alternate drawings of the same symbol

## SN74S182
designator U?
LOOK-AHEAD CARRY GNR
footprint SO16
footprint DIP-16
pins: 1 ~{G}1 (in), 2 ~{P}1 (in), 3 ~{G}0 (in), 4 ~{P}0 (in), 5 ~{G}3 (in), 6 ~{P}3 (in), 7 ~{P} (out), 8 GND (power) hidden to GND, 9 Cn+z (out), 10 ~{G} (out), 11 Cn+y (out), 12 Cn+x (out), 13 Cn (in), 14 ~{G}2 (in), 15 ~{P}2 (in), 16 VCC (power) hidden to VCC
1 alternate drawing of the same symbol

## SN74S257
designator U?
QUAD 2-1LINE DATA SLCR/MUX
footprint SO16
footprint DIP-16
pins: 1 ~{A}/B (in), 2 1A (in), 3 1B (in), 4 1Y (hiz), 5 2A (in), 6 2B (in), 7 2Y (hiz), 8 GND (power) hidden to GND, 9 3Y (hiz), 10 3B (in), 11 3A (in), 12 4Y (hiz), 13 4B (in), 14 4A (in), 15 ~{G} (in), 16 VCC (power) hidden to VCC
1 alternate drawing of the same symbol

## SN74S258
designator U?
QUAD 2-1LINE DATA SLCR/MUX
footprint SO16
footprint DIP-16
pins: 1 ~{A}/B (in), 2 1A (in), 3 1B (in), 4 1Y (hiz), 5 2A (in), 6 2B (in), 7 2Y (hiz), 8 GND (power) hidden to GND, 9 3Y (hiz), 10 3B (in), 11 3A (in), 12 4Y (hiz), 13 4B (in), 14 4A (in), 15 ~{G} (in), 16 VCC (power) hidden to VCC
1 alternate drawing of the same symbol


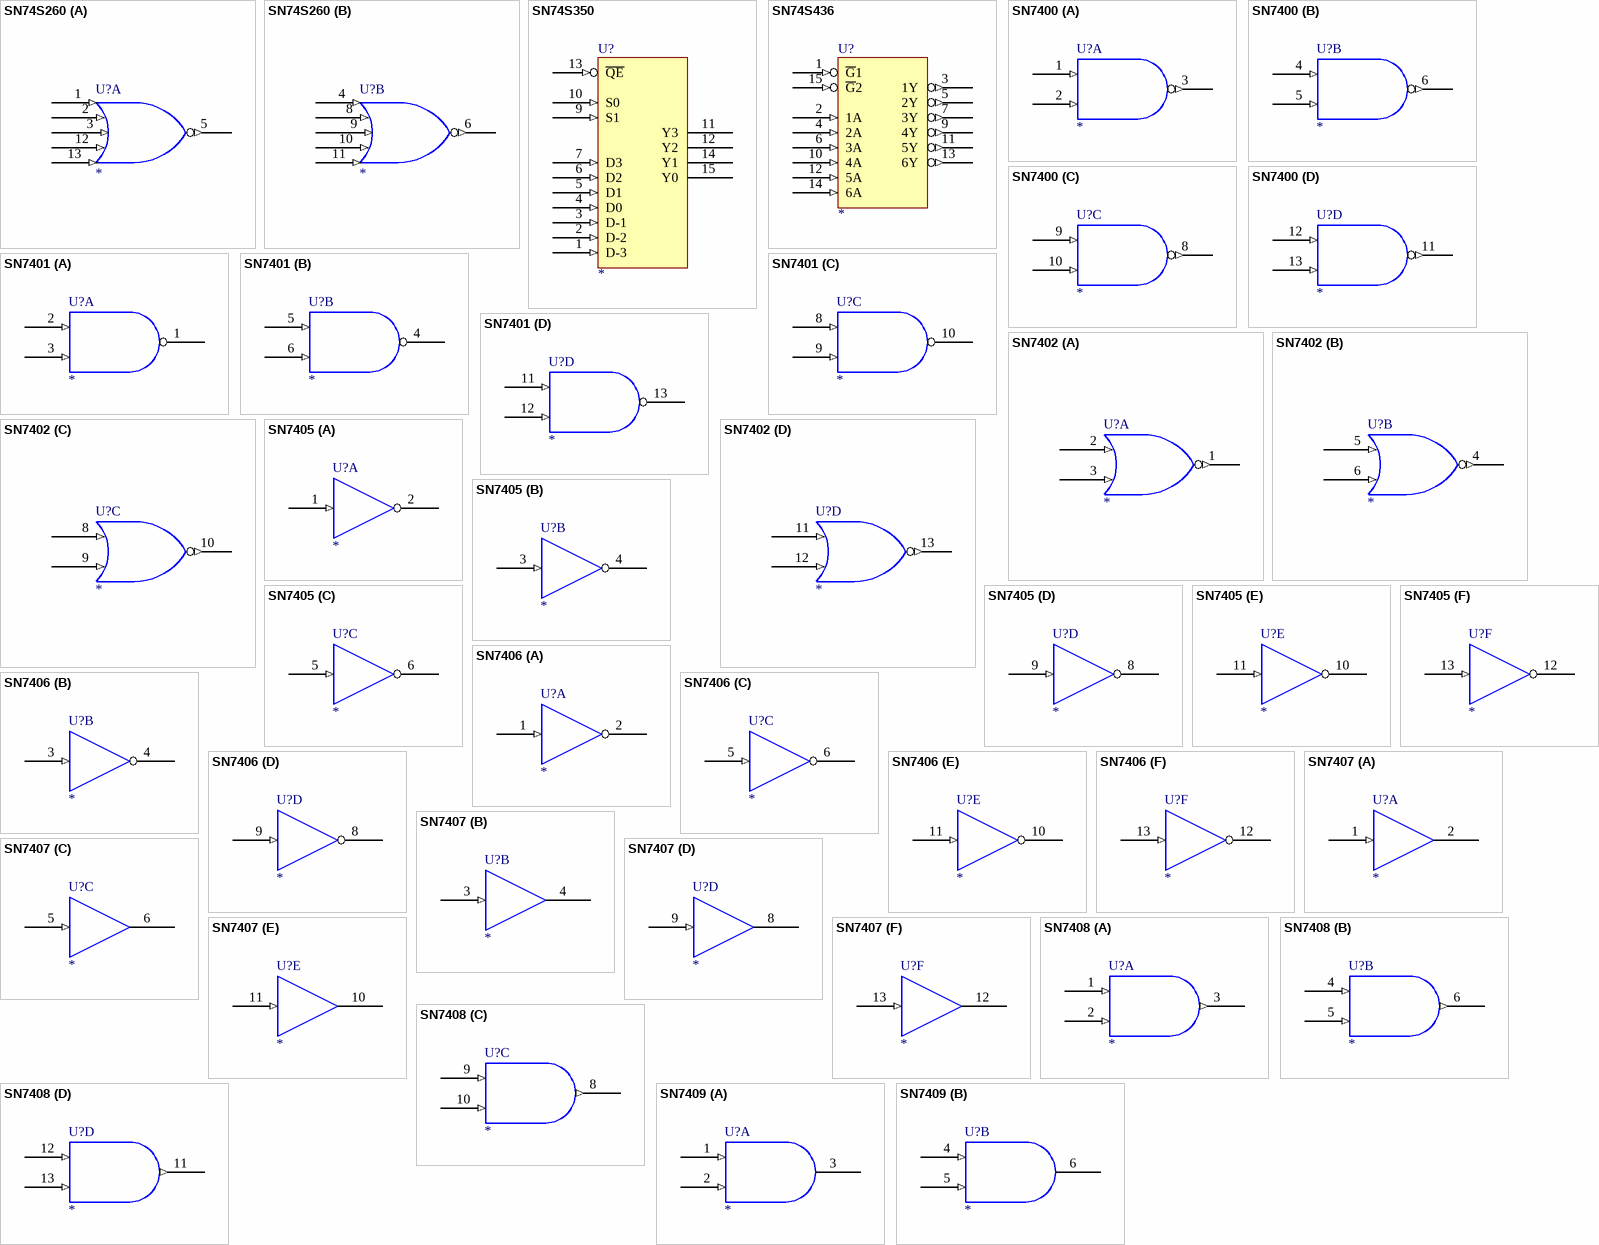
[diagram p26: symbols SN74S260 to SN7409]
## SN74S260
designator U?
DUAL 5-IN POS NOR G
footprint SO14
footprint DIP-14
part A pins: 1 (in), 2 (in), 3 (in), 5 (out), 7 GND (power) hidden to GND, 12 (in), 13 (in), 14 VCC (power) hidden to VCC
part B pins: 4 (in), 6 (out), 7 GND (power) hidden to GND, 8 (in), 9 (in), 10 (in), 11 (in), 14 VCC (power) hidden to VCC
2 alternate drawings of the same symbol

## SN74S350
designator U?
4-BIT SHIFTER 3SO
footprint SO16
footprint DIP-16
pins: 1 D-3 (in), 2 D-2 (in), 3 D-1 (in), 4 D0 (in), 5 D1 (in), 6 D2 (in), 7 D3 (in), 8 GND (power) hidden to GND, 9 S1 (in), 10 S0 (in), 11 Y3 (hiz), 12 Y2 (hiz), 13 ~{QE} (in), 14 Y1 (hiz), 15 Y0 (hiz), 16 VCC (power) hidden to VCC
1 alternate drawing of the same symbol

## SN74S436
designator U?
LINE DRV/MEMORY DRV CCT
footprint SO16
footprint DIP-16
pins: 1 ~{G}1 (in), 2 1A (in), 3 1Y (out), 4 2A (in), 5 2Y (out), 6 3A (in), 7 3Y (out), 8 GND (power) hidden to GND, 9 4Y (out), 10 4A (in), 11 5Y (out), 12 5A (in), 13 6Y (out), 14 6A (in), 15 ~{G}2 (in), 16 VCC (power) hidden to VCC
1 alternate drawing of the same symbol

## SN7400
designator U?
Quad 2-IN Pos Nand G
footprint DIP-14
footprint SO14
part A pins: 1 (in), 2 (in), 3 (out), 7 GND (power) hidden to GND, 14 VCC (power) hidden to VCC
part B pins: 4 (in), 5 (in), 6 (out), 7 GND (power) hidden to GND, 14 VCC (power) hidden to VCC
part C pins: 7 GND (power) hidden to GND, 8 (out), 9 (in), 10 (in), 14 VCC (power) hidden to VCC
part D pins: 7 GND (power) hidden to GND, 11 (out), 12 (in), 13 (in), 14 VCC (power) hidden to VCC
2 alternate drawings of the same symbol

## SN7401
designator U?
Quad 2-IN Pos Nand G OCO
footprint DIP-14
footprint SO14
part A pins: 1 (oc), 2 (in), 3 (in), 7 GND (power) hidden to GND, 14 VCC (power) hidden to VCC
part B pins: 4 (oc), 5 (in), 6 (in), 7 GND (power) hidden to GND, 14 VCC (power) hidden to VCC
part C pins: 7 GND (power) hidden to GND, 8 (in), 9 (in), 10 (oc), 14 VCC (power) hidden to VCC
part D pins: 7 GND (power) hidden to GND, 11 (in), 12 (in), 13 (oc), 14 VCC (power) hidden to VCC
2 alternate drawings of the same symbol

## SN7402
designator U?
Quad 2-IN Pos Nor G
footprint DIP-14
footprint SO14
part A pins: 1 (out), 2 (in), 3 (in), 7 GND (power) hidden to GND, 14 VCC (power) hidden to VCC
part B pins: 4 (out), 5 (in), 6 (in), 7 GND (power) hidden to GND, 14 VCC (power) hidden to VCC
part C pins: 7 GND (power) hidden to GND, 8 (in), 9 (in), 10 (out), 14 VCC (power) hidden to VCC
part D pins: 7 GND (power) hidden to GND, 11 (in), 12 (in), 13 (out), 14 VCC (power) hidden to VCC
2 alternate drawings of the same symbol

## SN7405
designator U?
Hex Inverters OCO
footprint DIP-14
footprint SO14
part A pins: 1 (in), 2 (oc), 7 GND (power) hidden to GND, 14 VCC (power) hidden to VCC
part B pins: 3 (in), 4 (oc), 7 GND (power) hidden to GND, 14 VCC (power) hidden to VCC
part C pins: 5 (in), 6 (oc), 7 GND (power) hidden to GND, 14 VCC (power) hidden to VCC
part D pins: 7 GND (power) hidden to GND, 8 (oc), 9 (in), 14 VCC (power) hidden to VCC
part E pins: 7 GND (power) hidden to GND, 10 (oc), 11 (in), 14 VCC (power) hidden to VCC
part F pins: 7 GND (power) hidden to GND, 12 (oc), 13 (in), 14 VCC (power) hidden to VCC
2 alternate drawings of the same symbol

## SN7406
designator U?
Hex Inverters Buf/Drv OCO HVO
footprint DIP-14
part A pins: 1 (in), 2 (oc), 7 GND (power) hidden to GND, 14 VCC (power) hidden to VCC
part B pins: 3 (in), 4 (oc), 7 GND (power) hidden to GND, 14 VCC (power) hidden to VCC
part C pins: 5 (in), 6 (oc), 7 GND (power) hidden to GND, 14 VCC (power) hidden to VCC
part D pins: 7 GND (power) hidden to GND, 8 (oc), 9 (in), 14 VCC (power) hidden to VCC
part E pins: 7 GND (power) hidden to GND, 10 (oc), 11 (in), 14 VCC (power) hidden to VCC
part F pins: 7 GND (power) hidden to GND, 12 (oc), 13 (in), 14 VCC (power) hidden to VCC
2 alternate drawings of the same symbol

## SN7407
designator U?
Hex Buf/Drv OCO HVO
footprint DIP-14
part A pins: 1 (in), 2 (oc), 7 GND (power) hidden to GND, 14 VCC (power) hidden to VCC
part B pins: 3 (in), 4 (oc), 7 GND (power) hidden to GND, 14 VCC (power) hidden to VCC
part C pins: 5 (in), 6 (oc), 7 GND (power) hidden to GND, 14 VCC (power) hidden to VCC
part D pins: 7 GND (power) hidden to GND, 8 (oc), 9 (in), 14 VCC (power) hidden to VCC
part E pins: 7 GND (power) hidden to GND, 10 (oc), 11 (in), 14 VCC (power) hidden to VCC
part F pins: 7 GND (power) hidden to GND, 12 (oc), 13 (in), 14 VCC (power) hidden to VCC
2 alternate drawings of the same symbol

## SN7408
designator U?
Quad 2-IN Pos And G
footprint DIP-14
footprint SO14
part A pins: 1 (in), 2 (in), 3 (out), 7 GND (power) hidden to GND, 14 VCC (power) hidden to VCC
part B pins: 4 (in), 5 (in), 6 (out), 7 GND (power) hidden to GND, 14 VCC (power) hidden to VCC
part C pins: 7 GND (power) hidden to GND, 8 (out), 9 (in), 10 (in), 14 VCC (power) hidden to VCC
part D pins: 7 GND (power) hidden to GND, 11 (out), 12 (in), 13 (in), 14 VCC (power) hidden to VCC
2 alternate drawings of the same symbol


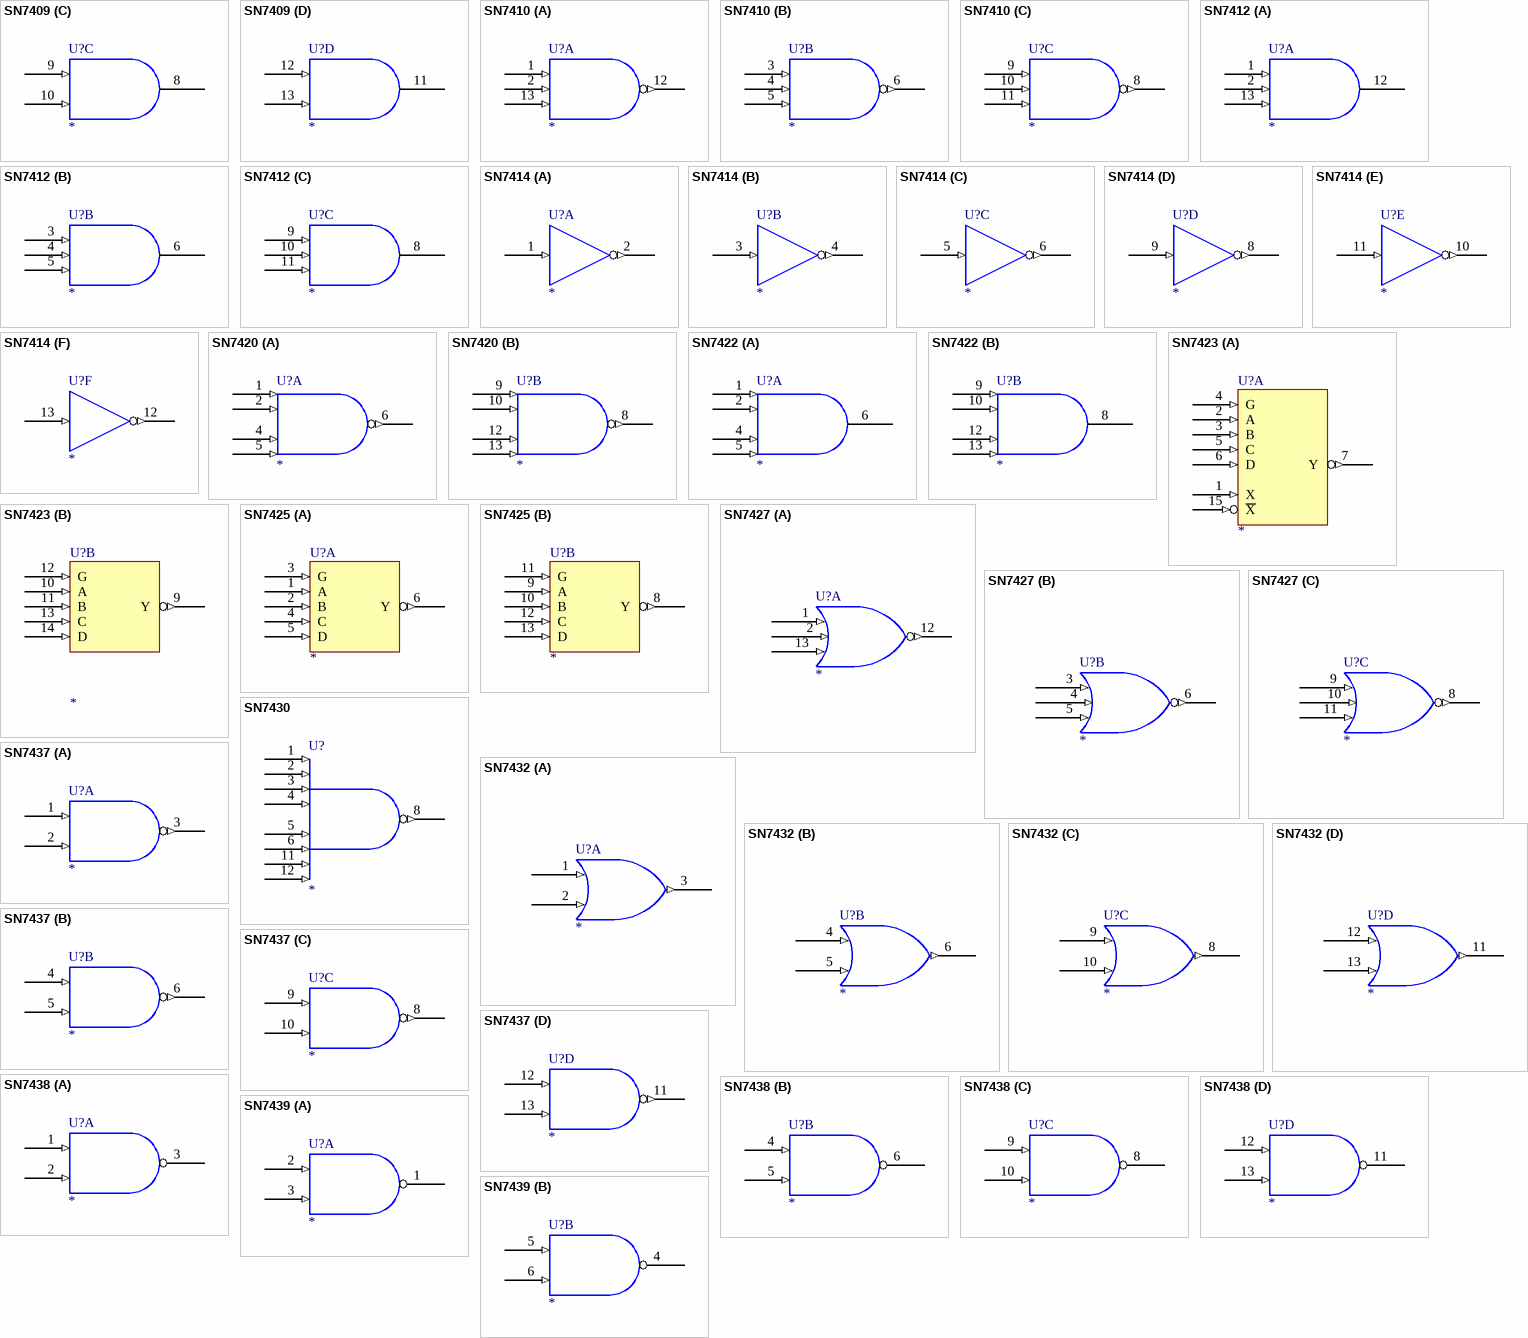
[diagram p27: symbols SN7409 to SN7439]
## SN7409
designator U?
Quad 2-IN Pos And G OCO
footprint DIP-14
footprint SO14
part A pins: 1 (in), 2 (in), 3 (oc), 7 GND (power) hidden to GND, 14 VCC (power) hidden to VCC
part B pins: 4 (in), 5 (in), 6 (oc), 7 GND (power) hidden to GND, 14 VCC (power) hidden to VCC
part C pins: 7 GND (power) hidden to GND, 8 (oc), 9 (in), 10 (in), 14 VCC (power) hidden to VCC
part D pins: 7 GND (power) hidden to GND, 11 (oc), 12 (in), 13 (in), 14 VCC (power) hidden to VCC
2 alternate drawings of the same symbol

## SN7410
designator U?
Triple 3-IN Pos Nand G
footprint DIP-14
footprint SO14
part A pins: 1 (in), 2 (in), 7 GND (power) hidden to GND, 12 (out), 13 (in), 14 VCC (power) hidden to VCC
part B pins: 3 (in), 4 (in), 5 (in), 6 (out), 7 GND (power) hidden to GND, 14 VCC (power) hidden to VCC
part C pins: 7 GND (power) hidden to GND, 8 (out), 9 (in), 10 (in), 11 (in), 14 VCC (power) hidden to VCC
2 alternate drawings of the same symbol

## SN7412
designator U?
Triple 3-IN Pos Nand G OCO
footprint DIP-14
footprint SO14
part A pins: 1 (in), 2 (in), 7 GND (power) hidden to GND, 12 (oc), 13 (in), 14 VCC (power) hidden to VCC
part B pins: 3 (in), 4 (in), 5 (in), 6 (oc), 7 GND (power) hidden to GND, 14 VCC (power) hidden to VCC
part C pins: 7 GND (power) hidden to GND, 8 (oc), 9 (in), 10 (in), 11 (in), 14 VCC (power) hidden to VCC
2 alternate drawings of the same symbol

## SN7414
designator U?
Hex Inverter SCH
footprint DIP-14
footprint SO14
part A pins: 1 (in), 2 (out), 7 GND (power) hidden to GND, 14 VCC (power) hidden to VCC
part B pins: 3 (in), 4 (out), 7 GND (power) hidden to GND, 14 VCC (power) hidden to VCC
part C pins: 5 (in), 6 (out), 7 GND (power) hidden to GND, 14 VCC (power) hidden to VCC
part D pins: 7 GND (power) hidden to GND, 8 (out), 9 (in), 14 VCC (power) hidden to VCC
part E pins: 7 GND (power) hidden to GND, 10 (out), 11 (in), 14 VCC (power) hidden to VCC
part F pins: 7 GND (power) hidden to GND, 12 (out), 13 (in), 14 VCC (power) hidden to VCC
2 alternate drawings of the same symbol

## SN7420
designator U?
Dual 4-IN Pos Nand G
footprint DIP-14
footprint SO14
part A pins: 1 (in), 2 (in), 4 (in), 5 (in), 6 (out), 7 GND (power) hidden to GND, 14 VCC (power) hidden to VCC
part B pins: 7 GND (power) hidden to GND, 8 (out), 9 (in), 10 (in), 12 (in), 13 (in), 14 VCC (power) hidden to VCC
2 alternate drawings of the same symbol

## SN7422
designator U?
Dual 4-IN Pos And G OCO
footprint DIP-14
footprint SO14
part A pins: 1 (in), 2 (in), 4 (in), 5 (in), 6 (oc), 7 GND (power) hidden to GND, 14 VCC (power) hidden to VCC
part B pins: 7 GND (power) hidden to GND, 8 (oc), 9 (in), 10 (in), 12 (in), 13 (in), 14 VCC (power) hidden to VCC
2 alternate drawings of the same symbol

## SN7423
designator U?
Dual 4-in Pos Nor G Strobe
footprint DIP-16
part A pins: 1 X (in), 2 A (in), 3 B (in), 4 G (in), 5 C (in), 6 D (in), 7 Y (out), 8 GND (power) hidden to GND, 15 ~{X} (in), 16 VCC (power) hidden to VCC
part B pins: 8 GND (power) hidden to GND, 9 Y (out), 10 A (in), 11 B (in), 12 G (in), 13 C (in), 14 D (in), 16 VCC (power) hidden to VCC
1 alternate drawing of the same symbol

## SN7425
designator U?
Dual 4-in Pos Nor G Strobe
footprint DIP-14
part A pins: 1 A (in), 2 B (in), 3 G (in), 4 C (in), 5 D (in), 6 Y (out), 7 GND (power) hidden to GND, 14 VCC (power) hidden to VCC
part B pins: 7 GND (power) hidden to GND, 8 Y (out), 9 A (in), 10 B (in), 11 G (in), 12 C (in), 13 D (in), 14 VCC (power) hidden to VCC
1 alternate drawing of the same symbol

## SN7427
designator U?
Triple 3-IN Pos Nor G
footprint DIP-14
footprint SO14
part A pins: 1 (in), 2 (in), 7 GND (power) hidden to GND, 12 (out), 13 (in), 14 VCC (power) hidden to VCC
part B pins: 3 (in), 4 (in), 5 (in), 6 (out), 7 GND (power) hidden to GND, 14 VCC (power) hidden to VCC
part C pins: 7 GND (power) hidden to GND, 8 (out), 9 (in), 10 (in), 11 (in), 14 VCC (power) hidden to VCC
2 alternate drawings of the same symbol

## SN7430
designator U?
8-IN Nand Pos G
footprint DIP-14
footprint SO14
pins: 1 (in), 2 (in), 3 (in), 4 (in), 5 (in), 6 (in), 7 GND (power) hidden to GND, 8 (out), 11 (in), 12 (in), 14 VCC (power) hidden to VCC
2 alternate drawings of the same symbol

## SN7432
designator U?
Quad 2-IN Pos Or G
footprint DIP-14
footprint SO14
part A pins: 1 (in), 2 (in), 3 (out), 7 GND (power) hidden to GND, 14 VCC (power) hidden to VCC
part B pins: 4 (in), 5 (in), 6 (out), 7 GND (power) hidden to GND, 14 VCC (power) hidden to VCC
part C pins: 7 GND (power) hidden to GND, 8 (out), 9 (in), 10 (in), 14 VCC (power) hidden to VCC
part D pins: 7 GND (power) hidden to GND, 11 (out), 12 (in), 13 (in), 14 VCC (power) hidden to VCC
2 alternate drawings of the same symbol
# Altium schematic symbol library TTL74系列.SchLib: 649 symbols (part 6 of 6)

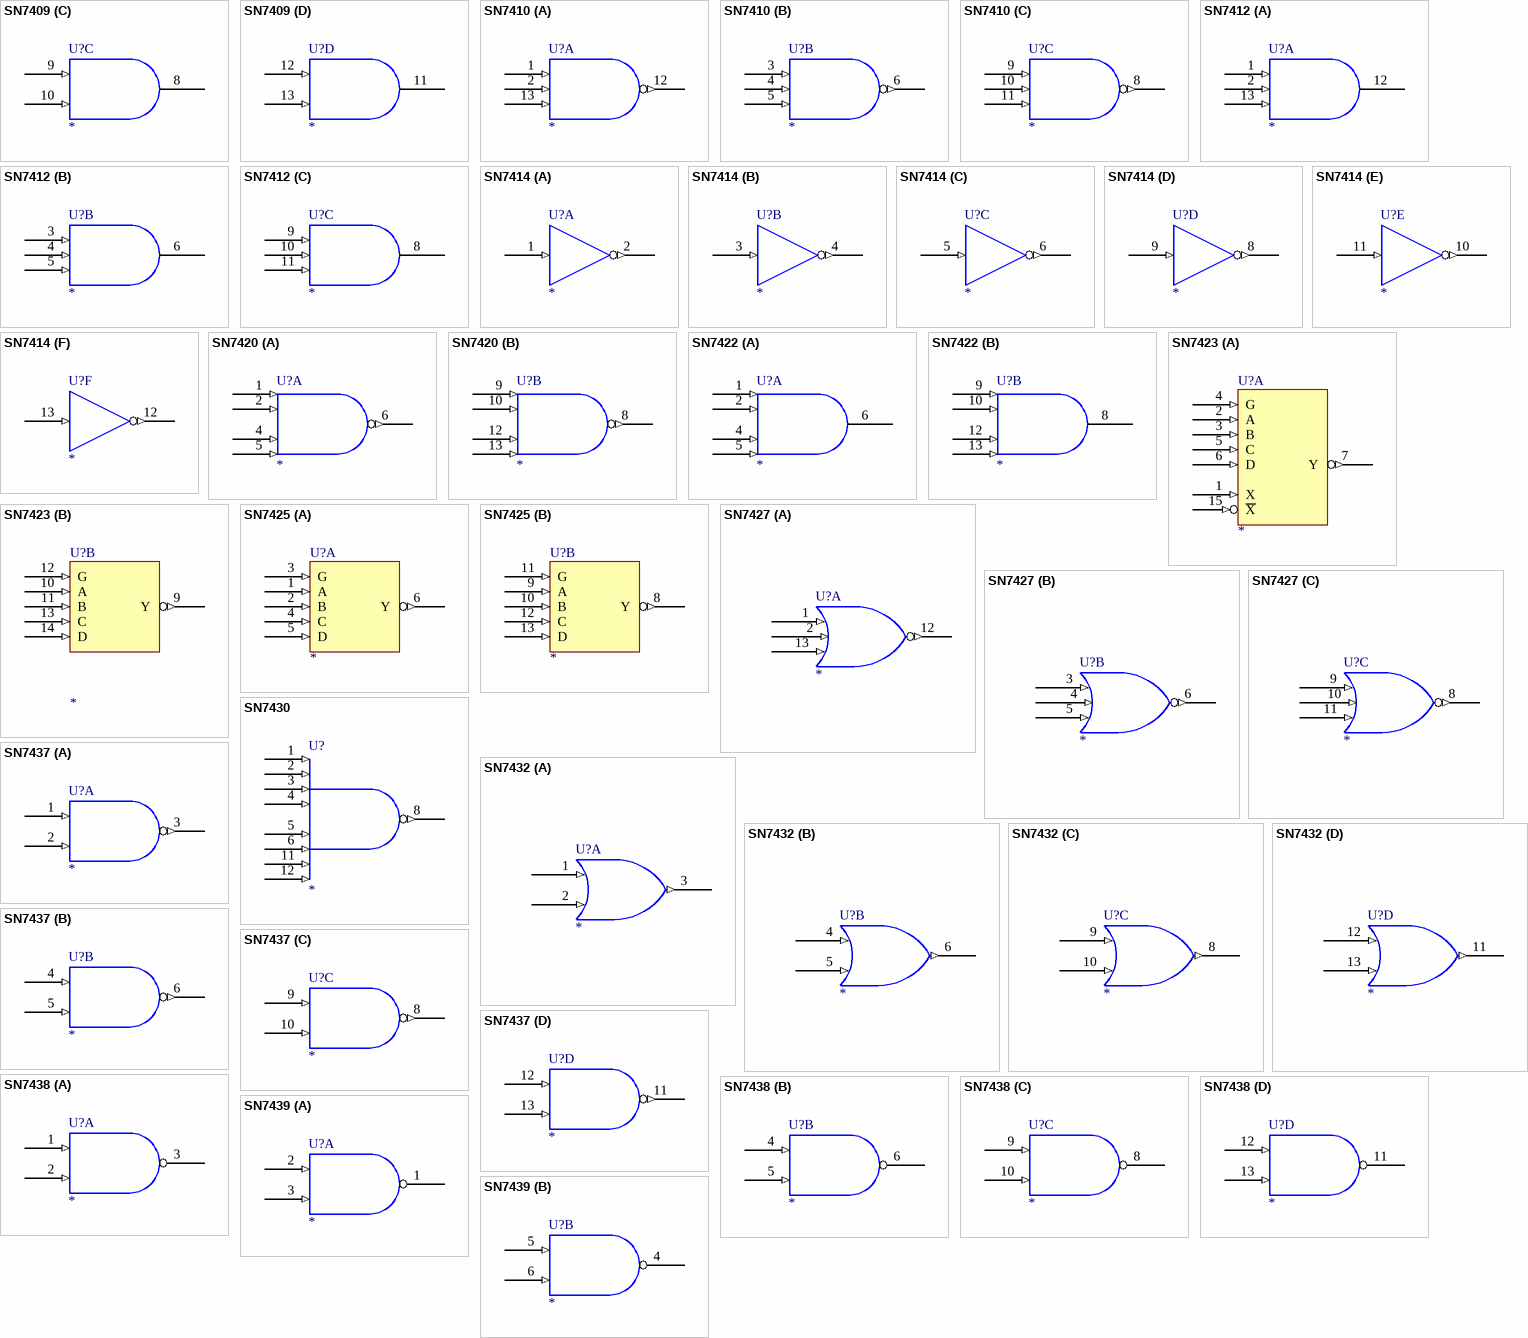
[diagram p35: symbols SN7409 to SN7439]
## SN7437
designator U?
Quad 2-IN Pos Nand G BUF
footprint DIP-14
footprint SO14
part A pins: 1 (in), 2 (in), 3 (out), 7 GND (power) hidden to GND, 14 VCC (power) hidden to VCC
part B pins: 4 (in), 5 (in), 6 (out), 7 GND (power) hidden to GND, 14 VCC (power) hidden to VCC
part C pins: 7 GND (power) hidden to GND, 8 (out), 9 (in), 10 (in), 14 VCC (power) hidden to VCC
part D pins: 7 GND (power) hidden to GND, 11 (out), 12 (in), 13 (in), 14 VCC (power) hidden to VCC
2 alternate drawings of the same symbol

## SN7438
designator U?
Quad 2-IN Pos Nand G BUF OCO
footprint DIP-14
footprint SO14
part A pins: 1 (in), 2 (in), 3 (oc), 7 GND (power) hidden to GND, 14 VCC (power) hidden to VCC
part B pins: 4 (in), 5 (in), 6 (oc), 7 GND (power) hidden to GND, 14 VCC (power) hidden to VCC
part C pins: 7 GND (power) hidden to GND, 8 (oc), 9 (in), 10 (in), 14 VCC (power) hidden to VCC
part D pins: 7 GND (power) hidden to GND, 11 (oc), 12 (in), 13 (in), 14 VCC (power) hidden to VCC
2 alternate drawings of the same symbol


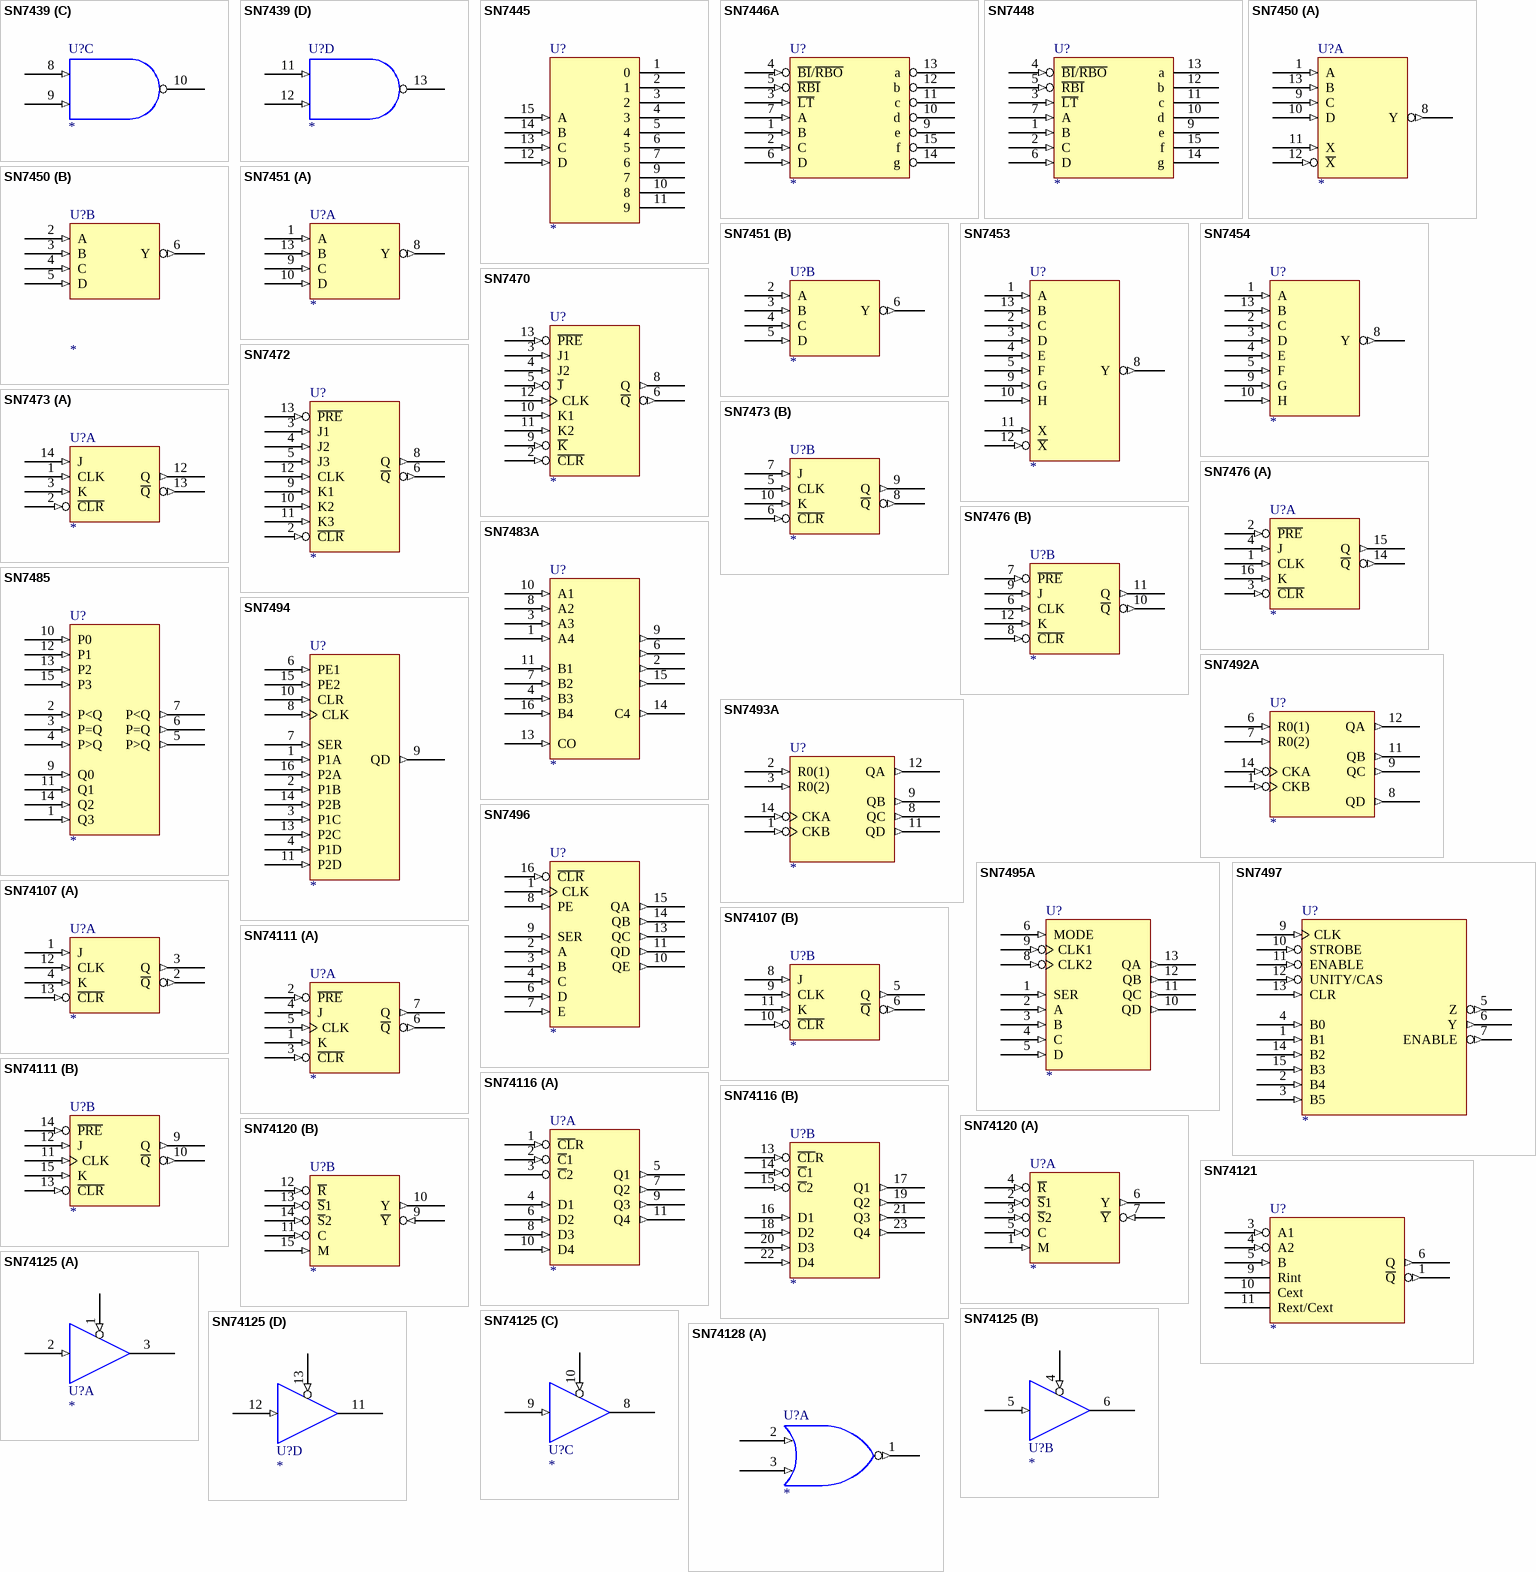
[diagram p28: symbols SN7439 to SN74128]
## SN7439
designator U?
Quad 2-IN Pos Nand G BUF OCO
footprint DIP-14
part A pins: 1 (oc), 2 (in), 3 (in), 7 GND (power) hidden to GND, 14 VCC (power) hidden to VCC
part B pins: 4 (oc), 5 (in), 6 (in), 7 GND (power) hidden to GND, 14 VCC (power) hidden to VCC
part C pins: 7 GND (power) hidden to GND, 8 (in), 9 (in), 10 (oc), 14 VCC (power) hidden to VCC
part D pins: 7 GND (power) hidden to GND, 11 (in), 12 (in), 13 (oc), 14 VCC (power) hidden to VCC
2 alternate drawings of the same symbol

## SN7445
designator U?
BCD-To-Decimal DEC DRV
footprint DIP-16
pins: 1 0 (oc), 2 1 (oc), 3 2 (oc), 4 3 (oc), 5 4 (oc), 6 5 (oc), 7 6 (oc), 8 GND (power) hidden to GND, 9 7 (oc), 10 8 (oc), 11 9 (oc), 12 D (in), 13 C (in), 14 B (in), 15 A (in), 16 VCC (power) hidden to VCC
1 alternate drawing of the same symbol

## SN7446A
designator U?
BCD-To-SEVEN-SEGMENT DEC DRV
footprint DIP-16
footprint SO16
pins: 1 B (in), 2 C (in), 3 ~{LT} (in), 4 ~{BI}/~{RBO} (in), 5 ~{RBI} (in), 6 D (in), 7 A (in), 8 GND (power) hidden to GND, 9 e (oc), 10 d (oc), 11 c (oc), 12 b (oc), 13 a (oc), 14 g (oc), 15 f (oc), 16 VCC (power) hidden to VCC
1 alternate drawing of the same symbol

## SN7448
designator U?
BCD-To-SEVEN-SEGMENT DEC DRV
footprint DIP-16
footprint SO16
pins: 1 B (in), 2 C (in), 3 ~{LT} (in), 4 ~{BI}/~{RBO} (in), 5 ~{RBI} (in), 6 D (in), 7 A (in), 8 GND (power) hidden to GND, 9 e (oc), 10 d (oc), 11 c (oc), 12 b (oc), 13 a (oc), 14 g (oc), 15 f (oc), 16 VCC (power) hidden to VCC
1 alternate drawing of the same symbol

## SN7450
designator U?
DUAL 2-WIDE 2-IN AND-OR-INVERT G
footprint DIP-14
part A pins: 1 A (in), 7 GND (power) hidden to GND, 8 Y (out), 9 C (in), 10 D (in), 11 X (in), 12 ~{X} (in), 13 B (in), 14 VCC (power) hidden to VCC
part B pins: 2 A (in), 3 B (in), 4 C (in), 5 D (in), 6 Y (out), 7 GND (power) hidden to GND, 14 VCC (power) hidden to VCC
1 alternate drawing of the same symbol

## SN7451
designator U?
DUAL 2-WIDE 2-IN AND-OR-INVERT G
footprint DIP-14
footprint SO14
part A pins: 1 A (in), 7 GND (power) hidden to GND, 8 Y (out), 9 C (in), 10 D (in), 13 B (in), 14 VCC (power) hidden to VCC
part B pins: 2 A (in), 3 B (in), 4 C (in), 5 D (in), 6 Y (out), 7 GND (power) hidden to GND, 14 VCC (power) hidden to VCC
1 alternate drawing of the same symbol

## SN7453
designator U?
EXPANDABLE 4-WIDE 2-IN AND-OR-INVERT G
footprint DIP-14
pins: 1 A (in), 2 C (in), 3 D (in), 4 E (in), 5 F (in), 7 GND (power) hidden to GND, 8 Y (out), 9 G (in), 10 H (in), 11 X (in), 12 ~{X} (in), 13 B (in), 14 VCC (power) hidden to VCC
1 alternate drawing of the same symbol

## SN7454
designator U?
4-WIDE 2-IN AND-OR-INVERT G
footprint DIP-14
pins: 1 A (in), 2 C (in), 3 D (in), 4 E (in), 5 F (in), 7 GND (power) hidden to GND, 8 Y (out), 9 G (in), 10 H (in), 13 B (in), 14 VCC (power) hidden to VCC
1 alternate drawing of the same symbol

## SN7470
designator U?
AND-GATED J-K PET FF RS CR
footprint DIP-14
pins: 2 ~{CLR} (in), 3 J1 (in), 4 J2 (in), 5 ~{J} (in), 6 ~{Q} (out), 7 GND (power) hidden to GND, 8 Q (out), 9 ~{K} (in), 10 K1 (in), 11 K2 (in), 12 CLK (in), 13 ~{PRE} (in), 14 VCC (power) hidden to VCC
1 alternate drawing of the same symbol

## SN7472
designator U?
AND-GATED J-K ms FF RS CR
footprint DIP-14
pins: 2 ~{CLR} (in), 3 J1 (in), 4 J2 (in), 5 J3 (in), 6 ~{Q} (out), 7 GND (power) hidden to GND, 8 Q (out), 9 K1 (in), 10 K2 (in), 11 K3 (in), 12 CLK (in), 13 ~{PRE} (in), 14 VCC (power) hidden to VCC
1 alternate drawing of the same symbol

## SN7473
designator U?
DUAL J-K FF CR
footprint DIP-14
footprint SO14
part A pins: 1 CLK (in), 2 ~{CLR} (in), 3 K (in), 4 GND (power) hidden to GND, 11 VCC (power) hidden to VCC, 12 Q (out), 13 ~{Q} (out), 14 J (in)
part B pins: 4 GND (power) hidden to GND, 5 CLK (in), 6 ~{CLR} (in), 7 J (in), 8 ~{Q} (out), 9 Q (out), 10 K (in), 11 VCC (power) hidden to VCC
1 alternate drawing of the same symbol

## SN7476
designator U?
DUAL J-K FF RS CR
footprint DIP-16
part A pins: 1 CLK (in), 2 ~{PRE} (in), 3 ~{CLR} (in), 4 J (in), 5 VCC (power) hidden to VCC, 13 GND (power) hidden to GND, 14 ~{Q} (out), 15 Q (out), 16 K (in)
part B pins: 5 VCC (power) hidden to VCC, 6 CLK (in), 7 ~{PRE} (in), 8 ~{CLR} (in), 9 J (in), 10 ~{Q} (out), 11 Q (out), 12 K (in), 13 GND (power) hidden to GND
1 alternate drawing of the same symbol

## SN7483A
designator U?
4-BIT FULL ADD FC
footprint DIP-16
footprint SO16
pins: 1 A4 (in), 2 (out), 3 A3 (in), 4 B3 (in), 5 VCC (power) hidden to VCC, 6 (out), 7 B2 (in), 8 A2 (in), 9 (out), 10 A1 (in), 11 B1 (in), 12 GND (power) hidden to GND, 13 CO (in), 14 C4 (out), 15 (out), 16 B4 (in)
1 alternate drawing of the same symbol

## SN7485
designator U?
4-BIT MAGNITUDE COMP
footprint DIP-16
footprint SO16
pins: 1 Q3 (in), 2 P<Q (in), 3 P=Q (in), 4 P>Q (in), 5 P>Q (out), 6 P=Q (out), 7 P<Q (out), 8 GND (power) hidden to GND, 9 Q0 (in), 10 P0 (in), 11 Q1 (in), 12 P1 (in), 13 P2 (in), 14 Q2 (in), 15 P3 (in), 16 VCC (power) hidden to VCC
1 alternate drawing of the same symbol

## SN7492A
designator U?
DECADE DIV-BY-12 BIN CNT
footprint DIP-14
footprint SO14
pins: 1 CKB (in), 5 VCC (power) hidden to VCC, 6 R0(1) (in), 7 R0(2) (in), 8 QD (out), 9 QC (out), 10 GND (power) hidden to GND, 11 QB (out), 12 QA (out), 14 CKA (in)
1 alternate drawing of the same symbol

## SN7493A
designator U?
DECADE DIV-BY-12 BIN CNT
footprint DIP-14
footprint SO14
pins: 1 CKB (in), 2 R0(1) (in), 3 R0(2) (in), 5 VCC (power) hidden to VCC, 8 QC (out), 9 QB (out), 10 GND (power) hidden to GND, 11 QD (out), 12 QA (out), 14 CKA (in)
1 alternate drawing of the same symbol

## SN7494
designator U?
4-BIT SHIFT REG
footprint DIP-16
pins: 1 P1A (in), 2 P1B (in), 3 P1C (in), 4 P1D (in), 5 VCC (power) hidden to VCC, 6 PE1 (in), 7 SER (in), 8 CLK (in), 9 QD (out), 10 CLR (in), 11 P2D (in), 12 GND (power) hidden to GND, 13 P2C (in), 14 P2B (in), 15 PE2 (in), 16 P2A (in)
1 alternate drawing of the same symbol

## SN7495A
designator U?
4-BIT PA SHIFT REG
footprint DIP-14
footprint SO14
pins: 1 SER (in), 2 A (in), 3 B (in), 4 C (in), 5 D (in), 6 MODE (in), 7 GND (power) hidden to GND, 8 CLK2 (in), 9 CLK1 (in), 10 QD (out), 11 QC (out), 12 QB (out), 13 QA (out), 14 VCC (power) hidden to VCC
1 alternate drawing of the same symbol

## SN7496
designator U?
5-BIT SHIFT REG
footprint DIP-16
footprint SO16
pins: 1 CLK (in), 2 A (in), 3 B (in), 4 C (in), 5 VCC (power) hidden to VCC, 6 D (in), 7 E (in), 8 PE (in), 9 SER (in), 10 QE (out), 11 QD (out), 12 GND (power) hidden to GND, 13 QC (out), 14 QB (out), 15 QA (out), 16 ~{CLR} (in)
1 alternate drawing of the same symbol

## SN7497
designator U?
SYN 6-BIT BIN RATE MULT
footprint DIP-16
pins: 1 B1 (in), 2 B4 (in), 3 B5 (in), 4 B0 (in), 5 Z (out), 6 Y (out), 7 ENABLE (out), 8 GND (power) hidden to GND, 9 CLK (in), 10 STROBE (in), 11 ENABLE (in), 12 UNITY/CAS (in), 13 CLR (in), 14 B2 (in), 15 B3 (in), 16 VCC (power) hidden to VCC
1 alternate drawing of the same symbol

## SN74107
designator U?
DUAL J-K FF CR
footprint DIP-14
part A pins: 1 J (in), 2 ~{Q} (out), 3 Q (out), 4 K (in), 7 GND (power) hidden to GND, 12 CLK (in), 13 ~{CLR} (in), 14 VCC (power) hidden to VCC
part B pins: 5 Q (out), 6 ~{Q} (out), 7 GND (power) hidden to GND, 8 J (in), 9 CLK (in), 10 ~{CLR} (in), 11 K (in), 14 VCC (power) hidden to VCC
1 alternate drawing of the same symbol

## SN74111
designator U?
DUAL J-K MS DATA LOCKOUT
footprint DIP-16
part A pins: 1 K (in), 2 ~{PRE} (in), 3 ~{CLR} (in), 4 J (in), 5 CLK (in), 6 ~{Q} (out), 7 Q (out), 8 GND (power) hidden to GND, 16 VCC (power) hidden to VCC
part B pins: 8 GND (power) hidden to GND, 9 Q (out), 10 ~{Q} (out), 11 CLK (in), 12 J (in), 13 ~{CLR} (in), 14 ~{PRE} (in), 15 K (in), 16 VCC (power) hidden to VCC
1 alternate drawing of the same symbol

## SN74116
designator U?
DUAL 4-BIT LCH CR
footprint DIP-24
part A pins: 1 ~{CL}R (in), 2 ~{C}1 (in), 3 ~{C}2, 4 D1 (in), 5 Q1 (out), 6 D2 (in), 7 Q2 (out), 8 D3 (in), 9 Q3 (out), 10 D4 (in), 11 Q4 (out), 12 GND (power) hidden to GND, 24 VCC (power) hidden to VCC
part B pins: 12 GND (power) hidden to GND, 13 ~{CL}R (in), 14 ~{C}1 (in), 15 ~{C}2 (in), 16 D1 (in), 17 Q1 (out), 18 D2 (in), 19 Q2 (out), 20 D3 (in), 21 Q3 (out), 22 D4 (in), 23 Q4 (out), 24 VCC (power) hidden to VCC
1 alternate drawing of the same symbol

## SN74120
designator U?
DUAL PULSE SYNR DRV
footprint DIP-16
part A pins: 1 M (in), 2 ~{S}1 (in), 3 ~{S}2 (in), 4 ~{R} (in), 5 C (in), 6 Y (out), 7 ~{Y} (in), 8 GND (power) hidden to GND, 16 VCC (power) hidden to VCC
part B pins: 8 GND (power) hidden to GND, 9 ~{Y} (in), 10 Y (out), 11 C (in), 12 ~{R} (in), 13 ~{S}1 (in), 14 ~{S}2 (in), 15 M (in), 16 VCC (power) hidden to VCC
1 alternate drawing of the same symbol

## SN74121
designator U?
MONOSTABLE MULTIVIBRATOR SCHI
footprint DIP-14
pins: 1 ~{Q} (out), 3 A1 (in), 4 A2 (in), 5 B (in), 6 Q (out), 7 GND (power) hidden to GND, 9 Rint, 10 Cext, 11 Rext/Cext, 14 VCC (power) hidden to VCC
1 alternate drawing of the same symbol

## SN74125
designator U?
QUAD BUS BUF 3SO
footprint DIP-14
part A pins: 1 (in), 2 (in), 3 (hiz), 7 GND (power) hidden to GND, 14 VCC (power) hidden to VCC
part B pins: 4 (in), 5 (in), 6 (hiz), 7 GND (power) hidden to GND, 14 VCC (power) hidden to VCC
part C pins: 7 GND (power) hidden to GND, 8 (hiz), 9 (in), 10 (in), 14 VCC (power) hidden to VCC
part D pins: 7 GND (power) hidden to GND, 11 (hiz), 12 (in), 13 (in), 14 VCC (power) hidden to VCC
2 alternate drawings of the same symbol


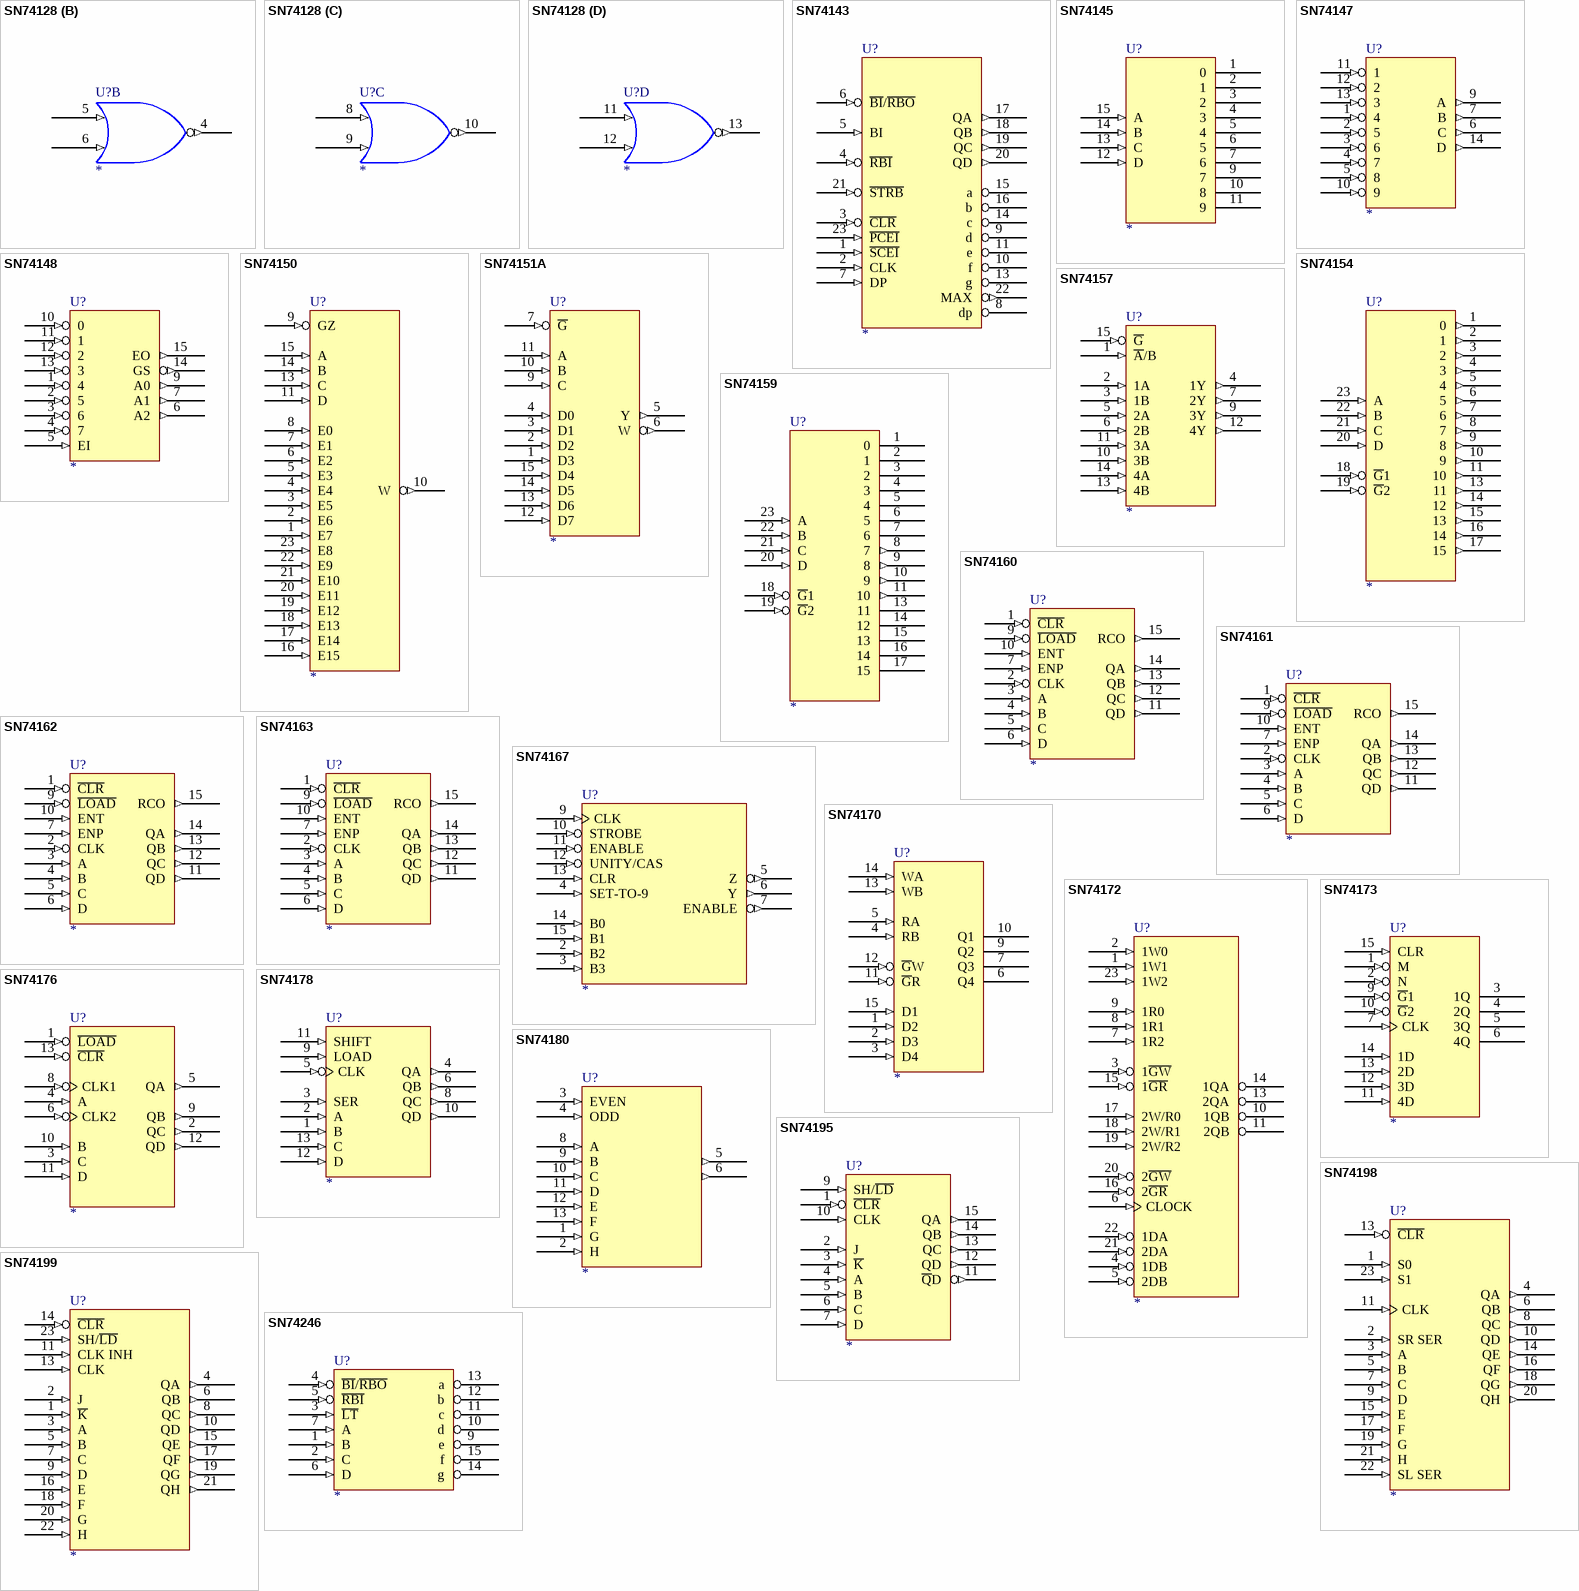
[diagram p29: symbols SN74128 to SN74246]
## SN74128
designator U?
QUAD LINE DRV
footprint DIP-14
part A pins: 1 (out), 2 (in), 3 (in), 7 GND (power) hidden to GND, 14 VCC (power) hidden to VCC
part B pins: 4 (out), 5 (in), 6 (in), 7 GND (power) hidden to GND, 14 VCC (power) hidden to VCC
part C pins: 7 GND (power) hidden to GND, 8 (in), 9 (in), 10 (out), 14 VCC (power) hidden to VCC
part D pins: 7 GND (power) hidden to GND, 11 (in), 12 (in), 13 (out), 14 VCC (power) hidden to VCC
2 alternate drawings of the same symbol

## SN74143
designator U?
4-BIT CNT/LCH SEVEN SEG LED/LAMP DRV
footprint DIP-24
pins: 1 ~{SCEI} (in), 2 CLK (in), 3 ~{CLR} (in), 4 ~{RBI} (in), 5 BI (in), 6 ~{BI}/~{RBO} (in), 7 DP (in), 8 dp (oc), 9 d (oc), 10 f (oc), 11 e (oc), 12 GND (power) hidden to GND, 13 g (oc), 14 c (oc), 15 a (oc), 16 b (oc), 17 QA (out), 18 QB (out), 19 QC (out), 20 QD (out), 21 ~{STRB} (in), 22 MAX (out), 23 ~{PCEI} (in), 24 VCC (power) hidden to VCC
1 alternate drawing of the same symbol

## SN74145
designator U?
BCD-To-Decimal DEC DRV
footprint DIP-16
pins: 1 0 (oc), 2 1 (oc), 3 2 (oc), 4 3 (oc), 5 4 (oc), 6 5 (oc), 7 6 (oc), 8 GND (power) hidden to GND, 9 7 (oc), 10 8 (oc), 11 9 (oc), 12 D (in), 13 C (in), 14 B (in), 15 A (in), 16 VCC (power) hidden to VCC
1 alternate drawing of the same symbol

## SN74147
designator U?
10-4 LINE PRIORITY ENC
footprint DIP-16
footprint SO16
pins: 1 4 (in), 2 5 (in), 3 6 (in), 4 7 (in), 5 8 (in), 6 C (out), 7 B (out), 8 GND (power) hidden to GND, 9 A (out), 10 9 (in), 11 1 (in), 12 2 (in), 13 3 (in), 14 D (out), 16 VCC (power) hidden to VCC
1 alternate drawing of the same symbol

## SN74148
designator U?
8-3 LINE PRIORITY ENC
footprint DIP-16
footprint SO16
pins: 1 4 (in), 2 5 (in), 3 6 (in), 4 7 (in), 5 EI (in), 6 A2 (out), 7 A1 (out), 8 GND (power) hidden to GND, 9 A0 (out), 10 0 (in), 11 1 (in), 12 2 (in), 13 3 (in), 14 GS (out), 15 EO (out), 16 VCC (power) hidden to VCC
1 alternate drawing of the same symbol

## SN74150
designator U?
DATA SELEC/MUX
footprint DIP-24
pins: 1 E7 (in), 2 E6 (in), 3 E5 (in), 4 E4 (in), 5 E3 (in), 6 E2 (in), 7 E1 (in), 8 E0 (in), 9 GZ (in), 10 W (out), 11 D (in), 12 GND (power) hidden to GND, 13 C (in), 14 B (in), 15 A (in), 16 E15 (in), 17 E14 (in), 18 E13 (in), 19 E12 (in), 20 E11 (in), 21 E10 (in), 22 E9 (in), 23 E8 (in), 24 VCC (power) hidden to VCC
1 alternate drawing of the same symbol

## SN74151A
designator U?
DATA SELEC/MUX
footprint DIP-16
footprint SO16
pins: 1 D3 (in), 2 D2 (in), 3 D1 (in), 4 D0 (in), 5 Y (out), 6 W (out), 7 ~{G} (in), 8 GND (power) hidden to GND, 9 C (in), 10 B (in), 11 A (in), 12 D7 (in), 13 D6 (in), 14 D5 (in), 15 D4 (in), 16 VCC (power) hidden to VCC
1 alternate drawing of the same symbol

## SN74154
designator U?
4-16LINE DEC DEMUL
footprint DIP-24
pins: 1 0 (out), 2 1 (out), 3 2 (out), 4 3 (out), 5 4 (out), 6 5 (out), 7 6 (out), 8 7 (out), 9 8 (out), 10 9 (out), 11 10 (out), 12 GND (power) hidden to GND, 13 11 (out), 14 12 (out), 15 13 (out), 16 14 (out), 17 15 (out), 18 ~{G}1 (in), 19 ~{G}2 (in), 20 D (in), 21 C (in), 22 B (in), 23 A (in), 24 VCC (power) hidden to VCC
1 alternate drawing of the same symbol

## SN74157
designator U?
QUAD 2-1LINE DATA SELEC/MUX
footprint DIP-16
footprint SO16
pins: 1 ~{A}/B (in), 2 1A (in), 3 1B (in), 4 1Y (out), 5 2A (in), 6 2B (in), 7 2Y (out), 8 GND (power) hidden to GND, 9 3Y (out), 10 3B (in), 11 3A (in), 12 4Y (out), 13 4B (in), 14 4A (in), 15 ~{G} (in), 16 VCC (power) hidden to VCC
1 alternate drawing of the same symbol

## SN74159
designator U?
4-16LINE DEC DEMUL OCO
footprint DIP-24
pins: 1 0 (oc), 2 1 (oc), 3 2 (oc), 4 3 (oc), 5 4 (oc), 6 5 (oc), 7 6 (oc), 8 7 (out), 9 8 (out), 10 9 (out), 11 10 (out), 12 GND (power) hidden to GND, 13 11 (oc), 14 12 (oc), 15 13 (oc), 16 14 (oc), 17 15 (oc), 18 ~{G}1 (in), 19 ~{G}2 (in), 20 D (in), 21 C (in), 22 B (in), 23 A (in), 24 VCC (power) hidden to VCC
1 alternate drawing of the same symbol

## SN74160
designator U?
SYN 4-BIT CNT
footprint DIP-16
pins: 1 ~{CLR} (in), 2 CLK (in), 3 A (in), 4 B (in), 5 C (in), 6 D (in), 7 ENP (in), 8 GND (power) hidden to GND, 9 ~{LOAD} (in), 10 ENT (in), 11 QD (out), 12 QC (out), 13 QB (out), 14 QA (out), 15 RCO (out), 16 VCC (power) hidden to VCC
1 alternate drawing of the same symbol

## SN74161
designator U?
SYN 4-BIT CNT
footprint DIP-16
pins: 1 ~{CLR} (in), 2 CLK (in), 3 A (in), 4 B (in), 5 C (in), 6 D (in), 7 ENP (in), 8 GND (power) hidden to GND, 9 ~{LOAD} (in), 10 ENT (in), 11 QD (out), 12 QC (out), 13 QB (out), 14 QA (out), 15 RCO (out), 16 VCC (power) hidden to VCC
1 alternate drawing of the same symbol

## SN74162
designator U?
SYN 4-BIT CNT
footprint DIP-16
pins: 1 ~{CLR} (in), 2 CLK (in), 3 A (in), 4 B (in), 5 C (in), 6 D (in), 7 ENP (in), 8 GND (power) hidden to GND, 9 ~{LOAD} (in), 10 ENT (in), 11 QD (out), 12 QC (out), 13 QB (out), 14 QA (out), 15 RCO (out), 16 VCC (power) hidden to VCC
1 alternate drawing of the same symbol

## SN74163
designator U?
SYN 4-BIT CNT
footprint DIP-16
pins: 1 ~{CLR} (in), 2 CLK (in), 3 A (in), 4 B (in), 5 C (in), 6 D (in), 7 ENP (in), 8 GND (power) hidden to GND, 9 ~{LOAD} (in), 10 ENT (in), 11 QD (out), 12 QC (out), 13 QB (out), 14 QA (out), 15 RCO (out), 16 VCC (power) hidden to VCC
1 alternate drawing of the same symbol

## SN74167
designator U?
SYN DECADE RATE MULTIPLIERS
footprint DIP-16
pins: 2 B2 (in), 3 B3 (in), 4 SET-TO-9 (in), 5 Z (out), 6 Y (out), 7 ENABLE (out), 8 GND (power) hidden to GND, 9 CLK (in), 10 STROBE (in), 11 ENABLE (in), 12 UNITY/CAS (in), 13 CLR (in), 14 B0 (in), 15 B1 (in), 16 VCC (power) hidden to VCC
1 alternate drawing of the same symbol

## SN74170
designator U?
4-4 REG FILES OCO
footprint DIP-16
footprint SO16
pins: 1 D2 (in), 2 D3 (in), 3 D4 (in), 4 RB (in), 5 RA (in), 6 Q4 (oc), 7 Q3 (oc), 8 GND (power) hidden to GND, 9 Q2 (oc), 10 Q1 (oc), 11 ~{G}R (in), 12 ~{G}W (in), 13 WB (in), 14 WA (in), 15 D1 (in), 16 VCC (power) hidden to VCC
1 alternate drawing of the same symbol

## SN74172
designator U?
16-bit multiple-port reg file 3so
footprint DIP-24
pins: 1 1W1 (in), 2 1W0 (in), 3 1~{GW} (in), 4 1DB (in), 5 2DB (in), 6 CLOCK (in), 7 1R2 (in), 8 1R1 (in), 9 1R0 (in), 10 1QB (hiz), 11 2QB (hiz), 12 GND (power) hidden to GND, 13 2QA (hiz), 14 1QA (hiz), 15 1~{GR} (in), 16 2~{GR} (in), 17 2W/R0 (in), 18 2W/R1 (in), 19 2W/R2 (in), 20 2~{GW} (in), 21 2DA (in), 22 1DA (in), 23 1W2 (in), 24 VCC (power) hidden to VCC
1 alternate drawing of the same symbol

## SN74173
designator U?
4-BIT D-TYPE REG 3SO
footprint DIP-16
pins: 1 M (in), 2 N (in), 3 1Q (hiz), 4 2Q (hiz), 5 3Q (hiz), 6 4Q (hiz), 7 CLK (in), 8 GND (power) hidden to GND, 9 ~{G}1 (in), 10 ~{G}2 (in), 11 4D (in), 12 3D (in), 13 2D (in), 14 1D (in), 15 CLR (in), 16 VCC (power) hidden to VCC
1 alternate drawing of the same symbol

## SN74176
designator U?
35-MHZ DECADE BIN CNT/LCH RS
footprint DIP-14
pins: 1 ~{LOAD} (in), 2 QC (out), 3 C (in), 4 A (in), 5 QA (out), 6 CLK2 (in), 7 GND (power) hidden to GND, 8 CLK1 (in), 9 QB (out), 10 B (in), 11 D (in), 12 QD (out), 13 ~{CLR} (in), 14 VCC (power) hidden to VCC
1 alternate drawing of the same symbol

## SN74178
designator U?
4-BIT PARALLEL-ACCESS SFT REG
footprint DIP-14
pins: 1 B (in), 2 A (in), 3 SER (in), 4 QA (out), 5 CLK (in), 6 QB (out), 7 GND (power) hidden to GND, 8 QC (out), 9 LOAD (in), 10 QD (out), 11 SHIFT (in), 12 D (in), 13 C (in), 14 VCC (power) hidden to VCC
1 alternate drawing of the same symbol

## SN74180
designator U?
9-BIT PARITY GNR/CHKR
footprint DIP-14
pins: 1 G (in), 2 H (in), 3 EVEN (in), 4 ODD (in), 5 (out), 6 (out), 7 GND (power) hidden to GND, 8 A (in), 9 B (in), 10 C (in), 11 D (in), 12 E (in), 13 F (in), 14 VCC (power) hidden to VCC
1 alternate drawing of the same symbol

## SN74195
designator U?
4-BIT PARALLEL ACCESS SFT REG
footprint DIP-16
pins: 1 ~{CLR} (in), 2 J (in), 3 ~{K} (in), 4 A (in), 5 B (in), 6 C (in), 7 D (in), 8 GND (power) hidden to GND, 9 SH/~{LD} (in), 10 CLK (in), 11 ~{Q}D (out), 12 QD (out), 13 QC (out), 14 QB (out), 15 QA (out), 16 VCC (power) hidden to VCC
1 alternate drawing of the same symbol

## SN74198
designator U?
8-BIT SFT REG
footprint DIP-24
pins: 1 S0 (in), 2 SR SER (in), 3 A (in), 4 QA (out), 5 B (in), 6 QB (out), 7 C (in), 8 QC (out), 9 D (in), 10 QD (out), 11 CLK (in), 12 GND (power) hidden to GND, 13 ~{CLR} (in), 14 QE (out), 15 E (in), 16 QF (out), 17 F (in), 18 QG (out), 19 G (in), 20 QH (out), 21 H (in), 22 SL SER (in), 23 S1 (in), 24 VCC (power) hidden to VCC
1 alternate drawing of the same symbol

## SN74199
designator U?
8-BIT SFT REG
footprint DIP-24
pins: 1 ~{K} (in), 2 J (in), 3 A (in), 4 QA (out), 5 B (in), 6 QB (out), 7 C (in), 8 QC (out), 9 D (in), 10 QD (out), 11 CLK INH (in), 12 GND (power) hidden to GND, 13 CLK (in), 14 ~{CLR} (in), 15 QE (out), 16 E (in), 17 QF (out), 18 F (in), 19 QG (out), 20 G (in), 21 QH (out), 22 H (in), 23 SH/~{LD} (in), 24 VCC (power) hidden to VCC
1 alternate drawing of the same symbol

## SN74246
designator U?
BCD-TO-SEVEN-SEGMENTDEC/DRV
footprint DIP-16
footprint SO16
pins: 1 B (in), 2 C (in), 3 ~{LT} (in), 4 ~{BI}/~{RBO} (in), 5 ~{RBI} (in), 6 D (in), 7 A (in), 8 GND (power) hidden to GND, 9 e (oc), 10 d (oc), 11 c (oc), 12 b (oc), 13 a (oc), 14 g (oc), 15 f (oc), 16 VCC (power) hidden to VCC
1 alternate drawing of the same symbol


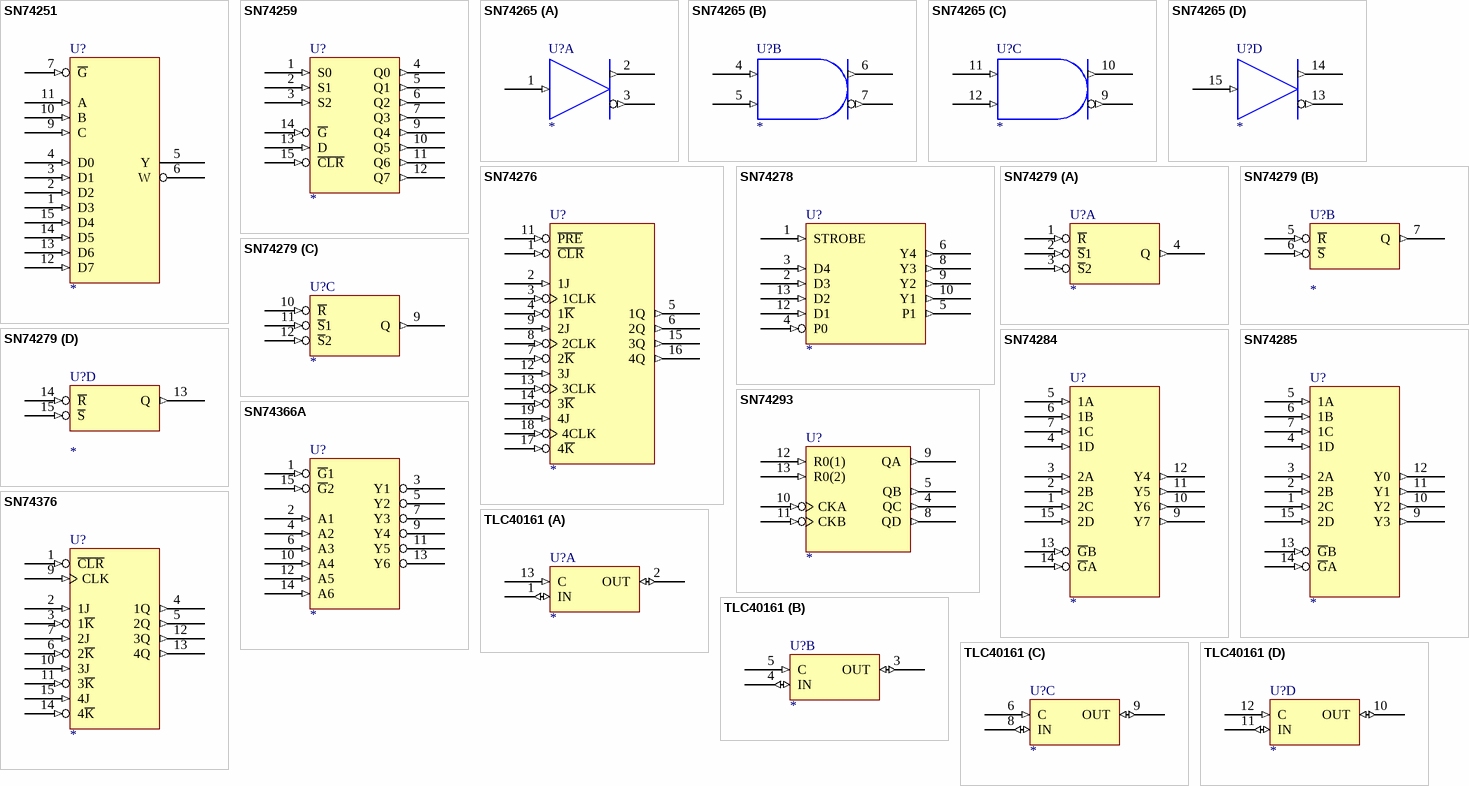
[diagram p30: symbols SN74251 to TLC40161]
## SN74251
designator U?
DATA SLCR/MUX 3SO
footprint DIP-16
footprint SO16
pins: 1 D3 (in), 2 D2 (in), 3 D1 (in), 4 D0 (in), 5 Y (hiz), 6 W (hiz), 7 ~{G} (in), 8 GND (power) hidden to GND, 9 C (in), 10 B (in), 11 A (in), 12 D7 (in), 13 D6 (in), 14 D5 (in), 15 D4 (in), 16 VCC (power) hidden to VCC
1 alternate drawing of the same symbol

## SN74259
designator U?
8-BIT ADDRESSABLE LCH
footprint DIP-16
footprint SO16
pins: 1 S0 (in), 2 S1 (in), 3 S2 (in), 4 Q0 (out), 5 Q1 (out), 6 Q2 (out), 7 Q3 (out), 8 GND (power) hidden to GND, 9 Q4 (out), 10 Q5 (out), 11 Q6 (out), 12 Q7 (out), 13 D (in), 14 ~{G} (in), 15 ~{CLR} (in), 16 VCC (power) hidden to VCC
1 alternate drawing of the same symbol

## SN74265
designator U?
QUAD COMPLEMENTARY-OUTPUT ELEMENTS
footprint DIP-16
part A pins: 1 (in), 2 (out), 3 (out), 8 GND (power) hidden to GND, 16 VCC (power) hidden to VCC
part B pins: 4 (in), 5 (in), 6 (out), 7 (out), 8 GND (power) hidden to GND, 16 VCC (power) hidden to VCC
part C pins: 8 GND (power) hidden to GND, 9 (out), 10 (out), 11 (in), 12 (in), 16 VCC (power) hidden to VCC
part D pins: 8 GND (power) hidden to GND, 13 (out), 14 (out), 15 (in), 16 VCC (power) hidden to VCC
2 alternate drawings of the same symbol

## SN74276
designator U?
QUAD JK FF
footprint DIP-20
pins: 1 ~{CLR} (in), 2 1J (in), 3 1CLK (in), 4 1~{K} (in), 5 1Q (out), 6 2Q (out), 7 2~{K} (in), 8 2CLK (in), 9 2J (in), 10 GND (power) hidden to GND, 11 ~{PRE} (in), 12 3J (in), 13 3CLK (in), 14 3~{K} (in), 15 3Q (out), 16 4Q (out), 17 4~{K} (in), 18 4CLK (in), 19 4J (in), 20 VCC (power) hidden to VCC
1 alternate drawing of the same symbol

## SN74278
designator U?
f4-BIT CASCADED PRIORITY REG
footprint DIP-14
pins: 1 STROBE (in), 2 D3 (in), 3 D4 (in), 4 P0 (in), 5 P1 (out), 6 Y4 (out), 7 GND (power) hidden to GND, 8 Y3 (out), 9 Y2 (out), 10 Y1 (out), 12 D1 (in), 13 D2 (in), 14 VCC (power) hidden to VCC
1 alternate drawing of the same symbol

## SN74279
designator U?
QUAD S\-R\ LCH
footprint DIP-16
footprint SO16
part A pins: 1 ~{R} (in), 2 ~{S}1 (in), 3 ~{S}2 (in), 4 Q (out), 8 GND (power) hidden to GND, 16 VCC (power) hidden to VCC
part B pins: 5 ~{R} (in), 6 ~{S} (in), 7 Q (out), 8 GND (power) hidden to GND, 16 VCC (power) hidden to VCC
part C pins: 8 GND (power) hidden to GND, 9 Q (out), 10 ~{R} (in), 11 ~{S}1 (in), 12 ~{S}2 (in), 16 VCC (power) hidden to VCC
part D pins: 8 GND (power) hidden to GND, 13 Q (out), 14 ~{R} (in), 15 ~{S} (in), 16 VCC (power) hidden to VCC
1 alternate drawing of the same symbol

## SN74284
designator U?
4-BIT BY 4-BIT PARALLEL BIN MULT
footprint DIP-16
pins: 1 2C (in), 2 2B (in), 3 2A (in), 4 1D (in), 5 1A (in), 6 1B (in), 7 1C (in), 8 GND (power) hidden to GND, 9 Y7 (out), 10 Y6 (out), 11 Y5 (out), 12 Y4 (out), 13 ~{G}B (in), 14 ~{G}A (in), 15 2D (in), 16 VCC (power) hidden to VCC
1 alternate drawing of the same symbol

## SN74285
designator U?
4-BIT BY 4-BIT PARALLEL BIN MULT
footprint DIP-16
pins: 1 2C (in), 2 2B (in), 3 2A (in), 4 1D (in), 5 1A (in), 6 1B (in), 7 1C (in), 8 GND (power) hidden to GND, 9 Y3 (out), 10 Y2 (out), 11 Y1 (out), 12 Y0 (out), 13 ~{G}B (in), 14 ~{G}A (in), 15 2D (in), 16 VCC (power) hidden to VCC
1 alternate drawing of the same symbol

## SN74293
designator U?
DECADE AND 4-BIT BIN CNT
footprint DIP-14
footprint SO14
pins: 4 QC (out), 5 QB (out), 7 GND (power) hidden to GND, 8 QD (out), 9 QA (out), 10 CKA (in), 11 CKB (in), 12 R0(1) (in), 13 R0(2) (in), 14 VCC (power) hidden to VCC
1 alternate drawing of the same symbol

## SN74366A
designator U?
HEX BUS DRV 3SO
footprint DIP-16
footprint SO16
pins: 1 ~{G}1 (in), 2 A1 (in), 3 Y1 (hiz), 4 A2 (in), 5 Y2 (hiz), 6 A3 (in), 7 Y3 (hiz), 8 GND (power) hidden to GND, 9 Y4 (hiz), 10 A4 (in), 11 Y5 (hiz), 12 A5 (in), 13 Y6 (hiz), 14 A6 (in), 15 ~{G}2 (in), 16 VCC (power) hidden to VCC
1 alternate drawing of the same symbol

## SN74376
designator U?
QUAD J-K\ FF
footprint DIP-16
pins: 1 ~{CLR} (in), 2 1J (in), 3 1~{K} (in), 4 1Q (out), 5 2Q (out), 6 2~{K} (in), 7 2J (in), 8 GND (power) hidden to GND, 9 CLK (in), 10 3J (in), 11 3~{K} (in), 12 3Q (out), 13 4Q (out), 14 4~{K} (in), 15 4J (in), 16 VCC (power) hidden to VCC
1 alternate drawing of the same symbol

## TLC40161
designator U?
QUAD ANALOG SWITCH MULTIPLEXER
footprint SO14
footprint DIP-14
part A pins: 1 IN (io), 2 OUT (io), 7 GND (power) hidden to GND, 13 C (in), 14 VCC (power) hidden to VCC
part B pins: 3 OUT (io), 4 IN (io), 5 C (in), 7 GND (power) hidden to GND, 14 VCC (power) hidden to VCC
part C pins: 6 C (in), 7 GND (power) hidden to GND, 8 IN (io), 9 OUT (io), 14 VCC (power) hidden to VCC
part D pins: 7 GND (power) hidden to GND, 10 OUT (io), 11 IN (io), 12 C (in), 14 VCC (power) hidden to VCC
1 alternate drawing of the same symbol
